VERSION 5.8 ;
BUSBITCHARS "[]" ;
DIVIDERCHAR "/" ;
UNITS
    DATABASE MICRONS 1000 ;
END UNITS

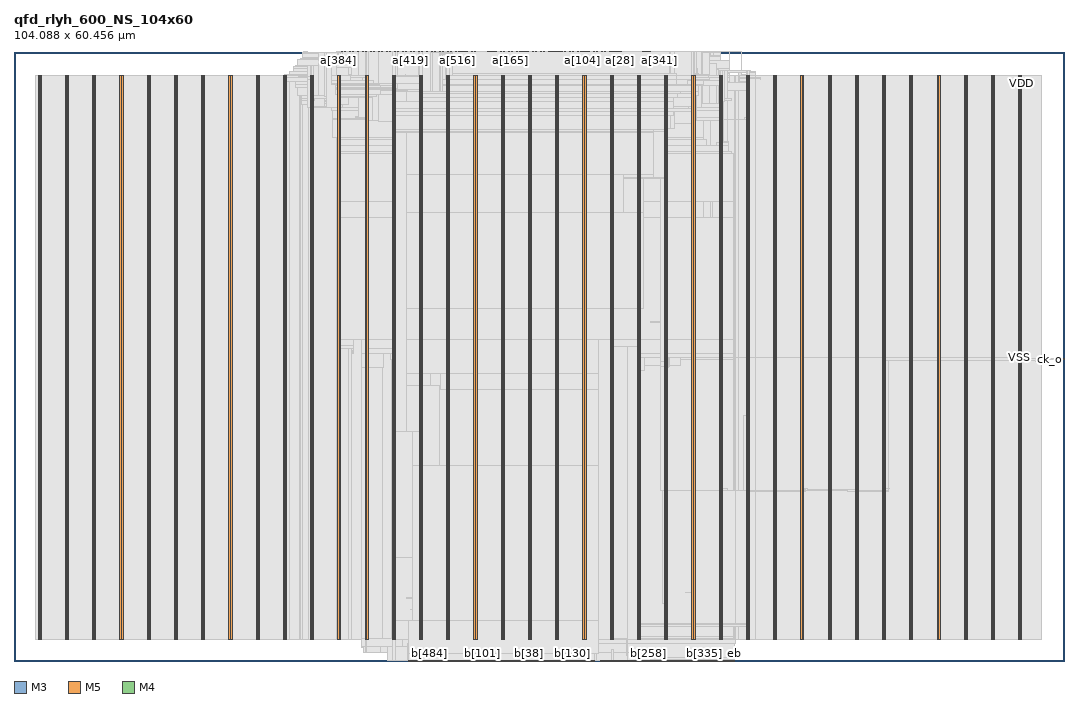
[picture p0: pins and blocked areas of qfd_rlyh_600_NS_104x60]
MACRO qfd_rlyh_600_NS_104x60
  FOREIGN qfd_rlyh_600_NS_104x60 0 0 ;
  CLASS BLOCK ;
  SIZE 104.088 BY 60.456 ;
  PIN a[0]
    DIRECTION INPUT ;
    USE SIGNAL ;
    PORT
      LAYER M3 ;
        RECT  58.068 60.419 58.086 60.456 ;
    END
  END a[0]
  PIN a[100]
    DIRECTION INPUT ;
    USE SIGNAL ;
    PORT
      LAYER M3 ;
        RECT  56.052 60.419 56.07 60.456 ;
    END
  END a[100]
  PIN a[101]
    DIRECTION INPUT ;
    USE SIGNAL ;
    PORT
      LAYER M3 ;
        RECT  56.124 60.419 56.142 60.456 ;
    END
  END a[101]
  PIN a[102]
    DIRECTION INPUT ;
    USE SIGNAL ;
    PORT
      LAYER M3 ;
        RECT  56.196 60.419 56.214 60.456 ;
    END
  END a[102]
  PIN a[103]
    DIRECTION INPUT ;
    USE SIGNAL ;
    PORT
      LAYER M3 ;
        RECT  56.268 60.419 56.286 60.456 ;
    END
  END a[103]
  PIN a[104]
    DIRECTION INPUT ;
    USE SIGNAL ;
    PORT
      LAYER M3 ;
        RECT  56.34 60.419 56.358 60.456 ;
    END
  END a[104]
  PIN a[105]
    DIRECTION INPUT ;
    USE SIGNAL ;
    PORT
      LAYER M3 ;
        RECT  56.412 60.419 56.43 60.456 ;
    END
  END a[105]
  PIN a[106]
    DIRECTION INPUT ;
    USE SIGNAL ;
    PORT
      LAYER M3 ;
        RECT  56.484 60.419 56.502 60.456 ;
    END
  END a[106]
  PIN a[107]
    DIRECTION INPUT ;
    USE SIGNAL ;
    PORT
      LAYER M3 ;
        RECT  56.556 60.419 56.574 60.456 ;
    END
  END a[107]
  PIN a[108]
    DIRECTION INPUT ;
    USE SIGNAL ;
    PORT
      LAYER M3 ;
        RECT  56.628 60.419 56.646 60.456 ;
    END
  END a[108]
  PIN a[109]
    DIRECTION INPUT ;
    USE SIGNAL ;
    PORT
      LAYER M3 ;
        RECT  56.7 60.419 56.718 60.456 ;
    END
  END a[109]
  PIN a[10]
    DIRECTION INPUT ;
    USE SIGNAL ;
    PORT
      LAYER M3 ;
        RECT  58.788 60.419 58.806 60.456 ;
    END
  END a[10]
  PIN a[110]
    DIRECTION INPUT ;
    USE SIGNAL ;
    PORT
      LAYER M3 ;
        RECT  56.772 60.419 56.79 60.456 ;
    END
  END a[110]
  PIN a[111]
    DIRECTION INPUT ;
    USE SIGNAL ;
    PORT
      LAYER M3 ;
        RECT  56.844 60.419 56.862 60.456 ;
    END
  END a[111]
  PIN a[112]
    DIRECTION INPUT ;
    USE SIGNAL ;
    PORT
      LAYER M3 ;
        RECT  56.916 60.419 56.934 60.456 ;
    END
  END a[112]
  PIN a[113]
    DIRECTION INPUT ;
    USE SIGNAL ;
    PORT
      LAYER M3 ;
        RECT  56.988 60.419 57.006 60.456 ;
    END
  END a[113]
  PIN a[114]
    DIRECTION INPUT ;
    USE SIGNAL ;
    PORT
      LAYER M3 ;
        RECT  57.06 60.419 57.078 60.456 ;
    END
  END a[114]
  PIN a[115]
    DIRECTION INPUT ;
    USE SIGNAL ;
    PORT
      LAYER M3 ;
        RECT  57.132 60.419 57.15 60.456 ;
    END
  END a[115]
  PIN a[116]
    DIRECTION INPUT ;
    USE SIGNAL ;
    PORT
      LAYER M3 ;
        RECT  57.204 60.419 57.222 60.456 ;
    END
  END a[116]
  PIN a[117]
    DIRECTION INPUT ;
    USE SIGNAL ;
    PORT
      LAYER M3 ;
        RECT  57.276 60.419 57.294 60.456 ;
    END
  END a[117]
  PIN a[118]
    DIRECTION INPUT ;
    USE SIGNAL ;
    PORT
      LAYER M3 ;
        RECT  57.348 60.419 57.366 60.456 ;
    END
  END a[118]
  PIN a[119]
    DIRECTION INPUT ;
    USE SIGNAL ;
    PORT
      LAYER M3 ;
        RECT  57.42 60.419 57.438 60.456 ;
    END
  END a[119]
  PIN a[11]
    DIRECTION INPUT ;
    USE SIGNAL ;
    PORT
      LAYER M3 ;
        RECT  58.86 60.419 58.878 60.456 ;
    END
  END a[11]
  PIN a[120]
    DIRECTION INPUT ;
    USE SIGNAL ;
    PORT
      LAYER M3 ;
        RECT  57.492 60.419 57.51 60.456 ;
    END
  END a[120]
  PIN a[121]
    DIRECTION INPUT ;
    USE SIGNAL ;
    PORT
      LAYER M3 ;
        RECT  57.564 60.419 57.582 60.456 ;
    END
  END a[121]
  PIN a[122]
    DIRECTION INPUT ;
    USE SIGNAL ;
    PORT
      LAYER M3 ;
        RECT  57.636 60.419 57.654 60.456 ;
    END
  END a[122]
  PIN a[123]
    DIRECTION INPUT ;
    USE SIGNAL ;
    PORT
      LAYER M3 ;
        RECT  57.708 60.419 57.726 60.456 ;
    END
  END a[123]
  PIN a[124]
    DIRECTION INPUT ;
    USE SIGNAL ;
    PORT
      LAYER M3 ;
        RECT  57.78 60.419 57.798 60.456 ;
    END
  END a[124]
  PIN a[125]
    DIRECTION INPUT ;
    USE SIGNAL ;
    PORT
      LAYER M3 ;
        RECT  57.852 60.419 57.87 60.456 ;
    END
  END a[125]
  PIN a[126]
    DIRECTION INPUT ;
    USE SIGNAL ;
    PORT
      LAYER M3 ;
        RECT  57.924 60.419 57.942 60.456 ;
    END
  END a[126]
  PIN a[127]
    DIRECTION INPUT ;
    USE SIGNAL ;
    PORT
      LAYER M3 ;
        RECT  57.996 60.419 58.014 60.456 ;
    END
  END a[127]
  PIN a[128]
    DIRECTION INPUT ;
    USE SIGNAL ;
    PORT
      LAYER M5 ;
        RECT  49.68 60.372 49.704 60.456 ;
    END
  END a[128]
  PIN a[129]
    DIRECTION INPUT ;
    USE SIGNAL ;
    PORT
      LAYER M5 ;
        RECT  49.776 60.372 49.8 60.456 ;
    END
  END a[129]
  PIN a[12]
    DIRECTION INPUT ;
    USE SIGNAL ;
    PORT
      LAYER M3 ;
        RECT  58.932 60.419 58.95 60.456 ;
    END
  END a[12]
  PIN a[130]
    DIRECTION INPUT ;
    USE SIGNAL ;
    PORT
      LAYER M5 ;
        RECT  49.872 60.372 49.896 60.456 ;
    END
  END a[130]
  PIN a[131]
    DIRECTION INPUT ;
    USE SIGNAL ;
    PORT
      LAYER M5 ;
        RECT  49.968 60.372 49.992 60.456 ;
    END
  END a[131]
  PIN a[132]
    DIRECTION INPUT ;
    USE SIGNAL ;
    PORT
      LAYER M5 ;
        RECT  50.064 60.372 50.088 60.456 ;
    END
  END a[132]
  PIN a[133]
    DIRECTION INPUT ;
    USE SIGNAL ;
    PORT
      LAYER M5 ;
        RECT  50.16 60.372 50.184 60.456 ;
    END
  END a[133]
  PIN a[134]
    DIRECTION INPUT ;
    USE SIGNAL ;
    PORT
      LAYER M5 ;
        RECT  50.256 60.372 50.28 60.456 ;
    END
  END a[134]
  PIN a[135]
    DIRECTION INPUT ;
    USE SIGNAL ;
    PORT
      LAYER M5 ;
        RECT  50.352 60.372 50.376 60.456 ;
    END
  END a[135]
  PIN a[136]
    DIRECTION INPUT ;
    USE SIGNAL ;
    PORT
      LAYER M5 ;
        RECT  50.448 60.372 50.472 60.456 ;
    END
  END a[136]
  PIN a[137]
    DIRECTION INPUT ;
    USE SIGNAL ;
    PORT
      LAYER M5 ;
        RECT  50.544 60.372 50.568 60.456 ;
    END
  END a[137]
  PIN a[138]
    DIRECTION INPUT ;
    USE SIGNAL ;
    PORT
      LAYER M5 ;
        RECT  50.64 60.372 50.664 60.456 ;
    END
  END a[138]
  PIN a[139]
    DIRECTION INPUT ;
    USE SIGNAL ;
    PORT
      LAYER M5 ;
        RECT  50.736 60.372 50.76 60.456 ;
    END
  END a[139]
  PIN a[13]
    DIRECTION INPUT ;
    USE SIGNAL ;
    PORT
      LAYER M3 ;
        RECT  59.004 60.419 59.022 60.456 ;
    END
  END a[13]
  PIN a[140]
    DIRECTION INPUT ;
    USE SIGNAL ;
    PORT
      LAYER M5 ;
        RECT  50.832 60.372 50.856 60.456 ;
    END
  END a[140]
  PIN a[141]
    DIRECTION INPUT ;
    USE SIGNAL ;
    PORT
      LAYER M5 ;
        RECT  50.928 60.372 50.952 60.456 ;
    END
  END a[141]
  PIN a[142]
    DIRECTION INPUT ;
    USE SIGNAL ;
    PORT
      LAYER M5 ;
        RECT  51.024 60.372 51.048 60.456 ;
    END
  END a[142]
  PIN a[143]
    DIRECTION INPUT ;
    USE SIGNAL ;
    PORT
      LAYER M5 ;
        RECT  51.12 60.372 51.144 60.456 ;
    END
  END a[143]
  PIN a[144]
    DIRECTION INPUT ;
    USE SIGNAL ;
    PORT
      LAYER M5 ;
        RECT  51.216 60.372 51.24 60.456 ;
    END
  END a[144]
  PIN a[145]
    DIRECTION INPUT ;
    USE SIGNAL ;
    PORT
      LAYER M5 ;
        RECT  51.312 60.372 51.336 60.456 ;
    END
  END a[145]
  PIN a[146]
    DIRECTION INPUT ;
    USE SIGNAL ;
    PORT
      LAYER M5 ;
        RECT  51.408 60.372 51.432 60.456 ;
    END
  END a[146]
  PIN a[147]
    DIRECTION INPUT ;
    USE SIGNAL ;
    PORT
      LAYER M5 ;
        RECT  51.504 60.372 51.528 60.456 ;
    END
  END a[147]
  PIN a[148]
    DIRECTION INPUT ;
    USE SIGNAL ;
    PORT
      LAYER M5 ;
        RECT  51.6 60.372 51.624 60.456 ;
    END
  END a[148]
  PIN a[149]
    DIRECTION INPUT ;
    USE SIGNAL ;
    PORT
      LAYER M5 ;
        RECT  51.696 60.372 51.72 60.456 ;
    END
  END a[149]
  PIN a[14]
    DIRECTION INPUT ;
    USE SIGNAL ;
    PORT
      LAYER M3 ;
        RECT  59.076 60.419 59.094 60.456 ;
    END
  END a[14]
  PIN a[150]
    DIRECTION INPUT ;
    USE SIGNAL ;
    PORT
      LAYER M5 ;
        RECT  51.792 60.372 51.816 60.456 ;
    END
  END a[150]
  PIN a[151]
    DIRECTION INPUT ;
    USE SIGNAL ;
    PORT
      LAYER M5 ;
        RECT  51.888 60.372 51.912 60.456 ;
    END
  END a[151]
  PIN a[152]
    DIRECTION INPUT ;
    USE SIGNAL ;
    PORT
      LAYER M5 ;
        RECT  51.984 60.372 52.008 60.456 ;
    END
  END a[152]
  PIN a[153]
    DIRECTION INPUT ;
    USE SIGNAL ;
    PORT
      LAYER M5 ;
        RECT  52.08 60.372 52.104 60.456 ;
    END
  END a[153]
  PIN a[154]
    DIRECTION INPUT ;
    USE SIGNAL ;
    PORT
      LAYER M5 ;
        RECT  52.176 60.372 52.2 60.456 ;
    END
  END a[154]
  PIN a[155]
    DIRECTION INPUT ;
    USE SIGNAL ;
    PORT
      LAYER M5 ;
        RECT  52.272 60.372 52.296 60.456 ;
    END
  END a[155]
  PIN a[156]
    DIRECTION INPUT ;
    USE SIGNAL ;
    PORT
      LAYER M5 ;
        RECT  52.368 60.372 52.392 60.456 ;
    END
  END a[156]
  PIN a[157]
    DIRECTION INPUT ;
    USE SIGNAL ;
    PORT
      LAYER M5 ;
        RECT  52.464 60.372 52.488 60.456 ;
    END
  END a[157]
  PIN a[158]
    DIRECTION INPUT ;
    USE SIGNAL ;
    PORT
      LAYER M5 ;
        RECT  52.56 60.372 52.584 60.456 ;
    END
  END a[158]
  PIN a[159]
    DIRECTION INPUT ;
    USE SIGNAL ;
    PORT
      LAYER M5 ;
        RECT  52.656 60.372 52.68 60.456 ;
    END
  END a[159]
  PIN a[15]
    DIRECTION INPUT ;
    USE SIGNAL ;
    PORT
      LAYER M3 ;
        RECT  59.148 60.419 59.166 60.456 ;
    END
  END a[15]
  PIN a[160]
    DIRECTION INPUT ;
    USE SIGNAL ;
    PORT
      LAYER M3 ;
        RECT  48.852 60.419 48.87 60.456 ;
    END
  END a[160]
  PIN a[161]
    DIRECTION INPUT ;
    USE SIGNAL ;
    PORT
      LAYER M3 ;
        RECT  48.924 60.419 48.942 60.456 ;
    END
  END a[161]
  PIN a[162]
    DIRECTION INPUT ;
    USE SIGNAL ;
    PORT
      LAYER M3 ;
        RECT  48.996 60.419 49.014 60.456 ;
    END
  END a[162]
  PIN a[163]
    DIRECTION INPUT ;
    USE SIGNAL ;
    PORT
      LAYER M3 ;
        RECT  49.068 60.419 49.086 60.456 ;
    END
  END a[163]
  PIN a[164]
    DIRECTION INPUT ;
    USE SIGNAL ;
    PORT
      LAYER M3 ;
        RECT  49.14 60.419 49.158 60.456 ;
    END
  END a[164]
  PIN a[165]
    DIRECTION INPUT ;
    USE SIGNAL ;
    PORT
      LAYER M3 ;
        RECT  49.212 60.419 49.23 60.456 ;
    END
  END a[165]
  PIN a[166]
    DIRECTION INPUT ;
    USE SIGNAL ;
    PORT
      LAYER M3 ;
        RECT  49.284 60.419 49.302 60.456 ;
    END
  END a[166]
  PIN a[167]
    DIRECTION INPUT ;
    USE SIGNAL ;
    PORT
      LAYER M3 ;
        RECT  49.356 60.419 49.374 60.456 ;
    END
  END a[167]
  PIN a[168]
    DIRECTION INPUT ;
    USE SIGNAL ;
    PORT
      LAYER M3 ;
        RECT  49.428 60.419 49.446 60.456 ;
    END
  END a[168]
  PIN a[169]
    DIRECTION INPUT ;
    USE SIGNAL ;
    PORT
      LAYER M3 ;
        RECT  49.5 60.419 49.518 60.456 ;
    END
  END a[169]
  PIN a[16]
    DIRECTION INPUT ;
    USE SIGNAL ;
    PORT
      LAYER M3 ;
        RECT  59.22 60.419 59.238 60.456 ;
    END
  END a[16]
  PIN a[170]
    DIRECTION INPUT ;
    USE SIGNAL ;
    PORT
      LAYER M3 ;
        RECT  49.572 60.419 49.59 60.456 ;
    END
  END a[170]
  PIN a[171]
    DIRECTION INPUT ;
    USE SIGNAL ;
    PORT
      LAYER M3 ;
        RECT  49.644 60.419 49.662 60.456 ;
    END
  END a[171]
  PIN a[172]
    DIRECTION INPUT ;
    USE SIGNAL ;
    PORT
      LAYER M3 ;
        RECT  49.716 60.419 49.734 60.456 ;
    END
  END a[172]
  PIN a[173]
    DIRECTION INPUT ;
    USE SIGNAL ;
    PORT
      LAYER M3 ;
        RECT  49.788 60.419 49.806 60.456 ;
    END
  END a[173]
  PIN a[174]
    DIRECTION INPUT ;
    USE SIGNAL ;
    PORT
      LAYER M3 ;
        RECT  49.86 60.419 49.878 60.456 ;
    END
  END a[174]
  PIN a[175]
    DIRECTION INPUT ;
    USE SIGNAL ;
    PORT
      LAYER M3 ;
        RECT  49.932 60.419 49.95 60.456 ;
    END
  END a[175]
  PIN a[176]
    DIRECTION INPUT ;
    USE SIGNAL ;
    PORT
      LAYER M3 ;
        RECT  50.004 60.419 50.022 60.456 ;
    END
  END a[176]
  PIN a[177]
    DIRECTION INPUT ;
    USE SIGNAL ;
    PORT
      LAYER M3 ;
        RECT  50.076 60.419 50.094 60.456 ;
    END
  END a[177]
  PIN a[178]
    DIRECTION INPUT ;
    USE SIGNAL ;
    PORT
      LAYER M3 ;
        RECT  50.148 60.419 50.166 60.456 ;
    END
  END a[178]
  PIN a[179]
    DIRECTION INPUT ;
    USE SIGNAL ;
    PORT
      LAYER M3 ;
        RECT  50.22 60.419 50.238 60.456 ;
    END
  END a[179]
  PIN a[17]
    DIRECTION INPUT ;
    USE SIGNAL ;
    PORT
      LAYER M3 ;
        RECT  59.292 60.419 59.31 60.456 ;
    END
  END a[17]
  PIN a[180]
    DIRECTION INPUT ;
    USE SIGNAL ;
    PORT
      LAYER M3 ;
        RECT  50.292 60.419 50.31 60.456 ;
    END
  END a[180]
  PIN a[181]
    DIRECTION INPUT ;
    USE SIGNAL ;
    PORT
      LAYER M3 ;
        RECT  50.364 60.419 50.382 60.456 ;
    END
  END a[181]
  PIN a[182]
    DIRECTION INPUT ;
    USE SIGNAL ;
    PORT
      LAYER M3 ;
        RECT  50.436 60.419 50.454 60.456 ;
    END
  END a[182]
  PIN a[183]
    DIRECTION INPUT ;
    USE SIGNAL ;
    PORT
      LAYER M3 ;
        RECT  50.508 60.419 50.526 60.456 ;
    END
  END a[183]
  PIN a[184]
    DIRECTION INPUT ;
    USE SIGNAL ;
    PORT
      LAYER M3 ;
        RECT  50.58 60.419 50.598 60.456 ;
    END
  END a[184]
  PIN a[185]
    DIRECTION INPUT ;
    USE SIGNAL ;
    PORT
      LAYER M3 ;
        RECT  50.652 60.419 50.67 60.456 ;
    END
  END a[185]
  PIN a[186]
    DIRECTION INPUT ;
    USE SIGNAL ;
    PORT
      LAYER M3 ;
        RECT  50.724 60.419 50.742 60.456 ;
    END
  END a[186]
  PIN a[187]
    DIRECTION INPUT ;
    USE SIGNAL ;
    PORT
      LAYER M3 ;
        RECT  50.796 60.419 50.814 60.456 ;
    END
  END a[187]
  PIN a[188]
    DIRECTION INPUT ;
    USE SIGNAL ;
    PORT
      LAYER M3 ;
        RECT  50.868 60.419 50.886 60.456 ;
    END
  END a[188]
  PIN a[189]
    DIRECTION INPUT ;
    USE SIGNAL ;
    PORT
      LAYER M3 ;
        RECT  50.94 60.419 50.958 60.456 ;
    END
  END a[189]
  PIN a[18]
    DIRECTION INPUT ;
    USE SIGNAL ;
    PORT
      LAYER M3 ;
        RECT  59.364 60.419 59.382 60.456 ;
    END
  END a[18]
  PIN a[190]
    DIRECTION INPUT ;
    USE SIGNAL ;
    PORT
      LAYER M3 ;
        RECT  51.012 60.419 51.03 60.456 ;
    END
  END a[190]
  PIN a[191]
    DIRECTION INPUT ;
    USE SIGNAL ;
    PORT
      LAYER M3 ;
        RECT  51.084 60.419 51.102 60.456 ;
    END
  END a[191]
  PIN a[192]
    DIRECTION INPUT ;
    USE SIGNAL ;
    PORT
      LAYER M3 ;
        RECT  53.46 60.419 53.478 60.456 ;
    END
  END a[192]
  PIN a[193]
    DIRECTION INPUT ;
    USE SIGNAL ;
    PORT
      LAYER M3 ;
        RECT  53.532 60.419 53.55 60.456 ;
    END
  END a[193]
  PIN a[194]
    DIRECTION INPUT ;
    USE SIGNAL ;
    PORT
      LAYER M3 ;
        RECT  53.604 60.419 53.622 60.456 ;
    END
  END a[194]
  PIN a[195]
    DIRECTION INPUT ;
    USE SIGNAL ;
    PORT
      LAYER M3 ;
        RECT  53.676 60.419 53.694 60.456 ;
    END
  END a[195]
  PIN a[196]
    DIRECTION INPUT ;
    USE SIGNAL ;
    PORT
      LAYER M3 ;
        RECT  53.748 60.419 53.766 60.456 ;
    END
  END a[196]
  PIN a[197]
    DIRECTION INPUT ;
    USE SIGNAL ;
    PORT
      LAYER M3 ;
        RECT  53.82 60.419 53.838 60.456 ;
    END
  END a[197]
  PIN a[198]
    DIRECTION INPUT ;
    USE SIGNAL ;
    PORT
      LAYER M3 ;
        RECT  53.892 60.419 53.91 60.456 ;
    END
  END a[198]
  PIN a[199]
    DIRECTION INPUT ;
    USE SIGNAL ;
    PORT
      LAYER M3 ;
        RECT  53.964 60.419 53.982 60.456 ;
    END
  END a[199]
  PIN a[19]
    DIRECTION INPUT ;
    USE SIGNAL ;
    PORT
      LAYER M3 ;
        RECT  59.436 60.419 59.454 60.456 ;
    END
  END a[19]
  PIN a[1]
    DIRECTION INPUT ;
    USE SIGNAL ;
    PORT
      LAYER M3 ;
        RECT  58.14 60.419 58.158 60.456 ;
    END
  END a[1]
  PIN a[200]
    DIRECTION INPUT ;
    USE SIGNAL ;
    PORT
      LAYER M3 ;
        RECT  54.036 60.419 54.054 60.456 ;
    END
  END a[200]
  PIN a[201]
    DIRECTION INPUT ;
    USE SIGNAL ;
    PORT
      LAYER M3 ;
        RECT  54.108 60.419 54.126 60.456 ;
    END
  END a[201]
  PIN a[202]
    DIRECTION INPUT ;
    USE SIGNAL ;
    PORT
      LAYER M3 ;
        RECT  54.18 60.419 54.198 60.456 ;
    END
  END a[202]
  PIN a[203]
    DIRECTION INPUT ;
    USE SIGNAL ;
    PORT
      LAYER M3 ;
        RECT  54.252 60.419 54.27 60.456 ;
    END
  END a[203]
  PIN a[204]
    DIRECTION INPUT ;
    USE SIGNAL ;
    PORT
      LAYER M3 ;
        RECT  54.324 60.419 54.342 60.456 ;
    END
  END a[204]
  PIN a[205]
    DIRECTION INPUT ;
    USE SIGNAL ;
    PORT
      LAYER M3 ;
        RECT  54.396 60.419 54.414 60.456 ;
    END
  END a[205]
  PIN a[206]
    DIRECTION INPUT ;
    USE SIGNAL ;
    PORT
      LAYER M3 ;
        RECT  54.468 60.419 54.486 60.456 ;
    END
  END a[206]
  PIN a[207]
    DIRECTION INPUT ;
    USE SIGNAL ;
    PORT
      LAYER M3 ;
        RECT  54.54 60.419 54.558 60.456 ;
    END
  END a[207]
  PIN a[208]
    DIRECTION INPUT ;
    USE SIGNAL ;
    PORT
      LAYER M3 ;
        RECT  54.612 60.419 54.63 60.456 ;
    END
  END a[208]
  PIN a[209]
    DIRECTION INPUT ;
    USE SIGNAL ;
    PORT
      LAYER M3 ;
        RECT  54.684 60.419 54.702 60.456 ;
    END
  END a[209]
  PIN a[20]
    DIRECTION INPUT ;
    USE SIGNAL ;
    PORT
      LAYER M3 ;
        RECT  59.508 60.419 59.526 60.456 ;
    END
  END a[20]
  PIN a[210]
    DIRECTION INPUT ;
    USE SIGNAL ;
    PORT
      LAYER M3 ;
        RECT  54.756 60.419 54.774 60.456 ;
    END
  END a[210]
  PIN a[211]
    DIRECTION INPUT ;
    USE SIGNAL ;
    PORT
      LAYER M3 ;
        RECT  54.828 60.419 54.846 60.456 ;
    END
  END a[211]
  PIN a[212]
    DIRECTION INPUT ;
    USE SIGNAL ;
    PORT
      LAYER M3 ;
        RECT  54.9 60.419 54.918 60.456 ;
    END
  END a[212]
  PIN a[213]
    DIRECTION INPUT ;
    USE SIGNAL ;
    PORT
      LAYER M3 ;
        RECT  54.972 60.419 54.99 60.456 ;
    END
  END a[213]
  PIN a[214]
    DIRECTION INPUT ;
    USE SIGNAL ;
    PORT
      LAYER M3 ;
        RECT  55.044 60.419 55.062 60.456 ;
    END
  END a[214]
  PIN a[215]
    DIRECTION INPUT ;
    USE SIGNAL ;
    PORT
      LAYER M3 ;
        RECT  55.116 60.419 55.134 60.456 ;
    END
  END a[215]
  PIN a[216]
    DIRECTION INPUT ;
    USE SIGNAL ;
    PORT
      LAYER M3 ;
        RECT  55.188 60.419 55.206 60.456 ;
    END
  END a[216]
  PIN a[217]
    DIRECTION INPUT ;
    USE SIGNAL ;
    PORT
      LAYER M3 ;
        RECT  55.26 60.419 55.278 60.456 ;
    END
  END a[217]
  PIN a[218]
    DIRECTION INPUT ;
    USE SIGNAL ;
    PORT
      LAYER M3 ;
        RECT  55.332 60.419 55.35 60.456 ;
    END
  END a[218]
  PIN a[219]
    DIRECTION INPUT ;
    USE SIGNAL ;
    PORT
      LAYER M3 ;
        RECT  55.404 60.419 55.422 60.456 ;
    END
  END a[219]
  PIN a[21]
    DIRECTION INPUT ;
    USE SIGNAL ;
    PORT
      LAYER M3 ;
        RECT  59.58 60.419 59.598 60.456 ;
    END
  END a[21]
  PIN a[220]
    DIRECTION INPUT ;
    USE SIGNAL ;
    PORT
      LAYER M3 ;
        RECT  55.476 60.419 55.494 60.456 ;
    END
  END a[220]
  PIN a[221]
    DIRECTION INPUT ;
    USE SIGNAL ;
    PORT
      LAYER M3 ;
        RECT  55.548 60.419 55.566 60.456 ;
    END
  END a[221]
  PIN a[222]
    DIRECTION INPUT ;
    USE SIGNAL ;
    PORT
      LAYER M3 ;
        RECT  55.62 60.419 55.638 60.456 ;
    END
  END a[222]
  PIN a[223]
    DIRECTION INPUT ;
    USE SIGNAL ;
    PORT
      LAYER M3 ;
        RECT  55.692 60.419 55.71 60.456 ;
    END
  END a[223]
  PIN a[224]
    DIRECTION INPUT ;
    USE SIGNAL ;
    PORT
      LAYER M3 ;
        RECT  51.156 60.419 51.174 60.456 ;
    END
  END a[224]
  PIN a[225]
    DIRECTION INPUT ;
    USE SIGNAL ;
    PORT
      LAYER M3 ;
        RECT  51.228 60.419 51.246 60.456 ;
    END
  END a[225]
  PIN a[226]
    DIRECTION INPUT ;
    USE SIGNAL ;
    PORT
      LAYER M3 ;
        RECT  51.3 60.419 51.318 60.456 ;
    END
  END a[226]
  PIN a[227]
    DIRECTION INPUT ;
    USE SIGNAL ;
    PORT
      LAYER M3 ;
        RECT  51.372 60.419 51.39 60.456 ;
    END
  END a[227]
  PIN a[228]
    DIRECTION INPUT ;
    USE SIGNAL ;
    PORT
      LAYER M3 ;
        RECT  51.444 60.419 51.462 60.456 ;
    END
  END a[228]
  PIN a[229]
    DIRECTION INPUT ;
    USE SIGNAL ;
    PORT
      LAYER M3 ;
        RECT  51.516 60.419 51.534 60.456 ;
    END
  END a[229]
  PIN a[22]
    DIRECTION INPUT ;
    USE SIGNAL ;
    PORT
      LAYER M3 ;
        RECT  59.652 60.419 59.67 60.456 ;
    END
  END a[22]
  PIN a[230]
    DIRECTION INPUT ;
    USE SIGNAL ;
    PORT
      LAYER M3 ;
        RECT  51.588 60.419 51.606 60.456 ;
    END
  END a[230]
  PIN a[231]
    DIRECTION INPUT ;
    USE SIGNAL ;
    PORT
      LAYER M3 ;
        RECT  51.66 60.419 51.678 60.456 ;
    END
  END a[231]
  PIN a[232]
    DIRECTION INPUT ;
    USE SIGNAL ;
    PORT
      LAYER M3 ;
        RECT  51.732 60.419 51.75 60.456 ;
    END
  END a[232]
  PIN a[233]
    DIRECTION INPUT ;
    USE SIGNAL ;
    PORT
      LAYER M3 ;
        RECT  51.804 60.419 51.822 60.456 ;
    END
  END a[233]
  PIN a[234]
    DIRECTION INPUT ;
    USE SIGNAL ;
    PORT
      LAYER M3 ;
        RECT  51.876 60.419 51.894 60.456 ;
    END
  END a[234]
  PIN a[235]
    DIRECTION INPUT ;
    USE SIGNAL ;
    PORT
      LAYER M3 ;
        RECT  51.948 60.419 51.966 60.456 ;
    END
  END a[235]
  PIN a[236]
    DIRECTION INPUT ;
    USE SIGNAL ;
    PORT
      LAYER M3 ;
        RECT  52.02 60.419 52.038 60.456 ;
    END
  END a[236]
  PIN a[237]
    DIRECTION INPUT ;
    USE SIGNAL ;
    PORT
      LAYER M3 ;
        RECT  52.092 60.419 52.11 60.456 ;
    END
  END a[237]
  PIN a[238]
    DIRECTION INPUT ;
    USE SIGNAL ;
    PORT
      LAYER M3 ;
        RECT  52.164 60.419 52.182 60.456 ;
    END
  END a[238]
  PIN a[239]
    DIRECTION INPUT ;
    USE SIGNAL ;
    PORT
      LAYER M3 ;
        RECT  52.236 60.419 52.254 60.456 ;
    END
  END a[239]
  PIN a[23]
    DIRECTION INPUT ;
    USE SIGNAL ;
    PORT
      LAYER M3 ;
        RECT  59.724 60.419 59.742 60.456 ;
    END
  END a[23]
  PIN a[240]
    DIRECTION INPUT ;
    USE SIGNAL ;
    PORT
      LAYER M3 ;
        RECT  52.308 60.419 52.326 60.456 ;
    END
  END a[240]
  PIN a[241]
    DIRECTION INPUT ;
    USE SIGNAL ;
    PORT
      LAYER M3 ;
        RECT  52.38 60.419 52.398 60.456 ;
    END
  END a[241]
  PIN a[242]
    DIRECTION INPUT ;
    USE SIGNAL ;
    PORT
      LAYER M3 ;
        RECT  52.452 60.419 52.47 60.456 ;
    END
  END a[242]
  PIN a[243]
    DIRECTION INPUT ;
    USE SIGNAL ;
    PORT
      LAYER M3 ;
        RECT  52.524 60.419 52.542 60.456 ;
    END
  END a[243]
  PIN a[244]
    DIRECTION INPUT ;
    USE SIGNAL ;
    PORT
      LAYER M3 ;
        RECT  52.596 60.419 52.614 60.456 ;
    END
  END a[244]
  PIN a[245]
    DIRECTION INPUT ;
    USE SIGNAL ;
    PORT
      LAYER M3 ;
        RECT  52.668 60.419 52.686 60.456 ;
    END
  END a[245]
  PIN a[246]
    DIRECTION INPUT ;
    USE SIGNAL ;
    PORT
      LAYER M3 ;
        RECT  52.74 60.419 52.758 60.456 ;
    END
  END a[246]
  PIN a[247]
    DIRECTION INPUT ;
    USE SIGNAL ;
    PORT
      LAYER M3 ;
        RECT  52.812 60.419 52.83 60.456 ;
    END
  END a[247]
  PIN a[248]
    DIRECTION INPUT ;
    USE SIGNAL ;
    PORT
      LAYER M3 ;
        RECT  52.884 60.419 52.902 60.456 ;
    END
  END a[248]
  PIN a[249]
    DIRECTION INPUT ;
    USE SIGNAL ;
    PORT
      LAYER M3 ;
        RECT  52.956 60.419 52.974 60.456 ;
    END
  END a[249]
  PIN a[24]
    DIRECTION INPUT ;
    USE SIGNAL ;
    PORT
      LAYER M3 ;
        RECT  59.796 60.419 59.814 60.456 ;
    END
  END a[24]
  PIN a[250]
    DIRECTION INPUT ;
    USE SIGNAL ;
    PORT
      LAYER M3 ;
        RECT  53.028 60.419 53.046 60.456 ;
    END
  END a[250]
  PIN a[251]
    DIRECTION INPUT ;
    USE SIGNAL ;
    PORT
      LAYER M3 ;
        RECT  53.1 60.419 53.118 60.456 ;
    END
  END a[251]
  PIN a[252]
    DIRECTION INPUT ;
    USE SIGNAL ;
    PORT
      LAYER M3 ;
        RECT  53.172 60.419 53.19 60.456 ;
    END
  END a[252]
  PIN a[253]
    DIRECTION INPUT ;
    USE SIGNAL ;
    PORT
      LAYER M3 ;
        RECT  53.244 60.419 53.262 60.456 ;
    END
  END a[253]
  PIN a[254]
    DIRECTION INPUT ;
    USE SIGNAL ;
    PORT
      LAYER M3 ;
        RECT  53.316 60.419 53.334 60.456 ;
    END
  END a[254]
  PIN a[255]
    DIRECTION INPUT ;
    USE SIGNAL ;
    PORT
      LAYER M3 ;
        RECT  53.388 60.419 53.406 60.456 ;
    END
  END a[255]
  PIN a[256]
    DIRECTION INPUT ;
    USE SIGNAL ;
    PORT
      LAYER M5 ;
        RECT  58.896 60.372 58.92 60.456 ;
    END
  END a[256]
  PIN a[257]
    DIRECTION INPUT ;
    USE SIGNAL ;
    PORT
      LAYER M5 ;
        RECT  58.992 60.372 59.016 60.456 ;
    END
  END a[257]
  PIN a[258]
    DIRECTION INPUT ;
    USE SIGNAL ;
    PORT
      LAYER M5 ;
        RECT  59.088 60.372 59.112 60.456 ;
    END
  END a[258]
  PIN a[259]
    DIRECTION INPUT ;
    USE SIGNAL ;
    PORT
      LAYER M5 ;
        RECT  59.184 60.372 59.208 60.456 ;
    END
  END a[259]
  PIN a[25]
    DIRECTION INPUT ;
    USE SIGNAL ;
    PORT
      LAYER M3 ;
        RECT  59.868 60.419 59.886 60.456 ;
    END
  END a[25]
  PIN a[260]
    DIRECTION INPUT ;
    USE SIGNAL ;
    PORT
      LAYER M5 ;
        RECT  59.28 60.372 59.304 60.456 ;
    END
  END a[260]
  PIN a[261]
    DIRECTION INPUT ;
    USE SIGNAL ;
    PORT
      LAYER M5 ;
        RECT  59.376 60.372 59.4 60.456 ;
    END
  END a[261]
  PIN a[262]
    DIRECTION INPUT ;
    USE SIGNAL ;
    PORT
      LAYER M5 ;
        RECT  59.472 60.372 59.496 60.456 ;
    END
  END a[262]
  PIN a[263]
    DIRECTION INPUT ;
    USE SIGNAL ;
    PORT
      LAYER M5 ;
        RECT  59.568 60.372 59.592 60.456 ;
    END
  END a[263]
  PIN a[264]
    DIRECTION INPUT ;
    USE SIGNAL ;
    PORT
      LAYER M5 ;
        RECT  59.664 60.372 59.688 60.456 ;
    END
  END a[264]
  PIN a[265]
    DIRECTION INPUT ;
    USE SIGNAL ;
    PORT
      LAYER M5 ;
        RECT  59.76 60.372 59.784 60.456 ;
    END
  END a[265]
  PIN a[266]
    DIRECTION INPUT ;
    USE SIGNAL ;
    PORT
      LAYER M5 ;
        RECT  59.856 60.372 59.88 60.456 ;
    END
  END a[266]
  PIN a[267]
    DIRECTION INPUT ;
    USE SIGNAL ;
    PORT
      LAYER M5 ;
        RECT  59.952 60.372 59.976 60.456 ;
    END
  END a[267]
  PIN a[268]
    DIRECTION INPUT ;
    USE SIGNAL ;
    PORT
      LAYER M5 ;
        RECT  60.048 60.372 60.072 60.456 ;
    END
  END a[268]
  PIN a[269]
    DIRECTION INPUT ;
    USE SIGNAL ;
    PORT
      LAYER M5 ;
        RECT  60.144 60.372 60.168 60.456 ;
    END
  END a[269]
  PIN a[26]
    DIRECTION INPUT ;
    USE SIGNAL ;
    PORT
      LAYER M3 ;
        RECT  59.94 60.419 59.958 60.456 ;
    END
  END a[26]
  PIN a[270]
    DIRECTION INPUT ;
    USE SIGNAL ;
    PORT
      LAYER M5 ;
        RECT  60.24 60.372 60.264 60.456 ;
    END
  END a[270]
  PIN a[271]
    DIRECTION INPUT ;
    USE SIGNAL ;
    PORT
      LAYER M5 ;
        RECT  60.336 60.372 60.36 60.456 ;
    END
  END a[271]
  PIN a[272]
    DIRECTION INPUT ;
    USE SIGNAL ;
    PORT
      LAYER M5 ;
        RECT  60.432 60.372 60.456 60.456 ;
    END
  END a[272]
  PIN a[273]
    DIRECTION INPUT ;
    USE SIGNAL ;
    PORT
      LAYER M5 ;
        RECT  60.528 60.372 60.552 60.456 ;
    END
  END a[273]
  PIN a[274]
    DIRECTION INPUT ;
    USE SIGNAL ;
    PORT
      LAYER M5 ;
        RECT  60.624 60.372 60.648 60.456 ;
    END
  END a[274]
  PIN a[275]
    DIRECTION INPUT ;
    USE SIGNAL ;
    PORT
      LAYER M5 ;
        RECT  60.72 60.372 60.744 60.456 ;
    END
  END a[275]
  PIN a[276]
    DIRECTION INPUT ;
    USE SIGNAL ;
    PORT
      LAYER M5 ;
        RECT  60.816 60.372 60.84 60.456 ;
    END
  END a[276]
  PIN a[277]
    DIRECTION INPUT ;
    USE SIGNAL ;
    PORT
      LAYER M5 ;
        RECT  60.912 60.372 60.936 60.456 ;
    END
  END a[277]
  PIN a[278]
    DIRECTION INPUT ;
    USE SIGNAL ;
    PORT
      LAYER M5 ;
        RECT  61.008 60.372 61.032 60.456 ;
    END
  END a[278]
  PIN a[279]
    DIRECTION INPUT ;
    USE SIGNAL ;
    PORT
      LAYER M5 ;
        RECT  61.104 60.372 61.128 60.456 ;
    END
  END a[279]
  PIN a[27]
    DIRECTION INPUT ;
    USE SIGNAL ;
    PORT
      LAYER M3 ;
        RECT  60.012 60.419 60.03 60.456 ;
    END
  END a[27]
  PIN a[280]
    DIRECTION INPUT ;
    USE SIGNAL ;
    PORT
      LAYER M5 ;
        RECT  61.2 60.372 61.224 60.456 ;
    END
  END a[280]
  PIN a[281]
    DIRECTION INPUT ;
    USE SIGNAL ;
    PORT
      LAYER M5 ;
        RECT  61.296 60.372 61.32 60.456 ;
    END
  END a[281]
  PIN a[282]
    DIRECTION INPUT ;
    USE SIGNAL ;
    PORT
      LAYER M5 ;
        RECT  61.392 60.372 61.416 60.456 ;
    END
  END a[282]
  PIN a[283]
    DIRECTION INPUT ;
    USE SIGNAL ;
    PORT
      LAYER M5 ;
        RECT  61.488 60.372 61.512 60.456 ;
    END
  END a[283]
  PIN a[284]
    DIRECTION INPUT ;
    USE SIGNAL ;
    PORT
      LAYER M5 ;
        RECT  61.584 60.372 61.608 60.456 ;
    END
  END a[284]
  PIN a[285]
    DIRECTION INPUT ;
    USE SIGNAL ;
    PORT
      LAYER M5 ;
        RECT  61.68 60.372 61.704 60.456 ;
    END
  END a[285]
  PIN a[286]
    DIRECTION INPUT ;
    USE SIGNAL ;
    PORT
      LAYER M5 ;
        RECT  61.776 60.372 61.8 60.456 ;
    END
  END a[286]
  PIN a[287]
    DIRECTION INPUT ;
    USE SIGNAL ;
    PORT
      LAYER M5 ;
        RECT  61.872 60.372 61.896 60.456 ;
    END
  END a[287]
  PIN a[288]
    DIRECTION INPUT ;
    USE SIGNAL ;
    PORT
      LAYER M5 ;
        RECT  55.824 60.372 55.848 60.456 ;
    END
  END a[288]
  PIN a[289]
    DIRECTION INPUT ;
    USE SIGNAL ;
    PORT
      LAYER M5 ;
        RECT  55.92 60.372 55.944 60.456 ;
    END
  END a[289]
  PIN a[28]
    DIRECTION INPUT ;
    USE SIGNAL ;
    PORT
      LAYER M3 ;
        RECT  60.084 60.419 60.102 60.456 ;
    END
  END a[28]
  PIN a[290]
    DIRECTION INPUT ;
    USE SIGNAL ;
    PORT
      LAYER M5 ;
        RECT  56.016 60.372 56.04 60.456 ;
    END
  END a[290]
  PIN a[291]
    DIRECTION INPUT ;
    USE SIGNAL ;
    PORT
      LAYER M5 ;
        RECT  56.112 60.372 56.136 60.456 ;
    END
  END a[291]
  PIN a[292]
    DIRECTION INPUT ;
    USE SIGNAL ;
    PORT
      LAYER M5 ;
        RECT  56.208 60.372 56.232 60.456 ;
    END
  END a[292]
  PIN a[293]
    DIRECTION INPUT ;
    USE SIGNAL ;
    PORT
      LAYER M5 ;
        RECT  56.304 60.372 56.328 60.456 ;
    END
  END a[293]
  PIN a[294]
    DIRECTION INPUT ;
    USE SIGNAL ;
    PORT
      LAYER M5 ;
        RECT  56.4 60.372 56.424 60.456 ;
    END
  END a[294]
  PIN a[295]
    DIRECTION INPUT ;
    USE SIGNAL ;
    PORT
      LAYER M5 ;
        RECT  56.496 60.372 56.52 60.456 ;
    END
  END a[295]
  PIN a[296]
    DIRECTION INPUT ;
    USE SIGNAL ;
    PORT
      LAYER M5 ;
        RECT  56.592 60.372 56.616 60.456 ;
    END
  END a[296]
  PIN a[297]
    DIRECTION INPUT ;
    USE SIGNAL ;
    PORT
      LAYER M5 ;
        RECT  56.688 60.372 56.712 60.456 ;
    END
  END a[297]
  PIN a[298]
    DIRECTION INPUT ;
    USE SIGNAL ;
    PORT
      LAYER M5 ;
        RECT  56.784 60.372 56.808 60.456 ;
    END
  END a[298]
  PIN a[299]
    DIRECTION INPUT ;
    USE SIGNAL ;
    PORT
      LAYER M5 ;
        RECT  56.88 60.372 56.904 60.456 ;
    END
  END a[299]
  PIN a[29]
    DIRECTION INPUT ;
    USE SIGNAL ;
    PORT
      LAYER M3 ;
        RECT  60.156 60.419 60.174 60.456 ;
    END
  END a[29]
  PIN a[2]
    DIRECTION INPUT ;
    USE SIGNAL ;
    PORT
      LAYER M3 ;
        RECT  58.212 60.419 58.23 60.456 ;
    END
  END a[2]
  PIN a[300]
    DIRECTION INPUT ;
    USE SIGNAL ;
    PORT
      LAYER M5 ;
        RECT  56.976 60.372 57 60.456 ;
    END
  END a[300]
  PIN a[301]
    DIRECTION INPUT ;
    USE SIGNAL ;
    PORT
      LAYER M5 ;
        RECT  57.072 60.372 57.096 60.456 ;
    END
  END a[301]
  PIN a[302]
    DIRECTION INPUT ;
    USE SIGNAL ;
    PORT
      LAYER M5 ;
        RECT  57.168 60.372 57.192 60.456 ;
    END
  END a[302]
  PIN a[303]
    DIRECTION INPUT ;
    USE SIGNAL ;
    PORT
      LAYER M5 ;
        RECT  57.264 60.372 57.288 60.456 ;
    END
  END a[303]
  PIN a[304]
    DIRECTION INPUT ;
    USE SIGNAL ;
    PORT
      LAYER M5 ;
        RECT  57.36 60.372 57.384 60.456 ;
    END
  END a[304]
  PIN a[305]
    DIRECTION INPUT ;
    USE SIGNAL ;
    PORT
      LAYER M5 ;
        RECT  57.456 60.372 57.48 60.456 ;
    END
  END a[305]
  PIN a[306]
    DIRECTION INPUT ;
    USE SIGNAL ;
    PORT
      LAYER M5 ;
        RECT  57.552 60.372 57.576 60.456 ;
    END
  END a[306]
  PIN a[307]
    DIRECTION INPUT ;
    USE SIGNAL ;
    PORT
      LAYER M5 ;
        RECT  57.648 60.372 57.672 60.456 ;
    END
  END a[307]
  PIN a[308]
    DIRECTION INPUT ;
    USE SIGNAL ;
    PORT
      LAYER M5 ;
        RECT  57.744 60.372 57.768 60.456 ;
    END
  END a[308]
  PIN a[309]
    DIRECTION INPUT ;
    USE SIGNAL ;
    PORT
      LAYER M5 ;
        RECT  57.84 60.372 57.864 60.456 ;
    END
  END a[309]
  PIN a[30]
    DIRECTION INPUT ;
    USE SIGNAL ;
    PORT
      LAYER M3 ;
        RECT  60.228 60.419 60.246 60.456 ;
    END
  END a[30]
  PIN a[310]
    DIRECTION INPUT ;
    USE SIGNAL ;
    PORT
      LAYER M5 ;
        RECT  57.936 60.372 57.96 60.456 ;
    END
  END a[310]
  PIN a[311]
    DIRECTION INPUT ;
    USE SIGNAL ;
    PORT
      LAYER M5 ;
        RECT  58.032 60.372 58.056 60.456 ;
    END
  END a[311]
  PIN a[312]
    DIRECTION INPUT ;
    USE SIGNAL ;
    PORT
      LAYER M5 ;
        RECT  58.128 60.372 58.152 60.456 ;
    END
  END a[312]
  PIN a[313]
    DIRECTION INPUT ;
    USE SIGNAL ;
    PORT
      LAYER M5 ;
        RECT  58.224 60.372 58.248 60.456 ;
    END
  END a[313]
  PIN a[314]
    DIRECTION INPUT ;
    USE SIGNAL ;
    PORT
      LAYER M5 ;
        RECT  58.32 60.372 58.344 60.456 ;
    END
  END a[314]
  PIN a[315]
    DIRECTION INPUT ;
    USE SIGNAL ;
    PORT
      LAYER M5 ;
        RECT  58.416 60.372 58.44 60.456 ;
    END
  END a[315]
  PIN a[316]
    DIRECTION INPUT ;
    USE SIGNAL ;
    PORT
      LAYER M5 ;
        RECT  58.512 60.372 58.536 60.456 ;
    END
  END a[316]
  PIN a[317]
    DIRECTION INPUT ;
    USE SIGNAL ;
    PORT
      LAYER M5 ;
        RECT  58.608 60.372 58.632 60.456 ;
    END
  END a[317]
  PIN a[318]
    DIRECTION INPUT ;
    USE SIGNAL ;
    PORT
      LAYER M5 ;
        RECT  58.704 60.372 58.728 60.456 ;
    END
  END a[318]
  PIN a[319]
    DIRECTION INPUT ;
    USE SIGNAL ;
    PORT
      LAYER M5 ;
        RECT  58.8 60.372 58.824 60.456 ;
    END
  END a[319]
  PIN a[31]
    DIRECTION INPUT ;
    USE SIGNAL ;
    PORT
      LAYER M3 ;
        RECT  60.3 60.419 60.318 60.456 ;
    END
  END a[31]
  PIN a[320]
    DIRECTION INPUT ;
    USE SIGNAL ;
    PORT
      LAYER M5 ;
        RECT  61.968 60.372 61.992 60.456 ;
    END
  END a[320]
  PIN a[321]
    DIRECTION INPUT ;
    USE SIGNAL ;
    PORT
      LAYER M5 ;
        RECT  62.064 60.372 62.088 60.456 ;
    END
  END a[321]
  PIN a[322]
    DIRECTION INPUT ;
    USE SIGNAL ;
    PORT
      LAYER M5 ;
        RECT  62.16 60.372 62.184 60.456 ;
    END
  END a[322]
  PIN a[323]
    DIRECTION INPUT ;
    USE SIGNAL ;
    PORT
      LAYER M5 ;
        RECT  62.256 60.372 62.28 60.456 ;
    END
  END a[323]
  PIN a[324]
    DIRECTION INPUT ;
    USE SIGNAL ;
    PORT
      LAYER M5 ;
        RECT  62.352 60.372 62.376 60.456 ;
    END
  END a[324]
  PIN a[325]
    DIRECTION INPUT ;
    USE SIGNAL ;
    PORT
      LAYER M5 ;
        RECT  62.448 60.372 62.472 60.456 ;
    END
  END a[325]
  PIN a[326]
    DIRECTION INPUT ;
    USE SIGNAL ;
    PORT
      LAYER M5 ;
        RECT  62.544 60.372 62.568 60.456 ;
    END
  END a[326]
  PIN a[327]
    DIRECTION INPUT ;
    USE SIGNAL ;
    PORT
      LAYER M5 ;
        RECT  62.64 60.372 62.664 60.456 ;
    END
  END a[327]
  PIN a[328]
    DIRECTION INPUT ;
    USE SIGNAL ;
    PORT
      LAYER M5 ;
        RECT  62.736 60.372 62.76 60.456 ;
    END
  END a[328]
  PIN a[329]
    DIRECTION INPUT ;
    USE SIGNAL ;
    PORT
      LAYER M5 ;
        RECT  62.832 60.372 62.856 60.456 ;
    END
  END a[329]
  PIN a[32]
    DIRECTION INPUT ;
    USE SIGNAL ;
    PORT
      LAYER M5 ;
        RECT  52.752 60.372 52.776 60.456 ;
    END
  END a[32]
  PIN a[330]
    DIRECTION INPUT ;
    USE SIGNAL ;
    PORT
      LAYER M5 ;
        RECT  62.928 60.372 62.952 60.456 ;
    END
  END a[330]
  PIN a[331]
    DIRECTION INPUT ;
    USE SIGNAL ;
    PORT
      LAYER M5 ;
        RECT  63.024 60.372 63.048 60.456 ;
    END
  END a[331]
  PIN a[332]
    DIRECTION INPUT ;
    USE SIGNAL ;
    PORT
      LAYER M5 ;
        RECT  63.12 60.372 63.144 60.456 ;
    END
  END a[332]
  PIN a[333]
    DIRECTION INPUT ;
    USE SIGNAL ;
    PORT
      LAYER M5 ;
        RECT  63.216 60.372 63.24 60.456 ;
    END
  END a[333]
  PIN a[334]
    DIRECTION INPUT ;
    USE SIGNAL ;
    PORT
      LAYER M5 ;
        RECT  63.312 60.372 63.336 60.456 ;
    END
  END a[334]
  PIN a[335]
    DIRECTION INPUT ;
    USE SIGNAL ;
    PORT
      LAYER M5 ;
        RECT  63.408 60.372 63.432 60.456 ;
    END
  END a[335]
  PIN a[336]
    DIRECTION INPUT ;
    USE SIGNAL ;
    PORT
      LAYER M5 ;
        RECT  63.504 60.372 63.528 60.456 ;
    END
  END a[336]
  PIN a[337]
    DIRECTION INPUT ;
    USE SIGNAL ;
    PORT
      LAYER M5 ;
        RECT  63.6 60.372 63.624 60.456 ;
    END
  END a[337]
  PIN a[338]
    DIRECTION INPUT ;
    USE SIGNAL ;
    PORT
      LAYER M5 ;
        RECT  63.696 60.372 63.72 60.456 ;
    END
  END a[338]
  PIN a[339]
    DIRECTION INPUT ;
    USE SIGNAL ;
    PORT
      LAYER M5 ;
        RECT  63.792 60.372 63.816 60.456 ;
    END
  END a[339]
  PIN a[33]
    DIRECTION INPUT ;
    USE SIGNAL ;
    PORT
      LAYER M5 ;
        RECT  52.848 60.372 52.872 60.456 ;
    END
  END a[33]
  PIN a[340]
    DIRECTION INPUT ;
    USE SIGNAL ;
    PORT
      LAYER M5 ;
        RECT  63.888 60.372 63.912 60.456 ;
    END
  END a[340]
  PIN a[341]
    DIRECTION INPUT ;
    USE SIGNAL ;
    PORT
      LAYER M5 ;
        RECT  63.984 60.372 64.008 60.456 ;
    END
  END a[341]
  PIN a[342]
    DIRECTION INPUT ;
    USE SIGNAL ;
    PORT
      LAYER M5 ;
        RECT  64.08 60.372 64.104 60.456 ;
    END
  END a[342]
  PIN a[343]
    DIRECTION INPUT ;
    USE SIGNAL ;
    PORT
      LAYER M5 ;
        RECT  64.176 60.372 64.2 60.456 ;
    END
  END a[343]
  PIN a[344]
    DIRECTION INPUT ;
    USE SIGNAL ;
    PORT
      LAYER M5 ;
        RECT  64.272 60.372 64.296 60.456 ;
    END
  END a[344]
  PIN a[345]
    DIRECTION INPUT ;
    USE SIGNAL ;
    PORT
      LAYER M5 ;
        RECT  64.368 60.372 64.392 60.456 ;
    END
  END a[345]
  PIN a[346]
    DIRECTION INPUT ;
    USE SIGNAL ;
    PORT
      LAYER M5 ;
        RECT  64.464 60.372 64.488 60.456 ;
    END
  END a[346]
  PIN a[347]
    DIRECTION INPUT ;
    USE SIGNAL ;
    PORT
      LAYER M5 ;
        RECT  64.56 60.372 64.584 60.456 ;
    END
  END a[347]
  PIN a[348]
    DIRECTION INPUT ;
    USE SIGNAL ;
    PORT
      LAYER M5 ;
        RECT  64.656 60.372 64.68 60.456 ;
    END
  END a[348]
  PIN a[349]
    DIRECTION INPUT ;
    USE SIGNAL ;
    PORT
      LAYER M5 ;
        RECT  64.752 60.372 64.776 60.456 ;
    END
  END a[349]
  PIN a[34]
    DIRECTION INPUT ;
    USE SIGNAL ;
    PORT
      LAYER M5 ;
        RECT  52.944 60.372 52.968 60.456 ;
    END
  END a[34]
  PIN a[350]
    DIRECTION INPUT ;
    USE SIGNAL ;
    PORT
      LAYER M5 ;
        RECT  64.848 60.372 64.872 60.456 ;
    END
  END a[350]
  PIN a[351]
    DIRECTION INPUT ;
    USE SIGNAL ;
    PORT
      LAYER M5 ;
        RECT  64.944 60.372 64.968 60.456 ;
    END
  END a[351]
  PIN a[352]
    DIRECTION INPUT ;
    USE SIGNAL ;
    PORT
      LAYER M5 ;
        RECT  46.608 60.372 46.632 60.456 ;
    END
  END a[352]
  PIN a[353]
    DIRECTION INPUT ;
    USE SIGNAL ;
    PORT
      LAYER M5 ;
        RECT  46.704 60.372 46.728 60.456 ;
    END
  END a[353]
  PIN a[354]
    DIRECTION INPUT ;
    USE SIGNAL ;
    PORT
      LAYER M5 ;
        RECT  46.8 60.372 46.824 60.456 ;
    END
  END a[354]
  PIN a[355]
    DIRECTION INPUT ;
    USE SIGNAL ;
    PORT
      LAYER M5 ;
        RECT  46.896 60.372 46.92 60.456 ;
    END
  END a[355]
  PIN a[356]
    DIRECTION INPUT ;
    USE SIGNAL ;
    PORT
      LAYER M5 ;
        RECT  46.992 60.372 47.016 60.456 ;
    END
  END a[356]
  PIN a[357]
    DIRECTION INPUT ;
    USE SIGNAL ;
    PORT
      LAYER M5 ;
        RECT  47.088 60.372 47.112 60.456 ;
    END
  END a[357]
  PIN a[358]
    DIRECTION INPUT ;
    USE SIGNAL ;
    PORT
      LAYER M5 ;
        RECT  47.184 60.372 47.208 60.456 ;
    END
  END a[358]
  PIN a[359]
    DIRECTION INPUT ;
    USE SIGNAL ;
    PORT
      LAYER M5 ;
        RECT  47.28 60.372 47.304 60.456 ;
    END
  END a[359]
  PIN a[35]
    DIRECTION INPUT ;
    USE SIGNAL ;
    PORT
      LAYER M5 ;
        RECT  53.04 60.372 53.064 60.456 ;
    END
  END a[35]
  PIN a[360]
    DIRECTION INPUT ;
    USE SIGNAL ;
    PORT
      LAYER M5 ;
        RECT  47.376 60.372 47.4 60.456 ;
    END
  END a[360]
  PIN a[361]
    DIRECTION INPUT ;
    USE SIGNAL ;
    PORT
      LAYER M5 ;
        RECT  47.472 60.372 47.496 60.456 ;
    END
  END a[361]
  PIN a[362]
    DIRECTION INPUT ;
    USE SIGNAL ;
    PORT
      LAYER M5 ;
        RECT  47.568 60.372 47.592 60.456 ;
    END
  END a[362]
  PIN a[363]
    DIRECTION INPUT ;
    USE SIGNAL ;
    PORT
      LAYER M5 ;
        RECT  47.664 60.372 47.688 60.456 ;
    END
  END a[363]
  PIN a[364]
    DIRECTION INPUT ;
    USE SIGNAL ;
    PORT
      LAYER M5 ;
        RECT  47.76 60.372 47.784 60.456 ;
    END
  END a[364]
  PIN a[365]
    DIRECTION INPUT ;
    USE SIGNAL ;
    PORT
      LAYER M5 ;
        RECT  47.856 60.372 47.88 60.456 ;
    END
  END a[365]
  PIN a[366]
    DIRECTION INPUT ;
    USE SIGNAL ;
    PORT
      LAYER M5 ;
        RECT  47.952 60.372 47.976 60.456 ;
    END
  END a[366]
  PIN a[367]
    DIRECTION INPUT ;
    USE SIGNAL ;
    PORT
      LAYER M5 ;
        RECT  48.048 60.372 48.072 60.456 ;
    END
  END a[367]
  PIN a[368]
    DIRECTION INPUT ;
    USE SIGNAL ;
    PORT
      LAYER M5 ;
        RECT  48.144 60.372 48.168 60.456 ;
    END
  END a[368]
  PIN a[369]
    DIRECTION INPUT ;
    USE SIGNAL ;
    PORT
      LAYER M5 ;
        RECT  48.24 60.372 48.264 60.456 ;
    END
  END a[369]
  PIN a[36]
    DIRECTION INPUT ;
    USE SIGNAL ;
    PORT
      LAYER M5 ;
        RECT  53.136 60.372 53.16 60.456 ;
    END
  END a[36]
  PIN a[370]
    DIRECTION INPUT ;
    USE SIGNAL ;
    PORT
      LAYER M5 ;
        RECT  48.336 60.372 48.36 60.456 ;
    END
  END a[370]
  PIN a[371]
    DIRECTION INPUT ;
    USE SIGNAL ;
    PORT
      LAYER M5 ;
        RECT  48.432 60.372 48.456 60.456 ;
    END
  END a[371]
  PIN a[372]
    DIRECTION INPUT ;
    USE SIGNAL ;
    PORT
      LAYER M5 ;
        RECT  48.528 60.372 48.552 60.456 ;
    END
  END a[372]
  PIN a[373]
    DIRECTION INPUT ;
    USE SIGNAL ;
    PORT
      LAYER M5 ;
        RECT  48.624 60.372 48.648 60.456 ;
    END
  END a[373]
  PIN a[374]
    DIRECTION INPUT ;
    USE SIGNAL ;
    PORT
      LAYER M5 ;
        RECT  48.72 60.372 48.744 60.456 ;
    END
  END a[374]
  PIN a[375]
    DIRECTION INPUT ;
    USE SIGNAL ;
    PORT
      LAYER M5 ;
        RECT  48.816 60.372 48.84 60.456 ;
    END
  END a[375]
  PIN a[376]
    DIRECTION INPUT ;
    USE SIGNAL ;
    PORT
      LAYER M5 ;
        RECT  48.912 60.372 48.936 60.456 ;
    END
  END a[376]
  PIN a[377]
    DIRECTION INPUT ;
    USE SIGNAL ;
    PORT
      LAYER M5 ;
        RECT  49.008 60.372 49.032 60.456 ;
    END
  END a[377]
  PIN a[378]
    DIRECTION INPUT ;
    USE SIGNAL ;
    PORT
      LAYER M5 ;
        RECT  49.104 60.372 49.128 60.456 ;
    END
  END a[378]
  PIN a[379]
    DIRECTION INPUT ;
    USE SIGNAL ;
    PORT
      LAYER M5 ;
        RECT  49.2 60.372 49.224 60.456 ;
    END
  END a[379]
  PIN a[37]
    DIRECTION INPUT ;
    USE SIGNAL ;
    PORT
      LAYER M5 ;
        RECT  53.232 60.372 53.256 60.456 ;
    END
  END a[37]
  PIN a[380]
    DIRECTION INPUT ;
    USE SIGNAL ;
    PORT
      LAYER M5 ;
        RECT  49.296 60.372 49.32 60.456 ;
    END
  END a[380]
  PIN a[381]
    DIRECTION INPUT ;
    USE SIGNAL ;
    PORT
      LAYER M5 ;
        RECT  49.392 60.372 49.416 60.456 ;
    END
  END a[381]
  PIN a[382]
    DIRECTION INPUT ;
    USE SIGNAL ;
    PORT
      LAYER M5 ;
        RECT  49.488 60.372 49.512 60.456 ;
    END
  END a[382]
  PIN a[383]
    DIRECTION INPUT ;
    USE SIGNAL ;
    PORT
      LAYER M5 ;
        RECT  49.584 60.372 49.608 60.456 ;
    END
  END a[383]
  PIN a[384]
    DIRECTION INPUT ;
    USE SIGNAL ;
    PORT
      LAYER M3 ;
        RECT  32.148 60.419 32.166 60.456 ;
    END
  END a[384]
  PIN a[385]
    DIRECTION INPUT ;
    USE SIGNAL ;
    PORT
      LAYER M3 ;
        RECT  32.22 60.419 32.238 60.456 ;
    END
  END a[385]
  PIN a[386]
    DIRECTION INPUT ;
    USE SIGNAL ;
    PORT
      LAYER M3 ;
        RECT  32.292 60.419 32.31 60.456 ;
    END
  END a[386]
  PIN a[387]
    DIRECTION INPUT ;
    USE SIGNAL ;
    PORT
      LAYER M3 ;
        RECT  32.364 60.419 32.382 60.456 ;
    END
  END a[387]
  PIN a[388]
    DIRECTION INPUT ;
    USE SIGNAL ;
    PORT
      LAYER M3 ;
        RECT  32.436 60.419 32.454 60.456 ;
    END
  END a[388]
  PIN a[389]
    DIRECTION INPUT ;
    USE SIGNAL ;
    PORT
      LAYER M3 ;
        RECT  32.508 60.419 32.526 60.456 ;
    END
  END a[389]
  PIN a[38]
    DIRECTION INPUT ;
    USE SIGNAL ;
    PORT
      LAYER M5 ;
        RECT  53.328 60.372 53.352 60.456 ;
    END
  END a[38]
  PIN a[390]
    DIRECTION INPUT ;
    USE SIGNAL ;
    PORT
      LAYER M3 ;
        RECT  32.58 60.419 32.598 60.456 ;
    END
  END a[390]
  PIN a[391]
    DIRECTION INPUT ;
    USE SIGNAL ;
    PORT
      LAYER M3 ;
        RECT  32.652 60.419 32.67 60.456 ;
    END
  END a[391]
  PIN a[392]
    DIRECTION INPUT ;
    USE SIGNAL ;
    PORT
      LAYER M3 ;
        RECT  32.724 60.419 32.742 60.456 ;
    END
  END a[392]
  PIN a[393]
    DIRECTION INPUT ;
    USE SIGNAL ;
    PORT
      LAYER M3 ;
        RECT  32.796 60.419 32.814 60.456 ;
    END
  END a[393]
  PIN a[394]
    DIRECTION INPUT ;
    USE SIGNAL ;
    PORT
      LAYER M3 ;
        RECT  32.868 60.419 32.886 60.456 ;
    END
  END a[394]
  PIN a[395]
    DIRECTION INPUT ;
    USE SIGNAL ;
    PORT
      LAYER M3 ;
        RECT  32.94 60.419 32.958 60.456 ;
    END
  END a[395]
  PIN a[396]
    DIRECTION INPUT ;
    USE SIGNAL ;
    PORT
      LAYER M3 ;
        RECT  33.012 60.419 33.03 60.456 ;
    END
  END a[396]
  PIN a[397]
    DIRECTION INPUT ;
    USE SIGNAL ;
    PORT
      LAYER M3 ;
        RECT  33.084 60.419 33.102 60.456 ;
    END
  END a[397]
  PIN a[398]
    DIRECTION INPUT ;
    USE SIGNAL ;
    PORT
      LAYER M3 ;
        RECT  33.156 60.419 33.174 60.456 ;
    END
  END a[398]
  PIN a[399]
    DIRECTION INPUT ;
    USE SIGNAL ;
    PORT
      LAYER M3 ;
        RECT  33.228 60.419 33.246 60.456 ;
    END
  END a[399]
  PIN a[39]
    DIRECTION INPUT ;
    USE SIGNAL ;
    PORT
      LAYER M5 ;
        RECT  53.424 60.372 53.448 60.456 ;
    END
  END a[39]
  PIN a[3]
    DIRECTION INPUT ;
    USE SIGNAL ;
    PORT
      LAYER M3 ;
        RECT  58.284 60.419 58.302 60.456 ;
    END
  END a[3]
  PIN a[400]
    DIRECTION INPUT ;
    USE SIGNAL ;
    PORT
      LAYER M3 ;
        RECT  33.3 60.419 33.318 60.456 ;
    END
  END a[400]
  PIN a[401]
    DIRECTION INPUT ;
    USE SIGNAL ;
    PORT
      LAYER M3 ;
        RECT  33.372 60.419 33.39 60.456 ;
    END
  END a[401]
  PIN a[402]
    DIRECTION INPUT ;
    USE SIGNAL ;
    PORT
      LAYER M3 ;
        RECT  33.444 60.419 33.462 60.456 ;
    END
  END a[402]
  PIN a[403]
    DIRECTION INPUT ;
    USE SIGNAL ;
    PORT
      LAYER M3 ;
        RECT  33.516 60.419 33.534 60.456 ;
    END
  END a[403]
  PIN a[404]
    DIRECTION INPUT ;
    USE SIGNAL ;
    PORT
      LAYER M3 ;
        RECT  33.588 60.419 33.606 60.456 ;
    END
  END a[404]
  PIN a[405]
    DIRECTION INPUT ;
    USE SIGNAL ;
    PORT
      LAYER M3 ;
        RECT  33.66 60.419 33.678 60.456 ;
    END
  END a[405]
  PIN a[406]
    DIRECTION INPUT ;
    USE SIGNAL ;
    PORT
      LAYER M3 ;
        RECT  33.732 60.419 33.75 60.456 ;
    END
  END a[406]
  PIN a[407]
    DIRECTION INPUT ;
    USE SIGNAL ;
    PORT
      LAYER M3 ;
        RECT  33.804 60.419 33.822 60.456 ;
    END
  END a[407]
  PIN a[408]
    DIRECTION INPUT ;
    USE SIGNAL ;
    PORT
      LAYER M3 ;
        RECT  33.876 60.419 33.894 60.456 ;
    END
  END a[408]
  PIN a[409]
    DIRECTION INPUT ;
    USE SIGNAL ;
    PORT
      LAYER M3 ;
        RECT  33.948 60.419 33.966 60.456 ;
    END
  END a[409]
  PIN a[40]
    DIRECTION INPUT ;
    USE SIGNAL ;
    PORT
      LAYER M5 ;
        RECT  53.52 60.372 53.544 60.456 ;
    END
  END a[40]
  PIN a[410]
    DIRECTION INPUT ;
    USE SIGNAL ;
    PORT
      LAYER M3 ;
        RECT  34.02 60.419 34.038 60.456 ;
    END
  END a[410]
  PIN a[411]
    DIRECTION INPUT ;
    USE SIGNAL ;
    PORT
      LAYER M3 ;
        RECT  34.092 60.419 34.11 60.456 ;
    END
  END a[411]
  PIN a[412]
    DIRECTION INPUT ;
    USE SIGNAL ;
    PORT
      LAYER M3 ;
        RECT  34.164 60.419 34.182 60.456 ;
    END
  END a[412]
  PIN a[413]
    DIRECTION INPUT ;
    USE SIGNAL ;
    PORT
      LAYER M3 ;
        RECT  34.236 60.419 34.254 60.456 ;
    END
  END a[413]
  PIN a[414]
    DIRECTION INPUT ;
    USE SIGNAL ;
    PORT
      LAYER M3 ;
        RECT  34.308 60.419 34.326 60.456 ;
    END
  END a[414]
  PIN a[415]
    DIRECTION INPUT ;
    USE SIGNAL ;
    PORT
      LAYER M3 ;
        RECT  34.38 60.419 34.398 60.456 ;
    END
  END a[415]
  PIN a[416]
    DIRECTION INPUT ;
    USE SIGNAL ;
    PORT
      LAYER M3 ;
        RECT  39.06 60.419 39.078 60.456 ;
    END
  END a[416]
  PIN a[417]
    DIRECTION INPUT ;
    USE SIGNAL ;
    PORT
      LAYER M3 ;
        RECT  39.132 60.419 39.15 60.456 ;
    END
  END a[417]
  PIN a[418]
    DIRECTION INPUT ;
    USE SIGNAL ;
    PORT
      LAYER M3 ;
        RECT  39.204 60.419 39.222 60.456 ;
    END
  END a[418]
  PIN a[419]
    DIRECTION INPUT ;
    USE SIGNAL ;
    PORT
      LAYER M3 ;
        RECT  39.276 60.419 39.294 60.456 ;
    END
  END a[419]
  PIN a[41]
    DIRECTION INPUT ;
    USE SIGNAL ;
    PORT
      LAYER M5 ;
        RECT  53.616 60.372 53.64 60.456 ;
    END
  END a[41]
  PIN a[420]
    DIRECTION INPUT ;
    USE SIGNAL ;
    PORT
      LAYER M3 ;
        RECT  39.348 60.419 39.366 60.456 ;
    END
  END a[420]
  PIN a[421]
    DIRECTION INPUT ;
    USE SIGNAL ;
    PORT
      LAYER M3 ;
        RECT  39.42 60.419 39.438 60.456 ;
    END
  END a[421]
  PIN a[422]
    DIRECTION INPUT ;
    USE SIGNAL ;
    PORT
      LAYER M3 ;
        RECT  39.492 60.419 39.51 60.456 ;
    END
  END a[422]
  PIN a[423]
    DIRECTION INPUT ;
    USE SIGNAL ;
    PORT
      LAYER M3 ;
        RECT  39.564 60.419 39.582 60.456 ;
    END
  END a[423]
  PIN a[424]
    DIRECTION INPUT ;
    USE SIGNAL ;
    PORT
      LAYER M3 ;
        RECT  39.636 60.419 39.654 60.456 ;
    END
  END a[424]
  PIN a[425]
    DIRECTION INPUT ;
    USE SIGNAL ;
    PORT
      LAYER M3 ;
        RECT  39.708 60.419 39.726 60.456 ;
    END
  END a[425]
  PIN a[426]
    DIRECTION INPUT ;
    USE SIGNAL ;
    PORT
      LAYER M3 ;
        RECT  39.78 60.419 39.798 60.456 ;
    END
  END a[426]
  PIN a[427]
    DIRECTION INPUT ;
    USE SIGNAL ;
    PORT
      LAYER M3 ;
        RECT  39.852 60.419 39.87 60.456 ;
    END
  END a[427]
  PIN a[428]
    DIRECTION INPUT ;
    USE SIGNAL ;
    PORT
      LAYER M3 ;
        RECT  39.924 60.419 39.942 60.456 ;
    END
  END a[428]
  PIN a[429]
    DIRECTION INPUT ;
    USE SIGNAL ;
    PORT
      LAYER M3 ;
        RECT  39.996 60.419 40.014 60.456 ;
    END
  END a[429]
  PIN a[42]
    DIRECTION INPUT ;
    USE SIGNAL ;
    PORT
      LAYER M5 ;
        RECT  53.712 60.372 53.736 60.456 ;
    END
  END a[42]
  PIN a[430]
    DIRECTION INPUT ;
    USE SIGNAL ;
    PORT
      LAYER M3 ;
        RECT  40.068 60.419 40.086 60.456 ;
    END
  END a[430]
  PIN a[431]
    DIRECTION INPUT ;
    USE SIGNAL ;
    PORT
      LAYER M3 ;
        RECT  40.14 60.419 40.158 60.456 ;
    END
  END a[431]
  PIN a[432]
    DIRECTION INPUT ;
    USE SIGNAL ;
    PORT
      LAYER M3 ;
        RECT  40.212 60.419 40.23 60.456 ;
    END
  END a[432]
  PIN a[433]
    DIRECTION INPUT ;
    USE SIGNAL ;
    PORT
      LAYER M3 ;
        RECT  40.284 60.419 40.302 60.456 ;
    END
  END a[433]
  PIN a[434]
    DIRECTION INPUT ;
    USE SIGNAL ;
    PORT
      LAYER M3 ;
        RECT  40.356 60.419 40.374 60.456 ;
    END
  END a[434]
  PIN a[435]
    DIRECTION INPUT ;
    USE SIGNAL ;
    PORT
      LAYER M3 ;
        RECT  40.428 60.419 40.446 60.456 ;
    END
  END a[435]
  PIN a[436]
    DIRECTION INPUT ;
    USE SIGNAL ;
    PORT
      LAYER M3 ;
        RECT  40.5 60.419 40.518 60.456 ;
    END
  END a[436]
  PIN a[437]
    DIRECTION INPUT ;
    USE SIGNAL ;
    PORT
      LAYER M3 ;
        RECT  40.572 60.419 40.59 60.456 ;
    END
  END a[437]
  PIN a[438]
    DIRECTION INPUT ;
    USE SIGNAL ;
    PORT
      LAYER M3 ;
        RECT  40.644 60.419 40.662 60.456 ;
    END
  END a[438]
  PIN a[439]
    DIRECTION INPUT ;
    USE SIGNAL ;
    PORT
      LAYER M3 ;
        RECT  40.716 60.419 40.734 60.456 ;
    END
  END a[439]
  PIN a[43]
    DIRECTION INPUT ;
    USE SIGNAL ;
    PORT
      LAYER M5 ;
        RECT  53.808 60.372 53.832 60.456 ;
    END
  END a[43]
  PIN a[440]
    DIRECTION INPUT ;
    USE SIGNAL ;
    PORT
      LAYER M3 ;
        RECT  40.788 60.419 40.806 60.456 ;
    END
  END a[440]
  PIN a[441]
    DIRECTION INPUT ;
    USE SIGNAL ;
    PORT
      LAYER M3 ;
        RECT  40.86 60.419 40.878 60.456 ;
    END
  END a[441]
  PIN a[442]
    DIRECTION INPUT ;
    USE SIGNAL ;
    PORT
      LAYER M3 ;
        RECT  40.932 60.419 40.95 60.456 ;
    END
  END a[442]
  PIN a[443]
    DIRECTION INPUT ;
    USE SIGNAL ;
    PORT
      LAYER M3 ;
        RECT  41.004 60.419 41.022 60.456 ;
    END
  END a[443]
  PIN a[444]
    DIRECTION INPUT ;
    USE SIGNAL ;
    PORT
      LAYER M3 ;
        RECT  41.076 60.419 41.094 60.456 ;
    END
  END a[444]
  PIN a[445]
    DIRECTION INPUT ;
    USE SIGNAL ;
    PORT
      LAYER M3 ;
        RECT  41.148 60.419 41.166 60.456 ;
    END
  END a[445]
  PIN a[446]
    DIRECTION INPUT ;
    USE SIGNAL ;
    PORT
      LAYER M3 ;
        RECT  41.22 60.419 41.238 60.456 ;
    END
  END a[446]
  PIN a[447]
    DIRECTION INPUT ;
    USE SIGNAL ;
    PORT
      LAYER M3 ;
        RECT  41.292 60.419 41.31 60.456 ;
    END
  END a[447]
  PIN a[448]
    DIRECTION INPUT ;
    USE SIGNAL ;
    PORT
      LAYER M3 ;
        RECT  41.364 60.419 41.382 60.456 ;
    END
  END a[448]
  PIN a[449]
    DIRECTION INPUT ;
    USE SIGNAL ;
    PORT
      LAYER M3 ;
        RECT  41.436 60.419 41.454 60.456 ;
    END
  END a[449]
  PIN a[44]
    DIRECTION INPUT ;
    USE SIGNAL ;
    PORT
      LAYER M5 ;
        RECT  53.904 60.372 53.928 60.456 ;
    END
  END a[44]
  PIN a[450]
    DIRECTION INPUT ;
    USE SIGNAL ;
    PORT
      LAYER M3 ;
        RECT  41.508 60.419 41.526 60.456 ;
    END
  END a[450]
  PIN a[451]
    DIRECTION INPUT ;
    USE SIGNAL ;
    PORT
      LAYER M3 ;
        RECT  41.58 60.419 41.598 60.456 ;
    END
  END a[451]
  PIN a[452]
    DIRECTION INPUT ;
    USE SIGNAL ;
    PORT
      LAYER M3 ;
        RECT  41.652 60.419 41.67 60.456 ;
    END
  END a[452]
  PIN a[453]
    DIRECTION INPUT ;
    USE SIGNAL ;
    PORT
      LAYER M3 ;
        RECT  41.724 60.419 41.742 60.456 ;
    END
  END a[453]
  PIN a[454]
    DIRECTION INPUT ;
    USE SIGNAL ;
    PORT
      LAYER M3 ;
        RECT  41.796 60.419 41.814 60.456 ;
    END
  END a[454]
  PIN a[455]
    DIRECTION INPUT ;
    USE SIGNAL ;
    PORT
      LAYER M3 ;
        RECT  41.868 60.419 41.886 60.456 ;
    END
  END a[455]
  PIN a[456]
    DIRECTION INPUT ;
    USE SIGNAL ;
    PORT
      LAYER M3 ;
        RECT  41.94 60.419 41.958 60.456 ;
    END
  END a[456]
  PIN a[457]
    DIRECTION INPUT ;
    USE SIGNAL ;
    PORT
      LAYER M3 ;
        RECT  42.012 60.419 42.03 60.456 ;
    END
  END a[457]
  PIN a[458]
    DIRECTION INPUT ;
    USE SIGNAL ;
    PORT
      LAYER M3 ;
        RECT  42.084 60.419 42.102 60.456 ;
    END
  END a[458]
  PIN a[459]
    DIRECTION INPUT ;
    USE SIGNAL ;
    PORT
      LAYER M3 ;
        RECT  42.156 60.419 42.174 60.456 ;
    END
  END a[459]
  PIN a[45]
    DIRECTION INPUT ;
    USE SIGNAL ;
    PORT
      LAYER M5 ;
        RECT  54 60.372 54.024 60.456 ;
    END
  END a[45]
  PIN a[460]
    DIRECTION INPUT ;
    USE SIGNAL ;
    PORT
      LAYER M3 ;
        RECT  42.228 60.419 42.246 60.456 ;
    END
  END a[460]
  PIN a[461]
    DIRECTION INPUT ;
    USE SIGNAL ;
    PORT
      LAYER M3 ;
        RECT  42.3 60.419 42.318 60.456 ;
    END
  END a[461]
  PIN a[462]
    DIRECTION INPUT ;
    USE SIGNAL ;
    PORT
      LAYER M3 ;
        RECT  42.372 60.419 42.39 60.456 ;
    END
  END a[462]
  PIN a[463]
    DIRECTION INPUT ;
    USE SIGNAL ;
    PORT
      LAYER M3 ;
        RECT  42.444 60.419 42.462 60.456 ;
    END
  END a[463]
  PIN a[464]
    DIRECTION INPUT ;
    USE SIGNAL ;
    PORT
      LAYER M3 ;
        RECT  42.516 60.419 42.534 60.456 ;
    END
  END a[464]
  PIN a[465]
    DIRECTION INPUT ;
    USE SIGNAL ;
    PORT
      LAYER M3 ;
        RECT  42.588 60.419 42.606 60.456 ;
    END
  END a[465]
  PIN a[466]
    DIRECTION INPUT ;
    USE SIGNAL ;
    PORT
      LAYER M3 ;
        RECT  42.66 60.419 42.678 60.456 ;
    END
  END a[466]
  PIN a[467]
    DIRECTION INPUT ;
    USE SIGNAL ;
    PORT
      LAYER M3 ;
        RECT  42.732 60.419 42.75 60.456 ;
    END
  END a[467]
  PIN a[468]
    DIRECTION INPUT ;
    USE SIGNAL ;
    PORT
      LAYER M3 ;
        RECT  42.804 60.419 42.822 60.456 ;
    END
  END a[468]
  PIN a[469]
    DIRECTION INPUT ;
    USE SIGNAL ;
    PORT
      LAYER M3 ;
        RECT  42.876 60.419 42.894 60.456 ;
    END
  END a[469]
  PIN a[46]
    DIRECTION INPUT ;
    USE SIGNAL ;
    PORT
      LAYER M5 ;
        RECT  54.096 60.372 54.12 60.456 ;
    END
  END a[46]
  PIN a[470]
    DIRECTION INPUT ;
    USE SIGNAL ;
    PORT
      LAYER M3 ;
        RECT  42.948 60.419 42.966 60.456 ;
    END
  END a[470]
  PIN a[471]
    DIRECTION INPUT ;
    USE SIGNAL ;
    PORT
      LAYER M3 ;
        RECT  43.02 60.419 43.038 60.456 ;
    END
  END a[471]
  PIN a[472]
    DIRECTION INPUT ;
    USE SIGNAL ;
    PORT
      LAYER M3 ;
        RECT  43.092 60.419 43.11 60.456 ;
    END
  END a[472]
  PIN a[473]
    DIRECTION INPUT ;
    USE SIGNAL ;
    PORT
      LAYER M3 ;
        RECT  43.164 60.419 43.182 60.456 ;
    END
  END a[473]
  PIN a[474]
    DIRECTION INPUT ;
    USE SIGNAL ;
    PORT
      LAYER M3 ;
        RECT  43.236 60.419 43.254 60.456 ;
    END
  END a[474]
  PIN a[475]
    DIRECTION INPUT ;
    USE SIGNAL ;
    PORT
      LAYER M3 ;
        RECT  43.308 60.419 43.326 60.456 ;
    END
  END a[475]
  PIN a[476]
    DIRECTION INPUT ;
    USE SIGNAL ;
    PORT
      LAYER M3 ;
        RECT  43.38 60.419 43.398 60.456 ;
    END
  END a[476]
  PIN a[477]
    DIRECTION INPUT ;
    USE SIGNAL ;
    PORT
      LAYER M3 ;
        RECT  43.452 60.419 43.47 60.456 ;
    END
  END a[477]
  PIN a[478]
    DIRECTION INPUT ;
    USE SIGNAL ;
    PORT
      LAYER M3 ;
        RECT  43.524 60.419 43.542 60.456 ;
    END
  END a[478]
  PIN a[479]
    DIRECTION INPUT ;
    USE SIGNAL ;
    PORT
      LAYER M3 ;
        RECT  43.596 60.419 43.614 60.456 ;
    END
  END a[479]
  PIN a[47]
    DIRECTION INPUT ;
    USE SIGNAL ;
    PORT
      LAYER M5 ;
        RECT  54.192 60.372 54.216 60.456 ;
    END
  END a[47]
  PIN a[480]
    DIRECTION INPUT ;
    USE SIGNAL ;
    PORT
      LAYER M3 ;
        RECT  34.452 60.419 34.47 60.456 ;
    END
  END a[480]
  PIN a[481]
    DIRECTION INPUT ;
    USE SIGNAL ;
    PORT
      LAYER M3 ;
        RECT  34.524 60.419 34.542 60.456 ;
    END
  END a[481]
  PIN a[482]
    DIRECTION INPUT ;
    USE SIGNAL ;
    PORT
      LAYER M3 ;
        RECT  34.596 60.419 34.614 60.456 ;
    END
  END a[482]
  PIN a[483]
    DIRECTION INPUT ;
    USE SIGNAL ;
    PORT
      LAYER M3 ;
        RECT  34.668 60.419 34.686 60.456 ;
    END
  END a[483]
  PIN a[484]
    DIRECTION INPUT ;
    USE SIGNAL ;
    PORT
      LAYER M3 ;
        RECT  34.74 60.419 34.758 60.456 ;
    END
  END a[484]
  PIN a[485]
    DIRECTION INPUT ;
    USE SIGNAL ;
    PORT
      LAYER M3 ;
        RECT  34.812 60.419 34.83 60.456 ;
    END
  END a[485]
  PIN a[486]
    DIRECTION INPUT ;
    USE SIGNAL ;
    PORT
      LAYER M3 ;
        RECT  34.884 60.419 34.902 60.456 ;
    END
  END a[486]
  PIN a[487]
    DIRECTION INPUT ;
    USE SIGNAL ;
    PORT
      LAYER M3 ;
        RECT  34.956 60.419 34.974 60.456 ;
    END
  END a[487]
  PIN a[488]
    DIRECTION INPUT ;
    USE SIGNAL ;
    PORT
      LAYER M3 ;
        RECT  35.028 60.419 35.046 60.456 ;
    END
  END a[488]
  PIN a[489]
    DIRECTION INPUT ;
    USE SIGNAL ;
    PORT
      LAYER M3 ;
        RECT  35.1 60.419 35.118 60.456 ;
    END
  END a[489]
  PIN a[48]
    DIRECTION INPUT ;
    USE SIGNAL ;
    PORT
      LAYER M5 ;
        RECT  54.288 60.372 54.312 60.456 ;
    END
  END a[48]
  PIN a[490]
    DIRECTION INPUT ;
    USE SIGNAL ;
    PORT
      LAYER M3 ;
        RECT  35.172 60.419 35.19 60.456 ;
    END
  END a[490]
  PIN a[491]
    DIRECTION INPUT ;
    USE SIGNAL ;
    PORT
      LAYER M3 ;
        RECT  35.244 60.419 35.262 60.456 ;
    END
  END a[491]
  PIN a[492]
    DIRECTION INPUT ;
    USE SIGNAL ;
    PORT
      LAYER M3 ;
        RECT  35.316 60.419 35.334 60.456 ;
    END
  END a[492]
  PIN a[493]
    DIRECTION INPUT ;
    USE SIGNAL ;
    PORT
      LAYER M3 ;
        RECT  35.388 60.419 35.406 60.456 ;
    END
  END a[493]
  PIN a[494]
    DIRECTION INPUT ;
    USE SIGNAL ;
    PORT
      LAYER M3 ;
        RECT  35.46 60.419 35.478 60.456 ;
    END
  END a[494]
  PIN a[495]
    DIRECTION INPUT ;
    USE SIGNAL ;
    PORT
      LAYER M3 ;
        RECT  35.532 60.419 35.55 60.456 ;
    END
  END a[495]
  PIN a[496]
    DIRECTION INPUT ;
    USE SIGNAL ;
    PORT
      LAYER M3 ;
        RECT  35.604 60.419 35.622 60.456 ;
    END
  END a[496]
  PIN a[497]
    DIRECTION INPUT ;
    USE SIGNAL ;
    PORT
      LAYER M3 ;
        RECT  35.676 60.419 35.694 60.456 ;
    END
  END a[497]
  PIN a[498]
    DIRECTION INPUT ;
    USE SIGNAL ;
    PORT
      LAYER M3 ;
        RECT  35.748 60.419 35.766 60.456 ;
    END
  END a[498]
  PIN a[499]
    DIRECTION INPUT ;
    USE SIGNAL ;
    PORT
      LAYER M3 ;
        RECT  35.82 60.419 35.838 60.456 ;
    END
  END a[499]
  PIN a[49]
    DIRECTION INPUT ;
    USE SIGNAL ;
    PORT
      LAYER M5 ;
        RECT  54.384 60.372 54.408 60.456 ;
    END
  END a[49]
  PIN a[4]
    DIRECTION INPUT ;
    USE SIGNAL ;
    PORT
      LAYER M3 ;
        RECT  58.356 60.419 58.374 60.456 ;
    END
  END a[4]
  PIN a[500]
    DIRECTION INPUT ;
    USE SIGNAL ;
    PORT
      LAYER M3 ;
        RECT  35.892 60.419 35.91 60.456 ;
    END
  END a[500]
  PIN a[501]
    DIRECTION INPUT ;
    USE SIGNAL ;
    PORT
      LAYER M3 ;
        RECT  35.964 60.419 35.982 60.456 ;
    END
  END a[501]
  PIN a[502]
    DIRECTION INPUT ;
    USE SIGNAL ;
    PORT
      LAYER M3 ;
        RECT  36.036 60.419 36.054 60.456 ;
    END
  END a[502]
  PIN a[503]
    DIRECTION INPUT ;
    USE SIGNAL ;
    PORT
      LAYER M3 ;
        RECT  36.108 60.419 36.126 60.456 ;
    END
  END a[503]
  PIN a[504]
    DIRECTION INPUT ;
    USE SIGNAL ;
    PORT
      LAYER M3 ;
        RECT  36.18 60.419 36.198 60.456 ;
    END
  END a[504]
  PIN a[505]
    DIRECTION INPUT ;
    USE SIGNAL ;
    PORT
      LAYER M3 ;
        RECT  36.252 60.419 36.27 60.456 ;
    END
  END a[505]
  PIN a[506]
    DIRECTION INPUT ;
    USE SIGNAL ;
    PORT
      LAYER M3 ;
        RECT  36.324 60.419 36.342 60.456 ;
    END
  END a[506]
  PIN a[507]
    DIRECTION INPUT ;
    USE SIGNAL ;
    PORT
      LAYER M3 ;
        RECT  36.396 60.419 36.414 60.456 ;
    END
  END a[507]
  PIN a[508]
    DIRECTION INPUT ;
    USE SIGNAL ;
    PORT
      LAYER M3 ;
        RECT  36.468 60.419 36.486 60.456 ;
    END
  END a[508]
  PIN a[509]
    DIRECTION INPUT ;
    USE SIGNAL ;
    PORT
      LAYER M3 ;
        RECT  36.54 60.419 36.558 60.456 ;
    END
  END a[509]
  PIN a[50]
    DIRECTION INPUT ;
    USE SIGNAL ;
    PORT
      LAYER M5 ;
        RECT  54.48 60.372 54.504 60.456 ;
    END
  END a[50]
  PIN a[510]
    DIRECTION INPUT ;
    USE SIGNAL ;
    PORT
      LAYER M3 ;
        RECT  36.612 60.419 36.63 60.456 ;
    END
  END a[510]
  PIN a[511]
    DIRECTION INPUT ;
    USE SIGNAL ;
    PORT
      LAYER M3 ;
        RECT  36.684 60.419 36.702 60.456 ;
    END
  END a[511]
  PIN a[512]
    DIRECTION INPUT ;
    USE SIGNAL ;
    PORT
      LAYER M3 ;
        RECT  43.668 60.419 43.686 60.456 ;
    END
  END a[512]
  PIN a[513]
    DIRECTION INPUT ;
    USE SIGNAL ;
    PORT
      LAYER M3 ;
        RECT  43.74 60.419 43.758 60.456 ;
    END
  END a[513]
  PIN a[514]
    DIRECTION INPUT ;
    USE SIGNAL ;
    PORT
      LAYER M3 ;
        RECT  43.812 60.419 43.83 60.456 ;
    END
  END a[514]
  PIN a[515]
    DIRECTION INPUT ;
    USE SIGNAL ;
    PORT
      LAYER M3 ;
        RECT  43.884 60.419 43.902 60.456 ;
    END
  END a[515]
  PIN a[516]
    DIRECTION INPUT ;
    USE SIGNAL ;
    PORT
      LAYER M3 ;
        RECT  43.956 60.419 43.974 60.456 ;
    END
  END a[516]
  PIN a[517]
    DIRECTION INPUT ;
    USE SIGNAL ;
    PORT
      LAYER M3 ;
        RECT  44.028 60.419 44.046 60.456 ;
    END
  END a[517]
  PIN a[518]
    DIRECTION INPUT ;
    USE SIGNAL ;
    PORT
      LAYER M3 ;
        RECT  44.1 60.419 44.118 60.456 ;
    END
  END a[518]
  PIN a[519]
    DIRECTION INPUT ;
    USE SIGNAL ;
    PORT
      LAYER M3 ;
        RECT  44.172 60.419 44.19 60.456 ;
    END
  END a[519]
  PIN a[51]
    DIRECTION INPUT ;
    USE SIGNAL ;
    PORT
      LAYER M5 ;
        RECT  54.576 60.372 54.6 60.456 ;
    END
  END a[51]
  PIN a[520]
    DIRECTION INPUT ;
    USE SIGNAL ;
    PORT
      LAYER M3 ;
        RECT  44.244 60.419 44.262 60.456 ;
    END
  END a[520]
  PIN a[521]
    DIRECTION INPUT ;
    USE SIGNAL ;
    PORT
      LAYER M3 ;
        RECT  44.316 60.419 44.334 60.456 ;
    END
  END a[521]
  PIN a[522]
    DIRECTION INPUT ;
    USE SIGNAL ;
    PORT
      LAYER M3 ;
        RECT  44.388 60.419 44.406 60.456 ;
    END
  END a[522]
  PIN a[523]
    DIRECTION INPUT ;
    USE SIGNAL ;
    PORT
      LAYER M3 ;
        RECT  44.46 60.419 44.478 60.456 ;
    END
  END a[523]
  PIN a[524]
    DIRECTION INPUT ;
    USE SIGNAL ;
    PORT
      LAYER M3 ;
        RECT  44.532 60.419 44.55 60.456 ;
    END
  END a[524]
  PIN a[525]
    DIRECTION INPUT ;
    USE SIGNAL ;
    PORT
      LAYER M3 ;
        RECT  44.604 60.419 44.622 60.456 ;
    END
  END a[525]
  PIN a[526]
    DIRECTION INPUT ;
    USE SIGNAL ;
    PORT
      LAYER M3 ;
        RECT  44.676 60.419 44.694 60.456 ;
    END
  END a[526]
  PIN a[527]
    DIRECTION INPUT ;
    USE SIGNAL ;
    PORT
      LAYER M3 ;
        RECT  44.748 60.419 44.766 60.456 ;
    END
  END a[527]
  PIN a[528]
    DIRECTION INPUT ;
    USE SIGNAL ;
    PORT
      LAYER M3 ;
        RECT  44.82 60.419 44.838 60.456 ;
    END
  END a[528]
  PIN a[529]
    DIRECTION INPUT ;
    USE SIGNAL ;
    PORT
      LAYER M3 ;
        RECT  44.892 60.419 44.91 60.456 ;
    END
  END a[529]
  PIN a[52]
    DIRECTION INPUT ;
    USE SIGNAL ;
    PORT
      LAYER M5 ;
        RECT  54.672 60.372 54.696 60.456 ;
    END
  END a[52]
  PIN a[530]
    DIRECTION INPUT ;
    USE SIGNAL ;
    PORT
      LAYER M3 ;
        RECT  44.964 60.419 44.982 60.456 ;
    END
  END a[530]
  PIN a[531]
    DIRECTION INPUT ;
    USE SIGNAL ;
    PORT
      LAYER M3 ;
        RECT  45.036 60.419 45.054 60.456 ;
    END
  END a[531]
  PIN a[532]
    DIRECTION INPUT ;
    USE SIGNAL ;
    PORT
      LAYER M3 ;
        RECT  45.108 60.419 45.126 60.456 ;
    END
  END a[532]
  PIN a[533]
    DIRECTION INPUT ;
    USE SIGNAL ;
    PORT
      LAYER M3 ;
        RECT  45.18 60.419 45.198 60.456 ;
    END
  END a[533]
  PIN a[534]
    DIRECTION INPUT ;
    USE SIGNAL ;
    PORT
      LAYER M3 ;
        RECT  45.252 60.419 45.27 60.456 ;
    END
  END a[534]
  PIN a[535]
    DIRECTION INPUT ;
    USE SIGNAL ;
    PORT
      LAYER M3 ;
        RECT  45.324 60.419 45.342 60.456 ;
    END
  END a[535]
  PIN a[536]
    DIRECTION INPUT ;
    USE SIGNAL ;
    PORT
      LAYER M3 ;
        RECT  45.396 60.419 45.414 60.456 ;
    END
  END a[536]
  PIN a[537]
    DIRECTION INPUT ;
    USE SIGNAL ;
    PORT
      LAYER M3 ;
        RECT  45.468 60.419 45.486 60.456 ;
    END
  END a[537]
  PIN a[538]
    DIRECTION INPUT ;
    USE SIGNAL ;
    PORT
      LAYER M3 ;
        RECT  45.54 60.419 45.558 60.456 ;
    END
  END a[538]
  PIN a[539]
    DIRECTION INPUT ;
    USE SIGNAL ;
    PORT
      LAYER M3 ;
        RECT  45.612 60.419 45.63 60.456 ;
    END
  END a[539]
  PIN a[53]
    DIRECTION INPUT ;
    USE SIGNAL ;
    PORT
      LAYER M5 ;
        RECT  54.768 60.372 54.792 60.456 ;
    END
  END a[53]
  PIN a[540]
    DIRECTION INPUT ;
    USE SIGNAL ;
    PORT
      LAYER M3 ;
        RECT  45.684 60.419 45.702 60.456 ;
    END
  END a[540]
  PIN a[541]
    DIRECTION INPUT ;
    USE SIGNAL ;
    PORT
      LAYER M3 ;
        RECT  45.756 60.419 45.774 60.456 ;
    END
  END a[541]
  PIN a[542]
    DIRECTION INPUT ;
    USE SIGNAL ;
    PORT
      LAYER M3 ;
        RECT  45.828 60.419 45.846 60.456 ;
    END
  END a[542]
  PIN a[543]
    DIRECTION INPUT ;
    USE SIGNAL ;
    PORT
      LAYER M3 ;
        RECT  45.9 60.419 45.918 60.456 ;
    END
  END a[543]
  PIN a[544]
    DIRECTION INPUT ;
    USE SIGNAL ;
    PORT
      LAYER M3 ;
        RECT  36.756 60.419 36.774 60.456 ;
    END
  END a[544]
  PIN a[545]
    DIRECTION INPUT ;
    USE SIGNAL ;
    PORT
      LAYER M3 ;
        RECT  36.828 60.419 36.846 60.456 ;
    END
  END a[545]
  PIN a[546]
    DIRECTION INPUT ;
    USE SIGNAL ;
    PORT
      LAYER M3 ;
        RECT  36.9 60.419 36.918 60.456 ;
    END
  END a[546]
  PIN a[547]
    DIRECTION INPUT ;
    USE SIGNAL ;
    PORT
      LAYER M3 ;
        RECT  36.972 60.419 36.99 60.456 ;
    END
  END a[547]
  PIN a[548]
    DIRECTION INPUT ;
    USE SIGNAL ;
    PORT
      LAYER M3 ;
        RECT  37.044 60.419 37.062 60.456 ;
    END
  END a[548]
  PIN a[549]
    DIRECTION INPUT ;
    USE SIGNAL ;
    PORT
      LAYER M3 ;
        RECT  37.116 60.419 37.134 60.456 ;
    END
  END a[549]
  PIN a[54]
    DIRECTION INPUT ;
    USE SIGNAL ;
    PORT
      LAYER M5 ;
        RECT  54.864 60.372 54.888 60.456 ;
    END
  END a[54]
  PIN a[550]
    DIRECTION INPUT ;
    USE SIGNAL ;
    PORT
      LAYER M3 ;
        RECT  37.188 60.419 37.206 60.456 ;
    END
  END a[550]
  PIN a[551]
    DIRECTION INPUT ;
    USE SIGNAL ;
    PORT
      LAYER M3 ;
        RECT  37.26 60.419 37.278 60.456 ;
    END
  END a[551]
  PIN a[552]
    DIRECTION INPUT ;
    USE SIGNAL ;
    PORT
      LAYER M3 ;
        RECT  37.332 60.419 37.35 60.456 ;
    END
  END a[552]
  PIN a[553]
    DIRECTION INPUT ;
    USE SIGNAL ;
    PORT
      LAYER M3 ;
        RECT  37.404 60.419 37.422 60.456 ;
    END
  END a[553]
  PIN a[554]
    DIRECTION INPUT ;
    USE SIGNAL ;
    PORT
      LAYER M3 ;
        RECT  37.476 60.419 37.494 60.456 ;
    END
  END a[554]
  PIN a[555]
    DIRECTION INPUT ;
    USE SIGNAL ;
    PORT
      LAYER M3 ;
        RECT  37.548 60.419 37.566 60.456 ;
    END
  END a[555]
  PIN a[556]
    DIRECTION INPUT ;
    USE SIGNAL ;
    PORT
      LAYER M3 ;
        RECT  37.62 60.419 37.638 60.456 ;
    END
  END a[556]
  PIN a[557]
    DIRECTION INPUT ;
    USE SIGNAL ;
    PORT
      LAYER M3 ;
        RECT  37.692 60.419 37.71 60.456 ;
    END
  END a[557]
  PIN a[558]
    DIRECTION INPUT ;
    USE SIGNAL ;
    PORT
      LAYER M3 ;
        RECT  37.764 60.419 37.782 60.456 ;
    END
  END a[558]
  PIN a[559]
    DIRECTION INPUT ;
    USE SIGNAL ;
    PORT
      LAYER M3 ;
        RECT  37.836 60.419 37.854 60.456 ;
    END
  END a[559]
  PIN a[55]
    DIRECTION INPUT ;
    USE SIGNAL ;
    PORT
      LAYER M5 ;
        RECT  54.96 60.372 54.984 60.456 ;
    END
  END a[55]
  PIN a[560]
    DIRECTION INPUT ;
    USE SIGNAL ;
    PORT
      LAYER M3 ;
        RECT  37.908 60.419 37.926 60.456 ;
    END
  END a[560]
  PIN a[561]
    DIRECTION INPUT ;
    USE SIGNAL ;
    PORT
      LAYER M3 ;
        RECT  37.98 60.419 37.998 60.456 ;
    END
  END a[561]
  PIN a[562]
    DIRECTION INPUT ;
    USE SIGNAL ;
    PORT
      LAYER M3 ;
        RECT  38.052 60.419 38.07 60.456 ;
    END
  END a[562]
  PIN a[563]
    DIRECTION INPUT ;
    USE SIGNAL ;
    PORT
      LAYER M3 ;
        RECT  38.124 60.419 38.142 60.456 ;
    END
  END a[563]
  PIN a[564]
    DIRECTION INPUT ;
    USE SIGNAL ;
    PORT
      LAYER M3 ;
        RECT  38.196 60.419 38.214 60.456 ;
    END
  END a[564]
  PIN a[565]
    DIRECTION INPUT ;
    USE SIGNAL ;
    PORT
      LAYER M3 ;
        RECT  38.268 60.419 38.286 60.456 ;
    END
  END a[565]
  PIN a[566]
    DIRECTION INPUT ;
    USE SIGNAL ;
    PORT
      LAYER M3 ;
        RECT  38.34 60.419 38.358 60.456 ;
    END
  END a[566]
  PIN a[567]
    DIRECTION INPUT ;
    USE SIGNAL ;
    PORT
      LAYER M3 ;
        RECT  38.412 60.419 38.43 60.456 ;
    END
  END a[567]
  PIN a[568]
    DIRECTION INPUT ;
    USE SIGNAL ;
    PORT
      LAYER M3 ;
        RECT  38.484 60.419 38.502 60.456 ;
    END
  END a[568]
  PIN a[569]
    DIRECTION INPUT ;
    USE SIGNAL ;
    PORT
      LAYER M3 ;
        RECT  38.556 60.419 38.574 60.456 ;
    END
  END a[569]
  PIN a[56]
    DIRECTION INPUT ;
    USE SIGNAL ;
    PORT
      LAYER M5 ;
        RECT  55.056 60.372 55.08 60.456 ;
    END
  END a[56]
  PIN a[570]
    DIRECTION INPUT ;
    USE SIGNAL ;
    PORT
      LAYER M3 ;
        RECT  38.628 60.419 38.646 60.456 ;
    END
  END a[570]
  PIN a[571]
    DIRECTION INPUT ;
    USE SIGNAL ;
    PORT
      LAYER M3 ;
        RECT  38.7 60.419 38.718 60.456 ;
    END
  END a[571]
  PIN a[572]
    DIRECTION INPUT ;
    USE SIGNAL ;
    PORT
      LAYER M3 ;
        RECT  38.772 60.419 38.79 60.456 ;
    END
  END a[572]
  PIN a[573]
    DIRECTION INPUT ;
    USE SIGNAL ;
    PORT
      LAYER M3 ;
        RECT  38.844 60.419 38.862 60.456 ;
    END
  END a[573]
  PIN a[574]
    DIRECTION INPUT ;
    USE SIGNAL ;
    PORT
      LAYER M3 ;
        RECT  38.916 60.419 38.934 60.456 ;
    END
  END a[574]
  PIN a[575]
    DIRECTION INPUT ;
    USE SIGNAL ;
    PORT
      LAYER M3 ;
        RECT  38.988 60.419 39.006 60.456 ;
    END
  END a[575]
  PIN a[576]
    DIRECTION INPUT ;
    USE SIGNAL ;
    PORT
      LAYER M5 ;
        RECT  43.44 60.372 43.464 60.456 ;
    END
  END a[576]
  PIN a[577]
    DIRECTION INPUT ;
    USE SIGNAL ;
    PORT
      LAYER M5 ;
        RECT  43.536 60.372 43.56 60.456 ;
    END
  END a[577]
  PIN a[578]
    DIRECTION INPUT ;
    USE SIGNAL ;
    PORT
      LAYER M5 ;
        RECT  43.632 60.372 43.656 60.456 ;
    END
  END a[578]
  PIN a[579]
    DIRECTION INPUT ;
    USE SIGNAL ;
    PORT
      LAYER M5 ;
        RECT  43.728 60.372 43.752 60.456 ;
    END
  END a[579]
  PIN a[57]
    DIRECTION INPUT ;
    USE SIGNAL ;
    PORT
      LAYER M5 ;
        RECT  55.152 60.372 55.176 60.456 ;
    END
  END a[57]
  PIN a[580]
    DIRECTION INPUT ;
    USE SIGNAL ;
    PORT
      LAYER M5 ;
        RECT  43.824 60.372 43.848 60.456 ;
    END
  END a[580]
  PIN a[581]
    DIRECTION INPUT ;
    USE SIGNAL ;
    PORT
      LAYER M5 ;
        RECT  43.92 60.372 43.944 60.456 ;
    END
  END a[581]
  PIN a[582]
    DIRECTION INPUT ;
    USE SIGNAL ;
    PORT
      LAYER M5 ;
        RECT  44.016 60.372 44.04 60.456 ;
    END
  END a[582]
  PIN a[583]
    DIRECTION INPUT ;
    USE SIGNAL ;
    PORT
      LAYER M5 ;
        RECT  44.112 60.372 44.136 60.456 ;
    END
  END a[583]
  PIN a[584]
    DIRECTION INPUT ;
    USE SIGNAL ;
    PORT
      LAYER M5 ;
        RECT  44.208 60.372 44.232 60.456 ;
    END
  END a[584]
  PIN a[585]
    DIRECTION INPUT ;
    USE SIGNAL ;
    PORT
      LAYER M5 ;
        RECT  44.304 60.372 44.328 60.456 ;
    END
  END a[585]
  PIN a[586]
    DIRECTION INPUT ;
    USE SIGNAL ;
    PORT
      LAYER M5 ;
        RECT  44.4 60.372 44.424 60.456 ;
    END
  END a[586]
  PIN a[587]
    DIRECTION INPUT ;
    USE SIGNAL ;
    PORT
      LAYER M5 ;
        RECT  44.496 60.372 44.52 60.456 ;
    END
  END a[587]
  PIN a[588]
    DIRECTION INPUT ;
    USE SIGNAL ;
    PORT
      LAYER M5 ;
        RECT  44.592 60.372 44.616 60.456 ;
    END
  END a[588]
  PIN a[589]
    DIRECTION INPUT ;
    USE SIGNAL ;
    PORT
      LAYER M5 ;
        RECT  44.688 60.372 44.712 60.456 ;
    END
  END a[589]
  PIN a[58]
    DIRECTION INPUT ;
    USE SIGNAL ;
    PORT
      LAYER M5 ;
        RECT  55.248 60.372 55.272 60.456 ;
    END
  END a[58]
  PIN a[590]
    DIRECTION INPUT ;
    USE SIGNAL ;
    PORT
      LAYER M5 ;
        RECT  44.784 60.372 44.808 60.456 ;
    END
  END a[590]
  PIN a[591]
    DIRECTION INPUT ;
    USE SIGNAL ;
    PORT
      LAYER M5 ;
        RECT  44.88 60.372 44.904 60.456 ;
    END
  END a[591]
  PIN a[592]
    DIRECTION INPUT ;
    USE SIGNAL ;
    PORT
      LAYER M5 ;
        RECT  44.976 60.372 45 60.456 ;
    END
  END a[592]
  PIN a[593]
    DIRECTION INPUT ;
    USE SIGNAL ;
    PORT
      LAYER M5 ;
        RECT  45.072 60.372 45.096 60.456 ;
    END
  END a[593]
  PIN a[594]
    DIRECTION INPUT ;
    USE SIGNAL ;
    PORT
      LAYER M5 ;
        RECT  45.168 60.372 45.192 60.456 ;
    END
  END a[594]
  PIN a[595]
    DIRECTION INPUT ;
    USE SIGNAL ;
    PORT
      LAYER M5 ;
        RECT  45.264 60.372 45.288 60.456 ;
    END
  END a[595]
  PIN a[596]
    DIRECTION INPUT ;
    USE SIGNAL ;
    PORT
      LAYER M5 ;
        RECT  45.36 60.372 45.384 60.456 ;
    END
  END a[596]
  PIN a[597]
    DIRECTION INPUT ;
    USE SIGNAL ;
    PORT
      LAYER M5 ;
        RECT  45.456 60.372 45.48 60.456 ;
    END
  END a[597]
  PIN a[598]
    DIRECTION INPUT ;
    USE SIGNAL ;
    PORT
      LAYER M5 ;
        RECT  45.552 60.372 45.576 60.456 ;
    END
  END a[598]
  PIN a[599]
    DIRECTION INPUT ;
    USE SIGNAL ;
    PORT
      LAYER M5 ;
        RECT  45.648 60.372 45.672 60.456 ;
    END
  END a[599]
  PIN a[59]
    DIRECTION INPUT ;
    USE SIGNAL ;
    PORT
      LAYER M5 ;
        RECT  55.344 60.372 55.368 60.456 ;
    END
  END a[59]
  PIN a[5]
    DIRECTION INPUT ;
    USE SIGNAL ;
    PORT
      LAYER M3 ;
        RECT  58.428 60.419 58.446 60.456 ;
    END
  END a[5]
  PIN a[60]
    DIRECTION INPUT ;
    USE SIGNAL ;
    PORT
      LAYER M5 ;
        RECT  55.44 60.372 55.464 60.456 ;
    END
  END a[60]
  PIN a[61]
    DIRECTION INPUT ;
    USE SIGNAL ;
    PORT
      LAYER M5 ;
        RECT  55.536 60.372 55.56 60.456 ;
    END
  END a[61]
  PIN a[62]
    DIRECTION INPUT ;
    USE SIGNAL ;
    PORT
      LAYER M5 ;
        RECT  55.632 60.372 55.656 60.456 ;
    END
  END a[62]
  PIN a[63]
    DIRECTION INPUT ;
    USE SIGNAL ;
    PORT
      LAYER M5 ;
        RECT  55.728 60.372 55.752 60.456 ;
    END
  END a[63]
  PIN a[64]
    DIRECTION INPUT ;
    USE SIGNAL ;
    PORT
      LAYER M3 ;
        RECT  46.548 60.419 46.566 60.456 ;
    END
  END a[64]
  PIN a[65]
    DIRECTION INPUT ;
    USE SIGNAL ;
    PORT
      LAYER M3 ;
        RECT  46.62 60.419 46.638 60.456 ;
    END
  END a[65]
  PIN a[66]
    DIRECTION INPUT ;
    USE SIGNAL ;
    PORT
      LAYER M3 ;
        RECT  46.692 60.419 46.71 60.456 ;
    END
  END a[66]
  PIN a[67]
    DIRECTION INPUT ;
    USE SIGNAL ;
    PORT
      LAYER M3 ;
        RECT  46.764 60.419 46.782 60.456 ;
    END
  END a[67]
  PIN a[68]
    DIRECTION INPUT ;
    USE SIGNAL ;
    PORT
      LAYER M3 ;
        RECT  46.836 60.419 46.854 60.456 ;
    END
  END a[68]
  PIN a[69]
    DIRECTION INPUT ;
    USE SIGNAL ;
    PORT
      LAYER M3 ;
        RECT  46.908 60.419 46.926 60.456 ;
    END
  END a[69]
  PIN a[6]
    DIRECTION INPUT ;
    USE SIGNAL ;
    PORT
      LAYER M3 ;
        RECT  58.5 60.419 58.518 60.456 ;
    END
  END a[6]
  PIN a[70]
    DIRECTION INPUT ;
    USE SIGNAL ;
    PORT
      LAYER M3 ;
        RECT  46.98 60.419 46.998 60.456 ;
    END
  END a[70]
  PIN a[71]
    DIRECTION INPUT ;
    USE SIGNAL ;
    PORT
      LAYER M3 ;
        RECT  47.052 60.419 47.07 60.456 ;
    END
  END a[71]
  PIN a[72]
    DIRECTION INPUT ;
    USE SIGNAL ;
    PORT
      LAYER M3 ;
        RECT  47.124 60.419 47.142 60.456 ;
    END
  END a[72]
  PIN a[73]
    DIRECTION INPUT ;
    USE SIGNAL ;
    PORT
      LAYER M3 ;
        RECT  47.196 60.419 47.214 60.456 ;
    END
  END a[73]
  PIN a[74]
    DIRECTION INPUT ;
    USE SIGNAL ;
    PORT
      LAYER M3 ;
        RECT  47.268 60.419 47.286 60.456 ;
    END
  END a[74]
  PIN a[75]
    DIRECTION INPUT ;
    USE SIGNAL ;
    PORT
      LAYER M3 ;
        RECT  47.34 60.419 47.358 60.456 ;
    END
  END a[75]
  PIN a[76]
    DIRECTION INPUT ;
    USE SIGNAL ;
    PORT
      LAYER M3 ;
        RECT  47.412 60.419 47.43 60.456 ;
    END
  END a[76]
  PIN a[77]
    DIRECTION INPUT ;
    USE SIGNAL ;
    PORT
      LAYER M3 ;
        RECT  47.484 60.419 47.502 60.456 ;
    END
  END a[77]
  PIN a[78]
    DIRECTION INPUT ;
    USE SIGNAL ;
    PORT
      LAYER M3 ;
        RECT  47.556 60.419 47.574 60.456 ;
    END
  END a[78]
  PIN a[79]
    DIRECTION INPUT ;
    USE SIGNAL ;
    PORT
      LAYER M3 ;
        RECT  47.628 60.419 47.646 60.456 ;
    END
  END a[79]
  PIN a[7]
    DIRECTION INPUT ;
    USE SIGNAL ;
    PORT
      LAYER M3 ;
        RECT  58.572 60.419 58.59 60.456 ;
    END
  END a[7]
  PIN a[80]
    DIRECTION INPUT ;
    USE SIGNAL ;
    PORT
      LAYER M3 ;
        RECT  47.7 60.419 47.718 60.456 ;
    END
  END a[80]
  PIN a[81]
    DIRECTION INPUT ;
    USE SIGNAL ;
    PORT
      LAYER M3 ;
        RECT  47.772 60.419 47.79 60.456 ;
    END
  END a[81]
  PIN a[82]
    DIRECTION INPUT ;
    USE SIGNAL ;
    PORT
      LAYER M3 ;
        RECT  47.844 60.419 47.862 60.456 ;
    END
  END a[82]
  PIN a[83]
    DIRECTION INPUT ;
    USE SIGNAL ;
    PORT
      LAYER M3 ;
        RECT  47.916 60.419 47.934 60.456 ;
    END
  END a[83]
  PIN a[84]
    DIRECTION INPUT ;
    USE SIGNAL ;
    PORT
      LAYER M3 ;
        RECT  47.988 60.419 48.006 60.456 ;
    END
  END a[84]
  PIN a[85]
    DIRECTION INPUT ;
    USE SIGNAL ;
    PORT
      LAYER M3 ;
        RECT  48.06 60.419 48.078 60.456 ;
    END
  END a[85]
  PIN a[86]
    DIRECTION INPUT ;
    USE SIGNAL ;
    PORT
      LAYER M3 ;
        RECT  48.132 60.419 48.15 60.456 ;
    END
  END a[86]
  PIN a[87]
    DIRECTION INPUT ;
    USE SIGNAL ;
    PORT
      LAYER M3 ;
        RECT  48.204 60.419 48.222 60.456 ;
    END
  END a[87]
  PIN a[88]
    DIRECTION INPUT ;
    USE SIGNAL ;
    PORT
      LAYER M3 ;
        RECT  48.276 60.419 48.294 60.456 ;
    END
  END a[88]
  PIN a[89]
    DIRECTION INPUT ;
    USE SIGNAL ;
    PORT
      LAYER M3 ;
        RECT  48.348 60.419 48.366 60.456 ;
    END
  END a[89]
  PIN a[8]
    DIRECTION INPUT ;
    USE SIGNAL ;
    PORT
      LAYER M3 ;
        RECT  58.644 60.419 58.662 60.456 ;
    END
  END a[8]
  PIN a[90]
    DIRECTION INPUT ;
    USE SIGNAL ;
    PORT
      LAYER M3 ;
        RECT  48.42 60.419 48.438 60.456 ;
    END
  END a[90]
  PIN a[91]
    DIRECTION INPUT ;
    USE SIGNAL ;
    PORT
      LAYER M3 ;
        RECT  48.492 60.419 48.51 60.456 ;
    END
  END a[91]
  PIN a[92]
    DIRECTION INPUT ;
    USE SIGNAL ;
    PORT
      LAYER M3 ;
        RECT  48.564 60.419 48.582 60.456 ;
    END
  END a[92]
  PIN a[93]
    DIRECTION INPUT ;
    USE SIGNAL ;
    PORT
      LAYER M3 ;
        RECT  48.636 60.419 48.654 60.456 ;
    END
  END a[93]
  PIN a[94]
    DIRECTION INPUT ;
    USE SIGNAL ;
    PORT
      LAYER M3 ;
        RECT  48.708 60.419 48.726 60.456 ;
    END
  END a[94]
  PIN a[95]
    DIRECTION INPUT ;
    USE SIGNAL ;
    PORT
      LAYER M3 ;
        RECT  48.78 60.419 48.798 60.456 ;
    END
  END a[95]
  PIN a[96]
    DIRECTION INPUT ;
    USE SIGNAL ;
    PORT
      LAYER M3 ;
        RECT  55.764 60.419 55.782 60.456 ;
    END
  END a[96]
  PIN a[97]
    DIRECTION INPUT ;
    USE SIGNAL ;
    PORT
      LAYER M3 ;
        RECT  55.836 60.419 55.854 60.456 ;
    END
  END a[97]
  PIN a[98]
    DIRECTION INPUT ;
    USE SIGNAL ;
    PORT
      LAYER M3 ;
        RECT  55.908 60.419 55.926 60.456 ;
    END
  END a[98]
  PIN a[99]
    DIRECTION INPUT ;
    USE SIGNAL ;
    PORT
      LAYER M3 ;
        RECT  55.98 60.419 55.998 60.456 ;
    END
  END a[99]
  PIN a[9]
    DIRECTION INPUT ;
    USE SIGNAL ;
    PORT
      LAYER M3 ;
        RECT  58.716 60.419 58.734 60.456 ;
    END
  END a[9]
  PIN b[0]
    DIRECTION OUTPUT ;
    USE SIGNAL ;
    PORT
      LAYER M3 ;
        RECT  43.74 0 43.758 0.037 ;
    END
  END b[0]
  PIN b[100]
    DIRECTION OUTPUT ;
    USE SIGNAL ;
    PORT
      LAYER M3 ;
        RECT  46.332 0 46.35 0.037 ;
    END
  END b[100]
  PIN b[101]
    DIRECTION OUTPUT ;
    USE SIGNAL ;
    PORT
      LAYER M3 ;
        RECT  46.404 0 46.422 0.037 ;
    END
  END b[101]
  PIN b[102]
    DIRECTION OUTPUT ;
    USE SIGNAL ;
    PORT
      LAYER M3 ;
        RECT  46.476 0 46.494 0.037 ;
    END
  END b[102]
  PIN b[103]
    DIRECTION OUTPUT ;
    USE SIGNAL ;
    PORT
      LAYER M3 ;
        RECT  46.548 0 46.566 0.037 ;
    END
  END b[103]
  PIN b[104]
    DIRECTION OUTPUT ;
    USE SIGNAL ;
    PORT
      LAYER M3 ;
        RECT  46.62 0 46.638 0.037 ;
    END
  END b[104]
  PIN b[105]
    DIRECTION OUTPUT ;
    USE SIGNAL ;
    PORT
      LAYER M3 ;
        RECT  46.692 0 46.71 0.037 ;
    END
  END b[105]
  PIN b[106]
    DIRECTION OUTPUT ;
    USE SIGNAL ;
    PORT
      LAYER M3 ;
        RECT  46.764 0 46.782 0.037 ;
    END
  END b[106]
  PIN b[107]
    DIRECTION OUTPUT ;
    USE SIGNAL ;
    PORT
      LAYER M3 ;
        RECT  46.836 0 46.854 0.037 ;
    END
  END b[107]
  PIN b[108]
    DIRECTION OUTPUT ;
    USE SIGNAL ;
    PORT
      LAYER M3 ;
        RECT  46.908 0 46.926 0.037 ;
    END
  END b[108]
  PIN b[109]
    DIRECTION OUTPUT ;
    USE SIGNAL ;
    PORT
      LAYER M3 ;
        RECT  46.98 0 46.998 0.037 ;
    END
  END b[109]
  PIN b[10]
    DIRECTION OUTPUT ;
    USE SIGNAL ;
    PORT
      LAYER M3 ;
        RECT  44.46 0 44.478 0.037 ;
    END
  END b[10]
  PIN b[110]
    DIRECTION OUTPUT ;
    USE SIGNAL ;
    PORT
      LAYER M3 ;
        RECT  47.052 0 47.07 0.037 ;
    END
  END b[110]
  PIN b[111]
    DIRECTION OUTPUT ;
    USE SIGNAL ;
    PORT
      LAYER M3 ;
        RECT  47.124 0 47.142 0.037 ;
    END
  END b[111]
  PIN b[112]
    DIRECTION OUTPUT ;
    USE SIGNAL ;
    PORT
      LAYER M3 ;
        RECT  47.196 0 47.214 0.037 ;
    END
  END b[112]
  PIN b[113]
    DIRECTION OUTPUT ;
    USE SIGNAL ;
    PORT
      LAYER M3 ;
        RECT  47.268 0 47.286 0.037 ;
    END
  END b[113]
  PIN b[114]
    DIRECTION OUTPUT ;
    USE SIGNAL ;
    PORT
      LAYER M3 ;
        RECT  47.34 0 47.358 0.037 ;
    END
  END b[114]
  PIN b[115]
    DIRECTION OUTPUT ;
    USE SIGNAL ;
    PORT
      LAYER M3 ;
        RECT  47.412 0 47.43 0.037 ;
    END
  END b[115]
  PIN b[116]
    DIRECTION OUTPUT ;
    USE SIGNAL ;
    PORT
      LAYER M3 ;
        RECT  47.484 0 47.502 0.037 ;
    END
  END b[116]
  PIN b[117]
    DIRECTION OUTPUT ;
    USE SIGNAL ;
    PORT
      LAYER M3 ;
        RECT  47.556 0 47.574 0.037 ;
    END
  END b[117]
  PIN b[118]
    DIRECTION OUTPUT ;
    USE SIGNAL ;
    PORT
      LAYER M3 ;
        RECT  47.628 0 47.646 0.037 ;
    END
  END b[118]
  PIN b[119]
    DIRECTION OUTPUT ;
    USE SIGNAL ;
    PORT
      LAYER M3 ;
        RECT  47.7 0 47.718 0.037 ;
    END
  END b[119]
  PIN b[11]
    DIRECTION OUTPUT ;
    USE SIGNAL ;
    PORT
      LAYER M3 ;
        RECT  44.532 0 44.55 0.037 ;
    END
  END b[11]
  PIN b[120]
    DIRECTION OUTPUT ;
    USE SIGNAL ;
    PORT
      LAYER M3 ;
        RECT  47.772 0 47.79 0.037 ;
    END
  END b[120]
  PIN b[121]
    DIRECTION OUTPUT ;
    USE SIGNAL ;
    PORT
      LAYER M3 ;
        RECT  47.844 0 47.862 0.037 ;
    END
  END b[121]
  PIN b[122]
    DIRECTION OUTPUT ;
    USE SIGNAL ;
    PORT
      LAYER M3 ;
        RECT  47.916 0 47.934 0.037 ;
    END
  END b[122]
  PIN b[123]
    DIRECTION OUTPUT ;
    USE SIGNAL ;
    PORT
      LAYER M3 ;
        RECT  47.988 0 48.006 0.037 ;
    END
  END b[123]
  PIN b[124]
    DIRECTION OUTPUT ;
    USE SIGNAL ;
    PORT
      LAYER M3 ;
        RECT  48.06 0 48.078 0.037 ;
    END
  END b[124]
  PIN b[125]
    DIRECTION OUTPUT ;
    USE SIGNAL ;
    PORT
      LAYER M3 ;
        RECT  48.132 0 48.15 0.037 ;
    END
  END b[125]
  PIN b[126]
    DIRECTION OUTPUT ;
    USE SIGNAL ;
    PORT
      LAYER M3 ;
        RECT  48.204 0 48.222 0.037 ;
    END
  END b[126]
  PIN b[127]
    DIRECTION OUTPUT ;
    USE SIGNAL ;
    PORT
      LAYER M3 ;
        RECT  48.276 0 48.294 0.037 ;
    END
  END b[127]
  PIN b[128]
    DIRECTION OUTPUT ;
    USE SIGNAL ;
    PORT
      LAYER M3 ;
        RECT  55.26 0 55.278 0.037 ;
    END
  END b[128]
  PIN b[129]
    DIRECTION OUTPUT ;
    USE SIGNAL ;
    PORT
      LAYER M3 ;
        RECT  55.332 0 55.35 0.037 ;
    END
  END b[129]
  PIN b[12]
    DIRECTION OUTPUT ;
    USE SIGNAL ;
    PORT
      LAYER M3 ;
        RECT  44.604 0 44.622 0.037 ;
    END
  END b[12]
  PIN b[130]
    DIRECTION OUTPUT ;
    USE SIGNAL ;
    PORT
      LAYER M3 ;
        RECT  55.404 0 55.422 0.037 ;
    END
  END b[130]
  PIN b[131]
    DIRECTION OUTPUT ;
    USE SIGNAL ;
    PORT
      LAYER M3 ;
        RECT  55.476 0 55.494 0.037 ;
    END
  END b[131]
  PIN b[132]
    DIRECTION OUTPUT ;
    USE SIGNAL ;
    PORT
      LAYER M3 ;
        RECT  55.548 0 55.566 0.037 ;
    END
  END b[132]
  PIN b[133]
    DIRECTION OUTPUT ;
    USE SIGNAL ;
    PORT
      LAYER M3 ;
        RECT  55.62 0 55.638 0.037 ;
    END
  END b[133]
  PIN b[134]
    DIRECTION OUTPUT ;
    USE SIGNAL ;
    PORT
      LAYER M3 ;
        RECT  55.692 0 55.71 0.037 ;
    END
  END b[134]
  PIN b[135]
    DIRECTION OUTPUT ;
    USE SIGNAL ;
    PORT
      LAYER M3 ;
        RECT  55.764 0 55.782 0.037 ;
    END
  END b[135]
  PIN b[136]
    DIRECTION OUTPUT ;
    USE SIGNAL ;
    PORT
      LAYER M3 ;
        RECT  55.836 0 55.854 0.037 ;
    END
  END b[136]
  PIN b[137]
    DIRECTION OUTPUT ;
    USE SIGNAL ;
    PORT
      LAYER M3 ;
        RECT  55.908 0 55.926 0.037 ;
    END
  END b[137]
  PIN b[138]
    DIRECTION OUTPUT ;
    USE SIGNAL ;
    PORT
      LAYER M3 ;
        RECT  55.98 0 55.998 0.037 ;
    END
  END b[138]
  PIN b[139]
    DIRECTION OUTPUT ;
    USE SIGNAL ;
    PORT
      LAYER M3 ;
        RECT  56.052 0 56.07 0.037 ;
    END
  END b[139]
  PIN b[13]
    DIRECTION OUTPUT ;
    USE SIGNAL ;
    PORT
      LAYER M3 ;
        RECT  44.676 0 44.694 0.037 ;
    END
  END b[13]
  PIN b[140]
    DIRECTION OUTPUT ;
    USE SIGNAL ;
    PORT
      LAYER M3 ;
        RECT  56.124 0 56.142 0.037 ;
    END
  END b[140]
  PIN b[141]
    DIRECTION OUTPUT ;
    USE SIGNAL ;
    PORT
      LAYER M3 ;
        RECT  56.196 0 56.214 0.037 ;
    END
  END b[141]
  PIN b[142]
    DIRECTION OUTPUT ;
    USE SIGNAL ;
    PORT
      LAYER M3 ;
        RECT  56.268 0 56.286 0.037 ;
    END
  END b[142]
  PIN b[143]
    DIRECTION OUTPUT ;
    USE SIGNAL ;
    PORT
      LAYER M3 ;
        RECT  56.34 0 56.358 0.037 ;
    END
  END b[143]
  PIN b[144]
    DIRECTION OUTPUT ;
    USE SIGNAL ;
    PORT
      LAYER M3 ;
        RECT  56.412 0 56.43 0.037 ;
    END
  END b[144]
  PIN b[145]
    DIRECTION OUTPUT ;
    USE SIGNAL ;
    PORT
      LAYER M3 ;
        RECT  56.484 0 56.502 0.037 ;
    END
  END b[145]
  PIN b[146]
    DIRECTION OUTPUT ;
    USE SIGNAL ;
    PORT
      LAYER M3 ;
        RECT  56.556 0 56.574 0.037 ;
    END
  END b[146]
  PIN b[147]
    DIRECTION OUTPUT ;
    USE SIGNAL ;
    PORT
      LAYER M3 ;
        RECT  56.628 0 56.646 0.037 ;
    END
  END b[147]
  PIN b[148]
    DIRECTION OUTPUT ;
    USE SIGNAL ;
    PORT
      LAYER M3 ;
        RECT  56.7 0 56.718 0.037 ;
    END
  END b[148]
  PIN b[149]
    DIRECTION OUTPUT ;
    USE SIGNAL ;
    PORT
      LAYER M3 ;
        RECT  56.772 0 56.79 0.037 ;
    END
  END b[149]
  PIN b[14]
    DIRECTION OUTPUT ;
    USE SIGNAL ;
    PORT
      LAYER M3 ;
        RECT  44.748 0 44.766 0.037 ;
    END
  END b[14]
  PIN b[150]
    DIRECTION OUTPUT ;
    USE SIGNAL ;
    PORT
      LAYER M3 ;
        RECT  56.844 0 56.862 0.037 ;
    END
  END b[150]
  PIN b[151]
    DIRECTION OUTPUT ;
    USE SIGNAL ;
    PORT
      LAYER M3 ;
        RECT  56.916 0 56.934 0.037 ;
    END
  END b[151]
  PIN b[152]
    DIRECTION OUTPUT ;
    USE SIGNAL ;
    PORT
      LAYER M3 ;
        RECT  56.988 0 57.006 0.037 ;
    END
  END b[152]
  PIN b[153]
    DIRECTION OUTPUT ;
    USE SIGNAL ;
    PORT
      LAYER M3 ;
        RECT  57.06 0 57.078 0.037 ;
    END
  END b[153]
  PIN b[154]
    DIRECTION OUTPUT ;
    USE SIGNAL ;
    PORT
      LAYER M3 ;
        RECT  57.132 0 57.15 0.037 ;
    END
  END b[154]
  PIN b[155]
    DIRECTION OUTPUT ;
    USE SIGNAL ;
    PORT
      LAYER M3 ;
        RECT  57.204 0 57.222 0.037 ;
    END
  END b[155]
  PIN b[156]
    DIRECTION OUTPUT ;
    USE SIGNAL ;
    PORT
      LAYER M3 ;
        RECT  57.276 0 57.294 0.037 ;
    END
  END b[156]
  PIN b[157]
    DIRECTION OUTPUT ;
    USE SIGNAL ;
    PORT
      LAYER M3 ;
        RECT  57.348 0 57.366 0.037 ;
    END
  END b[157]
  PIN b[158]
    DIRECTION OUTPUT ;
    USE SIGNAL ;
    PORT
      LAYER M3 ;
        RECT  57.42 0 57.438 0.037 ;
    END
  END b[158]
  PIN b[159]
    DIRECTION OUTPUT ;
    USE SIGNAL ;
    PORT
      LAYER M3 ;
        RECT  57.492 0 57.51 0.037 ;
    END
  END b[159]
  PIN b[15]
    DIRECTION OUTPUT ;
    USE SIGNAL ;
    PORT
      LAYER M3 ;
        RECT  44.82 0 44.838 0.037 ;
    END
  END b[15]
  PIN b[160]
    DIRECTION OUTPUT ;
    USE SIGNAL ;
    PORT
      LAYER M5 ;
        RECT  48.336 0 48.36 0.084 ;
    END
  END b[160]
  PIN b[161]
    DIRECTION OUTPUT ;
    USE SIGNAL ;
    PORT
      LAYER M5 ;
        RECT  48.432 0 48.456 0.084 ;
    END
  END b[161]
  PIN b[162]
    DIRECTION OUTPUT ;
    USE SIGNAL ;
    PORT
      LAYER M5 ;
        RECT  48.528 0 48.552 0.084 ;
    END
  END b[162]
  PIN b[163]
    DIRECTION OUTPUT ;
    USE SIGNAL ;
    PORT
      LAYER M5 ;
        RECT  48.624 0 48.648 0.084 ;
    END
  END b[163]
  PIN b[164]
    DIRECTION OUTPUT ;
    USE SIGNAL ;
    PORT
      LAYER M5 ;
        RECT  48.72 0 48.744 0.084 ;
    END
  END b[164]
  PIN b[165]
    DIRECTION OUTPUT ;
    USE SIGNAL ;
    PORT
      LAYER M5 ;
        RECT  48.816 0 48.84 0.084 ;
    END
  END b[165]
  PIN b[166]
    DIRECTION OUTPUT ;
    USE SIGNAL ;
    PORT
      LAYER M5 ;
        RECT  48.912 0 48.936 0.084 ;
    END
  END b[166]
  PIN b[167]
    DIRECTION OUTPUT ;
    USE SIGNAL ;
    PORT
      LAYER M5 ;
        RECT  49.008 0 49.032 0.084 ;
    END
  END b[167]
  PIN b[168]
    DIRECTION OUTPUT ;
    USE SIGNAL ;
    PORT
      LAYER M5 ;
        RECT  49.104 0 49.128 0.084 ;
    END
  END b[168]
  PIN b[169]
    DIRECTION OUTPUT ;
    USE SIGNAL ;
    PORT
      LAYER M5 ;
        RECT  49.2 0 49.224 0.084 ;
    END
  END b[169]
  PIN b[16]
    DIRECTION OUTPUT ;
    USE SIGNAL ;
    PORT
      LAYER M3 ;
        RECT  44.892 0 44.91 0.037 ;
    END
  END b[16]
  PIN b[170]
    DIRECTION OUTPUT ;
    USE SIGNAL ;
    PORT
      LAYER M5 ;
        RECT  49.296 0 49.32 0.084 ;
    END
  END b[170]
  PIN b[171]
    DIRECTION OUTPUT ;
    USE SIGNAL ;
    PORT
      LAYER M5 ;
        RECT  49.392 0 49.416 0.084 ;
    END
  END b[171]
  PIN b[172]
    DIRECTION OUTPUT ;
    USE SIGNAL ;
    PORT
      LAYER M5 ;
        RECT  49.488 0 49.512 0.084 ;
    END
  END b[172]
  PIN b[173]
    DIRECTION OUTPUT ;
    USE SIGNAL ;
    PORT
      LAYER M5 ;
        RECT  49.584 0 49.608 0.084 ;
    END
  END b[173]
  PIN b[174]
    DIRECTION OUTPUT ;
    USE SIGNAL ;
    PORT
      LAYER M5 ;
        RECT  49.68 0 49.704 0.084 ;
    END
  END b[174]
  PIN b[175]
    DIRECTION OUTPUT ;
    USE SIGNAL ;
    PORT
      LAYER M5 ;
        RECT  49.776 0 49.8 0.084 ;
    END
  END b[175]
  PIN b[176]
    DIRECTION OUTPUT ;
    USE SIGNAL ;
    PORT
      LAYER M5 ;
        RECT  49.872 0 49.896 0.084 ;
    END
  END b[176]
  PIN b[177]
    DIRECTION OUTPUT ;
    USE SIGNAL ;
    PORT
      LAYER M5 ;
        RECT  49.968 0 49.992 0.084 ;
    END
  END b[177]
  PIN b[178]
    DIRECTION OUTPUT ;
    USE SIGNAL ;
    PORT
      LAYER M5 ;
        RECT  50.064 0 50.088 0.084 ;
    END
  END b[178]
  PIN b[179]
    DIRECTION OUTPUT ;
    USE SIGNAL ;
    PORT
      LAYER M5 ;
        RECT  50.16 0 50.184 0.084 ;
    END
  END b[179]
  PIN b[17]
    DIRECTION OUTPUT ;
    USE SIGNAL ;
    PORT
      LAYER M3 ;
        RECT  44.964 0 44.982 0.037 ;
    END
  END b[17]
  PIN b[180]
    DIRECTION OUTPUT ;
    USE SIGNAL ;
    PORT
      LAYER M5 ;
        RECT  50.256 0 50.28 0.084 ;
    END
  END b[180]
  PIN b[181]
    DIRECTION OUTPUT ;
    USE SIGNAL ;
    PORT
      LAYER M5 ;
        RECT  50.352 0 50.376 0.084 ;
    END
  END b[181]
  PIN b[182]
    DIRECTION OUTPUT ;
    USE SIGNAL ;
    PORT
      LAYER M5 ;
        RECT  50.448 0 50.472 0.084 ;
    END
  END b[182]
  PIN b[183]
    DIRECTION OUTPUT ;
    USE SIGNAL ;
    PORT
      LAYER M5 ;
        RECT  50.544 0 50.568 0.084 ;
    END
  END b[183]
  PIN b[184]
    DIRECTION OUTPUT ;
    USE SIGNAL ;
    PORT
      LAYER M5 ;
        RECT  50.64 0 50.664 0.084 ;
    END
  END b[184]
  PIN b[185]
    DIRECTION OUTPUT ;
    USE SIGNAL ;
    PORT
      LAYER M5 ;
        RECT  50.736 0 50.76 0.084 ;
    END
  END b[185]
  PIN b[186]
    DIRECTION OUTPUT ;
    USE SIGNAL ;
    PORT
      LAYER M5 ;
        RECT  50.832 0 50.856 0.084 ;
    END
  END b[186]
  PIN b[187]
    DIRECTION OUTPUT ;
    USE SIGNAL ;
    PORT
      LAYER M5 ;
        RECT  50.928 0 50.952 0.084 ;
    END
  END b[187]
  PIN b[188]
    DIRECTION OUTPUT ;
    USE SIGNAL ;
    PORT
      LAYER M5 ;
        RECT  51.024 0 51.048 0.084 ;
    END
  END b[188]
  PIN b[189]
    DIRECTION OUTPUT ;
    USE SIGNAL ;
    PORT
      LAYER M5 ;
        RECT  51.12 0 51.144 0.084 ;
    END
  END b[189]
  PIN b[18]
    DIRECTION OUTPUT ;
    USE SIGNAL ;
    PORT
      LAYER M3 ;
        RECT  45.036 0 45.054 0.037 ;
    END
  END b[18]
  PIN b[190]
    DIRECTION OUTPUT ;
    USE SIGNAL ;
    PORT
      LAYER M5 ;
        RECT  51.216 0 51.24 0.084 ;
    END
  END b[190]
  PIN b[191]
    DIRECTION OUTPUT ;
    USE SIGNAL ;
    PORT
      LAYER M5 ;
        RECT  51.312 0 51.336 0.084 ;
    END
  END b[191]
  PIN b[192]
    DIRECTION OUTPUT ;
    USE SIGNAL ;
    PORT
      LAYER M3 ;
        RECT  52.956 0 52.974 0.037 ;
    END
  END b[192]
  PIN b[193]
    DIRECTION OUTPUT ;
    USE SIGNAL ;
    PORT
      LAYER M3 ;
        RECT  53.028 0 53.046 0.037 ;
    END
  END b[193]
  PIN b[194]
    DIRECTION OUTPUT ;
    USE SIGNAL ;
    PORT
      LAYER M3 ;
        RECT  53.1 0 53.118 0.037 ;
    END
  END b[194]
  PIN b[195]
    DIRECTION OUTPUT ;
    USE SIGNAL ;
    PORT
      LAYER M3 ;
        RECT  53.172 0 53.19 0.037 ;
    END
  END b[195]
  PIN b[196]
    DIRECTION OUTPUT ;
    USE SIGNAL ;
    PORT
      LAYER M3 ;
        RECT  53.244 0 53.262 0.037 ;
    END
  END b[196]
  PIN b[197]
    DIRECTION OUTPUT ;
    USE SIGNAL ;
    PORT
      LAYER M3 ;
        RECT  53.316 0 53.334 0.037 ;
    END
  END b[197]
  PIN b[198]
    DIRECTION OUTPUT ;
    USE SIGNAL ;
    PORT
      LAYER M3 ;
        RECT  53.388 0 53.406 0.037 ;
    END
  END b[198]
  PIN b[199]
    DIRECTION OUTPUT ;
    USE SIGNAL ;
    PORT
      LAYER M3 ;
        RECT  53.46 0 53.478 0.037 ;
    END
  END b[199]
  PIN b[19]
    DIRECTION OUTPUT ;
    USE SIGNAL ;
    PORT
      LAYER M3 ;
        RECT  45.108 0 45.126 0.037 ;
    END
  END b[19]
  PIN b[1]
    DIRECTION OUTPUT ;
    USE SIGNAL ;
    PORT
      LAYER M3 ;
        RECT  43.812 0 43.83 0.037 ;
    END
  END b[1]
  PIN b[200]
    DIRECTION OUTPUT ;
    USE SIGNAL ;
    PORT
      LAYER M3 ;
        RECT  53.532 0 53.55 0.037 ;
    END
  END b[200]
  PIN b[201]
    DIRECTION OUTPUT ;
    USE SIGNAL ;
    PORT
      LAYER M3 ;
        RECT  53.604 0 53.622 0.037 ;
    END
  END b[201]
  PIN b[202]
    DIRECTION OUTPUT ;
    USE SIGNAL ;
    PORT
      LAYER M3 ;
        RECT  53.676 0 53.694 0.037 ;
    END
  END b[202]
  PIN b[203]
    DIRECTION OUTPUT ;
    USE SIGNAL ;
    PORT
      LAYER M3 ;
        RECT  53.748 0 53.766 0.037 ;
    END
  END b[203]
  PIN b[204]
    DIRECTION OUTPUT ;
    USE SIGNAL ;
    PORT
      LAYER M3 ;
        RECT  53.82 0 53.838 0.037 ;
    END
  END b[204]
  PIN b[205]
    DIRECTION OUTPUT ;
    USE SIGNAL ;
    PORT
      LAYER M3 ;
        RECT  53.892 0 53.91 0.037 ;
    END
  END b[205]
  PIN b[206]
    DIRECTION OUTPUT ;
    USE SIGNAL ;
    PORT
      LAYER M3 ;
        RECT  53.964 0 53.982 0.037 ;
    END
  END b[206]
  PIN b[207]
    DIRECTION OUTPUT ;
    USE SIGNAL ;
    PORT
      LAYER M3 ;
        RECT  54.036 0 54.054 0.037 ;
    END
  END b[207]
  PIN b[208]
    DIRECTION OUTPUT ;
    USE SIGNAL ;
    PORT
      LAYER M3 ;
        RECT  54.108 0 54.126 0.037 ;
    END
  END b[208]
  PIN b[209]
    DIRECTION OUTPUT ;
    USE SIGNAL ;
    PORT
      LAYER M3 ;
        RECT  54.18 0 54.198 0.037 ;
    END
  END b[209]
  PIN b[20]
    DIRECTION OUTPUT ;
    USE SIGNAL ;
    PORT
      LAYER M3 ;
        RECT  45.18 0 45.198 0.037 ;
    END
  END b[20]
  PIN b[210]
    DIRECTION OUTPUT ;
    USE SIGNAL ;
    PORT
      LAYER M3 ;
        RECT  54.252 0 54.27 0.037 ;
    END
  END b[210]
  PIN b[211]
    DIRECTION OUTPUT ;
    USE SIGNAL ;
    PORT
      LAYER M3 ;
        RECT  54.324 0 54.342 0.037 ;
    END
  END b[211]
  PIN b[212]
    DIRECTION OUTPUT ;
    USE SIGNAL ;
    PORT
      LAYER M3 ;
        RECT  54.396 0 54.414 0.037 ;
    END
  END b[212]
  PIN b[213]
    DIRECTION OUTPUT ;
    USE SIGNAL ;
    PORT
      LAYER M3 ;
        RECT  54.468 0 54.486 0.037 ;
    END
  END b[213]
  PIN b[214]
    DIRECTION OUTPUT ;
    USE SIGNAL ;
    PORT
      LAYER M3 ;
        RECT  54.54 0 54.558 0.037 ;
    END
  END b[214]
  PIN b[215]
    DIRECTION OUTPUT ;
    USE SIGNAL ;
    PORT
      LAYER M3 ;
        RECT  54.612 0 54.63 0.037 ;
    END
  END b[215]
  PIN b[216]
    DIRECTION OUTPUT ;
    USE SIGNAL ;
    PORT
      LAYER M3 ;
        RECT  54.684 0 54.702 0.037 ;
    END
  END b[216]
  PIN b[217]
    DIRECTION OUTPUT ;
    USE SIGNAL ;
    PORT
      LAYER M3 ;
        RECT  54.756 0 54.774 0.037 ;
    END
  END b[217]
  PIN b[218]
    DIRECTION OUTPUT ;
    USE SIGNAL ;
    PORT
      LAYER M3 ;
        RECT  54.828 0 54.846 0.037 ;
    END
  END b[218]
  PIN b[219]
    DIRECTION OUTPUT ;
    USE SIGNAL ;
    PORT
      LAYER M3 ;
        RECT  54.9 0 54.918 0.037 ;
    END
  END b[219]
  PIN b[21]
    DIRECTION OUTPUT ;
    USE SIGNAL ;
    PORT
      LAYER M3 ;
        RECT  45.252 0 45.27 0.037 ;
    END
  END b[21]
  PIN b[220]
    DIRECTION OUTPUT ;
    USE SIGNAL ;
    PORT
      LAYER M3 ;
        RECT  54.972 0 54.99 0.037 ;
    END
  END b[220]
  PIN b[221]
    DIRECTION OUTPUT ;
    USE SIGNAL ;
    PORT
      LAYER M3 ;
        RECT  55.044 0 55.062 0.037 ;
    END
  END b[221]
  PIN b[222]
    DIRECTION OUTPUT ;
    USE SIGNAL ;
    PORT
      LAYER M3 ;
        RECT  55.116 0 55.134 0.037 ;
    END
  END b[222]
  PIN b[223]
    DIRECTION OUTPUT ;
    USE SIGNAL ;
    PORT
      LAYER M3 ;
        RECT  55.188 0 55.206 0.037 ;
    END
  END b[223]
  PIN b[224]
    DIRECTION OUTPUT ;
    USE SIGNAL ;
    PORT
      LAYER M3 ;
        RECT  48.348 0 48.366 0.037 ;
    END
  END b[224]
  PIN b[225]
    DIRECTION OUTPUT ;
    USE SIGNAL ;
    PORT
      LAYER M3 ;
        RECT  48.42 0 48.438 0.037 ;
    END
  END b[225]
  PIN b[226]
    DIRECTION OUTPUT ;
    USE SIGNAL ;
    PORT
      LAYER M3 ;
        RECT  48.492 0 48.51 0.037 ;
    END
  END b[226]
  PIN b[227]
    DIRECTION OUTPUT ;
    USE SIGNAL ;
    PORT
      LAYER M3 ;
        RECT  48.564 0 48.582 0.037 ;
    END
  END b[227]
  PIN b[228]
    DIRECTION OUTPUT ;
    USE SIGNAL ;
    PORT
      LAYER M3 ;
        RECT  48.636 0 48.654 0.037 ;
    END
  END b[228]
  PIN b[229]
    DIRECTION OUTPUT ;
    USE SIGNAL ;
    PORT
      LAYER M3 ;
        RECT  48.708 0 48.726 0.037 ;
    END
  END b[229]
  PIN b[22]
    DIRECTION OUTPUT ;
    USE SIGNAL ;
    PORT
      LAYER M3 ;
        RECT  45.324 0 45.342 0.037 ;
    END
  END b[22]
  PIN b[230]
    DIRECTION OUTPUT ;
    USE SIGNAL ;
    PORT
      LAYER M3 ;
        RECT  48.78 0 48.798 0.037 ;
    END
  END b[230]
  PIN b[231]
    DIRECTION OUTPUT ;
    USE SIGNAL ;
    PORT
      LAYER M3 ;
        RECT  48.852 0 48.87 0.037 ;
    END
  END b[231]
  PIN b[232]
    DIRECTION OUTPUT ;
    USE SIGNAL ;
    PORT
      LAYER M3 ;
        RECT  48.924 0 48.942 0.037 ;
    END
  END b[232]
  PIN b[233]
    DIRECTION OUTPUT ;
    USE SIGNAL ;
    PORT
      LAYER M3 ;
        RECT  48.996 0 49.014 0.037 ;
    END
  END b[233]
  PIN b[234]
    DIRECTION OUTPUT ;
    USE SIGNAL ;
    PORT
      LAYER M3 ;
        RECT  49.068 0 49.086 0.037 ;
    END
  END b[234]
  PIN b[235]
    DIRECTION OUTPUT ;
    USE SIGNAL ;
    PORT
      LAYER M3 ;
        RECT  49.14 0 49.158 0.037 ;
    END
  END b[235]
  PIN b[236]
    DIRECTION OUTPUT ;
    USE SIGNAL ;
    PORT
      LAYER M3 ;
        RECT  49.212 0 49.23 0.037 ;
    END
  END b[236]
  PIN b[237]
    DIRECTION OUTPUT ;
    USE SIGNAL ;
    PORT
      LAYER M3 ;
        RECT  49.284 0 49.302 0.037 ;
    END
  END b[237]
  PIN b[238]
    DIRECTION OUTPUT ;
    USE SIGNAL ;
    PORT
      LAYER M3 ;
        RECT  49.356 0 49.374 0.037 ;
    END
  END b[238]
  PIN b[239]
    DIRECTION OUTPUT ;
    USE SIGNAL ;
    PORT
      LAYER M3 ;
        RECT  49.428 0 49.446 0.037 ;
    END
  END b[239]
  PIN b[23]
    DIRECTION OUTPUT ;
    USE SIGNAL ;
    PORT
      LAYER M3 ;
        RECT  45.396 0 45.414 0.037 ;
    END
  END b[23]
  PIN b[240]
    DIRECTION OUTPUT ;
    USE SIGNAL ;
    PORT
      LAYER M3 ;
        RECT  49.5 0 49.518 0.037 ;
    END
  END b[240]
  PIN b[241]
    DIRECTION OUTPUT ;
    USE SIGNAL ;
    PORT
      LAYER M3 ;
        RECT  49.572 0 49.59 0.037 ;
    END
  END b[241]
  PIN b[242]
    DIRECTION OUTPUT ;
    USE SIGNAL ;
    PORT
      LAYER M3 ;
        RECT  49.644 0 49.662 0.037 ;
    END
  END b[242]
  PIN b[243]
    DIRECTION OUTPUT ;
    USE SIGNAL ;
    PORT
      LAYER M3 ;
        RECT  49.716 0 49.734 0.037 ;
    END
  END b[243]
  PIN b[244]
    DIRECTION OUTPUT ;
    USE SIGNAL ;
    PORT
      LAYER M3 ;
        RECT  49.788 0 49.806 0.037 ;
    END
  END b[244]
  PIN b[245]
    DIRECTION OUTPUT ;
    USE SIGNAL ;
    PORT
      LAYER M3 ;
        RECT  49.86 0 49.878 0.037 ;
    END
  END b[245]
  PIN b[246]
    DIRECTION OUTPUT ;
    USE SIGNAL ;
    PORT
      LAYER M3 ;
        RECT  49.932 0 49.95 0.037 ;
    END
  END b[246]
  PIN b[247]
    DIRECTION OUTPUT ;
    USE SIGNAL ;
    PORT
      LAYER M3 ;
        RECT  50.004 0 50.022 0.037 ;
    END
  END b[247]
  PIN b[248]
    DIRECTION OUTPUT ;
    USE SIGNAL ;
    PORT
      LAYER M3 ;
        RECT  50.076 0 50.094 0.037 ;
    END
  END b[248]
  PIN b[249]
    DIRECTION OUTPUT ;
    USE SIGNAL ;
    PORT
      LAYER M3 ;
        RECT  50.148 0 50.166 0.037 ;
    END
  END b[249]
  PIN b[24]
    DIRECTION OUTPUT ;
    USE SIGNAL ;
    PORT
      LAYER M3 ;
        RECT  45.468 0 45.486 0.037 ;
    END
  END b[24]
  PIN b[250]
    DIRECTION OUTPUT ;
    USE SIGNAL ;
    PORT
      LAYER M3 ;
        RECT  50.22 0 50.238 0.037 ;
    END
  END b[250]
  PIN b[251]
    DIRECTION OUTPUT ;
    USE SIGNAL ;
    PORT
      LAYER M3 ;
        RECT  50.292 0 50.31 0.037 ;
    END
  END b[251]
  PIN b[252]
    DIRECTION OUTPUT ;
    USE SIGNAL ;
    PORT
      LAYER M3 ;
        RECT  50.364 0 50.382 0.037 ;
    END
  END b[252]
  PIN b[253]
    DIRECTION OUTPUT ;
    USE SIGNAL ;
    PORT
      LAYER M3 ;
        RECT  50.436 0 50.454 0.037 ;
    END
  END b[253]
  PIN b[254]
    DIRECTION OUTPUT ;
    USE SIGNAL ;
    PORT
      LAYER M3 ;
        RECT  50.508 0 50.526 0.037 ;
    END
  END b[254]
  PIN b[255]
    DIRECTION OUTPUT ;
    USE SIGNAL ;
    PORT
      LAYER M3 ;
        RECT  50.58 0 50.598 0.037 ;
    END
  END b[255]
  PIN b[256]
    DIRECTION OUTPUT ;
    USE SIGNAL ;
    PORT
      LAYER M3 ;
        RECT  62.748 0 62.766 0.037 ;
    END
  END b[256]
  PIN b[257]
    DIRECTION OUTPUT ;
    USE SIGNAL ;
    PORT
      LAYER M3 ;
        RECT  62.82 0 62.838 0.037 ;
    END
  END b[257]
  PIN b[258]
    DIRECTION OUTPUT ;
    USE SIGNAL ;
    PORT
      LAYER M3 ;
        RECT  62.892 0 62.91 0.037 ;
    END
  END b[258]
  PIN b[259]
    DIRECTION OUTPUT ;
    USE SIGNAL ;
    PORT
      LAYER M3 ;
        RECT  62.964 0 62.982 0.037 ;
    END
  END b[259]
  PIN b[25]
    DIRECTION OUTPUT ;
    USE SIGNAL ;
    PORT
      LAYER M3 ;
        RECT  45.54 0 45.558 0.037 ;
    END
  END b[25]
  PIN b[260]
    DIRECTION OUTPUT ;
    USE SIGNAL ;
    PORT
      LAYER M3 ;
        RECT  63.036 0 63.054 0.037 ;
    END
  END b[260]
  PIN b[261]
    DIRECTION OUTPUT ;
    USE SIGNAL ;
    PORT
      LAYER M3 ;
        RECT  63.108 0 63.126 0.037 ;
    END
  END b[261]
  PIN b[262]
    DIRECTION OUTPUT ;
    USE SIGNAL ;
    PORT
      LAYER M3 ;
        RECT  63.18 0 63.198 0.037 ;
    END
  END b[262]
  PIN b[263]
    DIRECTION OUTPUT ;
    USE SIGNAL ;
    PORT
      LAYER M3 ;
        RECT  63.252 0 63.27 0.037 ;
    END
  END b[263]
  PIN b[264]
    DIRECTION OUTPUT ;
    USE SIGNAL ;
    PORT
      LAYER M3 ;
        RECT  63.324 0 63.342 0.037 ;
    END
  END b[264]
  PIN b[265]
    DIRECTION OUTPUT ;
    USE SIGNAL ;
    PORT
      LAYER M3 ;
        RECT  63.396 0 63.414 0.037 ;
    END
  END b[265]
  PIN b[266]
    DIRECTION OUTPUT ;
    USE SIGNAL ;
    PORT
      LAYER M3 ;
        RECT  63.468 0 63.486 0.037 ;
    END
  END b[266]
  PIN b[267]
    DIRECTION OUTPUT ;
    USE SIGNAL ;
    PORT
      LAYER M3 ;
        RECT  63.54 0 63.558 0.037 ;
    END
  END b[267]
  PIN b[268]
    DIRECTION OUTPUT ;
    USE SIGNAL ;
    PORT
      LAYER M3 ;
        RECT  63.612 0 63.63 0.037 ;
    END
  END b[268]
  PIN b[269]
    DIRECTION OUTPUT ;
    USE SIGNAL ;
    PORT
      LAYER M3 ;
        RECT  63.684 0 63.702 0.037 ;
    END
  END b[269]
  PIN b[26]
    DIRECTION OUTPUT ;
    USE SIGNAL ;
    PORT
      LAYER M3 ;
        RECT  45.612 0 45.63 0.037 ;
    END
  END b[26]
  PIN b[270]
    DIRECTION OUTPUT ;
    USE SIGNAL ;
    PORT
      LAYER M3 ;
        RECT  63.756 0 63.774 0.037 ;
    END
  END b[270]
  PIN b[271]
    DIRECTION OUTPUT ;
    USE SIGNAL ;
    PORT
      LAYER M3 ;
        RECT  63.828 0 63.846 0.037 ;
    END
  END b[271]
  PIN b[272]
    DIRECTION OUTPUT ;
    USE SIGNAL ;
    PORT
      LAYER M3 ;
        RECT  63.9 0 63.918 0.037 ;
    END
  END b[272]
  PIN b[273]
    DIRECTION OUTPUT ;
    USE SIGNAL ;
    PORT
      LAYER M3 ;
        RECT  63.972 0 63.99 0.037 ;
    END
  END b[273]
  PIN b[274]
    DIRECTION OUTPUT ;
    USE SIGNAL ;
    PORT
      LAYER M3 ;
        RECT  64.044 0 64.062 0.037 ;
    END
  END b[274]
  PIN b[275]
    DIRECTION OUTPUT ;
    USE SIGNAL ;
    PORT
      LAYER M3 ;
        RECT  64.116 0 64.134 0.037 ;
    END
  END b[275]
  PIN b[276]
    DIRECTION OUTPUT ;
    USE SIGNAL ;
    PORT
      LAYER M3 ;
        RECT  64.188 0 64.206 0.037 ;
    END
  END b[276]
  PIN b[277]
    DIRECTION OUTPUT ;
    USE SIGNAL ;
    PORT
      LAYER M3 ;
        RECT  64.26 0 64.278 0.037 ;
    END
  END b[277]
  PIN b[278]
    DIRECTION OUTPUT ;
    USE SIGNAL ;
    PORT
      LAYER M3 ;
        RECT  64.332 0 64.35 0.037 ;
    END
  END b[278]
  PIN b[279]
    DIRECTION OUTPUT ;
    USE SIGNAL ;
    PORT
      LAYER M3 ;
        RECT  64.404 0 64.422 0.037 ;
    END
  END b[279]
  PIN b[27]
    DIRECTION OUTPUT ;
    USE SIGNAL ;
    PORT
      LAYER M3 ;
        RECT  45.684 0 45.702 0.037 ;
    END
  END b[27]
  PIN b[280]
    DIRECTION OUTPUT ;
    USE SIGNAL ;
    PORT
      LAYER M3 ;
        RECT  64.476 0 64.494 0.037 ;
    END
  END b[280]
  PIN b[281]
    DIRECTION OUTPUT ;
    USE SIGNAL ;
    PORT
      LAYER M3 ;
        RECT  64.548 0 64.566 0.037 ;
    END
  END b[281]
  PIN b[282]
    DIRECTION OUTPUT ;
    USE SIGNAL ;
    PORT
      LAYER M3 ;
        RECT  64.62 0 64.638 0.037 ;
    END
  END b[282]
  PIN b[283]
    DIRECTION OUTPUT ;
    USE SIGNAL ;
    PORT
      LAYER M3 ;
        RECT  64.692 0 64.71 0.037 ;
    END
  END b[283]
  PIN b[284]
    DIRECTION OUTPUT ;
    USE SIGNAL ;
    PORT
      LAYER M3 ;
        RECT  64.764 0 64.782 0.037 ;
    END
  END b[284]
  PIN b[285]
    DIRECTION OUTPUT ;
    USE SIGNAL ;
    PORT
      LAYER M3 ;
        RECT  64.836 0 64.854 0.037 ;
    END
  END b[285]
  PIN b[286]
    DIRECTION OUTPUT ;
    USE SIGNAL ;
    PORT
      LAYER M3 ;
        RECT  64.908 0 64.926 0.037 ;
    END
  END b[286]
  PIN b[287]
    DIRECTION OUTPUT ;
    USE SIGNAL ;
    PORT
      LAYER M3 ;
        RECT  64.98 0 64.998 0.037 ;
    END
  END b[287]
  PIN b[288]
    DIRECTION OUTPUT ;
    USE SIGNAL ;
    PORT
      LAYER M5 ;
        RECT  54.48 0 54.504 0.084 ;
    END
  END b[288]
  PIN b[289]
    DIRECTION OUTPUT ;
    USE SIGNAL ;
    PORT
      LAYER M5 ;
        RECT  54.576 0 54.6 0.084 ;
    END
  END b[289]
  PIN b[28]
    DIRECTION OUTPUT ;
    USE SIGNAL ;
    PORT
      LAYER M3 ;
        RECT  45.756 0 45.774 0.037 ;
    END
  END b[28]
  PIN b[290]
    DIRECTION OUTPUT ;
    USE SIGNAL ;
    PORT
      LAYER M5 ;
        RECT  54.672 0 54.696 0.084 ;
    END
  END b[290]
  PIN b[291]
    DIRECTION OUTPUT ;
    USE SIGNAL ;
    PORT
      LAYER M5 ;
        RECT  54.768 0 54.792 0.084 ;
    END
  END b[291]
  PIN b[292]
    DIRECTION OUTPUT ;
    USE SIGNAL ;
    PORT
      LAYER M5 ;
        RECT  54.864 0 54.888 0.084 ;
    END
  END b[292]
  PIN b[293]
    DIRECTION OUTPUT ;
    USE SIGNAL ;
    PORT
      LAYER M5 ;
        RECT  54.96 0 54.984 0.084 ;
    END
  END b[293]
  PIN b[294]
    DIRECTION OUTPUT ;
    USE SIGNAL ;
    PORT
      LAYER M5 ;
        RECT  55.056 0 55.08 0.084 ;
    END
  END b[294]
  PIN b[295]
    DIRECTION OUTPUT ;
    USE SIGNAL ;
    PORT
      LAYER M5 ;
        RECT  55.152 0 55.176 0.084 ;
    END
  END b[295]
  PIN b[296]
    DIRECTION OUTPUT ;
    USE SIGNAL ;
    PORT
      LAYER M5 ;
        RECT  55.248 0 55.272 0.084 ;
    END
  END b[296]
  PIN b[297]
    DIRECTION OUTPUT ;
    USE SIGNAL ;
    PORT
      LAYER M5 ;
        RECT  55.344 0 55.368 0.084 ;
    END
  END b[297]
  PIN b[298]
    DIRECTION OUTPUT ;
    USE SIGNAL ;
    PORT
      LAYER M5 ;
        RECT  55.44 0 55.464 0.084 ;
    END
  END b[298]
  PIN b[299]
    DIRECTION OUTPUT ;
    USE SIGNAL ;
    PORT
      LAYER M5 ;
        RECT  55.536 0 55.56 0.084 ;
    END
  END b[299]
  PIN b[29]
    DIRECTION OUTPUT ;
    USE SIGNAL ;
    PORT
      LAYER M3 ;
        RECT  45.828 0 45.846 0.037 ;
    END
  END b[29]
  PIN b[2]
    DIRECTION OUTPUT ;
    USE SIGNAL ;
    PORT
      LAYER M3 ;
        RECT  43.884 0 43.902 0.037 ;
    END
  END b[2]
  PIN b[300]
    DIRECTION OUTPUT ;
    USE SIGNAL ;
    PORT
      LAYER M5 ;
        RECT  55.632 0 55.656 0.084 ;
    END
  END b[300]
  PIN b[301]
    DIRECTION OUTPUT ;
    USE SIGNAL ;
    PORT
      LAYER M5 ;
        RECT  55.728 0 55.752 0.084 ;
    END
  END b[301]
  PIN b[302]
    DIRECTION OUTPUT ;
    USE SIGNAL ;
    PORT
      LAYER M5 ;
        RECT  55.824 0 55.848 0.084 ;
    END
  END b[302]
  PIN b[303]
    DIRECTION OUTPUT ;
    USE SIGNAL ;
    PORT
      LAYER M5 ;
        RECT  55.92 0 55.944 0.084 ;
    END
  END b[303]
  PIN b[304]
    DIRECTION OUTPUT ;
    USE SIGNAL ;
    PORT
      LAYER M5 ;
        RECT  56.016 0 56.04 0.084 ;
    END
  END b[304]
  PIN b[305]
    DIRECTION OUTPUT ;
    USE SIGNAL ;
    PORT
      LAYER M5 ;
        RECT  56.112 0 56.136 0.084 ;
    END
  END b[305]
  PIN b[306]
    DIRECTION OUTPUT ;
    USE SIGNAL ;
    PORT
      LAYER M5 ;
        RECT  56.208 0 56.232 0.084 ;
    END
  END b[306]
  PIN b[307]
    DIRECTION OUTPUT ;
    USE SIGNAL ;
    PORT
      LAYER M5 ;
        RECT  56.304 0 56.328 0.084 ;
    END
  END b[307]
  PIN b[308]
    DIRECTION OUTPUT ;
    USE SIGNAL ;
    PORT
      LAYER M5 ;
        RECT  56.4 0 56.424 0.084 ;
    END
  END b[308]
  PIN b[309]
    DIRECTION OUTPUT ;
    USE SIGNAL ;
    PORT
      LAYER M5 ;
        RECT  56.496 0 56.52 0.084 ;
    END
  END b[309]
  PIN b[30]
    DIRECTION OUTPUT ;
    USE SIGNAL ;
    PORT
      LAYER M3 ;
        RECT  45.9 0 45.918 0.037 ;
    END
  END b[30]
  PIN b[310]
    DIRECTION OUTPUT ;
    USE SIGNAL ;
    PORT
      LAYER M5 ;
        RECT  56.592 0 56.616 0.084 ;
    END
  END b[310]
  PIN b[311]
    DIRECTION OUTPUT ;
    USE SIGNAL ;
    PORT
      LAYER M5 ;
        RECT  56.688 0 56.712 0.084 ;
    END
  END b[311]
  PIN b[312]
    DIRECTION OUTPUT ;
    USE SIGNAL ;
    PORT
      LAYER M5 ;
        RECT  56.784 0 56.808 0.084 ;
    END
  END b[312]
  PIN b[313]
    DIRECTION OUTPUT ;
    USE SIGNAL ;
    PORT
      LAYER M5 ;
        RECT  56.88 0 56.904 0.084 ;
    END
  END b[313]
  PIN b[314]
    DIRECTION OUTPUT ;
    USE SIGNAL ;
    PORT
      LAYER M5 ;
        RECT  56.976 0 57 0.084 ;
    END
  END b[314]
  PIN b[315]
    DIRECTION OUTPUT ;
    USE SIGNAL ;
    PORT
      LAYER M5 ;
        RECT  57.072 0 57.096 0.084 ;
    END
  END b[315]
  PIN b[316]
    DIRECTION OUTPUT ;
    USE SIGNAL ;
    PORT
      LAYER M5 ;
        RECT  57.168 0 57.192 0.084 ;
    END
  END b[316]
  PIN b[317]
    DIRECTION OUTPUT ;
    USE SIGNAL ;
    PORT
      LAYER M5 ;
        RECT  57.264 0 57.288 0.084 ;
    END
  END b[317]
  PIN b[318]
    DIRECTION OUTPUT ;
    USE SIGNAL ;
    PORT
      LAYER M5 ;
        RECT  57.36 0 57.384 0.084 ;
    END
  END b[318]
  PIN b[319]
    DIRECTION OUTPUT ;
    USE SIGNAL ;
    PORT
      LAYER M5 ;
        RECT  57.456 0 57.48 0.084 ;
    END
  END b[319]
  PIN b[31]
    DIRECTION OUTPUT ;
    USE SIGNAL ;
    PORT
      LAYER M3 ;
        RECT  45.972 0 45.99 0.037 ;
    END
  END b[31]
  PIN b[320]
    DIRECTION OUTPUT ;
    USE SIGNAL ;
    PORT
      LAYER M3 ;
        RECT  67.356 0 67.374 0.037 ;
    END
  END b[320]
  PIN b[321]
    DIRECTION OUTPUT ;
    USE SIGNAL ;
    PORT
      LAYER M3 ;
        RECT  67.428 0 67.446 0.037 ;
    END
  END b[321]
  PIN b[322]
    DIRECTION OUTPUT ;
    USE SIGNAL ;
    PORT
      LAYER M3 ;
        RECT  67.5 0 67.518 0.037 ;
    END
  END b[322]
  PIN b[323]
    DIRECTION OUTPUT ;
    USE SIGNAL ;
    PORT
      LAYER M3 ;
        RECT  67.572 0 67.59 0.037 ;
    END
  END b[323]
  PIN b[324]
    DIRECTION OUTPUT ;
    USE SIGNAL ;
    PORT
      LAYER M3 ;
        RECT  67.644 0 67.662 0.037 ;
    END
  END b[324]
  PIN b[325]
    DIRECTION OUTPUT ;
    USE SIGNAL ;
    PORT
      LAYER M3 ;
        RECT  67.716 0 67.734 0.037 ;
    END
  END b[325]
  PIN b[326]
    DIRECTION OUTPUT ;
    USE SIGNAL ;
    PORT
      LAYER M3 ;
        RECT  67.788 0 67.806 0.037 ;
    END
  END b[326]
  PIN b[327]
    DIRECTION OUTPUT ;
    USE SIGNAL ;
    PORT
      LAYER M3 ;
        RECT  67.86 0 67.878 0.037 ;
    END
  END b[327]
  PIN b[328]
    DIRECTION OUTPUT ;
    USE SIGNAL ;
    PORT
      LAYER M3 ;
        RECT  67.932 0 67.95 0.037 ;
    END
  END b[328]
  PIN b[329]
    DIRECTION OUTPUT ;
    USE SIGNAL ;
    PORT
      LAYER M3 ;
        RECT  68.004 0 68.022 0.037 ;
    END
  END b[329]
  PIN b[32]
    DIRECTION OUTPUT ;
    USE SIGNAL ;
    PORT
      LAYER M3 ;
        RECT  50.652 0 50.67 0.037 ;
    END
  END b[32]
  PIN b[330]
    DIRECTION OUTPUT ;
    USE SIGNAL ;
    PORT
      LAYER M3 ;
        RECT  68.076 0 68.094 0.037 ;
    END
  END b[330]
  PIN b[331]
    DIRECTION OUTPUT ;
    USE SIGNAL ;
    PORT
      LAYER M3 ;
        RECT  68.148 0 68.166 0.037 ;
    END
  END b[331]
  PIN b[332]
    DIRECTION OUTPUT ;
    USE SIGNAL ;
    PORT
      LAYER M3 ;
        RECT  68.22 0 68.238 0.037 ;
    END
  END b[332]
  PIN b[333]
    DIRECTION OUTPUT ;
    USE SIGNAL ;
    PORT
      LAYER M3 ;
        RECT  68.292 0 68.31 0.037 ;
    END
  END b[333]
  PIN b[334]
    DIRECTION OUTPUT ;
    USE SIGNAL ;
    PORT
      LAYER M3 ;
        RECT  68.364 0 68.382 0.037 ;
    END
  END b[334]
  PIN b[335]
    DIRECTION OUTPUT ;
    USE SIGNAL ;
    PORT
      LAYER M3 ;
        RECT  68.436 0 68.454 0.037 ;
    END
  END b[335]
  PIN b[336]
    DIRECTION OUTPUT ;
    USE SIGNAL ;
    PORT
      LAYER M3 ;
        RECT  68.508 0 68.526 0.037 ;
    END
  END b[336]
  PIN b[337]
    DIRECTION OUTPUT ;
    USE SIGNAL ;
    PORT
      LAYER M3 ;
        RECT  68.58 0 68.598 0.037 ;
    END
  END b[337]
  PIN b[338]
    DIRECTION OUTPUT ;
    USE SIGNAL ;
    PORT
      LAYER M3 ;
        RECT  68.652 0 68.67 0.037 ;
    END
  END b[338]
  PIN b[339]
    DIRECTION OUTPUT ;
    USE SIGNAL ;
    PORT
      LAYER M3 ;
        RECT  68.724 0 68.742 0.037 ;
    END
  END b[339]
  PIN b[33]
    DIRECTION OUTPUT ;
    USE SIGNAL ;
    PORT
      LAYER M3 ;
        RECT  50.724 0 50.742 0.037 ;
    END
  END b[33]
  PIN b[340]
    DIRECTION OUTPUT ;
    USE SIGNAL ;
    PORT
      LAYER M3 ;
        RECT  68.796 0 68.814 0.037 ;
    END
  END b[340]
  PIN b[341]
    DIRECTION OUTPUT ;
    USE SIGNAL ;
    PORT
      LAYER M3 ;
        RECT  68.868 0 68.886 0.037 ;
    END
  END b[341]
  PIN b[342]
    DIRECTION OUTPUT ;
    USE SIGNAL ;
    PORT
      LAYER M3 ;
        RECT  68.94 0 68.958 0.037 ;
    END
  END b[342]
  PIN b[343]
    DIRECTION OUTPUT ;
    USE SIGNAL ;
    PORT
      LAYER M3 ;
        RECT  69.012 0 69.03 0.037 ;
    END
  END b[343]
  PIN b[344]
    DIRECTION OUTPUT ;
    USE SIGNAL ;
    PORT
      LAYER M3 ;
        RECT  69.084 0 69.102 0.037 ;
    END
  END b[344]
  PIN b[345]
    DIRECTION OUTPUT ;
    USE SIGNAL ;
    PORT
      LAYER M3 ;
        RECT  69.156 0 69.174 0.037 ;
    END
  END b[345]
  PIN b[346]
    DIRECTION OUTPUT ;
    USE SIGNAL ;
    PORT
      LAYER M3 ;
        RECT  69.228 0 69.246 0.037 ;
    END
  END b[346]
  PIN b[347]
    DIRECTION OUTPUT ;
    USE SIGNAL ;
    PORT
      LAYER M3 ;
        RECT  69.3 0 69.318 0.037 ;
    END
  END b[347]
  PIN b[348]
    DIRECTION OUTPUT ;
    USE SIGNAL ;
    PORT
      LAYER M3 ;
        RECT  69.372 0 69.39 0.037 ;
    END
  END b[348]
  PIN b[349]
    DIRECTION OUTPUT ;
    USE SIGNAL ;
    PORT
      LAYER M3 ;
        RECT  69.444 0 69.462 0.037 ;
    END
  END b[349]
  PIN b[34]
    DIRECTION OUTPUT ;
    USE SIGNAL ;
    PORT
      LAYER M3 ;
        RECT  50.796 0 50.814 0.037 ;
    END
  END b[34]
  PIN b[350]
    DIRECTION OUTPUT ;
    USE SIGNAL ;
    PORT
      LAYER M3 ;
        RECT  69.516 0 69.534 0.037 ;
    END
  END b[350]
  PIN b[351]
    DIRECTION OUTPUT ;
    USE SIGNAL ;
    PORT
      LAYER M3 ;
        RECT  69.588 0 69.606 0.037 ;
    END
  END b[351]
  PIN b[352]
    DIRECTION OUTPUT ;
    USE SIGNAL ;
    PORT
      LAYER M5 ;
        RECT  51.408 0 51.432 0.084 ;
    END
  END b[352]
  PIN b[353]
    DIRECTION OUTPUT ;
    USE SIGNAL ;
    PORT
      LAYER M5 ;
        RECT  51.504 0 51.528 0.084 ;
    END
  END b[353]
  PIN b[354]
    DIRECTION OUTPUT ;
    USE SIGNAL ;
    PORT
      LAYER M5 ;
        RECT  51.6 0 51.624 0.084 ;
    END
  END b[354]
  PIN b[355]
    DIRECTION OUTPUT ;
    USE SIGNAL ;
    PORT
      LAYER M5 ;
        RECT  51.696 0 51.72 0.084 ;
    END
  END b[355]
  PIN b[356]
    DIRECTION OUTPUT ;
    USE SIGNAL ;
    PORT
      LAYER M5 ;
        RECT  51.792 0 51.816 0.084 ;
    END
  END b[356]
  PIN b[357]
    DIRECTION OUTPUT ;
    USE SIGNAL ;
    PORT
      LAYER M5 ;
        RECT  51.888 0 51.912 0.084 ;
    END
  END b[357]
  PIN b[358]
    DIRECTION OUTPUT ;
    USE SIGNAL ;
    PORT
      LAYER M5 ;
        RECT  51.984 0 52.008 0.084 ;
    END
  END b[358]
  PIN b[359]
    DIRECTION OUTPUT ;
    USE SIGNAL ;
    PORT
      LAYER M5 ;
        RECT  52.08 0 52.104 0.084 ;
    END
  END b[359]
  PIN b[35]
    DIRECTION OUTPUT ;
    USE SIGNAL ;
    PORT
      LAYER M3 ;
        RECT  50.868 0 50.886 0.037 ;
    END
  END b[35]
  PIN b[360]
    DIRECTION OUTPUT ;
    USE SIGNAL ;
    PORT
      LAYER M5 ;
        RECT  52.176 0 52.2 0.084 ;
    END
  END b[360]
  PIN b[361]
    DIRECTION OUTPUT ;
    USE SIGNAL ;
    PORT
      LAYER M5 ;
        RECT  52.272 0 52.296 0.084 ;
    END
  END b[361]
  PIN b[362]
    DIRECTION OUTPUT ;
    USE SIGNAL ;
    PORT
      LAYER M5 ;
        RECT  52.368 0 52.392 0.084 ;
    END
  END b[362]
  PIN b[363]
    DIRECTION OUTPUT ;
    USE SIGNAL ;
    PORT
      LAYER M5 ;
        RECT  52.464 0 52.488 0.084 ;
    END
  END b[363]
  PIN b[364]
    DIRECTION OUTPUT ;
    USE SIGNAL ;
    PORT
      LAYER M5 ;
        RECT  52.56 0 52.584 0.084 ;
    END
  END b[364]
  PIN b[365]
    DIRECTION OUTPUT ;
    USE SIGNAL ;
    PORT
      LAYER M5 ;
        RECT  52.656 0 52.68 0.084 ;
    END
  END b[365]
  PIN b[366]
    DIRECTION OUTPUT ;
    USE SIGNAL ;
    PORT
      LAYER M5 ;
        RECT  52.752 0 52.776 0.084 ;
    END
  END b[366]
  PIN b[367]
    DIRECTION OUTPUT ;
    USE SIGNAL ;
    PORT
      LAYER M5 ;
        RECT  52.848 0 52.872 0.084 ;
    END
  END b[367]
  PIN b[368]
    DIRECTION OUTPUT ;
    USE SIGNAL ;
    PORT
      LAYER M5 ;
        RECT  52.944 0 52.968 0.084 ;
    END
  END b[368]
  PIN b[369]
    DIRECTION OUTPUT ;
    USE SIGNAL ;
    PORT
      LAYER M5 ;
        RECT  53.04 0 53.064 0.084 ;
    END
  END b[369]
  PIN b[36]
    DIRECTION OUTPUT ;
    USE SIGNAL ;
    PORT
      LAYER M3 ;
        RECT  50.94 0 50.958 0.037 ;
    END
  END b[36]
  PIN b[370]
    DIRECTION OUTPUT ;
    USE SIGNAL ;
    PORT
      LAYER M5 ;
        RECT  53.136 0 53.16 0.084 ;
    END
  END b[370]
  PIN b[371]
    DIRECTION OUTPUT ;
    USE SIGNAL ;
    PORT
      LAYER M5 ;
        RECT  53.232 0 53.256 0.084 ;
    END
  END b[371]
  PIN b[372]
    DIRECTION OUTPUT ;
    USE SIGNAL ;
    PORT
      LAYER M5 ;
        RECT  53.328 0 53.352 0.084 ;
    END
  END b[372]
  PIN b[373]
    DIRECTION OUTPUT ;
    USE SIGNAL ;
    PORT
      LAYER M5 ;
        RECT  53.424 0 53.448 0.084 ;
    END
  END b[373]
  PIN b[374]
    DIRECTION OUTPUT ;
    USE SIGNAL ;
    PORT
      LAYER M5 ;
        RECT  53.52 0 53.544 0.084 ;
    END
  END b[374]
  PIN b[375]
    DIRECTION OUTPUT ;
    USE SIGNAL ;
    PORT
      LAYER M5 ;
        RECT  53.616 0 53.64 0.084 ;
    END
  END b[375]
  PIN b[376]
    DIRECTION OUTPUT ;
    USE SIGNAL ;
    PORT
      LAYER M5 ;
        RECT  53.712 0 53.736 0.084 ;
    END
  END b[376]
  PIN b[377]
    DIRECTION OUTPUT ;
    USE SIGNAL ;
    PORT
      LAYER M5 ;
        RECT  53.808 0 53.832 0.084 ;
    END
  END b[377]
  PIN b[378]
    DIRECTION OUTPUT ;
    USE SIGNAL ;
    PORT
      LAYER M5 ;
        RECT  53.904 0 53.928 0.084 ;
    END
  END b[378]
  PIN b[379]
    DIRECTION OUTPUT ;
    USE SIGNAL ;
    PORT
      LAYER M5 ;
        RECT  54 0 54.024 0.084 ;
    END
  END b[379]
  PIN b[37]
    DIRECTION OUTPUT ;
    USE SIGNAL ;
    PORT
      LAYER M3 ;
        RECT  51.012 0 51.03 0.037 ;
    END
  END b[37]
  PIN b[380]
    DIRECTION OUTPUT ;
    USE SIGNAL ;
    PORT
      LAYER M5 ;
        RECT  54.096 0 54.12 0.084 ;
    END
  END b[380]
  PIN b[381]
    DIRECTION OUTPUT ;
    USE SIGNAL ;
    PORT
      LAYER M5 ;
        RECT  54.192 0 54.216 0.084 ;
    END
  END b[381]
  PIN b[382]
    DIRECTION OUTPUT ;
    USE SIGNAL ;
    PORT
      LAYER M5 ;
        RECT  54.288 0 54.312 0.084 ;
    END
  END b[382]
  PIN b[383]
    DIRECTION OUTPUT ;
    USE SIGNAL ;
    PORT
      LAYER M5 ;
        RECT  54.384 0 54.408 0.084 ;
    END
  END b[383]
  PIN b[384]
    DIRECTION OUTPUT ;
    USE SIGNAL ;
    PORT
      LAYER M5 ;
        RECT  39.12 0 39.144 0.084 ;
    END
  END b[384]
  PIN b[385]
    DIRECTION OUTPUT ;
    USE SIGNAL ;
    PORT
      LAYER M5 ;
        RECT  39.216 0 39.24 0.084 ;
    END
  END b[385]
  PIN b[386]
    DIRECTION OUTPUT ;
    USE SIGNAL ;
    PORT
      LAYER M5 ;
        RECT  39.312 0 39.336 0.084 ;
    END
  END b[386]
  PIN b[387]
    DIRECTION OUTPUT ;
    USE SIGNAL ;
    PORT
      LAYER M5 ;
        RECT  39.408 0 39.432 0.084 ;
    END
  END b[387]
  PIN b[388]
    DIRECTION OUTPUT ;
    USE SIGNAL ;
    PORT
      LAYER M5 ;
        RECT  39.504 0 39.528 0.084 ;
    END
  END b[388]
  PIN b[389]
    DIRECTION OUTPUT ;
    USE SIGNAL ;
    PORT
      LAYER M5 ;
        RECT  39.6 0 39.624 0.084 ;
    END
  END b[389]
  PIN b[38]
    DIRECTION OUTPUT ;
    USE SIGNAL ;
    PORT
      LAYER M3 ;
        RECT  51.084 0 51.102 0.037 ;
    END
  END b[38]
  PIN b[390]
    DIRECTION OUTPUT ;
    USE SIGNAL ;
    PORT
      LAYER M5 ;
        RECT  39.696 0 39.72 0.084 ;
    END
  END b[390]
  PIN b[391]
    DIRECTION OUTPUT ;
    USE SIGNAL ;
    PORT
      LAYER M5 ;
        RECT  39.792 0 39.816 0.084 ;
    END
  END b[391]
  PIN b[392]
    DIRECTION OUTPUT ;
    USE SIGNAL ;
    PORT
      LAYER M5 ;
        RECT  39.888 0 39.912 0.084 ;
    END
  END b[392]
  PIN b[393]
    DIRECTION OUTPUT ;
    USE SIGNAL ;
    PORT
      LAYER M5 ;
        RECT  39.984 0 40.008 0.084 ;
    END
  END b[393]
  PIN b[394]
    DIRECTION OUTPUT ;
    USE SIGNAL ;
    PORT
      LAYER M5 ;
        RECT  40.08 0 40.104 0.084 ;
    END
  END b[394]
  PIN b[395]
    DIRECTION OUTPUT ;
    USE SIGNAL ;
    PORT
      LAYER M5 ;
        RECT  40.176 0 40.2 0.084 ;
    END
  END b[395]
  PIN b[396]
    DIRECTION OUTPUT ;
    USE SIGNAL ;
    PORT
      LAYER M5 ;
        RECT  40.272 0 40.296 0.084 ;
    END
  END b[396]
  PIN b[397]
    DIRECTION OUTPUT ;
    USE SIGNAL ;
    PORT
      LAYER M5 ;
        RECT  40.368 0 40.392 0.084 ;
    END
  END b[397]
  PIN b[398]
    DIRECTION OUTPUT ;
    USE SIGNAL ;
    PORT
      LAYER M5 ;
        RECT  40.464 0 40.488 0.084 ;
    END
  END b[398]
  PIN b[399]
    DIRECTION OUTPUT ;
    USE SIGNAL ;
    PORT
      LAYER M5 ;
        RECT  40.56 0 40.584 0.084 ;
    END
  END b[399]
  PIN b[39]
    DIRECTION OUTPUT ;
    USE SIGNAL ;
    PORT
      LAYER M3 ;
        RECT  51.156 0 51.174 0.037 ;
    END
  END b[39]
  PIN b[3]
    DIRECTION OUTPUT ;
    USE SIGNAL ;
    PORT
      LAYER M3 ;
        RECT  43.956 0 43.974 0.037 ;
    END
  END b[3]
  PIN b[400]
    DIRECTION OUTPUT ;
    USE SIGNAL ;
    PORT
      LAYER M5 ;
        RECT  40.656 0 40.68 0.084 ;
    END
  END b[400]
  PIN b[401]
    DIRECTION OUTPUT ;
    USE SIGNAL ;
    PORT
      LAYER M5 ;
        RECT  40.752 0 40.776 0.084 ;
    END
  END b[401]
  PIN b[402]
    DIRECTION OUTPUT ;
    USE SIGNAL ;
    PORT
      LAYER M5 ;
        RECT  40.848 0 40.872 0.084 ;
    END
  END b[402]
  PIN b[403]
    DIRECTION OUTPUT ;
    USE SIGNAL ;
    PORT
      LAYER M5 ;
        RECT  40.944 0 40.968 0.084 ;
    END
  END b[403]
  PIN b[404]
    DIRECTION OUTPUT ;
    USE SIGNAL ;
    PORT
      LAYER M5 ;
        RECT  41.04 0 41.064 0.084 ;
    END
  END b[404]
  PIN b[405]
    DIRECTION OUTPUT ;
    USE SIGNAL ;
    PORT
      LAYER M5 ;
        RECT  41.136 0 41.16 0.084 ;
    END
  END b[405]
  PIN b[406]
    DIRECTION OUTPUT ;
    USE SIGNAL ;
    PORT
      LAYER M5 ;
        RECT  41.232 0 41.256 0.084 ;
    END
  END b[406]
  PIN b[407]
    DIRECTION OUTPUT ;
    USE SIGNAL ;
    PORT
      LAYER M5 ;
        RECT  41.328 0 41.352 0.084 ;
    END
  END b[407]
  PIN b[408]
    DIRECTION OUTPUT ;
    USE SIGNAL ;
    PORT
      LAYER M5 ;
        RECT  41.424 0 41.448 0.084 ;
    END
  END b[408]
  PIN b[409]
    DIRECTION OUTPUT ;
    USE SIGNAL ;
    PORT
      LAYER M5 ;
        RECT  41.52 0 41.544 0.084 ;
    END
  END b[409]
  PIN b[40]
    DIRECTION OUTPUT ;
    USE SIGNAL ;
    PORT
      LAYER M3 ;
        RECT  51.228 0 51.246 0.037 ;
    END
  END b[40]
  PIN b[410]
    DIRECTION OUTPUT ;
    USE SIGNAL ;
    PORT
      LAYER M5 ;
        RECT  41.616 0 41.64 0.084 ;
    END
  END b[410]
  PIN b[411]
    DIRECTION OUTPUT ;
    USE SIGNAL ;
    PORT
      LAYER M5 ;
        RECT  41.712 0 41.736 0.084 ;
    END
  END b[411]
  PIN b[412]
    DIRECTION OUTPUT ;
    USE SIGNAL ;
    PORT
      LAYER M5 ;
        RECT  41.808 0 41.832 0.084 ;
    END
  END b[412]
  PIN b[413]
    DIRECTION OUTPUT ;
    USE SIGNAL ;
    PORT
      LAYER M5 ;
        RECT  41.904 0 41.928 0.084 ;
    END
  END b[413]
  PIN b[414]
    DIRECTION OUTPUT ;
    USE SIGNAL ;
    PORT
      LAYER M5 ;
        RECT  42 0 42.024 0.084 ;
    END
  END b[414]
  PIN b[415]
    DIRECTION OUTPUT ;
    USE SIGNAL ;
    PORT
      LAYER M5 ;
        RECT  42.096 0 42.12 0.084 ;
    END
  END b[415]
  PIN b[416]
    DIRECTION OUTPUT ;
    USE SIGNAL ;
    PORT
      LAYER M5 ;
        RECT  45.264 0 45.288 0.084 ;
    END
  END b[416]
  PIN b[417]
    DIRECTION OUTPUT ;
    USE SIGNAL ;
    PORT
      LAYER M5 ;
        RECT  45.36 0 45.384 0.084 ;
    END
  END b[417]
  PIN b[418]
    DIRECTION OUTPUT ;
    USE SIGNAL ;
    PORT
      LAYER M5 ;
        RECT  45.456 0 45.48 0.084 ;
    END
  END b[418]
  PIN b[419]
    DIRECTION OUTPUT ;
    USE SIGNAL ;
    PORT
      LAYER M5 ;
        RECT  45.552 0 45.576 0.084 ;
    END
  END b[419]
  PIN b[41]
    DIRECTION OUTPUT ;
    USE SIGNAL ;
    PORT
      LAYER M3 ;
        RECT  51.3 0 51.318 0.037 ;
    END
  END b[41]
  PIN b[420]
    DIRECTION OUTPUT ;
    USE SIGNAL ;
    PORT
      LAYER M5 ;
        RECT  45.648 0 45.672 0.084 ;
    END
  END b[420]
  PIN b[421]
    DIRECTION OUTPUT ;
    USE SIGNAL ;
    PORT
      LAYER M5 ;
        RECT  45.744 0 45.768 0.084 ;
    END
  END b[421]
  PIN b[422]
    DIRECTION OUTPUT ;
    USE SIGNAL ;
    PORT
      LAYER M5 ;
        RECT  45.84 0 45.864 0.084 ;
    END
  END b[422]
  PIN b[423]
    DIRECTION OUTPUT ;
    USE SIGNAL ;
    PORT
      LAYER M5 ;
        RECT  45.936 0 45.96 0.084 ;
    END
  END b[423]
  PIN b[424]
    DIRECTION OUTPUT ;
    USE SIGNAL ;
    PORT
      LAYER M5 ;
        RECT  46.032 0 46.056 0.084 ;
    END
  END b[424]
  PIN b[425]
    DIRECTION OUTPUT ;
    USE SIGNAL ;
    PORT
      LAYER M5 ;
        RECT  46.128 0 46.152 0.084 ;
    END
  END b[425]
  PIN b[426]
    DIRECTION OUTPUT ;
    USE SIGNAL ;
    PORT
      LAYER M5 ;
        RECT  46.224 0 46.248 0.084 ;
    END
  END b[426]
  PIN b[427]
    DIRECTION OUTPUT ;
    USE SIGNAL ;
    PORT
      LAYER M5 ;
        RECT  46.32 0 46.344 0.084 ;
    END
  END b[427]
  PIN b[428]
    DIRECTION OUTPUT ;
    USE SIGNAL ;
    PORT
      LAYER M5 ;
        RECT  46.416 0 46.44 0.084 ;
    END
  END b[428]
  PIN b[429]
    DIRECTION OUTPUT ;
    USE SIGNAL ;
    PORT
      LAYER M5 ;
        RECT  46.512 0 46.536 0.084 ;
    END
  END b[429]
  PIN b[42]
    DIRECTION OUTPUT ;
    USE SIGNAL ;
    PORT
      LAYER M3 ;
        RECT  51.372 0 51.39 0.037 ;
    END
  END b[42]
  PIN b[430]
    DIRECTION OUTPUT ;
    USE SIGNAL ;
    PORT
      LAYER M5 ;
        RECT  46.608 0 46.632 0.084 ;
    END
  END b[430]
  PIN b[431]
    DIRECTION OUTPUT ;
    USE SIGNAL ;
    PORT
      LAYER M5 ;
        RECT  46.704 0 46.728 0.084 ;
    END
  END b[431]
  PIN b[432]
    DIRECTION OUTPUT ;
    USE SIGNAL ;
    PORT
      LAYER M5 ;
        RECT  46.8 0 46.824 0.084 ;
    END
  END b[432]
  PIN b[433]
    DIRECTION OUTPUT ;
    USE SIGNAL ;
    PORT
      LAYER M5 ;
        RECT  46.896 0 46.92 0.084 ;
    END
  END b[433]
  PIN b[434]
    DIRECTION OUTPUT ;
    USE SIGNAL ;
    PORT
      LAYER M5 ;
        RECT  46.992 0 47.016 0.084 ;
    END
  END b[434]
  PIN b[435]
    DIRECTION OUTPUT ;
    USE SIGNAL ;
    PORT
      LAYER M5 ;
        RECT  47.088 0 47.112 0.084 ;
    END
  END b[435]
  PIN b[436]
    DIRECTION OUTPUT ;
    USE SIGNAL ;
    PORT
      LAYER M5 ;
        RECT  47.184 0 47.208 0.084 ;
    END
  END b[436]
  PIN b[437]
    DIRECTION OUTPUT ;
    USE SIGNAL ;
    PORT
      LAYER M5 ;
        RECT  47.28 0 47.304 0.084 ;
    END
  END b[437]
  PIN b[438]
    DIRECTION OUTPUT ;
    USE SIGNAL ;
    PORT
      LAYER M5 ;
        RECT  47.376 0 47.4 0.084 ;
    END
  END b[438]
  PIN b[439]
    DIRECTION OUTPUT ;
    USE SIGNAL ;
    PORT
      LAYER M5 ;
        RECT  47.472 0 47.496 0.084 ;
    END
  END b[439]
  PIN b[43]
    DIRECTION OUTPUT ;
    USE SIGNAL ;
    PORT
      LAYER M3 ;
        RECT  51.444 0 51.462 0.037 ;
    END
  END b[43]
  PIN b[440]
    DIRECTION OUTPUT ;
    USE SIGNAL ;
    PORT
      LAYER M5 ;
        RECT  47.568 0 47.592 0.084 ;
    END
  END b[440]
  PIN b[441]
    DIRECTION OUTPUT ;
    USE SIGNAL ;
    PORT
      LAYER M5 ;
        RECT  47.664 0 47.688 0.084 ;
    END
  END b[441]
  PIN b[442]
    DIRECTION OUTPUT ;
    USE SIGNAL ;
    PORT
      LAYER M5 ;
        RECT  47.76 0 47.784 0.084 ;
    END
  END b[442]
  PIN b[443]
    DIRECTION OUTPUT ;
    USE SIGNAL ;
    PORT
      LAYER M5 ;
        RECT  47.856 0 47.88 0.084 ;
    END
  END b[443]
  PIN b[444]
    DIRECTION OUTPUT ;
    USE SIGNAL ;
    PORT
      LAYER M5 ;
        RECT  47.952 0 47.976 0.084 ;
    END
  END b[444]
  PIN b[445]
    DIRECTION OUTPUT ;
    USE SIGNAL ;
    PORT
      LAYER M5 ;
        RECT  48.048 0 48.072 0.084 ;
    END
  END b[445]
  PIN b[446]
    DIRECTION OUTPUT ;
    USE SIGNAL ;
    PORT
      LAYER M5 ;
        RECT  48.144 0 48.168 0.084 ;
    END
  END b[446]
  PIN b[447]
    DIRECTION OUTPUT ;
    USE SIGNAL ;
    PORT
      LAYER M5 ;
        RECT  48.24 0 48.264 0.084 ;
    END
  END b[447]
  PIN b[448]
    DIRECTION OUTPUT ;
    USE SIGNAL ;
    PORT
      LAYER M3 ;
        RECT  58.14 0 58.158 0.037 ;
    END
  END b[448]
  PIN b[449]
    DIRECTION OUTPUT ;
    USE SIGNAL ;
    PORT
      LAYER M3 ;
        RECT  58.212 0 58.23 0.037 ;
    END
  END b[449]
  PIN b[44]
    DIRECTION OUTPUT ;
    USE SIGNAL ;
    PORT
      LAYER M3 ;
        RECT  51.516 0 51.534 0.037 ;
    END
  END b[44]
  PIN b[450]
    DIRECTION OUTPUT ;
    USE SIGNAL ;
    PORT
      LAYER M3 ;
        RECT  58.284 0 58.302 0.037 ;
    END
  END b[450]
  PIN b[451]
    DIRECTION OUTPUT ;
    USE SIGNAL ;
    PORT
      LAYER M3 ;
        RECT  58.356 0 58.374 0.037 ;
    END
  END b[451]
  PIN b[452]
    DIRECTION OUTPUT ;
    USE SIGNAL ;
    PORT
      LAYER M3 ;
        RECT  58.428 0 58.446 0.037 ;
    END
  END b[452]
  PIN b[453]
    DIRECTION OUTPUT ;
    USE SIGNAL ;
    PORT
      LAYER M3 ;
        RECT  58.5 0 58.518 0.037 ;
    END
  END b[453]
  PIN b[454]
    DIRECTION OUTPUT ;
    USE SIGNAL ;
    PORT
      LAYER M3 ;
        RECT  58.572 0 58.59 0.037 ;
    END
  END b[454]
  PIN b[455]
    DIRECTION OUTPUT ;
    USE SIGNAL ;
    PORT
      LAYER M3 ;
        RECT  58.644 0 58.662 0.037 ;
    END
  END b[455]
  PIN b[456]
    DIRECTION OUTPUT ;
    USE SIGNAL ;
    PORT
      LAYER M3 ;
        RECT  58.716 0 58.734 0.037 ;
    END
  END b[456]
  PIN b[457]
    DIRECTION OUTPUT ;
    USE SIGNAL ;
    PORT
      LAYER M3 ;
        RECT  58.788 0 58.806 0.037 ;
    END
  END b[457]
  PIN b[458]
    DIRECTION OUTPUT ;
    USE SIGNAL ;
    PORT
      LAYER M3 ;
        RECT  58.86 0 58.878 0.037 ;
    END
  END b[458]
  PIN b[459]
    DIRECTION OUTPUT ;
    USE SIGNAL ;
    PORT
      LAYER M3 ;
        RECT  58.932 0 58.95 0.037 ;
    END
  END b[459]
  PIN b[45]
    DIRECTION OUTPUT ;
    USE SIGNAL ;
    PORT
      LAYER M3 ;
        RECT  51.588 0 51.606 0.037 ;
    END
  END b[45]
  PIN b[460]
    DIRECTION OUTPUT ;
    USE SIGNAL ;
    PORT
      LAYER M3 ;
        RECT  59.004 0 59.022 0.037 ;
    END
  END b[460]
  PIN b[461]
    DIRECTION OUTPUT ;
    USE SIGNAL ;
    PORT
      LAYER M3 ;
        RECT  59.076 0 59.094 0.037 ;
    END
  END b[461]
  PIN b[462]
    DIRECTION OUTPUT ;
    USE SIGNAL ;
    PORT
      LAYER M3 ;
        RECT  59.148 0 59.166 0.037 ;
    END
  END b[462]
  PIN b[463]
    DIRECTION OUTPUT ;
    USE SIGNAL ;
    PORT
      LAYER M3 ;
        RECT  59.22 0 59.238 0.037 ;
    END
  END b[463]
  PIN b[464]
    DIRECTION OUTPUT ;
    USE SIGNAL ;
    PORT
      LAYER M3 ;
        RECT  59.292 0 59.31 0.037 ;
    END
  END b[464]
  PIN b[465]
    DIRECTION OUTPUT ;
    USE SIGNAL ;
    PORT
      LAYER M3 ;
        RECT  59.364 0 59.382 0.037 ;
    END
  END b[465]
  PIN b[466]
    DIRECTION OUTPUT ;
    USE SIGNAL ;
    PORT
      LAYER M3 ;
        RECT  59.436 0 59.454 0.037 ;
    END
  END b[466]
  PIN b[467]
    DIRECTION OUTPUT ;
    USE SIGNAL ;
    PORT
      LAYER M3 ;
        RECT  59.508 0 59.526 0.037 ;
    END
  END b[467]
  PIN b[468]
    DIRECTION OUTPUT ;
    USE SIGNAL ;
    PORT
      LAYER M3 ;
        RECT  59.58 0 59.598 0.037 ;
    END
  END b[468]
  PIN b[469]
    DIRECTION OUTPUT ;
    USE SIGNAL ;
    PORT
      LAYER M3 ;
        RECT  59.652 0 59.67 0.037 ;
    END
  END b[469]
  PIN b[46]
    DIRECTION OUTPUT ;
    USE SIGNAL ;
    PORT
      LAYER M3 ;
        RECT  51.66 0 51.678 0.037 ;
    END
  END b[46]
  PIN b[470]
    DIRECTION OUTPUT ;
    USE SIGNAL ;
    PORT
      LAYER M3 ;
        RECT  59.724 0 59.742 0.037 ;
    END
  END b[470]
  PIN b[471]
    DIRECTION OUTPUT ;
    USE SIGNAL ;
    PORT
      LAYER M3 ;
        RECT  59.796 0 59.814 0.037 ;
    END
  END b[471]
  PIN b[472]
    DIRECTION OUTPUT ;
    USE SIGNAL ;
    PORT
      LAYER M3 ;
        RECT  59.868 0 59.886 0.037 ;
    END
  END b[472]
  PIN b[473]
    DIRECTION OUTPUT ;
    USE SIGNAL ;
    PORT
      LAYER M3 ;
        RECT  59.94 0 59.958 0.037 ;
    END
  END b[473]
  PIN b[474]
    DIRECTION OUTPUT ;
    USE SIGNAL ;
    PORT
      LAYER M3 ;
        RECT  60.012 0 60.03 0.037 ;
    END
  END b[474]
  PIN b[475]
    DIRECTION OUTPUT ;
    USE SIGNAL ;
    PORT
      LAYER M3 ;
        RECT  60.084 0 60.102 0.037 ;
    END
  END b[475]
  PIN b[476]
    DIRECTION OUTPUT ;
    USE SIGNAL ;
    PORT
      LAYER M3 ;
        RECT  60.156 0 60.174 0.037 ;
    END
  END b[476]
  PIN b[477]
    DIRECTION OUTPUT ;
    USE SIGNAL ;
    PORT
      LAYER M3 ;
        RECT  60.228 0 60.246 0.037 ;
    END
  END b[477]
  PIN b[478]
    DIRECTION OUTPUT ;
    USE SIGNAL ;
    PORT
      LAYER M3 ;
        RECT  60.3 0 60.318 0.037 ;
    END
  END b[478]
  PIN b[479]
    DIRECTION OUTPUT ;
    USE SIGNAL ;
    PORT
      LAYER M3 ;
        RECT  60.372 0 60.39 0.037 ;
    END
  END b[479]
  PIN b[47]
    DIRECTION OUTPUT ;
    USE SIGNAL ;
    PORT
      LAYER M3 ;
        RECT  51.732 0 51.75 0.037 ;
    END
  END b[47]
  PIN b[480]
    DIRECTION OUTPUT ;
    USE SIGNAL ;
    PORT
      LAYER M3 ;
        RECT  40.86 0 40.878 0.037 ;
    END
  END b[480]
  PIN b[481]
    DIRECTION OUTPUT ;
    USE SIGNAL ;
    PORT
      LAYER M3 ;
        RECT  40.932 0 40.95 0.037 ;
    END
  END b[481]
  PIN b[482]
    DIRECTION OUTPUT ;
    USE SIGNAL ;
    PORT
      LAYER M3 ;
        RECT  41.004 0 41.022 0.037 ;
    END
  END b[482]
  PIN b[483]
    DIRECTION OUTPUT ;
    USE SIGNAL ;
    PORT
      LAYER M3 ;
        RECT  41.076 0 41.094 0.037 ;
    END
  END b[483]
  PIN b[484]
    DIRECTION OUTPUT ;
    USE SIGNAL ;
    PORT
      LAYER M3 ;
        RECT  41.148 0 41.166 0.037 ;
    END
  END b[484]
  PIN b[485]
    DIRECTION OUTPUT ;
    USE SIGNAL ;
    PORT
      LAYER M3 ;
        RECT  41.22 0 41.238 0.037 ;
    END
  END b[485]
  PIN b[486]
    DIRECTION OUTPUT ;
    USE SIGNAL ;
    PORT
      LAYER M3 ;
        RECT  41.292 0 41.31 0.037 ;
    END
  END b[486]
  PIN b[487]
    DIRECTION OUTPUT ;
    USE SIGNAL ;
    PORT
      LAYER M3 ;
        RECT  41.364 0 41.382 0.037 ;
    END
  END b[487]
  PIN b[488]
    DIRECTION OUTPUT ;
    USE SIGNAL ;
    PORT
      LAYER M3 ;
        RECT  41.436 0 41.454 0.037 ;
    END
  END b[488]
  PIN b[489]
    DIRECTION OUTPUT ;
    USE SIGNAL ;
    PORT
      LAYER M3 ;
        RECT  41.508 0 41.526 0.037 ;
    END
  END b[489]
  PIN b[48]
    DIRECTION OUTPUT ;
    USE SIGNAL ;
    PORT
      LAYER M3 ;
        RECT  51.804 0 51.822 0.037 ;
    END
  END b[48]
  PIN b[490]
    DIRECTION OUTPUT ;
    USE SIGNAL ;
    PORT
      LAYER M3 ;
        RECT  41.58 0 41.598 0.037 ;
    END
  END b[490]
  PIN b[491]
    DIRECTION OUTPUT ;
    USE SIGNAL ;
    PORT
      LAYER M3 ;
        RECT  41.652 0 41.67 0.037 ;
    END
  END b[491]
  PIN b[492]
    DIRECTION OUTPUT ;
    USE SIGNAL ;
    PORT
      LAYER M3 ;
        RECT  41.724 0 41.742 0.037 ;
    END
  END b[492]
  PIN b[493]
    DIRECTION OUTPUT ;
    USE SIGNAL ;
    PORT
      LAYER M3 ;
        RECT  41.796 0 41.814 0.037 ;
    END
  END b[493]
  PIN b[494]
    DIRECTION OUTPUT ;
    USE SIGNAL ;
    PORT
      LAYER M3 ;
        RECT  41.868 0 41.886 0.037 ;
    END
  END b[494]
  PIN b[495]
    DIRECTION OUTPUT ;
    USE SIGNAL ;
    PORT
      LAYER M3 ;
        RECT  41.94 0 41.958 0.037 ;
    END
  END b[495]
  PIN b[496]
    DIRECTION OUTPUT ;
    USE SIGNAL ;
    PORT
      LAYER M3 ;
        RECT  42.012 0 42.03 0.037 ;
    END
  END b[496]
  PIN b[497]
    DIRECTION OUTPUT ;
    USE SIGNAL ;
    PORT
      LAYER M3 ;
        RECT  42.084 0 42.102 0.037 ;
    END
  END b[497]
  PIN b[498]
    DIRECTION OUTPUT ;
    USE SIGNAL ;
    PORT
      LAYER M3 ;
        RECT  42.156 0 42.174 0.037 ;
    END
  END b[498]
  PIN b[499]
    DIRECTION OUTPUT ;
    USE SIGNAL ;
    PORT
      LAYER M3 ;
        RECT  42.228 0 42.246 0.037 ;
    END
  END b[499]
  PIN b[49]
    DIRECTION OUTPUT ;
    USE SIGNAL ;
    PORT
      LAYER M3 ;
        RECT  51.876 0 51.894 0.037 ;
    END
  END b[49]
  PIN b[4]
    DIRECTION OUTPUT ;
    USE SIGNAL ;
    PORT
      LAYER M3 ;
        RECT  44.028 0 44.046 0.037 ;
    END
  END b[4]
  PIN b[500]
    DIRECTION OUTPUT ;
    USE SIGNAL ;
    PORT
      LAYER M3 ;
        RECT  42.3 0 42.318 0.037 ;
    END
  END b[500]
  PIN b[501]
    DIRECTION OUTPUT ;
    USE SIGNAL ;
    PORT
      LAYER M3 ;
        RECT  42.372 0 42.39 0.037 ;
    END
  END b[501]
  PIN b[502]
    DIRECTION OUTPUT ;
    USE SIGNAL ;
    PORT
      LAYER M3 ;
        RECT  42.444 0 42.462 0.037 ;
    END
  END b[502]
  PIN b[503]
    DIRECTION OUTPUT ;
    USE SIGNAL ;
    PORT
      LAYER M3 ;
        RECT  42.516 0 42.534 0.037 ;
    END
  END b[503]
  PIN b[504]
    DIRECTION OUTPUT ;
    USE SIGNAL ;
    PORT
      LAYER M3 ;
        RECT  42.588 0 42.606 0.037 ;
    END
  END b[504]
  PIN b[505]
    DIRECTION OUTPUT ;
    USE SIGNAL ;
    PORT
      LAYER M3 ;
        RECT  42.66 0 42.678 0.037 ;
    END
  END b[505]
  PIN b[506]
    DIRECTION OUTPUT ;
    USE SIGNAL ;
    PORT
      LAYER M3 ;
        RECT  42.732 0 42.75 0.037 ;
    END
  END b[506]
  PIN b[507]
    DIRECTION OUTPUT ;
    USE SIGNAL ;
    PORT
      LAYER M3 ;
        RECT  42.804 0 42.822 0.037 ;
    END
  END b[507]
  PIN b[508]
    DIRECTION OUTPUT ;
    USE SIGNAL ;
    PORT
      LAYER M3 ;
        RECT  42.876 0 42.894 0.037 ;
    END
  END b[508]
  PIN b[509]
    DIRECTION OUTPUT ;
    USE SIGNAL ;
    PORT
      LAYER M3 ;
        RECT  42.948 0 42.966 0.037 ;
    END
  END b[509]
  PIN b[50]
    DIRECTION OUTPUT ;
    USE SIGNAL ;
    PORT
      LAYER M3 ;
        RECT  51.948 0 51.966 0.037 ;
    END
  END b[50]
  PIN b[510]
    DIRECTION OUTPUT ;
    USE SIGNAL ;
    PORT
      LAYER M3 ;
        RECT  43.02 0 43.038 0.037 ;
    END
  END b[510]
  PIN b[511]
    DIRECTION OUTPUT ;
    USE SIGNAL ;
    PORT
      LAYER M3 ;
        RECT  43.092 0 43.11 0.037 ;
    END
  END b[511]
  PIN b[512]
    DIRECTION OUTPUT ;
    USE SIGNAL ;
    PORT
      LAYER M3 ;
        RECT  60.444 0 60.462 0.037 ;
    END
  END b[512]
  PIN b[513]
    DIRECTION OUTPUT ;
    USE SIGNAL ;
    PORT
      LAYER M3 ;
        RECT  60.516 0 60.534 0.037 ;
    END
  END b[513]
  PIN b[514]
    DIRECTION OUTPUT ;
    USE SIGNAL ;
    PORT
      LAYER M3 ;
        RECT  60.588 0 60.606 0.037 ;
    END
  END b[514]
  PIN b[515]
    DIRECTION OUTPUT ;
    USE SIGNAL ;
    PORT
      LAYER M3 ;
        RECT  60.66 0 60.678 0.037 ;
    END
  END b[515]
  PIN b[516]
    DIRECTION OUTPUT ;
    USE SIGNAL ;
    PORT
      LAYER M3 ;
        RECT  60.732 0 60.75 0.037 ;
    END
  END b[516]
  PIN b[517]
    DIRECTION OUTPUT ;
    USE SIGNAL ;
    PORT
      LAYER M3 ;
        RECT  60.804 0 60.822 0.037 ;
    END
  END b[517]
  PIN b[518]
    DIRECTION OUTPUT ;
    USE SIGNAL ;
    PORT
      LAYER M3 ;
        RECT  60.876 0 60.894 0.037 ;
    END
  END b[518]
  PIN b[519]
    DIRECTION OUTPUT ;
    USE SIGNAL ;
    PORT
      LAYER M3 ;
        RECT  60.948 0 60.966 0.037 ;
    END
  END b[519]
  PIN b[51]
    DIRECTION OUTPUT ;
    USE SIGNAL ;
    PORT
      LAYER M3 ;
        RECT  52.02 0 52.038 0.037 ;
    END
  END b[51]
  PIN b[520]
    DIRECTION OUTPUT ;
    USE SIGNAL ;
    PORT
      LAYER M3 ;
        RECT  61.02 0 61.038 0.037 ;
    END
  END b[520]
  PIN b[521]
    DIRECTION OUTPUT ;
    USE SIGNAL ;
    PORT
      LAYER M3 ;
        RECT  61.092 0 61.11 0.037 ;
    END
  END b[521]
  PIN b[522]
    DIRECTION OUTPUT ;
    USE SIGNAL ;
    PORT
      LAYER M3 ;
        RECT  61.164 0 61.182 0.037 ;
    END
  END b[522]
  PIN b[523]
    DIRECTION OUTPUT ;
    USE SIGNAL ;
    PORT
      LAYER M3 ;
        RECT  61.236 0 61.254 0.037 ;
    END
  END b[523]
  PIN b[524]
    DIRECTION OUTPUT ;
    USE SIGNAL ;
    PORT
      LAYER M3 ;
        RECT  61.308 0 61.326 0.037 ;
    END
  END b[524]
  PIN b[525]
    DIRECTION OUTPUT ;
    USE SIGNAL ;
    PORT
      LAYER M3 ;
        RECT  61.38 0 61.398 0.037 ;
    END
  END b[525]
  PIN b[526]
    DIRECTION OUTPUT ;
    USE SIGNAL ;
    PORT
      LAYER M3 ;
        RECT  61.452 0 61.47 0.037 ;
    END
  END b[526]
  PIN b[527]
    DIRECTION OUTPUT ;
    USE SIGNAL ;
    PORT
      LAYER M3 ;
        RECT  61.524 0 61.542 0.037 ;
    END
  END b[527]
  PIN b[528]
    DIRECTION OUTPUT ;
    USE SIGNAL ;
    PORT
      LAYER M3 ;
        RECT  61.596 0 61.614 0.037 ;
    END
  END b[528]
  PIN b[529]
    DIRECTION OUTPUT ;
    USE SIGNAL ;
    PORT
      LAYER M3 ;
        RECT  61.668 0 61.686 0.037 ;
    END
  END b[529]
  PIN b[52]
    DIRECTION OUTPUT ;
    USE SIGNAL ;
    PORT
      LAYER M3 ;
        RECT  52.092 0 52.11 0.037 ;
    END
  END b[52]
  PIN b[530]
    DIRECTION OUTPUT ;
    USE SIGNAL ;
    PORT
      LAYER M3 ;
        RECT  61.74 0 61.758 0.037 ;
    END
  END b[530]
  PIN b[531]
    DIRECTION OUTPUT ;
    USE SIGNAL ;
    PORT
      LAYER M3 ;
        RECT  61.812 0 61.83 0.037 ;
    END
  END b[531]
  PIN b[532]
    DIRECTION OUTPUT ;
    USE SIGNAL ;
    PORT
      LAYER M3 ;
        RECT  61.884 0 61.902 0.037 ;
    END
  END b[532]
  PIN b[533]
    DIRECTION OUTPUT ;
    USE SIGNAL ;
    PORT
      LAYER M3 ;
        RECT  61.956 0 61.974 0.037 ;
    END
  END b[533]
  PIN b[534]
    DIRECTION OUTPUT ;
    USE SIGNAL ;
    PORT
      LAYER M3 ;
        RECT  62.028 0 62.046 0.037 ;
    END
  END b[534]
  PIN b[535]
    DIRECTION OUTPUT ;
    USE SIGNAL ;
    PORT
      LAYER M3 ;
        RECT  62.1 0 62.118 0.037 ;
    END
  END b[535]
  PIN b[536]
    DIRECTION OUTPUT ;
    USE SIGNAL ;
    PORT
      LAYER M3 ;
        RECT  62.172 0 62.19 0.037 ;
    END
  END b[536]
  PIN b[537]
    DIRECTION OUTPUT ;
    USE SIGNAL ;
    PORT
      LAYER M3 ;
        RECT  62.244 0 62.262 0.037 ;
    END
  END b[537]
  PIN b[538]
    DIRECTION OUTPUT ;
    USE SIGNAL ;
    PORT
      LAYER M3 ;
        RECT  62.316 0 62.334 0.037 ;
    END
  END b[538]
  PIN b[539]
    DIRECTION OUTPUT ;
    USE SIGNAL ;
    PORT
      LAYER M3 ;
        RECT  62.388 0 62.406 0.037 ;
    END
  END b[539]
  PIN b[53]
    DIRECTION OUTPUT ;
    USE SIGNAL ;
    PORT
      LAYER M3 ;
        RECT  52.164 0 52.182 0.037 ;
    END
  END b[53]
  PIN b[540]
    DIRECTION OUTPUT ;
    USE SIGNAL ;
    PORT
      LAYER M3 ;
        RECT  62.46 0 62.478 0.037 ;
    END
  END b[540]
  PIN b[541]
    DIRECTION OUTPUT ;
    USE SIGNAL ;
    PORT
      LAYER M3 ;
        RECT  62.532 0 62.55 0.037 ;
    END
  END b[541]
  PIN b[542]
    DIRECTION OUTPUT ;
    USE SIGNAL ;
    PORT
      LAYER M3 ;
        RECT  62.604 0 62.622 0.037 ;
    END
  END b[542]
  PIN b[543]
    DIRECTION OUTPUT ;
    USE SIGNAL ;
    PORT
      LAYER M3 ;
        RECT  62.676 0 62.694 0.037 ;
    END
  END b[543]
  PIN b[544]
    DIRECTION OUTPUT ;
    USE SIGNAL ;
    PORT
      LAYER M3 ;
        RECT  65.052 0 65.07 0.037 ;
    END
  END b[544]
  PIN b[545]
    DIRECTION OUTPUT ;
    USE SIGNAL ;
    PORT
      LAYER M3 ;
        RECT  65.124 0 65.142 0.037 ;
    END
  END b[545]
  PIN b[546]
    DIRECTION OUTPUT ;
    USE SIGNAL ;
    PORT
      LAYER M3 ;
        RECT  65.196 0 65.214 0.037 ;
    END
  END b[546]
  PIN b[547]
    DIRECTION OUTPUT ;
    USE SIGNAL ;
    PORT
      LAYER M3 ;
        RECT  65.268 0 65.286 0.037 ;
    END
  END b[547]
  PIN b[548]
    DIRECTION OUTPUT ;
    USE SIGNAL ;
    PORT
      LAYER M3 ;
        RECT  65.34 0 65.358 0.037 ;
    END
  END b[548]
  PIN b[549]
    DIRECTION OUTPUT ;
    USE SIGNAL ;
    PORT
      LAYER M3 ;
        RECT  65.412 0 65.43 0.037 ;
    END
  END b[549]
  PIN b[54]
    DIRECTION OUTPUT ;
    USE SIGNAL ;
    PORT
      LAYER M3 ;
        RECT  52.236 0 52.254 0.037 ;
    END
  END b[54]
  PIN b[550]
    DIRECTION OUTPUT ;
    USE SIGNAL ;
    PORT
      LAYER M3 ;
        RECT  65.484 0 65.502 0.037 ;
    END
  END b[550]
  PIN b[551]
    DIRECTION OUTPUT ;
    USE SIGNAL ;
    PORT
      LAYER M3 ;
        RECT  65.556 0 65.574 0.037 ;
    END
  END b[551]
  PIN b[552]
    DIRECTION OUTPUT ;
    USE SIGNAL ;
    PORT
      LAYER M3 ;
        RECT  65.628 0 65.646 0.037 ;
    END
  END b[552]
  PIN b[553]
    DIRECTION OUTPUT ;
    USE SIGNAL ;
    PORT
      LAYER M3 ;
        RECT  65.7 0 65.718 0.037 ;
    END
  END b[553]
  PIN b[554]
    DIRECTION OUTPUT ;
    USE SIGNAL ;
    PORT
      LAYER M3 ;
        RECT  65.772 0 65.79 0.037 ;
    END
  END b[554]
  PIN b[555]
    DIRECTION OUTPUT ;
    USE SIGNAL ;
    PORT
      LAYER M3 ;
        RECT  65.844 0 65.862 0.037 ;
    END
  END b[555]
  PIN b[556]
    DIRECTION OUTPUT ;
    USE SIGNAL ;
    PORT
      LAYER M3 ;
        RECT  65.916 0 65.934 0.037 ;
    END
  END b[556]
  PIN b[557]
    DIRECTION OUTPUT ;
    USE SIGNAL ;
    PORT
      LAYER M3 ;
        RECT  65.988 0 66.006 0.037 ;
    END
  END b[557]
  PIN b[558]
    DIRECTION OUTPUT ;
    USE SIGNAL ;
    PORT
      LAYER M3 ;
        RECT  66.06 0 66.078 0.037 ;
    END
  END b[558]
  PIN b[559]
    DIRECTION OUTPUT ;
    USE SIGNAL ;
    PORT
      LAYER M3 ;
        RECT  66.132 0 66.15 0.037 ;
    END
  END b[559]
  PIN b[55]
    DIRECTION OUTPUT ;
    USE SIGNAL ;
    PORT
      LAYER M3 ;
        RECT  52.308 0 52.326 0.037 ;
    END
  END b[55]
  PIN b[560]
    DIRECTION OUTPUT ;
    USE SIGNAL ;
    PORT
      LAYER M3 ;
        RECT  66.204 0 66.222 0.037 ;
    END
  END b[560]
  PIN b[561]
    DIRECTION OUTPUT ;
    USE SIGNAL ;
    PORT
      LAYER M3 ;
        RECT  66.276 0 66.294 0.037 ;
    END
  END b[561]
  PIN b[562]
    DIRECTION OUTPUT ;
    USE SIGNAL ;
    PORT
      LAYER M3 ;
        RECT  66.348 0 66.366 0.037 ;
    END
  END b[562]
  PIN b[563]
    DIRECTION OUTPUT ;
    USE SIGNAL ;
    PORT
      LAYER M3 ;
        RECT  66.42 0 66.438 0.037 ;
    END
  END b[563]
  PIN b[564]
    DIRECTION OUTPUT ;
    USE SIGNAL ;
    PORT
      LAYER M3 ;
        RECT  66.492 0 66.51 0.037 ;
    END
  END b[564]
  PIN b[565]
    DIRECTION OUTPUT ;
    USE SIGNAL ;
    PORT
      LAYER M3 ;
        RECT  66.564 0 66.582 0.037 ;
    END
  END b[565]
  PIN b[566]
    DIRECTION OUTPUT ;
    USE SIGNAL ;
    PORT
      LAYER M3 ;
        RECT  66.636 0 66.654 0.037 ;
    END
  END b[566]
  PIN b[567]
    DIRECTION OUTPUT ;
    USE SIGNAL ;
    PORT
      LAYER M3 ;
        RECT  66.708 0 66.726 0.037 ;
    END
  END b[567]
  PIN b[568]
    DIRECTION OUTPUT ;
    USE SIGNAL ;
    PORT
      LAYER M3 ;
        RECT  66.78 0 66.798 0.037 ;
    END
  END b[568]
  PIN b[569]
    DIRECTION OUTPUT ;
    USE SIGNAL ;
    PORT
      LAYER M3 ;
        RECT  66.852 0 66.87 0.037 ;
    END
  END b[569]
  PIN b[56]
    DIRECTION OUTPUT ;
    USE SIGNAL ;
    PORT
      LAYER M3 ;
        RECT  52.38 0 52.398 0.037 ;
    END
  END b[56]
  PIN b[570]
    DIRECTION OUTPUT ;
    USE SIGNAL ;
    PORT
      LAYER M3 ;
        RECT  66.924 0 66.942 0.037 ;
    END
  END b[570]
  PIN b[571]
    DIRECTION OUTPUT ;
    USE SIGNAL ;
    PORT
      LAYER M3 ;
        RECT  66.996 0 67.014 0.037 ;
    END
  END b[571]
  PIN b[572]
    DIRECTION OUTPUT ;
    USE SIGNAL ;
    PORT
      LAYER M3 ;
        RECT  67.068 0 67.086 0.037 ;
    END
  END b[572]
  PIN b[573]
    DIRECTION OUTPUT ;
    USE SIGNAL ;
    PORT
      LAYER M3 ;
        RECT  67.14 0 67.158 0.037 ;
    END
  END b[573]
  PIN b[574]
    DIRECTION OUTPUT ;
    USE SIGNAL ;
    PORT
      LAYER M3 ;
        RECT  67.212 0 67.23 0.037 ;
    END
  END b[574]
  PIN b[575]
    DIRECTION OUTPUT ;
    USE SIGNAL ;
    PORT
      LAYER M3 ;
        RECT  67.284 0 67.302 0.037 ;
    END
  END b[575]
  PIN b[576]
    DIRECTION OUTPUT ;
    USE SIGNAL ;
    PORT
      LAYER M3 ;
        RECT  69.66 0 69.678 0.037 ;
    END
  END b[576]
  PIN b[577]
    DIRECTION OUTPUT ;
    USE SIGNAL ;
    PORT
      LAYER M3 ;
        RECT  69.732 0 69.75 0.037 ;
    END
  END b[577]
  PIN b[578]
    DIRECTION OUTPUT ;
    USE SIGNAL ;
    PORT
      LAYER M3 ;
        RECT  69.804 0 69.822 0.037 ;
    END
  END b[578]
  PIN b[579]
    DIRECTION OUTPUT ;
    USE SIGNAL ;
    PORT
      LAYER M3 ;
        RECT  69.876 0 69.894 0.037 ;
    END
  END b[579]
  PIN b[57]
    DIRECTION OUTPUT ;
    USE SIGNAL ;
    PORT
      LAYER M3 ;
        RECT  52.452 0 52.47 0.037 ;
    END
  END b[57]
  PIN b[580]
    DIRECTION OUTPUT ;
    USE SIGNAL ;
    PORT
      LAYER M3 ;
        RECT  69.948 0 69.966 0.037 ;
    END
  END b[580]
  PIN b[581]
    DIRECTION OUTPUT ;
    USE SIGNAL ;
    PORT
      LAYER M3 ;
        RECT  70.02 0 70.038 0.037 ;
    END
  END b[581]
  PIN b[582]
    DIRECTION OUTPUT ;
    USE SIGNAL ;
    PORT
      LAYER M3 ;
        RECT  70.092 0 70.11 0.037 ;
    END
  END b[582]
  PIN b[583]
    DIRECTION OUTPUT ;
    USE SIGNAL ;
    PORT
      LAYER M3 ;
        RECT  70.164 0 70.182 0.037 ;
    END
  END b[583]
  PIN b[584]
    DIRECTION OUTPUT ;
    USE SIGNAL ;
    PORT
      LAYER M3 ;
        RECT  70.236 0 70.254 0.037 ;
    END
  END b[584]
  PIN b[585]
    DIRECTION OUTPUT ;
    USE SIGNAL ;
    PORT
      LAYER M3 ;
        RECT  70.308 0 70.326 0.037 ;
    END
  END b[585]
  PIN b[586]
    DIRECTION OUTPUT ;
    USE SIGNAL ;
    PORT
      LAYER M3 ;
        RECT  70.38 0 70.398 0.037 ;
    END
  END b[586]
  PIN b[587]
    DIRECTION OUTPUT ;
    USE SIGNAL ;
    PORT
      LAYER M3 ;
        RECT  70.452 0 70.47 0.037 ;
    END
  END b[587]
  PIN b[588]
    DIRECTION OUTPUT ;
    USE SIGNAL ;
    PORT
      LAYER M3 ;
        RECT  70.524 0 70.542 0.037 ;
    END
  END b[588]
  PIN b[589]
    DIRECTION OUTPUT ;
    USE SIGNAL ;
    PORT
      LAYER M3 ;
        RECT  70.596 0 70.614 0.037 ;
    END
  END b[589]
  PIN b[58]
    DIRECTION OUTPUT ;
    USE SIGNAL ;
    PORT
      LAYER M3 ;
        RECT  52.524 0 52.542 0.037 ;
    END
  END b[58]
  PIN b[590]
    DIRECTION OUTPUT ;
    USE SIGNAL ;
    PORT
      LAYER M3 ;
        RECT  70.668 0 70.686 0.037 ;
    END
  END b[590]
  PIN b[591]
    DIRECTION OUTPUT ;
    USE SIGNAL ;
    PORT
      LAYER M3 ;
        RECT  70.74 0 70.758 0.037 ;
    END
  END b[591]
  PIN b[592]
    DIRECTION OUTPUT ;
    USE SIGNAL ;
    PORT
      LAYER M3 ;
        RECT  70.812 0 70.83 0.037 ;
    END
  END b[592]
  PIN b[593]
    DIRECTION OUTPUT ;
    USE SIGNAL ;
    PORT
      LAYER M3 ;
        RECT  70.884 0 70.902 0.037 ;
    END
  END b[593]
  PIN b[594]
    DIRECTION OUTPUT ;
    USE SIGNAL ;
    PORT
      LAYER M3 ;
        RECT  70.956 0 70.974 0.037 ;
    END
  END b[594]
  PIN b[595]
    DIRECTION OUTPUT ;
    USE SIGNAL ;
    PORT
      LAYER M3 ;
        RECT  71.028 0 71.046 0.037 ;
    END
  END b[595]
  PIN b[596]
    DIRECTION OUTPUT ;
    USE SIGNAL ;
    PORT
      LAYER M3 ;
        RECT  71.1 0 71.118 0.037 ;
    END
  END b[596]
  PIN b[597]
    DIRECTION OUTPUT ;
    USE SIGNAL ;
    PORT
      LAYER M3 ;
        RECT  71.172 0 71.19 0.037 ;
    END
  END b[597]
  PIN b[598]
    DIRECTION OUTPUT ;
    USE SIGNAL ;
    PORT
      LAYER M3 ;
        RECT  71.244 0 71.262 0.037 ;
    END
  END b[598]
  PIN b[599]
    DIRECTION OUTPUT ;
    USE SIGNAL ;
    PORT
      LAYER M3 ;
        RECT  71.316 0 71.334 0.037 ;
    END
  END b[599]
  PIN b[59]
    DIRECTION OUTPUT ;
    USE SIGNAL ;
    PORT
      LAYER M3 ;
        RECT  52.596 0 52.614 0.037 ;
    END
  END b[59]
  PIN b[5]
    DIRECTION OUTPUT ;
    USE SIGNAL ;
    PORT
      LAYER M3 ;
        RECT  44.1 0 44.118 0.037 ;
    END
  END b[5]
  PIN b[60]
    DIRECTION OUTPUT ;
    USE SIGNAL ;
    PORT
      LAYER M3 ;
        RECT  52.668 0 52.686 0.037 ;
    END
  END b[60]
  PIN b[61]
    DIRECTION OUTPUT ;
    USE SIGNAL ;
    PORT
      LAYER M3 ;
        RECT  52.74 0 52.758 0.037 ;
    END
  END b[61]
  PIN b[62]
    DIRECTION OUTPUT ;
    USE SIGNAL ;
    PORT
      LAYER M3 ;
        RECT  52.812 0 52.83 0.037 ;
    END
  END b[62]
  PIN b[63]
    DIRECTION OUTPUT ;
    USE SIGNAL ;
    PORT
      LAYER M3 ;
        RECT  52.884 0 52.902 0.037 ;
    END
  END b[63]
  PIN b[64]
    DIRECTION OUTPUT ;
    USE SIGNAL ;
    PORT
      LAYER M5 ;
        RECT  42.192 0 42.216 0.084 ;
    END
  END b[64]
  PIN b[65]
    DIRECTION OUTPUT ;
    USE SIGNAL ;
    PORT
      LAYER M5 ;
        RECT  42.288 0 42.312 0.084 ;
    END
  END b[65]
  PIN b[66]
    DIRECTION OUTPUT ;
    USE SIGNAL ;
    PORT
      LAYER M5 ;
        RECT  42.384 0 42.408 0.084 ;
    END
  END b[66]
  PIN b[67]
    DIRECTION OUTPUT ;
    USE SIGNAL ;
    PORT
      LAYER M5 ;
        RECT  42.48 0 42.504 0.084 ;
    END
  END b[67]
  PIN b[68]
    DIRECTION OUTPUT ;
    USE SIGNAL ;
    PORT
      LAYER M5 ;
        RECT  42.576 0 42.6 0.084 ;
    END
  END b[68]
  PIN b[69]
    DIRECTION OUTPUT ;
    USE SIGNAL ;
    PORT
      LAYER M5 ;
        RECT  42.672 0 42.696 0.084 ;
    END
  END b[69]
  PIN b[6]
    DIRECTION OUTPUT ;
    USE SIGNAL ;
    PORT
      LAYER M3 ;
        RECT  44.172 0 44.19 0.037 ;
    END
  END b[6]
  PIN b[70]
    DIRECTION OUTPUT ;
    USE SIGNAL ;
    PORT
      LAYER M5 ;
        RECT  42.768 0 42.792 0.084 ;
    END
  END b[70]
  PIN b[71]
    DIRECTION OUTPUT ;
    USE SIGNAL ;
    PORT
      LAYER M5 ;
        RECT  42.864 0 42.888 0.084 ;
    END
  END b[71]
  PIN b[72]
    DIRECTION OUTPUT ;
    USE SIGNAL ;
    PORT
      LAYER M5 ;
        RECT  42.96 0 42.984 0.084 ;
    END
  END b[72]
  PIN b[73]
    DIRECTION OUTPUT ;
    USE SIGNAL ;
    PORT
      LAYER M5 ;
        RECT  43.056 0 43.08 0.084 ;
    END
  END b[73]
  PIN b[74]
    DIRECTION OUTPUT ;
    USE SIGNAL ;
    PORT
      LAYER M5 ;
        RECT  43.152 0 43.176 0.084 ;
    END
  END b[74]
  PIN b[75]
    DIRECTION OUTPUT ;
    USE SIGNAL ;
    PORT
      LAYER M5 ;
        RECT  43.248 0 43.272 0.084 ;
    END
  END b[75]
  PIN b[76]
    DIRECTION OUTPUT ;
    USE SIGNAL ;
    PORT
      LAYER M5 ;
        RECT  43.344 0 43.368 0.084 ;
    END
  END b[76]
  PIN b[77]
    DIRECTION OUTPUT ;
    USE SIGNAL ;
    PORT
      LAYER M5 ;
        RECT  43.44 0 43.464 0.084 ;
    END
  END b[77]
  PIN b[78]
    DIRECTION OUTPUT ;
    USE SIGNAL ;
    PORT
      LAYER M5 ;
        RECT  43.536 0 43.56 0.084 ;
    END
  END b[78]
  PIN b[79]
    DIRECTION OUTPUT ;
    USE SIGNAL ;
    PORT
      LAYER M5 ;
        RECT  43.632 0 43.656 0.084 ;
    END
  END b[79]
  PIN b[7]
    DIRECTION OUTPUT ;
    USE SIGNAL ;
    PORT
      LAYER M3 ;
        RECT  44.244 0 44.262 0.037 ;
    END
  END b[7]
  PIN b[80]
    DIRECTION OUTPUT ;
    USE SIGNAL ;
    PORT
      LAYER M5 ;
        RECT  43.728 0 43.752 0.084 ;
    END
  END b[80]
  PIN b[81]
    DIRECTION OUTPUT ;
    USE SIGNAL ;
    PORT
      LAYER M5 ;
        RECT  43.824 0 43.848 0.084 ;
    END
  END b[81]
  PIN b[82]
    DIRECTION OUTPUT ;
    USE SIGNAL ;
    PORT
      LAYER M5 ;
        RECT  43.92 0 43.944 0.084 ;
    END
  END b[82]
  PIN b[83]
    DIRECTION OUTPUT ;
    USE SIGNAL ;
    PORT
      LAYER M5 ;
        RECT  44.016 0 44.04 0.084 ;
    END
  END b[83]
  PIN b[84]
    DIRECTION OUTPUT ;
    USE SIGNAL ;
    PORT
      LAYER M5 ;
        RECT  44.112 0 44.136 0.084 ;
    END
  END b[84]
  PIN b[85]
    DIRECTION OUTPUT ;
    USE SIGNAL ;
    PORT
      LAYER M5 ;
        RECT  44.208 0 44.232 0.084 ;
    END
  END b[85]
  PIN b[86]
    DIRECTION OUTPUT ;
    USE SIGNAL ;
    PORT
      LAYER M5 ;
        RECT  44.304 0 44.328 0.084 ;
    END
  END b[86]
  PIN b[87]
    DIRECTION OUTPUT ;
    USE SIGNAL ;
    PORT
      LAYER M5 ;
        RECT  44.4 0 44.424 0.084 ;
    END
  END b[87]
  PIN b[88]
    DIRECTION OUTPUT ;
    USE SIGNAL ;
    PORT
      LAYER M5 ;
        RECT  44.496 0 44.52 0.084 ;
    END
  END b[88]
  PIN b[89]
    DIRECTION OUTPUT ;
    USE SIGNAL ;
    PORT
      LAYER M5 ;
        RECT  44.592 0 44.616 0.084 ;
    END
  END b[89]
  PIN b[8]
    DIRECTION OUTPUT ;
    USE SIGNAL ;
    PORT
      LAYER M3 ;
        RECT  44.316 0 44.334 0.037 ;
    END
  END b[8]
  PIN b[90]
    DIRECTION OUTPUT ;
    USE SIGNAL ;
    PORT
      LAYER M5 ;
        RECT  44.688 0 44.712 0.084 ;
    END
  END b[90]
  PIN b[91]
    DIRECTION OUTPUT ;
    USE SIGNAL ;
    PORT
      LAYER M5 ;
        RECT  44.784 0 44.808 0.084 ;
    END
  END b[91]
  PIN b[92]
    DIRECTION OUTPUT ;
    USE SIGNAL ;
    PORT
      LAYER M5 ;
        RECT  44.88 0 44.904 0.084 ;
    END
  END b[92]
  PIN b[93]
    DIRECTION OUTPUT ;
    USE SIGNAL ;
    PORT
      LAYER M5 ;
        RECT  44.976 0 45 0.084 ;
    END
  END b[93]
  PIN b[94]
    DIRECTION OUTPUT ;
    USE SIGNAL ;
    PORT
      LAYER M5 ;
        RECT  45.072 0 45.096 0.084 ;
    END
  END b[94]
  PIN b[95]
    DIRECTION OUTPUT ;
    USE SIGNAL ;
    PORT
      LAYER M5 ;
        RECT  45.168 0 45.192 0.084 ;
    END
  END b[95]
  PIN b[96]
    DIRECTION OUTPUT ;
    USE SIGNAL ;
    PORT
      LAYER M3 ;
        RECT  46.044 0 46.062 0.037 ;
    END
  END b[96]
  PIN b[97]
    DIRECTION OUTPUT ;
    USE SIGNAL ;
    PORT
      LAYER M3 ;
        RECT  46.116 0 46.134 0.037 ;
    END
  END b[97]
  PIN b[98]
    DIRECTION OUTPUT ;
    USE SIGNAL ;
    PORT
      LAYER M3 ;
        RECT  46.188 0 46.206 0.037 ;
    END
  END b[98]
  PIN b[99]
    DIRECTION OUTPUT ;
    USE SIGNAL ;
    PORT
      LAYER M3 ;
        RECT  46.26 0 46.278 0.037 ;
    END
  END b[99]
  PIN b[9]
    DIRECTION OUTPUT ;
    USE SIGNAL ;
    PORT
      LAYER M3 ;
        RECT  44.388 0 44.406 0.037 ;
    END
  END b[9]
  PIN ck_o
    DIRECTION OUTPUT ;
    USE SIGNAL ;
    PORT
      LAYER M4 ;
        RECT  104.004 29.904 104.088 29.928 ;
    END
  END ck_o
  PIN ckf
    DIRECTION INPUT ;
    USE SIGNAL ;
    PORT
      LAYER M4 ;
        RECT  104.004 30 104.088 30.024 ;
    END
  END ckf
  PIN ea
    DIRECTION INPUT ;
    USE SIGNAL ;
    PORT
      LAYER M5 ;
        RECT  45.744 60.372 45.768 60.456 ;
    END
  END ea
  PIN eb
    DIRECTION OUTPUT ;
    USE SIGNAL ;
    PORT
      LAYER M3 ;
        RECT  71.388 0 71.406 0.037 ;
    END
  END eb
  PIN VDD
    DIRECTION INOUT ;
    USE POWER ;
    PORT
      LAYER M5 ;
        RECT  99.792 2.151 99.912 58.073 ;
        RECT  97.092 2.151 97.212 58.073 ;
        RECT  94.392 2.151 94.512 58.073 ;
        RECT  91.692 2.151 91.812 58.073 ;
        RECT  88.992 2.151 89.112 58.073 ;
        RECT  86.292 2.151 86.412 58.073 ;
        RECT  83.592 2.151 83.712 58.073 ;
        RECT  80.892 2.151 81.012 58.073 ;
        RECT  78.192 2.151 78.312 58.073 ;
        RECT  75.492 2.151 75.612 58.073 ;
        RECT  72.792 2.151 72.912 58.073 ;
        RECT  70.092 2.151 70.212 58.073 ;
        RECT  67.392 2.151 67.512 58.073 ;
        RECT  64.692 2.151 64.812 58.073 ;
        RECT  61.992 2.151 62.112 58.073 ;
        RECT  59.292 2.151 59.412 58.073 ;
        RECT  56.592 2.151 56.712 58.073 ;
        RECT  53.892 2.151 54.012 58.073 ;
        RECT  51.192 2.151 51.312 58.073 ;
        RECT  48.492 2.151 48.612 58.073 ;
        RECT  45.792 2.151 45.912 58.073 ;
        RECT  43.092 2.151 43.212 58.073 ;
        RECT  40.392 2.151 40.512 58.073 ;
        RECT  37.692 2.151 37.812 58.073 ;
        RECT  34.992 2.151 35.112 58.073 ;
        RECT  32.292 2.151 32.412 58.073 ;
        RECT  29.592 2.151 29.712 58.073 ;
        RECT  26.892 2.151 27.012 58.073 ;
        RECT  24.192 2.151 24.312 58.073 ;
        RECT  21.492 2.151 21.612 58.073 ;
        RECT  18.792 2.151 18.912 58.073 ;
        RECT  16.092 2.151 16.212 58.073 ;
        RECT  13.392 2.151 13.512 58.073 ;
        RECT  10.692 2.151 10.812 58.073 ;
        RECT  7.992 2.151 8.112 58.073 ;
        RECT  5.292 2.151 5.412 58.073 ;
        RECT  2.592 2.151 2.712 58.073 ;
    END
  END VDD
  PIN VSS
    DIRECTION INOUT ;
    USE GROUND ;
    PORT
      LAYER M5 ;
        RECT  99.6 2.137 99.72 58.059 ;
        RECT  96.9 2.137 97.02 58.059 ;
        RECT  94.2 2.137 94.32 58.059 ;
        RECT  91.5 2.137 91.62 58.059 ;
        RECT  88.8 2.137 88.92 58.059 ;
        RECT  86.1 2.137 86.22 58.059 ;
        RECT  83.4 2.137 83.52 58.059 ;
        RECT  80.7 2.137 80.82 58.059 ;
        RECT  78 2.137 78.12 58.059 ;
        RECT  75.3 2.137 75.42 58.059 ;
        RECT  72.6 2.137 72.72 58.059 ;
        RECT  69.9 2.137 70.02 58.059 ;
        RECT  67.2 2.137 67.32 58.059 ;
        RECT  64.5 2.137 64.62 58.059 ;
        RECT  61.8 2.137 61.92 58.059 ;
        RECT  59.1 2.137 59.22 58.059 ;
        RECT  56.4 2.137 56.52 58.059 ;
        RECT  53.7 2.137 53.82 58.059 ;
        RECT  51 2.137 51.12 58.059 ;
        RECT  48.3 2.137 48.42 58.059 ;
        RECT  45.6 2.137 45.72 58.059 ;
        RECT  42.9 2.137 43.02 58.059 ;
        RECT  40.2 2.137 40.32 58.059 ;
        RECT  37.5 2.137 37.62 58.059 ;
        RECT  34.8 2.137 34.92 58.059 ;
        RECT  32.1 2.137 32.22 58.059 ;
        RECT  29.4 2.137 29.52 58.059 ;
        RECT  26.7 2.137 26.82 58.059 ;
        RECT  24 2.137 24.12 58.059 ;
        RECT  21.3 2.137 21.42 58.059 ;
        RECT  18.6 2.137 18.72 58.059 ;
        RECT  15.9 2.137 16.02 58.059 ;
        RECT  13.2 2.137 13.32 58.059 ;
        RECT  10.5 2.137 10.62 58.059 ;
        RECT  7.8 2.137 7.92 58.059 ;
        RECT  5.1 2.137 5.22 58.059 ;
        RECT  2.4 2.137 2.52 58.059 ;
    END
  END VSS
  # OT_OBS_CLOSED layer=M5 d_um=1.536 added=44
  OBS
    LAYER RVTN ;
     RECT  2.16 2.16 101.898 2.295 ;
     RECT  2.16 2.565 101.898 2.835 ;
     RECT  2.16 3.105 101.898 3.375 ;
     RECT  2.16 3.645 101.898 3.915 ;
     RECT  2.16 4.185 101.898 4.455 ;
     RECT  2.16 4.725 101.898 4.995 ;
     RECT  2.16 5.265 101.898 5.535 ;
     RECT  2.16 5.805 101.898 6.075 ;
     RECT  2.16 6.345 101.898 6.615 ;
     RECT  2.16 6.885 101.898 7.155 ;
     RECT  2.16 7.425 101.898 7.695 ;
     RECT  2.16 7.965 101.898 8.235 ;
     RECT  2.16 8.505 101.898 8.775 ;
     RECT  2.16 9.045 101.898 9.315 ;
     RECT  2.16 9.585 101.898 9.855 ;
     RECT  2.16 10.125 101.898 10.395 ;
     RECT  2.16 10.665 101.898 10.935 ;
     RECT  2.16 11.205 101.898 11.475 ;
     RECT  2.16 11.745 101.898 12.015 ;
     RECT  2.16 12.285 101.898 12.555 ;
     RECT  2.16 12.825 101.898 13.095 ;
     RECT  2.16 13.365 101.898 13.635 ;
     RECT  2.16 13.905 101.898 14.175 ;
     RECT  2.16 14.445 101.898 14.715 ;
     RECT  2.16 14.985 101.898 15.255 ;
     RECT  2.16 15.525 101.898 15.795 ;
     RECT  2.16 16.065 101.898 16.335 ;
     RECT  2.16 16.605 101.898 16.875 ;
     RECT  2.16 17.145 101.898 17.415 ;
     RECT  2.16 17.685 101.898 17.955 ;
     RECT  2.16 18.225 101.898 18.495 ;
     RECT  2.16 18.765 101.898 19.035 ;
     RECT  2.16 19.305 101.898 19.575 ;
     RECT  2.16 19.845 101.898 20.115 ;
     RECT  2.16 20.385 101.898 20.655 ;
     RECT  2.16 20.925 101.898 21.195 ;
     RECT  2.16 21.465 101.898 21.735 ;
     RECT  2.16 22.005 101.898 22.275 ;
     RECT  2.16 22.545 101.898 22.815 ;
     RECT  2.16 23.085 101.898 23.355 ;
     RECT  2.16 23.625 101.898 23.895 ;
     RECT  2.16 24.165 101.898 24.435 ;
     RECT  2.16 24.705 101.898 24.975 ;
     RECT  2.16 25.245 101.898 25.515 ;
     RECT  2.16 25.785 101.898 26.055 ;
     RECT  2.16 26.325 101.898 26.595 ;
     RECT  2.16 26.865 101.898 27.135 ;
     RECT  2.16 27.405 101.898 27.675 ;
     RECT  2.16 27.945 101.898 28.215 ;
     RECT  2.16 28.485 101.898 28.755 ;
     RECT  2.16 29.025 101.898 29.295 ;
     RECT  2.16 29.565 101.898 29.835 ;
     RECT  2.16 30.105 101.898 30.375 ;
     RECT  2.16 30.645 101.898 30.915 ;
     RECT  2.16 31.185 101.898 31.455 ;
     RECT  2.16 31.725 101.898 31.995 ;
     RECT  2.16 32.265 101.898 32.535 ;
     RECT  2.16 32.805 101.898 33.075 ;
     RECT  2.16 33.345 101.898 33.615 ;
     RECT  2.16 33.885 101.898 34.155 ;
     RECT  2.16 34.425 101.898 34.695 ;
     RECT  2.16 34.965 101.898 35.235 ;
     RECT  2.16 35.505 101.898 35.775 ;
     RECT  2.16 36.045 101.898 36.315 ;
     RECT  2.16 36.585 101.898 36.855 ;
     RECT  2.16 37.125 101.898 37.395 ;
     RECT  2.16 37.665 101.898 37.935 ;
     RECT  2.16 38.205 101.898 38.475 ;
     RECT  2.16 38.745 101.898 39.015 ;
     RECT  2.16 39.285 101.898 39.555 ;
     RECT  2.16 39.825 101.898 40.095 ;
     RECT  2.16 40.365 101.898 40.635 ;
     RECT  2.16 40.905 101.898 41.175 ;
     RECT  2.16 41.445 101.898 41.715 ;
     RECT  2.16 41.985 101.898 42.255 ;
     RECT  2.16 42.525 101.898 42.795 ;
     RECT  2.16 43.065 101.898 43.335 ;
     RECT  2.16 43.605 101.898 43.875 ;
     RECT  2.16 44.145 101.898 44.415 ;
     RECT  2.16 44.685 101.898 44.955 ;
     RECT  2.16 45.225 101.898 45.495 ;
     RECT  2.16 45.765 101.898 46.035 ;
     RECT  2.16 46.305 101.898 46.575 ;
     RECT  2.16 46.845 101.898 47.115 ;
     RECT  2.16 47.385 101.898 47.655 ;
     RECT  2.16 47.925 101.898 48.195 ;
     RECT  2.16 48.465 101.898 48.735 ;
     RECT  2.16 49.005 101.898 49.275 ;
     RECT  2.16 49.545 101.898 49.815 ;
     RECT  2.16 50.085 101.898 50.355 ;
     RECT  2.16 50.625 101.898 50.895 ;
     RECT  2.16 51.165 101.898 51.435 ;
     RECT  2.16 51.705 101.898 51.975 ;
     RECT  2.16 52.245 101.898 52.515 ;
     RECT  2.16 52.785 101.898 53.055 ;
     RECT  2.16 53.325 101.898 53.595 ;
     RECT  2.16 53.865 101.898 54.135 ;
     RECT  2.16 54.405 101.898 54.675 ;
     RECT  2.16 54.945 101.898 55.215 ;
     RECT  2.16 55.485 101.898 55.755 ;
     RECT  2.16 56.025 101.898 56.295 ;
     RECT  2.16 56.565 101.898 56.835 ;
     RECT  2.16 57.105 101.898 57.375 ;
     RECT  2.16 57.645 101.898 57.915 ;
    LAYER RVTP ;
     RECT  2.16 2.295 101.898 2.565 ;
     RECT  2.16 2.835 101.898 3.105 ;
     RECT  2.16 3.375 101.898 3.645 ;
     RECT  2.16 3.915 101.898 4.185 ;
     RECT  2.16 4.455 101.898 4.725 ;
     RECT  2.16 4.995 101.898 5.265 ;
     RECT  2.16 5.535 101.898 5.805 ;
     RECT  2.16 6.075 101.898 6.345 ;
     RECT  2.16 6.615 101.898 6.885 ;
     RECT  2.16 7.155 101.898 7.425 ;
     RECT  2.16 7.695 101.898 7.965 ;
     RECT  2.16 8.235 101.898 8.505 ;
     RECT  2.16 8.775 101.898 9.045 ;
     RECT  2.16 9.315 101.898 9.585 ;
     RECT  2.16 9.855 101.898 10.125 ;
     RECT  2.16 10.395 101.898 10.665 ;
     RECT  2.16 10.935 101.898 11.205 ;
     RECT  2.16 11.475 101.898 11.745 ;
     RECT  2.16 12.015 101.898 12.285 ;
     RECT  2.16 12.555 101.898 12.825 ;
     RECT  2.16 13.095 101.898 13.365 ;
     RECT  2.16 13.635 101.898 13.905 ;
     RECT  2.16 14.175 101.898 14.445 ;
     RECT  2.16 14.715 101.898 14.985 ;
     RECT  2.16 15.255 101.898 15.525 ;
     RECT  2.16 15.795 101.898 16.065 ;
     RECT  2.16 16.335 101.898 16.605 ;
     RECT  2.16 16.875 101.898 17.145 ;
     RECT  2.16 17.415 101.898 17.685 ;
     RECT  2.16 17.955 101.898 18.225 ;
     RECT  2.16 18.495 101.898 18.765 ;
     RECT  2.16 19.035 101.898 19.305 ;
     RECT  2.16 19.575 101.898 19.845 ;
     RECT  2.16 20.115 101.898 20.385 ;
     RECT  2.16 20.655 101.898 20.925 ;
     RECT  2.16 21.195 101.898 21.465 ;
     RECT  2.16 21.735 101.898 22.005 ;
     RECT  2.16 22.275 101.898 22.545 ;
     RECT  2.16 22.815 101.898 23.085 ;
     RECT  2.16 23.355 101.898 23.625 ;
     RECT  2.16 23.895 101.898 24.165 ;
     RECT  2.16 24.435 101.898 24.705 ;
     RECT  2.16 24.975 101.898 25.245 ;
     RECT  2.16 25.515 101.898 25.785 ;
     RECT  2.16 26.055 101.898 26.325 ;
     RECT  2.16 26.595 101.898 26.865 ;
     RECT  2.16 27.135 101.898 27.405 ;
     RECT  2.16 27.675 101.898 27.945 ;
     RECT  2.16 28.215 101.898 28.485 ;
     RECT  2.16 28.755 101.898 29.025 ;
     RECT  2.16 29.295 101.898 29.565 ;
     RECT  2.16 29.835 101.898 30.105 ;
     RECT  2.16 30.375 101.898 30.645 ;
     RECT  2.16 30.915 101.898 31.185 ;
     RECT  2.16 31.455 101.898 31.725 ;
     RECT  2.16 31.995 101.898 32.265 ;
     RECT  2.16 32.535 101.898 32.805 ;
     RECT  2.16 33.075 101.898 33.345 ;
     RECT  2.16 33.615 101.898 33.885 ;
     RECT  2.16 34.155 101.898 34.425 ;
     RECT  2.16 34.695 101.898 34.965 ;
     RECT  2.16 35.235 101.898 35.505 ;
     RECT  2.16 35.775 101.898 36.045 ;
     RECT  2.16 36.315 101.898 36.585 ;
     RECT  2.16 36.855 101.898 37.125 ;
     RECT  2.16 37.395 101.898 37.665 ;
     RECT  2.16 37.935 101.898 38.205 ;
     RECT  2.16 38.475 101.898 38.745 ;
     RECT  2.16 39.015 101.898 39.285 ;
     RECT  2.16 39.555 101.898 39.825 ;
     RECT  2.16 40.095 101.898 40.365 ;
     RECT  2.16 40.635 101.898 40.905 ;
     RECT  2.16 41.175 101.898 41.445 ;
     RECT  2.16 41.715 101.898 41.985 ;
     RECT  2.16 42.255 101.898 42.525 ;
     RECT  2.16 42.795 101.898 43.065 ;
     RECT  2.16 43.335 101.898 43.605 ;
     RECT  2.16 43.875 101.898 44.145 ;
     RECT  2.16 44.415 101.898 44.685 ;
     RECT  2.16 44.955 101.898 45.225 ;
     RECT  2.16 45.495 101.898 45.765 ;
     RECT  2.16 46.035 101.898 46.305 ;
     RECT  2.16 46.575 101.898 46.845 ;
     RECT  2.16 47.115 101.898 47.385 ;
     RECT  2.16 47.655 101.898 47.925 ;
     RECT  2.16 48.195 101.898 48.465 ;
     RECT  2.16 48.735 101.898 49.005 ;
     RECT  2.16 49.275 101.898 49.545 ;
     RECT  2.16 49.815 101.898 50.085 ;
     RECT  2.16 50.355 101.898 50.625 ;
     RECT  2.16 50.895 101.898 51.165 ;
     RECT  2.16 51.435 101.898 51.705 ;
     RECT  2.16 51.975 101.898 52.245 ;
     RECT  2.16 52.515 101.898 52.785 ;
     RECT  2.16 53.055 101.898 53.325 ;
     RECT  2.16 53.595 101.898 53.865 ;
     RECT  2.16 54.135 101.898 54.405 ;
     RECT  2.16 54.675 101.898 54.945 ;
     RECT  2.16 55.215 101.898 55.485 ;
     RECT  2.16 55.755 101.898 56.025 ;
     RECT  2.16 56.295 101.898 56.565 ;
     RECT  2.16 56.835 101.898 57.105 ;
     RECT  2.16 57.375 101.898 57.645 ;
     RECT  2.16 57.915 101.898 58.05 ;
    LAYER M1 ;
     RECT  2.16 2.151 101.898 58.059 ;
    LAYER M2 ;
     RECT  2.16 2.151 26.779 58.059 ;
     RECT  26.779 2.151 26.851 58.14 ;
     RECT  26.851 2.151 27.355 58.176 ;
     RECT  27.355 2.151 28.327 58.446 ;
     RECT  28.147 59.58 28.327 59.598 ;
     RECT  28.327 2.151 28.435 59.598 ;
     RECT  28.435 2.151 28.579 59.679 ;
     RECT  28.579 2.151 29.147 60.3 ;
     RECT  29.147 2.151 31.999 60.264 ;
     RECT  31.999 2.151 32.315 60.408 ;
     RECT  32.315 2.151 32.387 60.336 ;
     RECT  32.387 2.151 33.115 60.3 ;
     RECT  33.115 2.151 33.475 60.408 ;
     RECT  33.475 2.151 37.435 60.444 ;
     RECT  37.435 1.422 39.199 60.444 ;
     RECT  39.199 1.116 39.983 60.444 ;
     RECT  39.983 1.116 40.163 60.408 ;
     RECT  38.515 0.036 40.351 0.054 ;
     RECT  40.163 1.116 40.451 60.336 ;
     RECT  40.351 0.036 40.891 0.126 ;
     RECT  40.891 0.036 41.323 0.324 ;
     RECT  40.451 1.116 41.323 1.134 ;
     RECT  41.323 0.036 41.639 1.134 ;
     RECT  40.451 2.106 41.899 60.336 ;
     RECT  41.639 0.036 42.179 0.396 ;
     RECT  41.899 2.106 43.439 60.408 ;
     RECT  43.439 58.968 43.547 60.408 ;
     RECT  43.439 2.106 43.835 58.176 ;
     RECT  43.547 58.968 44.527 60.336 ;
     RECT  44.527 58.968 44.915 60.408 ;
     RECT  44.915 59.544 44.987 60.408 ;
     RECT  44.987 59.544 45.059 59.562 ;
     RECT  43.835 2.106 45.067 58.14 ;
     RECT  42.179 0.036 45.607 0.279 ;
     RECT  45.607 0.036 45.643 0.864 ;
     RECT  45.067 2.034 45.643 58.14 ;
     RECT  44.987 60.318 45.895 60.408 ;
     RECT  45.895 60.282 46.759 60.408 ;
     RECT  46.759 60.246 47.011 60.408 ;
     RECT  47.011 60.156 47.083 60.408 ;
     RECT  47.083 60.084 47.479 60.408 ;
     RECT  47.407 58.896 47.507 58.914 ;
     RECT  47.479 59.886 47.651 60.408 ;
     RECT  47.651 59.931 47.687 60.408 ;
     RECT  45.643 0.036 48.191 58.14 ;
     RECT  47.687 60.282 48.487 60.408 ;
     RECT  48.487 60.201 48.523 60.408 ;
     RECT  48.523 60.048 48.803 60.408 ;
     RECT  48.803 60.246 49.783 60.408 ;
     RECT  49.783 60.201 49.891 60.408 ;
     RECT  49.891 60.156 50.171 60.408 ;
     RECT  50.171 60.201 51.071 60.408 ;
     RECT  48.191 0.036 51.827 58.104 ;
     RECT  51.071 60.246 52.411 60.408 ;
     RECT  51.827 0.036 52.663 58.059 ;
     RECT  52.411 60.201 52.763 60.408 ;
     RECT  52.763 60.246 53.599 60.408 ;
     RECT  53.599 59.742 53.843 60.408 ;
     RECT  53.843 60.156 54.527 60.408 ;
     RECT  54.527 60.201 55.543 60.408 ;
     RECT  55.543 60.156 55.723 60.408 ;
     RECT  52.663 0.036 56.083 58.716 ;
     RECT  55.723 60.012 57.911 60.408 ;
     RECT  56.083 0.036 58.207 58.986 ;
     RECT  57.911 60.012 58.207 60.336 ;
     RECT  58.207 0.036 59.035 60.336 ;
     RECT  59.035 0.036 59.395 60.408 ;
     RECT  59.395 0.036 59.531 60.444 ;
     RECT  59.531 0.036 59.567 0.054 ;
     RECT  59.531 0.846 60.143 60.444 ;
     RECT  60.143 0.918 60.215 60.444 ;
     RECT  60.439 0.036 60.475 0.054 ;
     RECT  60.215 1.8 60.791 60.444 ;
     RECT  60.215 0.918 61.051 1.044 ;
     RECT  60.475 0.036 61.159 0.126 ;
     RECT  61.051 0.918 61.159 1.17 ;
     RECT  61.159 0.036 61.331 1.17 ;
     RECT  61.331 0.036 61.835 0.279 ;
     RECT  61.331 1.152 62.051 1.17 ;
     RECT  60.791 2.106 62.779 60.444 ;
     RECT  61.835 0.036 64.435 0.054 ;
     RECT  64.435 0.036 64.471 0.126 ;
     RECT  64.471 0.036 64.651 0.234 ;
     RECT  64.651 0.036 64.787 0.279 ;
     RECT  64.787 0.036 64.967 0.126 ;
     RECT  62.779 1.998 65.011 60.444 ;
     RECT  65.011 1.728 65.219 60.444 ;
     RECT  64.967 0.108 65.327 0.126 ;
     RECT  65.219 1.998 65.399 60.444 ;
     RECT  65.399 2.151 66.523 60.444 ;
     RECT  66.523 1.728 67.235 60.444 ;
     RECT  66.307 0.306 67.279 0.324 ;
     RECT  67.279 0.306 67.351 0.36 ;
     RECT  67.351 0.144 67.423 0.36 ;
     RECT  67.423 0.036 67.703 0.36 ;
     RECT  67.703 0.036 68.747 0.324 ;
     RECT  67.235 2.151 69.035 60.444 ;
     RECT  68.747 0.306 69.251 0.324 ;
     RECT  69.035 59.544 69.359 60.444 ;
     RECT  69.763 0.108 69.835 0.126 ;
     RECT  69.359 60.354 70.007 60.444 ;
     RECT  69.835 0.036 70.043 0.126 ;
     RECT  69.035 2.151 70.087 58.446 ;
     RECT  70.087 1.494 70.259 58.446 ;
     RECT  70.259 1.494 70.367 58.104 ;
     RECT  70.043 0.036 70.619 0.054 ;
     RECT  69.359 59.544 70.727 59.562 ;
     RECT  70.367 2.151 70.763 58.104 ;
     RECT  70.007 60.39 70.979 60.444 ;
     RECT  70.763 2.151 71.383 58.059 ;
     RECT  71.383 1.728 71.519 58.059 ;
     RECT  71.519 2.151 71.779 58.059 ;
     RECT  70.979 60.39 72.095 60.408 ;
     RECT  71.779 2.151 73.499 58.104 ;
     RECT  73.499 2.151 101.898 58.059 ;
    LAYER M3 ;
     RECT  40.878 0.012 40.932 0.031 ;
     RECT  40.95 0.012 41.004 0.031 ;
     RECT  41.022 0.012 41.076 0.031 ;
     RECT  41.094 0.012 41.148 0.031 ;
     RECT  41.166 0.012 41.22 0.031 ;
     RECT  41.238 0.012 41.292 0.031 ;
     RECT  41.31 0.012 41.364 0.031 ;
     RECT  41.382 0.012 41.436 0.031 ;
     RECT  41.454 0.012 41.508 0.031 ;
     RECT  41.526 0.012 41.58 0.031 ;
     RECT  41.598 0.012 41.652 0.031 ;
     RECT  41.67 0.012 41.724 0.031 ;
     RECT  41.742 0.012 41.796 0.031 ;
     RECT  41.814 0.012 41.868 0.031 ;
     RECT  41.886 0.012 41.94 0.031 ;
     RECT  41.958 0.012 42.012 0.031 ;
     RECT  42.03 0.012 42.084 0.031 ;
     RECT  42.102 0.012 42.156 0.031 ;
     RECT  42.174 0.012 42.228 0.031 ;
     RECT  42.246 0.012 42.3 0.031 ;
     RECT  42.318 0.012 42.372 0.031 ;
     RECT  42.39 0.012 42.444 0.031 ;
     RECT  42.462 0.012 42.516 0.031 ;
     RECT  42.534 0.012 42.588 0.031 ;
     RECT  42.606 0.012 42.66 0.031 ;
     RECT  42.678 0.012 42.732 0.031 ;
     RECT  42.75 0.012 42.804 0.031 ;
     RECT  42.822 0.012 42.876 0.031 ;
     RECT  42.894 0.012 42.948 0.031 ;
     RECT  42.966 0.012 43.02 0.031 ;
     RECT  43.038 0.012 43.092 0.031 ;
     RECT  43.11 0.012 43.74 0.031 ;
     RECT  43.758 0.012 43.812 0.031 ;
     RECT  43.83 0.012 43.884 0.031 ;
     RECT  43.902 0.012 43.956 0.031 ;
     RECT  43.974 0.012 44.028 0.031 ;
     RECT  44.046 0.012 44.1 0.031 ;
     RECT  44.118 0.012 44.172 0.031 ;
     RECT  44.19 0.012 44.244 0.031 ;
     RECT  44.262 0.012 44.316 0.031 ;
     RECT  44.334 0.012 44.388 0.031 ;
     RECT  44.406 0.012 44.46 0.031 ;
     RECT  44.478 0.012 44.532 0.031 ;
     RECT  44.55 0.012 44.604 0.031 ;
     RECT  44.622 0.012 44.676 0.031 ;
     RECT  44.694 0.012 44.748 0.031 ;
     RECT  44.766 0.012 44.82 0.031 ;
     RECT  44.838 0.012 44.892 0.031 ;
     RECT  44.91 0.012 44.964 0.031 ;
     RECT  44.982 0.012 45.036 0.031 ;
     RECT  45.054 0.012 45.108 0.031 ;
     RECT  45.126 0.012 45.18 0.031 ;
     RECT  45.198 0.012 45.252 0.031 ;
     RECT  45.27 0.012 45.324 0.031 ;
     RECT  45.342 0.012 45.396 0.031 ;
     RECT  45.414 0.012 45.468 0.031 ;
     RECT  45.486 0.012 45.54 0.031 ;
     RECT  45.558 0.012 45.612 0.031 ;
     RECT  45.63 0.012 45.684 0.031 ;
     RECT  45.702 0.012 45.756 0.031 ;
     RECT  45.774 0.012 45.828 0.031 ;
     RECT  45.846 0.012 45.9 0.031 ;
     RECT  45.918 0.012 45.972 0.031 ;
     RECT  45.99 0.012 46.044 0.031 ;
     RECT  46.062 0.012 46.116 0.031 ;
     RECT  46.134 0.012 46.188 0.031 ;
     RECT  46.206 0.012 46.26 0.031 ;
     RECT  46.278 0.012 46.332 0.031 ;
     RECT  46.35 0.012 46.404 0.031 ;
     RECT  46.422 0.012 46.476 0.031 ;
     RECT  46.494 0.012 46.548 0.031 ;
     RECT  46.566 0.012 46.62 0.031 ;
     RECT  46.638 0.012 46.692 0.031 ;
     RECT  46.71 0.012 46.764 0.031 ;
     RECT  46.782 0.012 46.836 0.031 ;
     RECT  46.854 0.012 46.908 0.031 ;
     RECT  46.926 0.012 46.98 0.031 ;
     RECT  46.998 0.012 47.052 0.031 ;
     RECT  47.07 0.012 47.124 0.031 ;
     RECT  47.142 0.012 47.196 0.031 ;
     RECT  47.214 0.012 47.268 0.031 ;
     RECT  47.286 0.012 47.34 0.031 ;
     RECT  47.358 0.012 47.412 0.031 ;
     RECT  47.43 0.012 47.484 0.031 ;
     RECT  47.502 0.012 47.556 0.031 ;
     RECT  47.574 0.012 47.628 0.031 ;
     RECT  47.646 0.012 47.7 0.031 ;
     RECT  47.718 0.012 47.772 0.031 ;
     RECT  47.79 0.012 47.844 0.031 ;
     RECT  47.862 0.012 47.916 0.031 ;
     RECT  47.934 0.012 47.988 0.031 ;
     RECT  48.006 0.012 48.06 0.031 ;
     RECT  48.078 0.012 48.132 0.031 ;
     RECT  48.15 0.012 48.204 0.031 ;
     RECT  48.222 0.012 48.276 0.031 ;
     RECT  48.294 0.012 48.348 0.031 ;
     RECT  48.366 0.012 48.42 0.031 ;
     RECT  48.438 0.012 48.492 0.031 ;
     RECT  48.51 0.012 48.564 0.031 ;
     RECT  48.582 0.012 48.636 0.031 ;
     RECT  48.654 0.012 48.708 0.031 ;
     RECT  48.726 0.012 48.78 0.031 ;
     RECT  48.798 0.012 48.852 0.031 ;
     RECT  48.87 0.012 48.924 0.031 ;
     RECT  48.942 0.012 48.996 0.031 ;
     RECT  49.014 0.012 49.068 0.031 ;
     RECT  49.086 0.012 49.14 0.031 ;
     RECT  49.158 0.012 49.212 0.031 ;
     RECT  49.23 0.012 49.284 0.031 ;
     RECT  49.302 0.012 49.356 0.031 ;
     RECT  49.374 0.012 49.428 0.031 ;
     RECT  49.446 0.012 49.5 0.031 ;
     RECT  49.518 0.012 49.572 0.031 ;
     RECT  49.59 0.012 49.644 0.031 ;
     RECT  49.662 0.012 49.716 0.031 ;
     RECT  49.734 0.012 49.788 0.031 ;
     RECT  49.806 0.012 49.86 0.031 ;
     RECT  49.878 0.012 49.932 0.031 ;
     RECT  49.95 0.012 50.004 0.031 ;
     RECT  50.022 0.012 50.076 0.031 ;
     RECT  50.094 0.012 50.148 0.031 ;
     RECT  50.166 0.012 50.22 0.031 ;
     RECT  50.238 0.012 50.292 0.031 ;
     RECT  50.31 0.012 50.364 0.031 ;
     RECT  50.382 0.012 50.436 0.031 ;
     RECT  50.454 0.012 50.508 0.031 ;
     RECT  50.526 0.012 50.58 0.031 ;
     RECT  50.598 0.012 50.652 0.031 ;
     RECT  50.67 0.012 50.724 0.031 ;
     RECT  50.742 0.012 50.796 0.031 ;
     RECT  50.814 0.012 50.868 0.031 ;
     RECT  50.886 0.012 50.94 0.031 ;
     RECT  50.958 0.012 51.012 0.031 ;
     RECT  51.03 0.012 51.084 0.031 ;
     RECT  51.102 0.012 51.156 0.031 ;
     RECT  51.174 0.012 51.228 0.031 ;
     RECT  51.246 0.012 51.3 0.031 ;
     RECT  51.318 0.012 51.372 0.031 ;
     RECT  51.39 0.012 51.444 0.031 ;
     RECT  51.462 0.012 51.516 0.031 ;
     RECT  51.534 0.012 51.588 0.031 ;
     RECT  51.606 0.012 51.66 0.031 ;
     RECT  51.678 0.012 51.732 0.031 ;
     RECT  51.75 0.012 51.804 0.031 ;
     RECT  51.822 0.012 51.876 0.031 ;
     RECT  51.894 0.012 51.948 0.031 ;
     RECT  51.966 0.012 52.02 0.031 ;
     RECT  52.038 0.012 52.092 0.031 ;
     RECT  52.11 0.012 52.164 0.031 ;
     RECT  52.182 0.012 52.236 0.031 ;
     RECT  52.254 0.012 52.308 0.031 ;
     RECT  52.326 0.012 52.38 0.031 ;
     RECT  52.398 0.012 52.452 0.031 ;
     RECT  52.47 0.012 52.524 0.031 ;
     RECT  52.542 0.012 52.596 0.031 ;
     RECT  52.614 0.012 52.668 0.031 ;
     RECT  52.686 0.012 52.74 0.031 ;
     RECT  52.758 0.012 52.812 0.031 ;
     RECT  52.83 0.012 52.884 0.031 ;
     RECT  52.902 0.012 52.956 0.031 ;
     RECT  52.974 0.012 53.028 0.031 ;
     RECT  53.046 0.012 53.1 0.031 ;
     RECT  53.118 0.012 53.172 0.031 ;
     RECT  53.19 0.012 53.244 0.031 ;
     RECT  53.262 0.012 53.316 0.031 ;
     RECT  53.334 0.012 53.388 0.031 ;
     RECT  53.406 0.012 53.46 0.031 ;
     RECT  53.478 0.012 53.532 0.031 ;
     RECT  53.55 0.012 53.604 0.031 ;
     RECT  53.622 0.012 53.676 0.031 ;
     RECT  53.694 0.012 53.748 0.031 ;
     RECT  53.766 0.012 53.82 0.031 ;
     RECT  53.838 0.012 53.892 0.031 ;
     RECT  53.91 0.012 53.964 0.031 ;
     RECT  53.982 0.012 54.036 0.031 ;
     RECT  54.054 0.012 54.108 0.031 ;
     RECT  54.126 0.012 54.18 0.031 ;
     RECT  54.198 0.012 54.252 0.031 ;
     RECT  54.27 0.012 54.324 0.031 ;
     RECT  54.342 0.012 54.396 0.031 ;
     RECT  54.414 0.012 54.468 0.031 ;
     RECT  54.486 0.012 54.54 0.031 ;
     RECT  54.558 0.012 54.612 0.031 ;
     RECT  54.63 0.012 54.684 0.031 ;
     RECT  54.702 0.012 54.756 0.031 ;
     RECT  54.774 0.012 54.828 0.031 ;
     RECT  54.846 0.012 54.9 0.031 ;
     RECT  54.918 0.012 54.972 0.031 ;
     RECT  54.99 0.012 55.044 0.031 ;
     RECT  55.062 0.012 55.116 0.031 ;
     RECT  55.134 0.012 55.188 0.031 ;
     RECT  55.206 0.012 55.26 0.031 ;
     RECT  55.278 0.012 55.332 0.031 ;
     RECT  55.35 0.012 55.404 0.031 ;
     RECT  55.422 0.012 55.476 0.031 ;
     RECT  55.494 0.012 55.548 0.031 ;
     RECT  55.566 0.012 55.62 0.031 ;
     RECT  55.638 0.012 55.692 0.031 ;
     RECT  55.71 0.012 55.764 0.031 ;
     RECT  55.782 0.012 55.836 0.031 ;
     RECT  55.854 0.012 55.908 0.031 ;
     RECT  55.926 0.012 55.98 0.031 ;
     RECT  55.998 0.012 56.052 0.031 ;
     RECT  56.07 0.012 56.124 0.031 ;
     RECT  56.142 0.012 56.196 0.031 ;
     RECT  56.214 0.012 56.268 0.031 ;
     RECT  56.286 0.012 56.34 0.031 ;
     RECT  56.358 0.012 56.412 0.031 ;
     RECT  56.43 0.012 56.484 0.031 ;
     RECT  56.502 0.012 56.556 0.031 ;
     RECT  56.574 0.012 56.628 0.031 ;
     RECT  56.646 0.012 56.7 0.031 ;
     RECT  56.718 0.012 56.772 0.031 ;
     RECT  56.79 0.012 56.844 0.031 ;
     RECT  56.862 0.012 56.916 0.031 ;
     RECT  56.934 0.012 56.988 0.031 ;
     RECT  57.006 0.012 57.06 0.031 ;
     RECT  57.078 0.012 57.132 0.031 ;
     RECT  57.15 0.012 57.204 0.031 ;
     RECT  57.222 0.012 57.276 0.031 ;
     RECT  57.294 0.012 57.348 0.031 ;
     RECT  57.366 0.012 57.42 0.031 ;
     RECT  57.438 0.012 57.492 0.031 ;
     RECT  57.51 0.012 58.14 0.031 ;
     RECT  58.158 0.012 58.212 0.031 ;
     RECT  58.23 0.012 58.284 0.031 ;
     RECT  58.302 0.012 58.356 0.031 ;
     RECT  58.374 0.012 58.428 0.031 ;
     RECT  58.446 0.012 58.5 0.031 ;
     RECT  58.518 0.012 58.572 0.031 ;
     RECT  58.59 0.012 58.644 0.031 ;
     RECT  58.662 0.012 58.716 0.031 ;
     RECT  58.734 0.012 58.788 0.031 ;
     RECT  58.806 0.012 58.86 0.031 ;
     RECT  58.878 0.012 58.932 0.031 ;
     RECT  58.95 0.012 59.004 0.031 ;
     RECT  59.022 0.012 59.076 0.031 ;
     RECT  59.094 0.012 59.148 0.031 ;
     RECT  59.166 0.012 59.22 0.031 ;
     RECT  59.238 0.012 59.292 0.031 ;
     RECT  59.31 0.012 59.364 0.031 ;
     RECT  59.382 0.012 59.436 0.031 ;
     RECT  59.454 0.012 59.508 0.031 ;
     RECT  59.526 0.012 59.58 0.031 ;
     RECT  59.598 0.012 59.652 0.031 ;
     RECT  59.67 0.012 59.724 0.031 ;
     RECT  59.742 0.012 59.796 0.031 ;
     RECT  59.814 0.012 59.868 0.031 ;
     RECT  59.886 0.012 59.94 0.031 ;
     RECT  59.958 0.012 60.012 0.031 ;
     RECT  60.03 0.012 60.084 0.031 ;
     RECT  60.102 0.012 60.156 0.031 ;
     RECT  60.174 0.012 60.228 0.031 ;
     RECT  60.246 0.012 60.3 0.031 ;
     RECT  60.318 0.012 60.372 0.031 ;
     RECT  60.39 0.012 60.444 0.031 ;
     RECT  60.462 0.012 60.516 0.031 ;
     RECT  60.534 0.012 60.588 0.031 ;
     RECT  60.606 0.012 60.66 0.031 ;
     RECT  60.678 0.012 60.732 0.031 ;
     RECT  60.75 0.012 60.804 0.031 ;
     RECT  60.822 0.012 60.876 0.031 ;
     RECT  60.894 0.012 60.948 0.031 ;
     RECT  60.966 0.012 61.02 0.031 ;
     RECT  61.038 0.012 61.092 0.031 ;
     RECT  61.11 0.012 61.164 0.031 ;
     RECT  61.182 0.012 61.236 0.031 ;
     RECT  61.254 0.012 61.308 0.031 ;
     RECT  61.326 0.012 61.38 0.031 ;
     RECT  61.398 0.012 61.452 0.031 ;
     RECT  61.47 0.012 61.524 0.031 ;
     RECT  61.542 0.012 61.596 0.031 ;
     RECT  61.614 0.012 61.668 0.031 ;
     RECT  61.686 0.012 61.74 0.031 ;
     RECT  61.758 0.012 61.812 0.031 ;
     RECT  61.83 0.012 61.884 0.031 ;
     RECT  61.902 0.012 61.956 0.031 ;
     RECT  61.974 0.012 62.028 0.031 ;
     RECT  62.046 0.012 62.1 0.031 ;
     RECT  62.118 0.012 62.172 0.031 ;
     RECT  62.19 0.012 62.244 0.031 ;
     RECT  62.262 0.012 62.316 0.031 ;
     RECT  62.334 0.012 62.388 0.031 ;
     RECT  62.406 0.012 62.46 0.031 ;
     RECT  62.478 0.012 62.532 0.031 ;
     RECT  62.55 0.012 62.604 0.031 ;
     RECT  62.622 0.012 62.676 0.031 ;
     RECT  62.694 0.012 62.748 0.031 ;
     RECT  62.766 0.012 62.82 0.031 ;
     RECT  62.838 0.012 62.892 0.031 ;
     RECT  62.91 0.012 62.964 0.031 ;
     RECT  62.982 0.012 63.036 0.031 ;
     RECT  63.054 0.012 63.108 0.031 ;
     RECT  63.126 0.012 63.18 0.031 ;
     RECT  63.198 0.012 63.252 0.031 ;
     RECT  63.27 0.012 63.324 0.031 ;
     RECT  63.342 0.012 63.396 0.031 ;
     RECT  63.414 0.012 63.468 0.031 ;
     RECT  63.486 0.012 63.54 0.031 ;
     RECT  63.558 0.012 63.612 0.031 ;
     RECT  63.63 0.012 63.684 0.031 ;
     RECT  63.702 0.012 63.756 0.031 ;
     RECT  63.774 0.012 63.828 0.031 ;
     RECT  63.846 0.012 63.9 0.031 ;
     RECT  63.918 0.012 63.972 0.031 ;
     RECT  63.99 0.012 64.044 0.031 ;
     RECT  64.062 0.012 64.116 0.031 ;
     RECT  64.134 0.012 64.188 0.031 ;
     RECT  64.206 0.012 64.26 0.031 ;
     RECT  64.278 0.012 64.332 0.031 ;
     RECT  64.35 0.012 64.404 0.031 ;
     RECT  64.422 0.012 64.476 0.031 ;
     RECT  64.494 0.012 64.548 0.031 ;
     RECT  64.566 0.012 64.62 0.031 ;
     RECT  64.638 0.012 64.692 0.031 ;
     RECT  64.71 0.012 64.764 0.031 ;
     RECT  64.782 0.012 64.836 0.031 ;
     RECT  64.854 0.012 64.908 0.031 ;
     RECT  64.926 0.012 64.98 0.031 ;
     RECT  64.998 0.012 65.052 0.031 ;
     RECT  65.07 0.012 65.124 0.031 ;
     RECT  65.142 0.012 65.196 0.031 ;
     RECT  65.214 0.012 65.268 0.031 ;
     RECT  65.286 0.012 65.34 0.031 ;
     RECT  65.358 0.012 65.412 0.031 ;
     RECT  65.43 0.012 65.484 0.031 ;
     RECT  65.502 0.012 65.556 0.031 ;
     RECT  65.574 0.012 65.628 0.031 ;
     RECT  65.646 0.012 65.7 0.031 ;
     RECT  65.718 0.012 65.772 0.031 ;
     RECT  65.79 0.012 65.844 0.031 ;
     RECT  65.862 0.012 65.916 0.031 ;
     RECT  65.934 0.012 65.988 0.031 ;
     RECT  66.006 0.012 66.06 0.031 ;
     RECT  66.078 0.012 66.132 0.031 ;
     RECT  66.15 0.012 66.204 0.031 ;
     RECT  66.222 0.012 66.276 0.031 ;
     RECT  66.294 0.012 66.348 0.031 ;
     RECT  66.366 0.012 66.42 0.031 ;
     RECT  66.438 0.012 66.492 0.031 ;
     RECT  66.51 0.012 66.564 0.031 ;
     RECT  66.582 0.012 66.636 0.031 ;
     RECT  66.654 0.012 66.708 0.031 ;
     RECT  66.726 0.012 66.78 0.031 ;
     RECT  66.798 0.012 66.852 0.031 ;
     RECT  66.87 0.012 66.924 0.031 ;
     RECT  66.942 0.012 66.996 0.031 ;
     RECT  67.014 0.012 67.068 0.031 ;
     RECT  67.086 0.012 67.14 0.031 ;
     RECT  67.158 0.012 67.212 0.031 ;
     RECT  67.23 0.012 67.284 0.031 ;
     RECT  67.302 0.012 67.356 0.031 ;
     RECT  67.374 0.012 67.428 0.031 ;
     RECT  67.446 0.012 67.5 0.031 ;
     RECT  67.518 0.012 67.572 0.031 ;
     RECT  67.59 0.012 67.644 0.031 ;
     RECT  67.662 0.012 67.716 0.031 ;
     RECT  67.734 0.012 67.788 0.031 ;
     RECT  67.806 0.012 67.86 0.031 ;
     RECT  67.878 0.012 67.932 0.031 ;
     RECT  67.95 0.012 68.004 0.031 ;
     RECT  68.022 0.012 68.076 0.031 ;
     RECT  68.094 0.012 68.148 0.031 ;
     RECT  68.166 0.012 68.22 0.031 ;
     RECT  68.238 0.012 68.292 0.031 ;
     RECT  68.31 0.012 68.364 0.031 ;
     RECT  68.382 0.012 68.436 0.031 ;
     RECT  68.454 0.012 68.508 0.031 ;
     RECT  68.526 0.012 68.58 0.031 ;
     RECT  68.598 0.012 68.652 0.031 ;
     RECT  68.67 0.012 68.724 0.031 ;
     RECT  68.742 0.012 68.796 0.031 ;
     RECT  68.814 0.012 68.868 0.031 ;
     RECT  68.886 0.012 68.94 0.031 ;
     RECT  68.958 0.012 69.012 0.031 ;
     RECT  69.03 0.012 69.084 0.031 ;
     RECT  69.102 0.012 69.156 0.031 ;
     RECT  69.174 0.012 69.228 0.031 ;
     RECT  69.246 0.012 69.3 0.031 ;
     RECT  69.318 0.012 69.372 0.031 ;
     RECT  69.39 0.012 69.444 0.031 ;
     RECT  69.462 0.012 69.516 0.031 ;
     RECT  69.534 0.012 69.588 0.031 ;
     RECT  69.606 0.012 69.66 0.031 ;
     RECT  69.678 0.012 69.732 0.031 ;
     RECT  69.75 0.012 69.804 0.031 ;
     RECT  69.822 0.012 69.876 0.031 ;
     RECT  69.894 0.012 69.948 0.031 ;
     RECT  69.966 0.012 70.02 0.031 ;
     RECT  70.038 0.012 70.092 0.031 ;
     RECT  70.11 0.012 70.164 0.031 ;
     RECT  70.182 0.012 70.236 0.031 ;
     RECT  70.254 0.012 70.308 0.031 ;
     RECT  70.326 0.012 70.38 0.031 ;
     RECT  70.398 0.012 70.452 0.031 ;
     RECT  70.47 0.012 70.524 0.031 ;
     RECT  70.542 0.012 70.596 0.031 ;
     RECT  70.614 0.012 70.668 0.031 ;
     RECT  70.686 0.012 70.74 0.031 ;
     RECT  70.758 0.012 70.812 0.031 ;
     RECT  70.83 0.012 70.884 0.031 ;
     RECT  70.902 0.012 70.956 0.031 ;
     RECT  70.974 0.012 71.028 0.031 ;
     RECT  71.046 0.012 71.1 0.031 ;
     RECT  71.118 0.012 71.172 0.031 ;
     RECT  71.19 0.012 71.244 0.031 ;
     RECT  71.262 0.012 71.316 0.031 ;
     RECT  71.334 0.012 71.388 0.031 ;
     RECT  38.52 0.031 38.538 0.091 ;
     RECT  37.044 0.043 37.062 0.139 ;
     RECT  38.52 0.091 39.33 0.187 ;
     RECT  40.356 0.031 40.86 0.037 ;
     RECT  40.878 0.031 40.932 0.037 ;
     RECT  40.95 0.031 41.004 0.037 ;
     RECT  41.022 0.031 41.076 0.037 ;
     RECT  41.094 0.031 41.148 0.037 ;
     RECT  41.166 0.031 41.22 0.037 ;
     RECT  41.238 0.031 41.292 0.037 ;
     RECT  41.31 0.031 41.364 0.037 ;
     RECT  41.382 0.031 41.436 0.037 ;
     RECT  41.454 0.031 41.508 0.037 ;
     RECT  41.526 0.031 41.58 0.037 ;
     RECT  41.598 0.031 41.652 0.037 ;
     RECT  41.67 0.031 41.724 0.037 ;
     RECT  41.742 0.031 41.796 0.037 ;
     RECT  41.814 0.031 41.868 0.037 ;
     RECT  41.886 0.031 41.94 0.037 ;
     RECT  41.958 0.031 42.012 0.037 ;
     RECT  42.03 0.031 42.084 0.037 ;
     RECT  42.102 0.031 42.156 0.037 ;
     RECT  42.174 0.031 42.228 0.037 ;
     RECT  42.246 0.031 42.3 0.037 ;
     RECT  42.318 0.031 42.372 0.037 ;
     RECT  42.39 0.031 42.444 0.037 ;
     RECT  42.462 0.031 42.516 0.037 ;
     RECT  42.534 0.031 42.588 0.037 ;
     RECT  42.606 0.031 42.66 0.037 ;
     RECT  42.678 0.031 42.732 0.037 ;
     RECT  42.75 0.031 42.804 0.037 ;
     RECT  42.822 0.031 42.876 0.037 ;
     RECT  42.894 0.031 42.948 0.037 ;
     RECT  42.966 0.031 43.02 0.037 ;
     RECT  43.038 0.031 43.092 0.037 ;
     RECT  43.11 0.031 43.74 0.037 ;
     RECT  43.758 0.031 43.812 0.037 ;
     RECT  43.83 0.031 43.884 0.037 ;
     RECT  43.902 0.031 43.956 0.037 ;
     RECT  43.974 0.031 44.028 0.037 ;
     RECT  44.046 0.031 44.1 0.037 ;
     RECT  44.118 0.031 44.172 0.037 ;
     RECT  44.19 0.031 44.244 0.037 ;
     RECT  44.262 0.031 44.316 0.037 ;
     RECT  44.334 0.031 44.388 0.037 ;
     RECT  44.406 0.031 44.46 0.037 ;
     RECT  44.478 0.031 44.532 0.037 ;
     RECT  44.55 0.031 44.604 0.037 ;
     RECT  44.622 0.031 44.676 0.037 ;
     RECT  44.694 0.031 44.748 0.037 ;
     RECT  44.766 0.031 44.82 0.037 ;
     RECT  44.838 0.031 44.892 0.037 ;
     RECT  44.91 0.031 44.964 0.037 ;
     RECT  44.982 0.031 45.036 0.037 ;
     RECT  45.054 0.031 45.108 0.037 ;
     RECT  45.126 0.031 45.18 0.037 ;
     RECT  45.198 0.031 45.252 0.037 ;
     RECT  45.27 0.031 45.324 0.037 ;
     RECT  45.342 0.031 45.396 0.037 ;
     RECT  45.414 0.031 45.468 0.037 ;
     RECT  45.486 0.031 45.54 0.037 ;
     RECT  45.558 0.031 45.612 0.037 ;
     RECT  45.63 0.031 45.684 0.037 ;
     RECT  45.702 0.031 45.756 0.037 ;
     RECT  45.774 0.031 45.828 0.037 ;
     RECT  45.846 0.031 45.9 0.037 ;
     RECT  45.918 0.031 45.972 0.037 ;
     RECT  45.99 0.031 46.044 0.037 ;
     RECT  46.062 0.031 46.116 0.037 ;
     RECT  46.134 0.031 46.188 0.037 ;
     RECT  46.206 0.031 46.26 0.037 ;
     RECT  46.278 0.031 46.332 0.037 ;
     RECT  46.35 0.031 46.404 0.037 ;
     RECT  46.422 0.031 46.476 0.037 ;
     RECT  46.494 0.031 46.548 0.037 ;
     RECT  46.566 0.031 46.62 0.037 ;
     RECT  46.638 0.031 46.692 0.037 ;
     RECT  46.71 0.031 46.764 0.037 ;
     RECT  46.782 0.031 46.836 0.037 ;
     RECT  46.854 0.031 46.908 0.037 ;
     RECT  46.926 0.031 46.98 0.037 ;
     RECT  46.998 0.031 47.052 0.037 ;
     RECT  47.07 0.031 47.124 0.037 ;
     RECT  47.142 0.031 47.196 0.037 ;
     RECT  47.214 0.031 47.268 0.037 ;
     RECT  47.286 0.031 47.34 0.037 ;
     RECT  47.358 0.031 47.412 0.037 ;
     RECT  47.43 0.031 47.484 0.037 ;
     RECT  47.502 0.031 47.556 0.037 ;
     RECT  47.574 0.031 47.628 0.037 ;
     RECT  47.646 0.031 47.7 0.037 ;
     RECT  47.718 0.031 47.772 0.037 ;
     RECT  47.79 0.031 47.844 0.037 ;
     RECT  47.862 0.031 47.916 0.037 ;
     RECT  47.934 0.031 47.988 0.037 ;
     RECT  48.006 0.031 48.06 0.037 ;
     RECT  48.078 0.031 48.132 0.037 ;
     RECT  48.15 0.031 48.204 0.037 ;
     RECT  48.222 0.031 48.276 0.037 ;
     RECT  48.294 0.031 48.348 0.037 ;
     RECT  48.366 0.031 48.42 0.037 ;
     RECT  48.438 0.031 48.492 0.037 ;
     RECT  48.51 0.031 48.564 0.037 ;
     RECT  48.582 0.031 48.636 0.037 ;
     RECT  48.654 0.031 48.708 0.037 ;
     RECT  48.726 0.031 48.78 0.037 ;
     RECT  48.798 0.031 48.852 0.037 ;
     RECT  48.87 0.031 48.924 0.037 ;
     RECT  48.942 0.031 48.996 0.037 ;
     RECT  49.014 0.031 49.068 0.037 ;
     RECT  49.086 0.031 49.14 0.037 ;
     RECT  49.158 0.031 49.212 0.037 ;
     RECT  49.23 0.031 49.284 0.037 ;
     RECT  49.302 0.031 49.356 0.037 ;
     RECT  49.374 0.031 49.428 0.037 ;
     RECT  49.446 0.031 49.5 0.037 ;
     RECT  49.518 0.031 49.572 0.037 ;
     RECT  49.59 0.031 49.644 0.037 ;
     RECT  49.662 0.031 49.716 0.037 ;
     RECT  49.734 0.031 49.788 0.037 ;
     RECT  49.806 0.031 49.86 0.037 ;
     RECT  49.878 0.031 49.932 0.037 ;
     RECT  49.95 0.031 50.004 0.037 ;
     RECT  50.022 0.031 50.076 0.037 ;
     RECT  50.094 0.031 50.148 0.037 ;
     RECT  50.166 0.031 50.22 0.037 ;
     RECT  50.238 0.031 50.292 0.037 ;
     RECT  50.31 0.031 50.364 0.037 ;
     RECT  50.382 0.031 50.436 0.037 ;
     RECT  50.454 0.031 50.508 0.037 ;
     RECT  50.526 0.031 50.58 0.037 ;
     RECT  50.598 0.031 50.652 0.037 ;
     RECT  50.67 0.031 50.724 0.037 ;
     RECT  50.742 0.031 50.796 0.037 ;
     RECT  50.814 0.031 50.868 0.037 ;
     RECT  50.886 0.031 50.94 0.037 ;
     RECT  50.958 0.031 51.012 0.037 ;
     RECT  51.03 0.031 51.084 0.037 ;
     RECT  51.102 0.031 51.156 0.037 ;
     RECT  51.174 0.031 51.228 0.037 ;
     RECT  51.246 0.031 51.3 0.037 ;
     RECT  51.318 0.031 51.372 0.037 ;
     RECT  51.39 0.031 51.444 0.037 ;
     RECT  51.462 0.031 51.516 0.037 ;
     RECT  51.534 0.031 51.588 0.037 ;
     RECT  51.606 0.031 51.66 0.037 ;
     RECT  51.678 0.031 51.732 0.037 ;
     RECT  51.75 0.031 51.804 0.037 ;
     RECT  51.822 0.031 51.876 0.037 ;
     RECT  51.894 0.031 51.948 0.037 ;
     RECT  51.966 0.031 52.02 0.037 ;
     RECT  52.038 0.031 52.092 0.037 ;
     RECT  52.11 0.031 52.164 0.037 ;
     RECT  52.182 0.031 52.236 0.037 ;
     RECT  52.254 0.031 52.308 0.037 ;
     RECT  52.326 0.031 52.38 0.037 ;
     RECT  52.398 0.031 52.452 0.037 ;
     RECT  52.47 0.031 52.524 0.037 ;
     RECT  52.542 0.031 52.596 0.037 ;
     RECT  52.614 0.031 52.668 0.037 ;
     RECT  52.686 0.031 52.74 0.037 ;
     RECT  52.758 0.031 52.812 0.037 ;
     RECT  52.83 0.031 52.884 0.037 ;
     RECT  52.902 0.031 52.956 0.037 ;
     RECT  52.974 0.031 53.028 0.037 ;
     RECT  53.046 0.031 53.1 0.037 ;
     RECT  53.118 0.031 53.172 0.037 ;
     RECT  53.19 0.031 53.244 0.037 ;
     RECT  53.262 0.031 53.316 0.037 ;
     RECT  53.334 0.031 53.388 0.037 ;
     RECT  53.406 0.031 53.46 0.037 ;
     RECT  53.478 0.031 53.532 0.037 ;
     RECT  53.55 0.031 53.604 0.037 ;
     RECT  53.622 0.031 53.676 0.037 ;
     RECT  53.694 0.031 53.748 0.037 ;
     RECT  53.766 0.031 53.82 0.037 ;
     RECT  53.838 0.031 53.892 0.037 ;
     RECT  53.91 0.031 53.964 0.037 ;
     RECT  53.982 0.031 54.036 0.037 ;
     RECT  54.054 0.031 54.108 0.037 ;
     RECT  54.126 0.031 54.18 0.037 ;
     RECT  54.198 0.031 54.252 0.037 ;
     RECT  54.27 0.031 54.324 0.037 ;
     RECT  54.342 0.031 54.396 0.037 ;
     RECT  54.414 0.031 54.468 0.037 ;
     RECT  54.486 0.031 54.54 0.037 ;
     RECT  54.558 0.031 54.612 0.037 ;
     RECT  54.63 0.031 54.684 0.037 ;
     RECT  54.702 0.031 54.756 0.037 ;
     RECT  54.774 0.031 54.828 0.037 ;
     RECT  54.846 0.031 54.9 0.037 ;
     RECT  54.918 0.031 54.972 0.037 ;
     RECT  54.99 0.031 55.044 0.037 ;
     RECT  55.062 0.031 55.116 0.037 ;
     RECT  55.134 0.031 55.188 0.037 ;
     RECT  55.206 0.031 55.26 0.037 ;
     RECT  55.278 0.031 55.332 0.037 ;
     RECT  55.35 0.031 55.404 0.037 ;
     RECT  55.422 0.031 55.476 0.037 ;
     RECT  55.494 0.031 55.548 0.037 ;
     RECT  55.566 0.031 55.62 0.037 ;
     RECT  55.638 0.031 55.692 0.037 ;
     RECT  55.71 0.031 55.764 0.037 ;
     RECT  55.782 0.031 55.836 0.037 ;
     RECT  55.854 0.031 55.908 0.037 ;
     RECT  55.926 0.031 55.98 0.037 ;
     RECT  55.998 0.031 56.052 0.037 ;
     RECT  56.07 0.031 56.124 0.037 ;
     RECT  56.142 0.031 56.196 0.037 ;
     RECT  56.214 0.031 56.268 0.037 ;
     RECT  56.286 0.031 56.34 0.037 ;
     RECT  56.358 0.031 56.412 0.037 ;
     RECT  56.43 0.031 56.484 0.037 ;
     RECT  56.502 0.031 56.556 0.037 ;
     RECT  56.574 0.031 56.628 0.037 ;
     RECT  56.646 0.031 56.7 0.037 ;
     RECT  56.718 0.031 56.772 0.037 ;
     RECT  56.79 0.031 56.844 0.037 ;
     RECT  56.862 0.031 56.916 0.037 ;
     RECT  56.934 0.031 56.988 0.037 ;
     RECT  57.006 0.031 57.06 0.037 ;
     RECT  57.078 0.031 57.132 0.037 ;
     RECT  57.15 0.031 57.204 0.037 ;
     RECT  57.222 0.031 57.276 0.037 ;
     RECT  57.294 0.031 57.348 0.037 ;
     RECT  57.366 0.031 57.42 0.037 ;
     RECT  57.438 0.031 57.492 0.037 ;
     RECT  57.51 0.031 58.14 0.037 ;
     RECT  58.158 0.031 58.212 0.037 ;
     RECT  58.23 0.031 58.284 0.037 ;
     RECT  58.302 0.031 58.356 0.037 ;
     RECT  58.374 0.031 58.428 0.037 ;
     RECT  58.446 0.031 58.5 0.037 ;
     RECT  58.518 0.031 58.572 0.037 ;
     RECT  58.59 0.031 58.644 0.037 ;
     RECT  58.662 0.031 58.716 0.037 ;
     RECT  58.734 0.031 58.788 0.037 ;
     RECT  58.806 0.031 58.86 0.037 ;
     RECT  58.878 0.031 58.932 0.037 ;
     RECT  58.95 0.031 59.004 0.037 ;
     RECT  59.022 0.031 59.076 0.037 ;
     RECT  59.094 0.031 59.148 0.037 ;
     RECT  59.166 0.031 59.22 0.037 ;
     RECT  59.238 0.031 59.292 0.037 ;
     RECT  59.31 0.031 59.364 0.037 ;
     RECT  59.382 0.031 59.436 0.037 ;
     RECT  59.454 0.031 59.508 0.037 ;
     RECT  59.526 0.031 59.58 0.037 ;
     RECT  59.598 0.031 59.652 0.037 ;
     RECT  59.67 0.031 59.724 0.037 ;
     RECT  59.742 0.031 59.796 0.037 ;
     RECT  59.814 0.031 59.868 0.037 ;
     RECT  59.886 0.031 59.94 0.037 ;
     RECT  59.958 0.031 60.012 0.037 ;
     RECT  60.03 0.031 60.084 0.037 ;
     RECT  60.102 0.031 60.156 0.037 ;
     RECT  60.174 0.031 60.228 0.037 ;
     RECT  60.246 0.031 60.3 0.037 ;
     RECT  60.318 0.031 60.372 0.037 ;
     RECT  60.39 0.031 60.444 0.037 ;
     RECT  60.462 0.031 60.516 0.037 ;
     RECT  60.534 0.031 60.588 0.037 ;
     RECT  60.606 0.031 60.66 0.037 ;
     RECT  60.678 0.031 60.732 0.037 ;
     RECT  60.75 0.031 60.804 0.037 ;
     RECT  60.822 0.031 60.876 0.037 ;
     RECT  60.894 0.031 60.948 0.037 ;
     RECT  60.966 0.031 61.02 0.037 ;
     RECT  61.038 0.031 61.092 0.037 ;
     RECT  61.11 0.031 61.164 0.037 ;
     RECT  61.182 0.031 61.236 0.037 ;
     RECT  61.254 0.031 61.308 0.037 ;
     RECT  61.326 0.031 61.38 0.037 ;
     RECT  61.398 0.031 61.452 0.037 ;
     RECT  61.47 0.031 61.524 0.037 ;
     RECT  61.542 0.031 61.596 0.037 ;
     RECT  61.614 0.031 61.668 0.037 ;
     RECT  61.686 0.031 61.74 0.037 ;
     RECT  61.758 0.031 61.812 0.037 ;
     RECT  61.83 0.031 61.884 0.037 ;
     RECT  61.902 0.031 61.956 0.037 ;
     RECT  61.974 0.031 62.028 0.037 ;
     RECT  62.046 0.031 62.1 0.037 ;
     RECT  62.118 0.031 62.172 0.037 ;
     RECT  62.19 0.031 62.244 0.037 ;
     RECT  62.262 0.031 62.316 0.037 ;
     RECT  62.334 0.031 62.388 0.037 ;
     RECT  62.406 0.031 62.46 0.037 ;
     RECT  62.478 0.031 62.532 0.037 ;
     RECT  62.55 0.031 62.604 0.037 ;
     RECT  62.622 0.031 62.676 0.037 ;
     RECT  62.694 0.031 62.748 0.037 ;
     RECT  62.766 0.031 62.82 0.037 ;
     RECT  62.838 0.031 62.892 0.037 ;
     RECT  62.91 0.031 62.964 0.037 ;
     RECT  62.982 0.031 63.036 0.037 ;
     RECT  63.054 0.031 63.108 0.037 ;
     RECT  63.126 0.031 63.18 0.037 ;
     RECT  63.198 0.031 63.252 0.037 ;
     RECT  63.27 0.031 63.324 0.037 ;
     RECT  63.342 0.031 63.396 0.037 ;
     RECT  63.414 0.031 63.468 0.037 ;
     RECT  63.486 0.031 63.54 0.037 ;
     RECT  63.558 0.031 63.612 0.037 ;
     RECT  63.63 0.031 63.684 0.037 ;
     RECT  63.702 0.031 63.756 0.037 ;
     RECT  63.774 0.031 63.828 0.037 ;
     RECT  63.846 0.031 63.9 0.037 ;
     RECT  63.918 0.031 63.972 0.037 ;
     RECT  63.99 0.031 64.044 0.037 ;
     RECT  64.062 0.031 64.116 0.037 ;
     RECT  64.134 0.031 64.188 0.037 ;
     RECT  64.206 0.031 64.26 0.037 ;
     RECT  64.278 0.031 64.332 0.037 ;
     RECT  64.35 0.031 64.404 0.037 ;
     RECT  64.422 0.031 64.476 0.037 ;
     RECT  64.494 0.031 64.548 0.037 ;
     RECT  64.566 0.031 64.62 0.037 ;
     RECT  64.638 0.031 64.692 0.037 ;
     RECT  64.71 0.031 64.764 0.037 ;
     RECT  64.782 0.031 64.836 0.037 ;
     RECT  64.854 0.031 64.908 0.037 ;
     RECT  64.926 0.031 64.98 0.037 ;
     RECT  64.998 0.031 65.052 0.037 ;
     RECT  65.07 0.031 65.124 0.037 ;
     RECT  65.142 0.031 65.196 0.037 ;
     RECT  65.214 0.031 65.268 0.037 ;
     RECT  65.286 0.031 65.34 0.037 ;
     RECT  65.358 0.031 65.412 0.037 ;
     RECT  65.43 0.031 65.484 0.037 ;
     RECT  65.502 0.031 65.556 0.037 ;
     RECT  65.574 0.031 65.628 0.037 ;
     RECT  65.646 0.031 65.7 0.037 ;
     RECT  65.718 0.031 65.772 0.037 ;
     RECT  65.79 0.031 65.844 0.037 ;
     RECT  65.862 0.031 65.916 0.037 ;
     RECT  65.934 0.031 65.988 0.037 ;
     RECT  66.006 0.031 66.06 0.037 ;
     RECT  66.078 0.031 66.132 0.037 ;
     RECT  66.15 0.031 66.204 0.037 ;
     RECT  66.222 0.031 66.276 0.037 ;
     RECT  66.294 0.031 66.348 0.037 ;
     RECT  66.366 0.031 66.42 0.037 ;
     RECT  66.438 0.031 66.492 0.037 ;
     RECT  66.51 0.031 66.564 0.037 ;
     RECT  66.582 0.031 66.636 0.037 ;
     RECT  66.654 0.031 66.708 0.037 ;
     RECT  66.726 0.031 66.78 0.037 ;
     RECT  66.798 0.031 66.852 0.037 ;
     RECT  66.87 0.031 66.924 0.037 ;
     RECT  66.942 0.031 66.996 0.037 ;
     RECT  67.014 0.031 67.068 0.037 ;
     RECT  67.086 0.031 67.14 0.037 ;
     RECT  67.158 0.031 67.212 0.037 ;
     RECT  67.23 0.031 67.284 0.037 ;
     RECT  67.302 0.031 67.356 0.037 ;
     RECT  67.374 0.031 67.428 0.037 ;
     RECT  67.446 0.031 67.5 0.037 ;
     RECT  67.518 0.031 67.572 0.037 ;
     RECT  67.59 0.031 67.644 0.037 ;
     RECT  67.662 0.031 67.716 0.037 ;
     RECT  67.734 0.031 67.788 0.037 ;
     RECT  67.806 0.031 67.86 0.037 ;
     RECT  67.878 0.031 67.932 0.037 ;
     RECT  67.95 0.031 68.004 0.037 ;
     RECT  68.022 0.031 68.076 0.037 ;
     RECT  68.094 0.031 68.148 0.037 ;
     RECT  68.166 0.031 68.22 0.037 ;
     RECT  68.238 0.031 68.292 0.037 ;
     RECT  68.31 0.031 68.364 0.037 ;
     RECT  68.382 0.031 68.436 0.037 ;
     RECT  68.454 0.031 68.508 0.037 ;
     RECT  68.526 0.031 68.58 0.037 ;
     RECT  68.598 0.031 68.652 0.037 ;
     RECT  68.67 0.031 68.724 0.037 ;
     RECT  68.742 0.031 68.796 0.037 ;
     RECT  68.814 0.031 68.868 0.037 ;
     RECT  68.886 0.031 68.94 0.037 ;
     RECT  68.958 0.031 69.012 0.037 ;
     RECT  69.03 0.031 69.084 0.037 ;
     RECT  69.102 0.031 69.156 0.037 ;
     RECT  69.174 0.031 69.228 0.037 ;
     RECT  69.246 0.031 69.3 0.037 ;
     RECT  69.318 0.031 69.372 0.037 ;
     RECT  69.39 0.031 69.444 0.037 ;
     RECT  69.462 0.031 69.516 0.037 ;
     RECT  69.534 0.031 69.588 0.037 ;
     RECT  69.606 0.031 69.66 0.037 ;
     RECT  69.678 0.031 69.732 0.037 ;
     RECT  69.75 0.031 69.804 0.037 ;
     RECT  69.822 0.031 69.876 0.037 ;
     RECT  69.894 0.031 69.948 0.037 ;
     RECT  69.966 0.031 70.02 0.037 ;
     RECT  70.038 0.031 70.092 0.037 ;
     RECT  70.11 0.031 70.164 0.037 ;
     RECT  70.182 0.031 70.236 0.037 ;
     RECT  70.254 0.031 70.308 0.037 ;
     RECT  70.326 0.031 70.38 0.037 ;
     RECT  70.398 0.031 70.452 0.037 ;
     RECT  70.47 0.031 70.524 0.037 ;
     RECT  70.542 0.031 70.596 0.037 ;
     RECT  70.614 0.031 70.668 0.037 ;
     RECT  70.686 0.031 70.74 0.037 ;
     RECT  70.758 0.031 70.812 0.037 ;
     RECT  70.83 0.031 70.884 0.037 ;
     RECT  70.902 0.031 70.956 0.037 ;
     RECT  70.974 0.031 71.028 0.037 ;
     RECT  71.046 0.031 71.1 0.037 ;
     RECT  71.118 0.031 71.172 0.037 ;
     RECT  71.19 0.031 71.244 0.037 ;
     RECT  71.262 0.031 71.316 0.037 ;
     RECT  71.334 0.031 71.388 0.037 ;
     RECT  40.356 0.037 71.406 0.187 ;
     RECT  38.484 0.187 71.406 0.317 ;
     RECT  37.044 0.139 37.674 0.811 ;
     RECT  36.324 0.811 37.674 0.907 ;
     RECT  34.704 0.859 34.722 1.003 ;
     RECT  35.676 0.907 37.674 1.003 ;
     RECT  34.704 1.003 37.674 1.387 ;
     RECT  40.428 0.317 71.406 1.723 ;
     RECT  40.428 1.723 71.514 2.143 ;
     RECT  38.484 0.317 39.33 2.191 ;
     RECT  40.215 2.143 71.514 2.191 ;
     RECT  34.416 1.387 37.674 2.219 ;
     RECT  38.484 2.191 71.514 2.219 ;
     RECT  2.415 2.143 2.505 2.413 ;
     RECT  5.115 2.143 5.205 2.413 ;
     RECT  7.815 2.143 7.905 2.413 ;
     RECT  10.515 2.143 10.605 2.413 ;
     RECT  13.215 2.143 13.305 2.413 ;
     RECT  15.915 2.143 16.005 2.413 ;
     RECT  18.615 2.143 18.705 2.413 ;
     RECT  21.315 2.143 21.405 2.413 ;
     RECT  24.015 2.143 24.105 2.413 ;
     RECT  26.715 2.143 26.805 2.413 ;
     RECT  29.415 2.143 29.505 2.413 ;
     RECT  32.115 2.143 32.205 2.413 ;
     RECT  37.44 2.219 37.674 2.413 ;
     RECT  38.484 2.219 71.37 2.413 ;
     RECT  72.615 2.143 72.705 2.413 ;
     RECT  75.315 2.143 75.405 2.413 ;
     RECT  78.015 2.143 78.105 2.413 ;
     RECT  80.715 2.143 80.805 2.413 ;
     RECT  83.415 2.143 83.505 2.413 ;
     RECT  86.115 2.143 86.205 2.413 ;
     RECT  88.815 2.143 88.905 2.413 ;
     RECT  91.515 2.143 91.605 2.413 ;
     RECT  94.215 2.143 94.305 2.413 ;
     RECT  96.915 2.143 97.005 2.413 ;
     RECT  99.615 2.143 99.705 2.413 ;
     RECT  72.615 2.413 72.897 3.379 ;
     RECT  37.44 2.413 71.37 3.451 ;
     RECT  72.324 3.379 72.897 3.451 ;
     RECT  37.44 3.451 72.897 3.569 ;
     RECT  72.324 3.569 72.897 3.605 ;
     RECT  37.44 3.569 71.478 3.725 ;
     RECT  86.115 2.413 86.397 16.771 ;
     RECT  78.015 2.413 78.297 16.891 ;
     RECT  86.115 16.771 86.706 16.891 ;
     RECT  80.715 2.413 80.997 16.939 ;
     RECT  82.656 16.843 82.674 16.973 ;
     RECT  80.715 16.939 81.09 16.979 ;
     RECT  78.015 16.891 78.678 17.069 ;
     RECT  86.076 16.891 86.706 17.069 ;
     RECT  86.115 17.069 86.706 17.117 ;
     RECT  72.36 3.605 72.897 24.359 ;
     RECT  34.416 2.219 36.558 29.065 ;
     RECT  101.232 29.731 101.43 29.789 ;
     RECT  101.412 29.789 101.43 29.831 ;
     RECT  37.44 3.725 71.334 29.839 ;
     RECT  101.736 29.899 101.754 29.939 ;
     RECT  99.615 2.413 99.897 29.995 ;
     RECT  99.615 29.995 99.99 30.125 ;
     RECT  34.416 29.065 36.63 30.451 ;
     RECT  37.368 29.839 71.334 30.451 ;
     RECT  33.588 30.451 33.606 30.811 ;
     RECT  32.115 2.413 32.397 30.991 ;
     RECT  33.408 30.811 33.606 30.991 ;
     RECT  32.115 30.991 33.606 31.261 ;
     RECT  32.076 31.261 33.606 31.891 ;
     RECT  34.416 30.451 71.334 31.891 ;
     RECT  32.076 31.891 71.334 43.979 ;
     RECT  32.076 43.979 68.31 45.571 ;
     RECT  69.264 43.979 71.334 45.571 ;
     RECT  32.076 45.571 71.334 50.279 ;
     RECT  32.076 50.279 71.118 50.549 ;
     RECT  32.076 50.549 70.83 51.125 ;
     RECT  69.624 51.125 70.83 51.359 ;
     RECT  69.915 51.359 70.83 51.539 ;
     RECT  32.076 51.125 68.67 51.737 ;
     RECT  32.076 51.737 68.31 51.943 ;
     RECT  69.915 51.539 70.197 53.563 ;
     RECT  31.572 51.943 68.31 53.635 ;
     RECT  72.615 24.359 72.897 53.659 ;
     RECT  69.915 53.563 70.29 53.693 ;
     RECT  31.572 53.635 68.814 53.803 ;
     RECT  69.915 53.693 70.197 53.803 ;
     RECT  72.396 53.659 72.897 53.837 ;
     RECT  31.572 53.803 70.197 54.571 ;
     RECT  31.5 54.571 70.197 54.841 ;
     RECT  29.415 2.413 29.697 54.907 ;
     RECT  29.124 54.907 29.697 54.913 ;
     RECT  29.088 54.913 29.697 55.147 ;
     RECT  30.78 54.841 70.197 55.243 ;
     RECT  30.78 55.243 70.254 55.435 ;
     RECT  30.78 55.435 70.398 55.525 ;
     RECT  28.512 55.147 29.697 55.561 ;
     RECT  30.78 55.525 70.686 55.561 ;
     RECT  30.78 55.561 71.118 55.751 ;
     RECT  30.78 55.751 70.686 55.759 ;
     RECT  28.512 55.561 29.826 55.795 ;
     RECT  30.636 55.759 70.686 55.795 ;
     RECT  28.512 55.795 70.686 55.805 ;
     RECT  28.512 55.805 70.578 56.057 ;
     RECT  28.512 56.057 70.398 56.101 ;
     RECT  71.82 56.539 71.838 56.587 ;
     RECT  72.615 53.837 72.897 56.587 ;
     RECT  28.152 56.101 70.398 56.839 ;
     RECT  27.936 56.839 70.398 56.875 ;
     RECT  71.82 56.587 72.897 57.029 ;
     RECT  27.936 56.875 70.722 57.109 ;
     RECT  26.715 2.413 26.997 57.415 ;
     RECT  27.936 57.109 70.758 57.415 ;
     RECT  71.892 57.029 72.897 57.415 ;
     RECT  71.892 57.415 72.954 57.721 ;
     RECT  74.016 57.649 74.034 57.721 ;
     RECT  2.415 2.413 2.697 57.797 ;
     RECT  5.115 2.413 5.397 57.797 ;
     RECT  7.815 2.413 8.097 57.797 ;
     RECT  10.515 2.413 10.797 57.797 ;
     RECT  13.215 2.413 13.497 57.797 ;
     RECT  15.915 2.413 16.197 57.797 ;
     RECT  18.615 2.413 18.897 57.797 ;
     RECT  21.315 2.413 21.597 57.797 ;
     RECT  24.015 2.413 24.297 57.797 ;
     RECT  26.715 57.415 70.974 57.797 ;
     RECT  75.315 2.413 75.597 57.797 ;
     RECT  78.015 17.069 78.297 57.797 ;
     RECT  80.715 16.979 80.997 57.797 ;
     RECT  83.415 2.413 83.697 57.797 ;
     RECT  86.115 17.117 86.397 57.797 ;
     RECT  88.815 2.413 89.097 57.797 ;
     RECT  91.515 2.413 91.797 57.797 ;
     RECT  94.215 2.413 94.497 57.797 ;
     RECT  96.915 2.413 97.197 57.797 ;
     RECT  99.615 30.125 99.897 57.797 ;
     RECT  71.892 57.721 74.034 57.839 ;
     RECT  26.784 57.797 70.974 58.019 ;
     RECT  2.607 57.797 2.697 58.067 ;
     RECT  5.307 57.797 5.397 58.067 ;
     RECT  8.007 57.797 8.097 58.067 ;
     RECT  10.707 57.797 10.797 58.067 ;
     RECT  13.407 57.797 13.497 58.067 ;
     RECT  16.107 57.797 16.197 58.067 ;
     RECT  18.807 57.797 18.897 58.067 ;
     RECT  21.507 57.797 21.597 58.067 ;
     RECT  24.207 57.797 24.297 58.067 ;
     RECT  71.892 57.839 73.53 58.067 ;
     RECT  75.507 57.797 75.597 58.067 ;
     RECT  78.207 57.797 78.297 58.067 ;
     RECT  80.907 57.797 80.997 58.067 ;
     RECT  83.607 57.797 83.697 58.067 ;
     RECT  86.307 57.797 86.397 58.067 ;
     RECT  89.007 57.797 89.097 58.067 ;
     RECT  91.707 57.797 91.797 58.067 ;
     RECT  94.407 57.797 94.497 58.067 ;
     RECT  97.107 57.797 97.197 58.067 ;
     RECT  99.807 57.797 99.897 58.067 ;
     RECT  71.892 58.067 72.09 58.081 ;
     RECT  26.784 58.019 61.074 58.145 ;
     RECT  26.856 58.145 61.074 58.181 ;
     RECT  61.848 58.019 70.974 58.253 ;
     RECT  61.848 58.253 61.866 58.289 ;
     RECT  72.936 58.067 73.53 58.397 ;
     RECT  72.936 58.397 72.99 58.445 ;
     RECT  27.36 58.181 61.074 58.451 ;
     RECT  71.784 58.081 72.09 58.493 ;
     RECT  72.936 58.445 72.954 58.541 ;
     RECT  27.756 58.451 61.074 58.721 ;
     RECT  62.82 58.253 70.974 58.721 ;
     RECT  62.856 58.721 70.974 58.733 ;
     RECT  27.756 58.721 61.002 58.973 ;
     RECT  27.936 58.973 61.002 59.021 ;
     RECT  62.856 58.733 62.874 59.503 ;
     RECT  63.756 58.733 70.974 59.503 ;
     RECT  62.856 59.503 70.974 59.567 ;
     RECT  28.152 59.021 61.002 59.603 ;
     RECT  28.44 59.603 61.002 59.684 ;
     RECT  28.584 59.684 61.002 59.837 ;
     RECT  62.856 59.567 70.002 59.954 ;
     RECT  62.856 59.954 66.186 59.981 ;
     RECT  66.924 59.954 70.002 59.981 ;
     RECT  66.996 59.981 70.002 59.999 ;
     RECT  63.252 59.981 66.186 60.029 ;
     RECT  63.252 60.029 65.646 60.077 ;
     RECT  66.996 59.999 68.274 60.173 ;
     RECT  28.584 59.837 60.426 60.179 ;
     RECT  31.536 60.179 60.426 60.221 ;
     RECT  63.252 60.077 64.89 60.221 ;
     RECT  67.356 60.173 68.274 60.221 ;
     RECT  28.584 60.179 30.582 60.224 ;
     RECT  65.628 60.077 65.646 60.224 ;
     RECT  28.584 60.224 30.006 60.269 ;
     RECT  67.356 60.221 68.238 60.269 ;
     RECT  28.584 60.269 29.142 60.305 ;
     RECT  67.356 60.269 67.374 60.305 ;
     RECT  32.004 60.221 60.426 60.317 ;
     RECT  64.548 60.221 64.89 60.341 ;
     RECT  29.988 60.269 30.006 60.365 ;
     RECT  63.252 60.221 63.378 60.365 ;
     RECT  69.3 59.999 70.002 60.365 ;
     RECT  69.984 60.365 70.002 60.377 ;
     RECT  28.692 60.305 29.106 60.413 ;
     RECT  32.004 60.317 60.318 60.413 ;
     RECT  61.56 59.926 61.578 60.413 ;
     RECT  64.548 60.341 64.566 60.413 ;
     RECT  68.22 60.269 68.238 60.413 ;
     RECT  72.072 58.493 72.09 60.413 ;
     RECT  32.148 60.413 60.318 60.419 ;
     RECT  32.166 60.419 32.22 60.444 ;
     RECT  32.238 60.419 32.292 60.444 ;
     RECT  32.31 60.419 32.364 60.444 ;
     RECT  32.382 60.419 32.436 60.444 ;
     RECT  32.454 60.419 32.508 60.444 ;
     RECT  32.526 60.419 32.58 60.444 ;
     RECT  32.598 60.419 32.652 60.444 ;
     RECT  32.67 60.419 32.724 60.444 ;
     RECT  32.742 60.419 32.796 60.444 ;
     RECT  32.814 60.419 32.868 60.444 ;
     RECT  32.886 60.419 32.94 60.444 ;
     RECT  32.958 60.419 33.012 60.444 ;
     RECT  33.03 60.419 33.084 60.444 ;
     RECT  33.102 60.419 33.156 60.444 ;
     RECT  33.174 60.419 33.228 60.444 ;
     RECT  33.246 60.419 33.3 60.444 ;
     RECT  33.318 60.419 33.372 60.444 ;
     RECT  33.39 60.419 33.444 60.444 ;
     RECT  33.462 60.419 33.516 60.444 ;
     RECT  33.534 60.419 33.588 60.444 ;
     RECT  33.606 60.419 33.66 60.444 ;
     RECT  33.678 60.419 33.732 60.444 ;
     RECT  33.75 60.419 33.804 60.444 ;
     RECT  33.822 60.419 33.876 60.444 ;
     RECT  33.894 60.419 33.948 60.444 ;
     RECT  33.966 60.419 34.02 60.444 ;
     RECT  34.038 60.419 34.092 60.444 ;
     RECT  34.11 60.419 34.164 60.444 ;
     RECT  34.182 60.419 34.236 60.444 ;
     RECT  34.254 60.419 34.308 60.444 ;
     RECT  34.326 60.419 34.38 60.444 ;
     RECT  34.398 60.419 34.452 60.444 ;
     RECT  34.47 60.419 34.524 60.444 ;
     RECT  34.542 60.419 34.596 60.444 ;
     RECT  34.614 60.419 34.668 60.444 ;
     RECT  34.686 60.419 34.74 60.444 ;
     RECT  34.758 60.419 34.812 60.444 ;
     RECT  34.83 60.419 34.884 60.444 ;
     RECT  34.902 60.419 34.956 60.444 ;
     RECT  34.974 60.419 35.028 60.444 ;
     RECT  35.046 60.419 35.1 60.444 ;
     RECT  35.118 60.419 35.172 60.444 ;
     RECT  35.19 60.419 35.244 60.444 ;
     RECT  35.262 60.419 35.316 60.444 ;
     RECT  35.334 60.419 35.388 60.444 ;
     RECT  35.406 60.419 35.46 60.444 ;
     RECT  35.478 60.419 35.532 60.444 ;
     RECT  35.55 60.419 35.604 60.444 ;
     RECT  35.622 60.419 35.676 60.444 ;
     RECT  35.694 60.419 35.748 60.444 ;
     RECT  35.766 60.419 35.82 60.444 ;
     RECT  35.838 60.419 35.892 60.444 ;
     RECT  35.91 60.419 35.964 60.444 ;
     RECT  35.982 60.419 36.036 60.444 ;
     RECT  36.054 60.419 36.108 60.444 ;
     RECT  36.126 60.419 36.18 60.444 ;
     RECT  36.198 60.419 36.252 60.444 ;
     RECT  36.27 60.419 36.324 60.444 ;
     RECT  36.342 60.419 36.396 60.444 ;
     RECT  36.414 60.419 36.468 60.444 ;
     RECT  36.486 60.419 36.54 60.444 ;
     RECT  36.558 60.419 36.612 60.444 ;
     RECT  36.63 60.419 36.684 60.444 ;
     RECT  36.702 60.419 36.756 60.444 ;
     RECT  36.774 60.419 36.828 60.444 ;
     RECT  36.846 60.419 36.9 60.444 ;
     RECT  36.918 60.419 36.972 60.444 ;
     RECT  36.99 60.419 37.044 60.444 ;
     RECT  37.062 60.419 37.116 60.444 ;
     RECT  37.134 60.419 37.188 60.444 ;
     RECT  37.206 60.419 37.26 60.444 ;
     RECT  37.278 60.419 37.332 60.444 ;
     RECT  37.35 60.419 37.404 60.444 ;
     RECT  37.422 60.419 37.476 60.444 ;
     RECT  37.494 60.419 37.548 60.444 ;
     RECT  37.566 60.419 37.62 60.444 ;
     RECT  37.638 60.419 37.692 60.444 ;
     RECT  37.71 60.419 37.764 60.444 ;
     RECT  37.782 60.419 37.836 60.444 ;
     RECT  37.854 60.419 37.908 60.444 ;
     RECT  37.926 60.419 37.98 60.444 ;
     RECT  37.998 60.419 38.052 60.444 ;
     RECT  38.07 60.419 38.124 60.444 ;
     RECT  38.142 60.419 38.196 60.444 ;
     RECT  38.214 60.419 38.268 60.444 ;
     RECT  38.286 60.419 38.34 60.444 ;
     RECT  38.358 60.419 38.412 60.444 ;
     RECT  38.43 60.419 38.484 60.444 ;
     RECT  38.502 60.419 38.556 60.444 ;
     RECT  38.574 60.419 38.628 60.444 ;
     RECT  38.646 60.419 38.7 60.444 ;
     RECT  38.718 60.419 38.772 60.444 ;
     RECT  38.79 60.419 38.844 60.444 ;
     RECT  38.862 60.419 38.916 60.444 ;
     RECT  38.934 60.419 38.988 60.444 ;
     RECT  39.006 60.419 39.06 60.444 ;
     RECT  39.078 60.419 39.132 60.444 ;
     RECT  39.15 60.419 39.204 60.444 ;
     RECT  39.222 60.419 39.276 60.444 ;
     RECT  39.294 60.419 39.348 60.444 ;
     RECT  39.366 60.419 39.42 60.444 ;
     RECT  39.438 60.419 39.492 60.444 ;
     RECT  39.51 60.419 39.564 60.444 ;
     RECT  39.582 60.419 39.636 60.444 ;
     RECT  39.654 60.419 39.708 60.444 ;
     RECT  39.726 60.419 39.78 60.444 ;
     RECT  39.798 60.419 39.852 60.444 ;
     RECT  39.87 60.419 39.924 60.444 ;
     RECT  39.942 60.419 39.996 60.444 ;
     RECT  40.014 60.419 40.068 60.444 ;
     RECT  40.086 60.419 40.14 60.444 ;
     RECT  40.158 60.419 40.212 60.444 ;
     RECT  40.23 60.419 40.284 60.444 ;
     RECT  40.302 60.419 40.356 60.444 ;
     RECT  40.374 60.419 40.428 60.444 ;
     RECT  40.446 60.419 40.5 60.444 ;
     RECT  40.518 60.419 40.572 60.444 ;
     RECT  40.59 60.419 40.644 60.444 ;
     RECT  40.662 60.419 40.716 60.444 ;
     RECT  40.734 60.419 40.788 60.444 ;
     RECT  40.806 60.419 40.86 60.444 ;
     RECT  40.878 60.419 40.932 60.444 ;
     RECT  40.95 60.419 41.004 60.444 ;
     RECT  41.022 60.419 41.076 60.444 ;
     RECT  41.094 60.419 41.148 60.444 ;
     RECT  41.166 60.419 41.22 60.444 ;
     RECT  41.238 60.419 41.292 60.444 ;
     RECT  41.31 60.419 41.364 60.444 ;
     RECT  41.382 60.419 41.436 60.444 ;
     RECT  41.454 60.419 41.508 60.444 ;
     RECT  41.526 60.419 41.58 60.444 ;
     RECT  41.598 60.419 41.652 60.444 ;
     RECT  41.67 60.419 41.724 60.444 ;
     RECT  41.742 60.419 41.796 60.444 ;
     RECT  41.814 60.419 41.868 60.444 ;
     RECT  41.886 60.419 41.94 60.444 ;
     RECT  41.958 60.419 42.012 60.444 ;
     RECT  42.03 60.419 42.084 60.444 ;
     RECT  42.102 60.419 42.156 60.444 ;
     RECT  42.174 60.419 42.228 60.444 ;
     RECT  42.246 60.419 42.3 60.444 ;
     RECT  42.318 60.419 42.372 60.444 ;
     RECT  42.39 60.419 42.444 60.444 ;
     RECT  42.462 60.419 42.516 60.444 ;
     RECT  42.534 60.419 42.588 60.444 ;
     RECT  42.606 60.419 42.66 60.444 ;
     RECT  42.678 60.419 42.732 60.444 ;
     RECT  42.75 60.419 42.804 60.444 ;
     RECT  42.822 60.419 42.876 60.444 ;
     RECT  42.894 60.419 42.948 60.444 ;
     RECT  42.966 60.419 43.02 60.444 ;
     RECT  43.038 60.419 43.092 60.444 ;
     RECT  43.11 60.419 43.164 60.444 ;
     RECT  43.182 60.419 43.236 60.444 ;
     RECT  43.254 60.419 43.308 60.444 ;
     RECT  43.326 60.419 43.38 60.444 ;
     RECT  43.398 60.419 43.452 60.444 ;
     RECT  43.47 60.419 43.524 60.444 ;
     RECT  43.542 60.419 43.596 60.444 ;
     RECT  43.614 60.419 43.668 60.444 ;
     RECT  43.686 60.419 43.74 60.444 ;
     RECT  43.758 60.419 43.812 60.444 ;
     RECT  43.83 60.419 43.884 60.444 ;
     RECT  43.902 60.419 43.956 60.444 ;
     RECT  43.974 60.419 44.028 60.444 ;
     RECT  44.046 60.419 44.1 60.444 ;
     RECT  44.118 60.419 44.172 60.444 ;
     RECT  44.19 60.419 44.244 60.444 ;
     RECT  44.262 60.419 44.316 60.444 ;
     RECT  44.334 60.419 44.388 60.444 ;
     RECT  44.406 60.419 44.46 60.444 ;
     RECT  44.478 60.419 44.532 60.444 ;
     RECT  44.55 60.419 44.604 60.444 ;
     RECT  44.622 60.419 44.676 60.444 ;
     RECT  44.694 60.419 44.748 60.444 ;
     RECT  44.766 60.419 44.82 60.444 ;
     RECT  44.838 60.419 44.892 60.444 ;
     RECT  44.91 60.419 44.964 60.444 ;
     RECT  44.982 60.419 45.036 60.444 ;
     RECT  45.054 60.419 45.108 60.444 ;
     RECT  45.126 60.419 45.18 60.444 ;
     RECT  45.198 60.419 45.252 60.444 ;
     RECT  45.27 60.419 45.324 60.444 ;
     RECT  45.342 60.419 45.396 60.444 ;
     RECT  45.414 60.419 45.468 60.444 ;
     RECT  45.486 60.419 45.54 60.444 ;
     RECT  45.558 60.419 45.612 60.444 ;
     RECT  45.63 60.419 45.684 60.444 ;
     RECT  45.702 60.419 45.756 60.444 ;
     RECT  45.774 60.419 45.828 60.444 ;
     RECT  45.846 60.419 45.9 60.444 ;
     RECT  45.918 60.419 46.548 60.444 ;
     RECT  46.566 60.419 46.62 60.444 ;
     RECT  46.638 60.419 46.692 60.444 ;
     RECT  46.71 60.419 46.764 60.444 ;
     RECT  46.782 60.419 46.836 60.444 ;
     RECT  46.854 60.419 46.908 60.444 ;
     RECT  46.926 60.419 46.98 60.444 ;
     RECT  46.998 60.419 47.052 60.444 ;
     RECT  47.07 60.419 47.124 60.444 ;
     RECT  47.142 60.419 47.196 60.444 ;
     RECT  47.214 60.419 47.268 60.444 ;
     RECT  47.286 60.419 47.34 60.444 ;
     RECT  47.358 60.419 47.412 60.444 ;
     RECT  47.43 60.419 47.484 60.444 ;
     RECT  47.502 60.419 47.556 60.444 ;
     RECT  47.574 60.419 47.628 60.444 ;
     RECT  47.646 60.419 47.7 60.444 ;
     RECT  47.718 60.419 47.772 60.444 ;
     RECT  47.79 60.419 47.844 60.444 ;
     RECT  47.862 60.419 47.916 60.444 ;
     RECT  47.934 60.419 47.988 60.444 ;
     RECT  48.006 60.419 48.06 60.444 ;
     RECT  48.078 60.419 48.132 60.444 ;
     RECT  48.15 60.419 48.204 60.444 ;
     RECT  48.222 60.419 48.276 60.444 ;
     RECT  48.294 60.419 48.348 60.444 ;
     RECT  48.366 60.419 48.42 60.444 ;
     RECT  48.438 60.419 48.492 60.444 ;
     RECT  48.51 60.419 48.564 60.444 ;
     RECT  48.582 60.419 48.636 60.444 ;
     RECT  48.654 60.419 48.708 60.444 ;
     RECT  48.726 60.419 48.78 60.444 ;
     RECT  48.798 60.419 48.852 60.444 ;
     RECT  48.87 60.419 48.924 60.444 ;
     RECT  48.942 60.419 48.996 60.444 ;
     RECT  49.014 60.419 49.068 60.444 ;
     RECT  49.086 60.419 49.14 60.444 ;
     RECT  49.158 60.419 49.212 60.444 ;
     RECT  49.23 60.419 49.284 60.444 ;
     RECT  49.302 60.419 49.356 60.444 ;
     RECT  49.374 60.419 49.428 60.444 ;
     RECT  49.446 60.419 49.5 60.444 ;
     RECT  49.518 60.419 49.572 60.444 ;
     RECT  49.59 60.419 49.644 60.444 ;
     RECT  49.662 60.419 49.716 60.444 ;
     RECT  49.734 60.419 49.788 60.444 ;
     RECT  49.806 60.419 49.86 60.444 ;
     RECT  49.878 60.419 49.932 60.444 ;
     RECT  49.95 60.419 50.004 60.444 ;
     RECT  50.022 60.419 50.076 60.444 ;
     RECT  50.094 60.419 50.148 60.444 ;
     RECT  50.166 60.419 50.22 60.444 ;
     RECT  50.238 60.419 50.292 60.444 ;
     RECT  50.31 60.419 50.364 60.444 ;
     RECT  50.382 60.419 50.436 60.444 ;
     RECT  50.454 60.419 50.508 60.444 ;
     RECT  50.526 60.419 50.58 60.444 ;
     RECT  50.598 60.419 50.652 60.444 ;
     RECT  50.67 60.419 50.724 60.444 ;
     RECT  50.742 60.419 50.796 60.444 ;
     RECT  50.814 60.419 50.868 60.444 ;
     RECT  50.886 60.419 50.94 60.444 ;
     RECT  50.958 60.419 51.012 60.444 ;
     RECT  51.03 60.419 51.084 60.444 ;
     RECT  51.102 60.419 51.156 60.444 ;
     RECT  51.174 60.419 51.228 60.444 ;
     RECT  51.246 60.419 51.3 60.444 ;
     RECT  51.318 60.419 51.372 60.444 ;
     RECT  51.39 60.419 51.444 60.444 ;
     RECT  51.462 60.419 51.516 60.444 ;
     RECT  51.534 60.419 51.588 60.444 ;
     RECT  51.606 60.419 51.66 60.444 ;
     RECT  51.678 60.419 51.732 60.444 ;
     RECT  51.75 60.419 51.804 60.444 ;
     RECT  51.822 60.419 51.876 60.444 ;
     RECT  51.894 60.419 51.948 60.444 ;
     RECT  51.966 60.419 52.02 60.444 ;
     RECT  52.038 60.419 52.092 60.444 ;
     RECT  52.11 60.419 52.164 60.444 ;
     RECT  52.182 60.419 52.236 60.444 ;
     RECT  52.254 60.419 52.308 60.444 ;
     RECT  52.326 60.419 52.38 60.444 ;
     RECT  52.398 60.419 52.452 60.444 ;
     RECT  52.47 60.419 52.524 60.444 ;
     RECT  52.542 60.419 52.596 60.444 ;
     RECT  52.614 60.419 52.668 60.444 ;
     RECT  52.686 60.419 52.74 60.444 ;
     RECT  52.758 60.419 52.812 60.444 ;
     RECT  52.83 60.419 52.884 60.444 ;
     RECT  52.902 60.419 52.956 60.444 ;
     RECT  52.974 60.419 53.028 60.444 ;
     RECT  53.046 60.419 53.1 60.444 ;
     RECT  53.118 60.419 53.172 60.444 ;
     RECT  53.19 60.419 53.244 60.444 ;
     RECT  53.262 60.419 53.316 60.444 ;
     RECT  53.334 60.419 53.388 60.444 ;
     RECT  53.406 60.419 53.46 60.444 ;
     RECT  53.478 60.419 53.532 60.444 ;
     RECT  53.55 60.419 53.604 60.444 ;
     RECT  53.622 60.419 53.676 60.444 ;
     RECT  53.694 60.419 53.748 60.444 ;
     RECT  53.766 60.419 53.82 60.444 ;
     RECT  53.838 60.419 53.892 60.444 ;
     RECT  53.91 60.419 53.964 60.444 ;
     RECT  53.982 60.419 54.036 60.444 ;
     RECT  54.054 60.419 54.108 60.444 ;
     RECT  54.126 60.419 54.18 60.444 ;
     RECT  54.198 60.419 54.252 60.444 ;
     RECT  54.27 60.419 54.324 60.444 ;
     RECT  54.342 60.419 54.396 60.444 ;
     RECT  54.414 60.419 54.468 60.444 ;
     RECT  54.486 60.419 54.54 60.444 ;
     RECT  54.558 60.419 54.612 60.444 ;
     RECT  54.63 60.419 54.684 60.444 ;
     RECT  54.702 60.419 54.756 60.444 ;
     RECT  54.774 60.419 54.828 60.444 ;
     RECT  54.846 60.419 54.9 60.444 ;
     RECT  54.918 60.419 54.972 60.444 ;
     RECT  54.99 60.419 55.044 60.444 ;
     RECT  55.062 60.419 55.116 60.444 ;
     RECT  55.134 60.419 55.188 60.444 ;
     RECT  55.206 60.419 55.26 60.444 ;
     RECT  55.278 60.419 55.332 60.444 ;
     RECT  55.35 60.419 55.404 60.444 ;
     RECT  55.422 60.419 55.476 60.444 ;
     RECT  55.494 60.419 55.548 60.444 ;
     RECT  55.566 60.419 55.62 60.444 ;
     RECT  55.638 60.419 55.692 60.444 ;
     RECT  55.71 60.419 55.764 60.444 ;
     RECT  55.782 60.419 55.836 60.444 ;
     RECT  55.854 60.419 55.908 60.444 ;
     RECT  55.926 60.419 55.98 60.444 ;
     RECT  55.998 60.419 56.052 60.444 ;
     RECT  56.07 60.419 56.124 60.444 ;
     RECT  56.142 60.419 56.196 60.444 ;
     RECT  56.214 60.419 56.268 60.444 ;
     RECT  56.286 60.419 56.34 60.444 ;
     RECT  56.358 60.419 56.412 60.444 ;
     RECT  56.43 60.419 56.484 60.444 ;
     RECT  56.502 60.419 56.556 60.444 ;
     RECT  56.574 60.419 56.628 60.444 ;
     RECT  56.646 60.419 56.7 60.444 ;
     RECT  56.718 60.419 56.772 60.444 ;
     RECT  56.79 60.419 56.844 60.444 ;
     RECT  56.862 60.419 56.916 60.444 ;
     RECT  56.934 60.419 56.988 60.444 ;
     RECT  57.006 60.419 57.06 60.444 ;
     RECT  57.078 60.419 57.132 60.444 ;
     RECT  57.15 60.419 57.204 60.444 ;
     RECT  57.222 60.419 57.276 60.444 ;
     RECT  57.294 60.419 57.348 60.444 ;
     RECT  57.366 60.419 57.42 60.444 ;
     RECT  57.438 60.419 57.492 60.444 ;
     RECT  57.51 60.419 57.564 60.444 ;
     RECT  57.582 60.419 57.636 60.444 ;
     RECT  57.654 60.419 57.708 60.444 ;
     RECT  57.726 60.419 57.78 60.444 ;
     RECT  57.798 60.419 57.852 60.444 ;
     RECT  57.87 60.419 57.924 60.444 ;
     RECT  57.942 60.419 57.996 60.444 ;
     RECT  58.014 60.419 58.068 60.444 ;
     RECT  58.086 60.419 58.14 60.444 ;
     RECT  58.158 60.419 58.212 60.444 ;
     RECT  58.23 60.419 58.284 60.444 ;
     RECT  58.302 60.419 58.356 60.444 ;
     RECT  58.374 60.419 58.428 60.444 ;
     RECT  58.446 60.419 58.5 60.444 ;
     RECT  58.518 60.419 58.572 60.444 ;
     RECT  58.59 60.419 58.644 60.444 ;
     RECT  58.662 60.419 58.716 60.444 ;
     RECT  58.734 60.419 58.788 60.444 ;
     RECT  58.806 60.419 58.86 60.444 ;
     RECT  58.878 60.419 58.932 60.444 ;
     RECT  58.95 60.419 59.004 60.444 ;
     RECT  59.022 60.419 59.076 60.444 ;
     RECT  59.094 60.419 59.148 60.444 ;
     RECT  59.166 60.419 59.22 60.444 ;
     RECT  59.238 60.419 59.292 60.444 ;
     RECT  59.31 60.419 59.364 60.444 ;
     RECT  59.382 60.419 59.436 60.444 ;
     RECT  59.454 60.419 59.508 60.444 ;
     RECT  59.526 60.419 59.58 60.444 ;
     RECT  59.598 60.419 59.652 60.444 ;
     RECT  59.67 60.419 59.724 60.444 ;
     RECT  59.742 60.419 59.796 60.444 ;
     RECT  59.814 60.419 59.868 60.444 ;
     RECT  59.886 60.419 59.94 60.444 ;
     RECT  59.958 60.419 60.012 60.444 ;
     RECT  60.03 60.419 60.084 60.444 ;
     RECT  60.102 60.419 60.156 60.444 ;
     RECT  60.174 60.419 60.228 60.444 ;
     RECT  60.246 60.419 60.3 60.444 ;
     RECT  33.48 60.444 33.498 60.449 ;
     RECT  39.96 60.444 39.978 60.449 ;
     RECT  59.4 60.444 59.418 60.449 ;
     RECT  70.956 59.567 70.974 60.449 ;
    LAYER M4 ;
     RECT  2.408 2.148 2.512 57.792 ;
     RECT  2.512 2.418 2.6 57.792 ;
     RECT  2.6 2.418 2.704 58.062 ;
     RECT  5.108 2.148 5.212 57.792 ;
     RECT  5.212 2.418 5.3 57.792 ;
     RECT  5.3 2.418 5.404 58.062 ;
     RECT  7.808 2.148 7.912 57.792 ;
     RECT  7.912 2.418 8 57.792 ;
     RECT  8 2.418 8.104 58.062 ;
     RECT  10.508 2.148 10.612 57.792 ;
     RECT  10.612 2.418 10.7 57.792 ;
     RECT  10.7 2.418 10.804 58.062 ;
     RECT  13.208 2.148 13.312 57.792 ;
     RECT  13.312 2.418 13.4 57.792 ;
     RECT  13.4 2.418 13.504 58.062 ;
     RECT  15.908 2.148 16.012 57.792 ;
     RECT  16.012 2.418 16.1 57.792 ;
     RECT  16.1 2.418 16.204 58.062 ;
     RECT  18.608 2.148 18.712 57.792 ;
     RECT  18.712 2.418 18.8 57.792 ;
     RECT  18.8 2.418 18.904 58.062 ;
     RECT  21.308 2.148 21.412 57.792 ;
     RECT  21.412 2.418 21.5 57.792 ;
     RECT  21.5 2.418 21.604 58.062 ;
     RECT  24.008 2.148 24.112 57.792 ;
     RECT  24.112 2.418 24.2 57.792 ;
     RECT  24.2 2.418 24.304 58.062 ;
     RECT  26.708 2.148 26.812 57.792 ;
     RECT  26.812 2.418 26.9 57.792 ;
     RECT  26.9 2.418 27.004 58.062 ;
     RECT  27.745 58.944 27.925 58.968 ;
     RECT  28.825 56.832 29.077 56.856 ;
     RECT  28.249 57.936 29.077 57.96 ;
     RECT  28.681 60.384 29.077 60.408 ;
     RECT  28.501 55.152 29.113 55.176 ;
     RECT  29.077 56.832 29.113 57.96 ;
     RECT  27.925 58.944 29.113 59.016 ;
     RECT  29.077 60.288 29.117 60.408 ;
     RECT  29.113 54.912 29.408 59.016 ;
     RECT  29.408 2.148 29.512 59.016 ;
     RECT  29.512 2.418 29.704 59.016 ;
     RECT  29.117 60.288 29.941 60.36 ;
     RECT  29.704 56.016 30.157 59.016 ;
     RECT  29.941 60.24 30.157 60.36 ;
     RECT  30.157 56.016 30.733 60.36 ;
     RECT  29.704 54.912 30.949 54.936 ;
     RECT  30.733 55.92 30.949 60.36 ;
     RECT  30.949 54.912 32.108 60.36 ;
     RECT  32.108 2.148 32.212 60.36 ;
     RECT  32.212 2.418 32.404 60.36 ;
     RECT  32.404 54.912 32.533 60.36 ;
     RECT  33.829 53.904 34.117 53.928 ;
     RECT  32.533 54.912 34.117 60.408 ;
     RECT  34.405 1.392 34.693 1.416 ;
     RECT  34.693 0.864 34.808 1.416 ;
     RECT  34.117 53.904 34.808 60.408 ;
     RECT  34.808 0.864 34.912 60.408 ;
     RECT  34.912 2.418 35.104 60.408 ;
     RECT  35.104 53.568 36.133 60.408 ;
     RECT  34.912 0.864 36.313 1.416 ;
     RECT  36.313 0.816 37.033 1.416 ;
     RECT  37.033 0.048 37.508 1.416 ;
     RECT  35.104 30.96 37.508 30.984 ;
     RECT  36.133 53.52 37.508 60.408 ;
     RECT  37.508 0.048 37.804 60.408 ;
     RECT  37.804 52.368 38.009 60.408 ;
     RECT  37.804 0.048 39.013 1.464 ;
     RECT  37.804 31.632 39.089 31.656 ;
     RECT  37.804 3.936 39.155 3.96 ;
     RECT  39.013 0.048 39.445 1.704 ;
     RECT  39.445 0.048 39.541 2.28 ;
     RECT  39.337 5.088 39.697 5.112 ;
     RECT  38.905 6.24 39.925 6.264 ;
     RECT  39.913 7.392 39.925 7.416 ;
     RECT  39.265 30.864 40.049 31.176 ;
     RECT  38.009 52.944 40.057 60.408 ;
     RECT  39.541 0.048 40.208 2.376 ;
     RECT  39.697 5.04 40.208 5.112 ;
     RECT  39.925 6.24 40.208 7.416 ;
     RECT  37.804 10.224 40.208 10.248 ;
     RECT  39.553 11.376 40.208 11.4 ;
     RECT  38.869 22.752 40.208 22.776 ;
     RECT  40.049 30.192 40.208 31.176 ;
     RECT  40.021 50.736 40.208 50.76 ;
     RECT  40.057 52.8 40.208 60.408 ;
     RECT  40.208 0.048 40.504 60.408 ;
     RECT  40.504 3.408 40.643 3.432 ;
     RECT  40.504 5.04 40.691 5.064 ;
     RECT  40.504 0.048 40.709 2.28 ;
     RECT  40.709 0.096 40.883 2.28 ;
     RECT  40.504 32.928 41.033 32.952 ;
     RECT  40.504 42.72 41.033 42.744 ;
     RECT  40.504 31.104 41.041 31.752 ;
     RECT  40.504 52.8 41.249 60.408 ;
     RECT  40.883 0.192 41.363 2.28 ;
     RECT  41.041 31.104 41.393 31.512 ;
     RECT  40.504 19.344 41.459 19.368 ;
     RECT  41.249 52.8 41.497 60.312 ;
     RECT  41.393 31.104 41.605 31.32 ;
     RECT  41.363 0.336 41.843 2.28 ;
     RECT  40.504 28.512 41.893 29.592 ;
     RECT  41.843 0.336 41.939 0.36 ;
     RECT  41.497 52.752 42.145 60.312 ;
     RECT  40.504 27.312 42.181 27.336 ;
     RECT  42.145 52.464 42.181 60.312 ;
     RECT  42.181 52.224 42.329 60.312 ;
     RECT  41.893 28.464 42.421 29.592 ;
     RECT  42.181 26.832 42.469 27.336 ;
     RECT  42.329 52.224 42.469 60.168 ;
     RECT  41.701 34.752 42.565 34.776 ;
     RECT  42.565 34.752 42.661 35.304 ;
     RECT  42.469 26.784 42.668 27.336 ;
     RECT  42.668 26.688 42.709 27.336 ;
     RECT  42.421 28.416 42.709 29.592 ;
     RECT  42.696 47.904 42.709 47.928 ;
     RECT  42.685 19.92 42.757 19.944 ;
     RECT  42.709 26.688 42.793 29.592 ;
     RECT  41.605 30.816 42.793 31.32 ;
     RECT  42.469 52.032 42.793 60.168 ;
     RECT  41.843 1.68 42.853 2.28 ;
     RECT  42.853 1.248 42.908 2.28 ;
     RECT  42.565 5.136 42.908 5.16 ;
     RECT  42.709 7.872 42.908 7.896 ;
     RECT  42.685 15.984 42.908 16.008 ;
     RECT  42.757 18.768 42.908 18.792 ;
     RECT  42.757 19.92 42.908 20.088 ;
     RECT  42.685 24 42.908 24.024 ;
     RECT  42.793 26.688 42.908 31.32 ;
     RECT  42.661 34.752 42.908 35.928 ;
     RECT  42.661 39.888 42.908 39.912 ;
     RECT  42.709 47.904 42.908 48.072 ;
     RECT  42.793 51.648 42.908 60.168 ;
     RECT  42.908 1.248 43.204 60.168 ;
     RECT  42.949 0.144 43.261 0.168 ;
     RECT  43.204 1.248 43.261 2.04 ;
     RECT  43.261 0.144 43.331 2.04 ;
     RECT  43.204 15.984 43.331 16.104 ;
     RECT  43.204 19.968 43.331 20.088 ;
     RECT  43.331 16.08 43.373 16.104 ;
     RECT  43.204 18.576 43.373 18.984 ;
     RECT  43.331 0.432 43.427 2.04 ;
     RECT  43.373 18.576 43.427 18.888 ;
     RECT  43.331 19.968 43.427 19.992 ;
     RECT  43.204 26.688 43.427 29.688 ;
     RECT  43.427 18.864 43.481 18.888 ;
     RECT  43.204 51.264 43.549 60.168 ;
     RECT  43.204 14.256 43.553 14.28 ;
     RECT  43.204 46.752 43.571 46.776 ;
     RECT  43.204 25.68 44.165 25.704 ;
     RECT  43.427 26.784 44.233 29.688 ;
     RECT  43.204 30.72 44.233 35.304 ;
     RECT  44.233 26.784 44.293 35.304 ;
     RECT  43.549 51.264 44.341 60.408 ;
     RECT  44.341 51.168 44.485 60.408 ;
     RECT  43.204 24.528 44.677 24.552 ;
     RECT  44.197 49.536 44.737 49.56 ;
     RECT  44.485 50.832 44.737 60.408 ;
     RECT  43.427 0.432 44.773 1.992 ;
     RECT  44.773 0.096 44.857 1.992 ;
     RECT  44.773 3.936 44.989 3.96 ;
     RECT  44.773 6.816 45.061 6.84 ;
     RECT  44.293 26.784 45.061 35.352 ;
     RECT  44.665 48.192 45.097 48.216 ;
     RECT  44.737 49.296 45.109 49.56 ;
     RECT  44.737 50.592 45.109 60.408 ;
     RECT  44.989 3.936 45.133 4.44 ;
     RECT  45.109 49.296 45.277 60.408 ;
     RECT  45.061 6.816 45.349 7.464 ;
     RECT  45.133 3.936 45.397 4.536 ;
     RECT  44.857 0.144 45.452 1.992 ;
     RECT  45.097 48.192 45.601 48.264 ;
     RECT  45.277 49.248 45.601 60.408 ;
     RECT  45.452 0.144 45.608 2.136 ;
     RECT  45.397 3.408 45.608 4.536 ;
     RECT  45.349 6.096 45.608 7.464 ;
     RECT  44.677 23.616 45.608 24.552 ;
     RECT  45.061 26.736 45.608 35.352 ;
     RECT  45.349 37.392 45.608 37.416 ;
     RECT  45.421 39.6 45.608 39.624 ;
     RECT  43.204 42.192 45.608 42.216 ;
     RECT  45.601 48.192 45.608 60.408 ;
     RECT  45.608 0.144 45.779 60.408 ;
     RECT  45.779 0.144 45.875 0.504 ;
     RECT  45.779 1.632 45.904 60.408 ;
     RECT  45.875 0.144 45.925 0.456 ;
     RECT  45.904 4.416 46.067 7.704 ;
     RECT  45.925 0.096 46.073 0.456 ;
     RECT  45.904 14.784 46.259 14.808 ;
     RECT  45.904 48.192 46.469 49.752 ;
     RECT  45.904 2.832 46.547 3.432 ;
     RECT  45.904 23.616 46.643 25.08 ;
     RECT  45.904 39.312 46.685 39.624 ;
     RECT  45.904 46.752 46.685 46.776 ;
     RECT  46.643 23.616 46.757 24.504 ;
     RECT  45.904 26.784 46.757 36.264 ;
     RECT  45.904 42.192 46.787 42.216 ;
     RECT  46.067 4.56 46.835 7.704 ;
     RECT  46.835 4.56 46.931 6.264 ;
     RECT  46.073 0.432 47.041 0.456 ;
     RECT  46.757 23.616 47.041 23.64 ;
     RECT  46.469 49.248 47.077 49.752 ;
     RECT  45.904 50.88 47.077 60.408 ;
     RECT  47.036 4.512 47.123 4.536 ;
     RECT  47.041 22.8 47.189 23.64 ;
     RECT  46.931 5.664 47.219 6.264 ;
     RECT  47.077 49.248 47.219 60.408 ;
     RECT  45.904 1.632 47.221 1.656 ;
     RECT  47.041 0.144 47.293 0.456 ;
     RECT  47.221 1.632 47.293 2.04 ;
     RECT  47.219 53.04 47.549 60.408 ;
     RECT  46.469 48.192 47.653 48.264 ;
     RECT  47.219 49.248 47.653 51.864 ;
     RECT  45.904 37.392 47.749 37.416 ;
     RECT  47.653 48.192 47.833 51.864 ;
     RECT  46.757 27.264 47.941 36.264 ;
     RECT  47.293 0.144 48.085 2.04 ;
     RECT  47.833 47.856 48.181 51.864 ;
     RECT  47.549 53.04 48.181 60.312 ;
     RECT  47.941 26.784 48.265 36.264 ;
     RECT  47.749 37.392 48.265 38.184 ;
     RECT  48.085 0.096 48.308 2.04 ;
     RECT  46.547 3.408 48.308 3.432 ;
     RECT  47.219 6.24 48.308 6.264 ;
     RECT  46.835 7.68 48.308 7.704 ;
     RECT  47.708 17.088 48.308 17.112 ;
     RECT  45.904 20.544 48.308 20.568 ;
     RECT  47.189 23.616 48.308 23.64 ;
     RECT  48.265 26.784 48.308 38.184 ;
     RECT  46.685 39.6 48.308 39.624 ;
     RECT  47.564 41.616 48.308 41.64 ;
     RECT  48.181 47.856 48.308 60.312 ;
     RECT  48.308 0.096 48.604 60.312 ;
     RECT  48.604 47.28 48.611 60.312 ;
     RECT  48.611 59.52 48.661 60.312 ;
     RECT  48.604 0.096 48.755 1.752 ;
     RECT  48.604 23.616 48.773 23.64 ;
     RECT  48.604 3.408 48.803 3.96 ;
     RECT  48.661 59.52 48.809 60.408 ;
     RECT  48.604 39.6 48.917 39.912 ;
     RECT  48.604 4.992 49.043 5.016 ;
     RECT  48.809 59.52 49.187 60.36 ;
     RECT  48.604 18.192 49.331 18.216 ;
     RECT  48.604 42.192 49.475 42.216 ;
     RECT  48.611 47.28 49.529 58.2 ;
     RECT  48.604 8.544 49.565 9.384 ;
     RECT  49.529 47.328 49.565 58.2 ;
     RECT  48.604 27.888 49.571 37.464 ;
     RECT  49.565 57.792 49.601 58.2 ;
     RECT  48.755 1.248 49.637 1.752 ;
     RECT  49.573 4.56 49.709 4.584 ;
     RECT  49.187 59.808 49.715 60.36 ;
     RECT  48.755 0.096 49.717 0.264 ;
     RECT  49.637 1.248 49.717 1.416 ;
     RECT  49.601 58.128 49.781 58.2 ;
     RECT  48.917 39.6 49.813 39.624 ;
     RECT  49.565 9.36 49.885 9.384 ;
     RECT  49.571 28.752 49.885 37.464 ;
     RECT  49.805 16.56 49.889 16.584 ;
     RECT  49.715 59.856 49.921 60.36 ;
     RECT  49.813 38.784 49.955 39.624 ;
     RECT  49.955 39.6 50.053 39.624 ;
     RECT  48.803 3.408 50.317 3.432 ;
     RECT  50.209 58.656 50.317 58.728 ;
     RECT  49.565 47.328 50.533 56.472 ;
     RECT  49.717 0.096 50.641 1.416 ;
     RECT  50.533 46.704 50.713 56.472 ;
     RECT  49.885 28.752 50.857 37.752 ;
     RECT  50.353 43.92 50.869 43.944 ;
     RECT  50.317 58.656 50.929 58.776 ;
     RECT  50.713 46.704 51.001 57 ;
     RECT  50.641 0.096 51.008 2.376 ;
     RECT  50.317 3.408 51.008 4.152 ;
     RECT  50.149 5.136 51.008 5.16 ;
     RECT  50.101 7.104 51.008 7.128 ;
     RECT  49.885 9.36 51.008 9.528 ;
     RECT  48.604 11.952 51.008 11.976 ;
     RECT  50.785 21.12 51.008 21.144 ;
     RECT  50.857 28.416 51.008 37.752 ;
     RECT  50.053 39.6 51.008 40.44 ;
     RECT  50.869 43.92 51.008 44.184 ;
     RECT  51.001 46.704 51.008 57.384 ;
     RECT  50.929 58.608 51.008 58.776 ;
     RECT  51.008 0.096 51.155 58.776 ;
     RECT  49.921 59.856 51.251 60.408 ;
     RECT  51.155 1.344 51.304 58.776 ;
     RECT  51.304 47.904 51.469 58.776 ;
     RECT  51.304 6.288 51.581 7.128 ;
     RECT  51.304 26.64 51.587 26.664 ;
     RECT  51.304 1.344 51.635 5.16 ;
     RECT  51.469 47.904 51.635 59.304 ;
     RECT  51.304 13.056 51.683 13.08 ;
     RECT  51.155 0.096 51.725 0.264 ;
     RECT  51.635 1.344 51.731 3.96 ;
     RECT  51.251 60.288 51.797 60.408 ;
     RECT  51.304 44.16 51.827 44.472 ;
     RECT  51.304 21.12 51.869 21.144 ;
     RECT  51.635 47.904 51.949 59.256 ;
     RECT  51.581 7.104 51.971 7.128 ;
     RECT  51.635 5.04 52.157 5.16 ;
     RECT  51.304 46.176 52.163 46.2 ;
     RECT  51.797 60.288 52.213 60.36 ;
     RECT  51.725 0.144 52.225 0.264 ;
     RECT  51.731 1.344 52.225 2.04 ;
     RECT  52.157 5.04 52.307 5.112 ;
     RECT  51.731 3.408 52.403 3.96 ;
     RECT  51.304 38.736 52.597 39.624 ;
     RECT  52.307 5.04 52.691 5.064 ;
     RECT  52.621 41.616 52.739 41.64 ;
     RECT  51.949 48.192 52.844 59.256 ;
     RECT  52.213 60.24 52.844 60.36 ;
     RECT  51.827 44.16 52.981 44.184 ;
     RECT  51.304 9.36 53.053 9.528 ;
     RECT  52.225 0.144 53.266 2.04 ;
     RECT  52.844 48.192 53.305 60.36 ;
     RECT  53.305 48.192 53.341 60.408 ;
     RECT  51.304 28.464 53.485 37.464 ;
     RECT  53.266 0.096 53.593 2.04 ;
     RECT  53.593 0.048 53.708 2.04 ;
     RECT  52.403 3.6 53.708 3.96 ;
     RECT  52.513 7.968 53.708 7.992 ;
     RECT  53.053 9.36 53.708 9.672 ;
     RECT  52.909 11.376 53.708 11.4 ;
     RECT  53.557 12.528 53.708 12.552 ;
     RECT  53.509 17.664 53.708 17.688 ;
     RECT  53.665 26.784 53.708 26.808 ;
     RECT  53.485 28.464 53.708 37.656 ;
     RECT  52.597 38.784 53.708 39.624 ;
     RECT  52.981 44.16 53.708 44.472 ;
     RECT  53.341 47.328 53.708 60.408 ;
     RECT  53.708 0.048 53.785 60.408 ;
     RECT  53.785 0.048 53.987 58.68 ;
     RECT  53.987 2.016 54.004 58.68 ;
     RECT  54.004 2.016 54.101 2.856 ;
     RECT  54.004 9.6 54.101 9.624 ;
     RECT  54.004 26.784 54.101 26.808 ;
     RECT  54.004 44.16 54.209 44.424 ;
     RECT  54.004 28.464 54.227 39.912 ;
     RECT  54.101 2.832 54.323 2.856 ;
     RECT  53.785 59.76 54.461 60.408 ;
     RECT  54.227 28.512 55.001 39.912 ;
     RECT  54.004 7.92 55.325 7.944 ;
     RECT  54.004 47.328 55.427 58.68 ;
     RECT  54.461 60.144 55.429 60.408 ;
     RECT  55.429 60.048 55.621 60.408 ;
     RECT  56.149 2.304 56.408 2.328 ;
     RECT  55.001 28.512 56.408 37.752 ;
     RECT  55.001 39.36 56.408 39.912 ;
     RECT  54.209 44.4 56.408 44.424 ;
     RECT  56.101 45.552 56.408 45.576 ;
     RECT  55.897 46.752 56.408 46.776 ;
     RECT  55.427 47.904 56.408 58.68 ;
     RECT  56.408 2.148 56.512 58.68 ;
     RECT  56.512 2.304 56.585 58.68 ;
     RECT  56.585 2.418 56.704 58.68 ;
     RECT  55.621 60 56.725 60.408 ;
     RECT  56.704 28.512 56.765 37.464 ;
     RECT  56.765 28.752 57.017 37.464 ;
     RECT  53.987 0.048 57.061 0.696 ;
     RECT  57.061 0.048 57.349 0.84 ;
     RECT  57.349 0.048 57.737 1.176 ;
     RECT  56.704 44.4 57.829 44.424 ;
     RECT  56.704 48.192 57.913 58.68 ;
     RECT  56.725 59.712 57.913 60.408 ;
     RECT  57.805 41.616 57.923 41.64 ;
     RECT  57.017 28.752 57.985 33.144 ;
     RECT  57.017 34.368 57.985 37.464 ;
     RECT  57.985 28.752 58.237 37.464 ;
     RECT  58.237 28.752 59.108 37.656 ;
     RECT  56.704 39.6 59.108 39.624 ;
     RECT  58.069 42.144 59.108 42.168 ;
     RECT  57.829 44.4 59.108 45.048 ;
     RECT  57.913 48.192 59.108 60.408 ;
     RECT  59.108 2.148 59.212 60.408 ;
     RECT  57.737 0.048 59.245 0.84 ;
     RECT  59.212 2.256 59.404 60.408 ;
     RECT  59.245 0.048 59.465 1.176 ;
     RECT  59.404 34.368 59.465 37.56 ;
     RECT  59.465 34.416 59.537 37.56 ;
     RECT  59.404 44.304 59.891 44.424 ;
     RECT  59.537 34.944 60.131 37.56 ;
     RECT  59.404 48.192 60.227 48.216 ;
     RECT  59.404 46.752 60.257 46.824 ;
     RECT  59.404 49.248 60.323 49.8 ;
     RECT  60.257 46.8 60.365 46.824 ;
     RECT  59.891 44.304 60.419 44.328 ;
     RECT  60.131 37.296 60.473 37.56 ;
     RECT  60.323 49.584 60.509 49.8 ;
     RECT  59.404 32.736 60.515 33.048 ;
     RECT  60.509 49.776 60.653 49.8 ;
     RECT  60.515 32.784 60.707 33.048 ;
     RECT  60.707 33.024 60.803 33.048 ;
     RECT  60.131 34.944 60.803 36.264 ;
     RECT  59.404 50.832 61.589 60.408 ;
     RECT  59.404 2.256 61.808 2.28 ;
     RECT  59.404 28.752 61.808 30.12 ;
     RECT  59.404 31.2 61.808 31.224 ;
     RECT  60.803 34.944 61.808 35.448 ;
     RECT  60.473 37.392 61.808 37.56 ;
     RECT  59.404 39.6 61.808 39.624 ;
     RECT  60.373 47.856 61.808 47.88 ;
     RECT  61.589 50.832 61.808 60.36 ;
     RECT  61.808 2.148 61.912 60.36 ;
     RECT  61.912 2.256 61.985 60.36 ;
     RECT  61.985 2.418 62.104 60.36 ;
     RECT  62.104 34.944 62.435 34.968 ;
     RECT  62.104 28.752 62.525 30.12 ;
     RECT  59.465 0.048 63.101 0.84 ;
     RECT  62.104 50.832 63.395 50.856 ;
     RECT  62.104 52.464 63.601 60.36 ;
     RECT  63.101 0.816 63.605 0.84 ;
     RECT  64.285 5.664 64.508 5.688 ;
     RECT  64.069 16.896 64.508 16.92 ;
     RECT  62.525 29.328 64.508 30.12 ;
     RECT  63.133 33.6 64.508 33.624 ;
     RECT  62.104 47.856 64.508 47.88 ;
     RECT  63.601 52.32 64.508 60.36 ;
     RECT  64.508 2.148 64.537 60.36 ;
     RECT  64.537 2.148 64.612 60.408 ;
     RECT  64.612 2.418 64.804 60.408 ;
     RECT  64.804 29.088 64.865 30.12 ;
     RECT  64.865 29.232 64.972 30.12 ;
     RECT  64.804 52.752 65.081 60.408 ;
     RECT  65.081 52.8 65.441 60.408 ;
     RECT  64.972 29.328 66.053 30.12 ;
     RECT  66.553 6.816 67.208 6.84 ;
     RECT  64.804 16.896 67.208 16.92 ;
     RECT  66.053 30.096 67.208 30.12 ;
     RECT  65.441 53.328 67.208 60.408 ;
     RECT  67.208 2.148 67.312 60.408 ;
     RECT  67.312 2.418 67.504 60.408 ;
     RECT  67.165 0.048 67.601 0.072 ;
     RECT  67.504 53.568 67.673 60.408 ;
     RECT  67.673 54.912 68.177 60.408 ;
     RECT  68.177 55.248 68.249 60.408 ;
     RECT  68.249 55.248 68.897 60.36 ;
     RECT  68.897 60.288 69.329 60.36 ;
     RECT  69.329 60.288 69.437 60.312 ;
     RECT  68.897 55.248 69.617 59.256 ;
     RECT  69.617 55.248 69.833 58.68 ;
     RECT  67.504 16.896 69.908 16.92 ;
     RECT  67.504 30.096 69.908 30.12 ;
     RECT  67.673 53.568 69.908 53.832 ;
     RECT  69.833 55.248 69.908 58.536 ;
     RECT  69.908 2.148 70.012 58.536 ;
     RECT  70.012 2.418 70.204 58.536 ;
     RECT  70.204 55.248 70.265 58.536 ;
     RECT  70.204 53.568 70.301 53.688 ;
     RECT  70.265 55.44 70.409 58.536 ;
     RECT  70.409 55.776 70.697 58.536 ;
     RECT  70.204 16.896 70.733 17.064 ;
     RECT  70.697 56.544 70.769 58.536 ;
     RECT  70.733 16.896 71.509 16.92 ;
     RECT  71.449 3.696 71.555 3.72 ;
     RECT  70.301 53.664 72.385 53.688 ;
     RECT  71.509 16.848 72.608 16.92 ;
     RECT  70.204 30.096 72.608 30.12 ;
     RECT  72.385 53.664 72.608 53.832 ;
     RECT  70.769 56.544 72.608 57.384 ;
     RECT  70.769 58.368 72.608 58.536 ;
     RECT  72.608 2.148 72.712 58.536 ;
     RECT  72.712 2.418 72.904 58.536 ;
     RECT  72.904 58.368 72.965 58.536 ;
     RECT  72.965 58.368 73.001 58.44 ;
     RECT  73.001 58.368 73.541 58.392 ;
     RECT  72.904 16.848 75.308 16.92 ;
     RECT  72.904 30.096 75.308 30.12 ;
     RECT  75.308 2.148 75.412 57.792 ;
     RECT  75.412 2.418 75.5 57.792 ;
     RECT  75.5 2.418 75.604 58.062 ;
     RECT  75.604 16.848 78.008 16.92 ;
     RECT  75.604 30.096 78.008 30.12 ;
     RECT  78.008 2.148 78.112 57.792 ;
     RECT  78.112 2.418 78.2 57.792 ;
     RECT  78.2 2.418 78.304 58.062 ;
     RECT  78.304 16.848 78.419 17.064 ;
     RECT  78.419 16.896 78.689 17.064 ;
     RECT  78.689 16.896 80.708 16.968 ;
     RECT  78.304 30.096 80.708 30.12 ;
     RECT  80.708 2.148 80.812 57.792 ;
     RECT  80.812 2.418 80.9 57.792 ;
     RECT  80.9 2.418 81.004 58.062 ;
     RECT  81.004 16.896 82.645 16.968 ;
     RECT  82.645 16.848 83.408 16.968 ;
     RECT  81.004 30.096 83.408 30.12 ;
     RECT  83.408 2.148 83.512 57.792 ;
     RECT  83.512 2.418 83.6 57.792 ;
     RECT  83.6 2.418 83.704 58.062 ;
     RECT  83.704 16.848 86.108 16.92 ;
     RECT  83.704 30.096 86.108 30.12 ;
     RECT  86.108 2.148 86.212 57.792 ;
     RECT  86.212 2.418 86.3 57.792 ;
     RECT  86.3 2.418 86.404 58.062 ;
     RECT  86.404 17.088 86.761 17.112 ;
     RECT  86.404 29.76 88.808 30.12 ;
     RECT  88.808 2.148 88.912 57.792 ;
     RECT  88.912 2.418 89 57.792 ;
     RECT  89 2.418 89.104 58.062 ;
     RECT  89.104 29.76 91.508 30.12 ;
     RECT  91.508 2.148 91.612 57.792 ;
     RECT  91.612 2.418 91.7 57.792 ;
     RECT  91.7 2.418 91.804 58.062 ;
     RECT  91.804 29.76 94.208 30.12 ;
     RECT  94.208 2.148 94.312 57.792 ;
     RECT  94.312 2.418 94.4 57.792 ;
     RECT  94.4 2.418 94.504 58.062 ;
     RECT  94.504 29.76 96.908 30.12 ;
     RECT  96.908 2.148 97.012 57.792 ;
     RECT  97.012 2.418 97.1 57.792 ;
     RECT  97.1 2.418 97.204 58.062 ;
     RECT  97.204 29.76 99.608 30.12 ;
     RECT  99.608 2.148 99.712 57.792 ;
     RECT  99.712 2.418 99.8 57.792 ;
     RECT  99.8 2.418 99.904 58.062 ;
     RECT  99.904 29.76 100.001 30.12 ;
     RECT  100.001 29.76 101.261 30.024 ;
     RECT  101.261 29.904 104.004 29.928 ;
     RECT  101.261 29.928 104.028 30 ;
     RECT  101.261 30 104.004 30.024 ;
    LAYER M5 ;
     RECT  39.144 0.016 39.216 0.037 ;
     RECT  39.24 0.016 39.312 0.037 ;
     RECT  39.336 0.016 39.408 0.037 ;
     RECT  39.432 0.016 39.504 0.037 ;
     RECT  39.528 0.016 39.6 0.037 ;
     RECT  39.624 0.016 39.696 0.037 ;
     RECT  39.72 0.016 39.792 0.037 ;
     RECT  39.816 0.016 39.888 0.037 ;
     RECT  39.912 0.016 39.984 0.037 ;
     RECT  40.008 0.016 40.08 0.037 ;
     RECT  40.104 0.016 40.176 0.037 ;
     RECT  40.2 0.016 40.272 0.037 ;
     RECT  40.296 0.016 40.368 0.037 ;
     RECT  40.392 0.016 40.464 0.037 ;
     RECT  40.488 0.016 40.56 0.037 ;
     RECT  40.584 0.016 40.656 0.037 ;
     RECT  40.68 0.016 40.752 0.037 ;
     RECT  40.776 0.016 40.848 0.037 ;
     RECT  40.872 0.016 40.944 0.037 ;
     RECT  40.968 0.016 41.04 0.037 ;
     RECT  41.064 0.016 41.136 0.037 ;
     RECT  41.16 0.016 41.232 0.037 ;
     RECT  41.256 0.016 41.328 0.037 ;
     RECT  41.352 0.016 41.424 0.037 ;
     RECT  41.448 0.016 41.52 0.037 ;
     RECT  41.544 0.016 41.616 0.037 ;
     RECT  41.64 0.016 41.712 0.037 ;
     RECT  41.736 0.016 41.808 0.037 ;
     RECT  41.832 0.016 41.904 0.037 ;
     RECT  41.928 0.016 42 0.037 ;
     RECT  42.024 0.016 42.096 0.037 ;
     RECT  42.12 0.016 42.192 0.037 ;
     RECT  42.216 0.016 42.288 0.037 ;
     RECT  42.312 0.016 42.384 0.037 ;
     RECT  42.408 0.016 42.48 0.037 ;
     RECT  42.504 0.016 42.576 0.037 ;
     RECT  42.6 0.016 42.672 0.037 ;
     RECT  42.696 0.016 42.768 0.037 ;
     RECT  42.792 0.016 42.864 0.037 ;
     RECT  42.888 0.016 42.96 0.037 ;
     RECT  42.984 0.016 43.056 0.037 ;
     RECT  43.08 0.016 43.152 0.037 ;
     RECT  43.176 0.016 43.248 0.037 ;
     RECT  43.272 0.016 43.344 0.037 ;
     RECT  43.368 0.016 43.44 0.037 ;
     RECT  43.464 0.016 43.536 0.037 ;
     RECT  43.56 0.016 43.632 0.037 ;
     RECT  43.656 0.016 43.728 0.037 ;
     RECT  43.752 0.016 43.824 0.037 ;
     RECT  43.848 0.016 43.92 0.037 ;
     RECT  43.944 0.016 44.016 0.037 ;
     RECT  44.04 0.016 44.112 0.037 ;
     RECT  44.136 0.016 44.208 0.037 ;
     RECT  44.232 0.016 44.304 0.037 ;
     RECT  44.328 0.016 44.4 0.037 ;
     RECT  44.424 0.016 44.496 0.037 ;
     RECT  44.52 0.016 44.592 0.037 ;
     RECT  44.616 0.016 44.688 0.037 ;
     RECT  44.712 0.016 44.784 0.037 ;
     RECT  44.808 0.016 44.88 0.037 ;
     RECT  44.904 0.016 44.976 0.037 ;
     RECT  45 0.016 45.072 0.037 ;
     RECT  45.096 0.016 45.168 0.037 ;
     RECT  45.192 0.016 45.264 0.037 ;
     RECT  45.288 0.016 45.36 0.037 ;
     RECT  45.384 0.016 45.456 0.037 ;
     RECT  45.48 0.016 45.552 0.037 ;
     RECT  45.576 0.016 45.648 0.037 ;
     RECT  45.672 0.016 45.744 0.037 ;
     RECT  45.768 0.016 45.84 0.037 ;
     RECT  45.864 0.016 45.936 0.037 ;
     RECT  45.96 0.016 46.032 0.037 ;
     RECT  46.056 0.016 46.128 0.037 ;
     RECT  46.152 0.016 46.224 0.037 ;
     RECT  46.248 0.016 46.32 0.037 ;
     RECT  46.344 0.016 46.416 0.037 ;
     RECT  46.44 0.016 46.512 0.037 ;
     RECT  46.536 0.016 46.608 0.037 ;
     RECT  46.632 0.016 46.704 0.037 ;
     RECT  46.728 0.016 46.8 0.037 ;
     RECT  46.824 0.016 46.896 0.037 ;
     RECT  46.92 0.016 46.992 0.037 ;
     RECT  47.016 0.016 47.088 0.037 ;
     RECT  47.112 0.016 47.184 0.037 ;
     RECT  47.208 0.016 47.28 0.037 ;
     RECT  47.304 0.016 47.376 0.037 ;
     RECT  47.4 0.016 47.472 0.037 ;
     RECT  47.496 0.016 47.568 0.037 ;
     RECT  47.592 0.016 47.664 0.037 ;
     RECT  47.688 0.016 47.76 0.037 ;
     RECT  47.784 0.016 47.856 0.037 ;
     RECT  47.88 0.016 47.952 0.037 ;
     RECT  47.976 0.016 48.048 0.037 ;
     RECT  48.072 0.016 48.144 0.037 ;
     RECT  48.168 0.016 48.24 0.037 ;
     RECT  48.264 0.016 48.336 0.037 ;
     RECT  48.36 0.016 48.432 0.037 ;
     RECT  48.456 0.016 48.528 0.037 ;
     RECT  48.552 0.016 48.624 0.037 ;
     RECT  48.648 0.016 48.72 0.037 ;
     RECT  48.744 0.016 48.816 0.037 ;
     RECT  48.84 0.016 48.912 0.037 ;
     RECT  48.936 0.016 49.008 0.037 ;
     RECT  49.032 0.016 49.104 0.037 ;
     RECT  49.128 0.016 49.2 0.037 ;
     RECT  49.224 0.016 49.296 0.037 ;
     RECT  49.32 0.016 49.392 0.037 ;
     RECT  49.416 0.016 49.488 0.037 ;
     RECT  49.512 0.016 49.584 0.037 ;
     RECT  49.608 0.016 49.68 0.037 ;
     RECT  49.704 0.016 49.776 0.037 ;
     RECT  49.8 0.016 49.872 0.037 ;
     RECT  49.896 0.016 49.968 0.037 ;
     RECT  49.992 0.016 50.064 0.037 ;
     RECT  50.088 0.016 50.16 0.037 ;
     RECT  50.184 0.016 50.256 0.037 ;
     RECT  50.28 0.016 50.352 0.037 ;
     RECT  50.376 0.016 50.448 0.037 ;
     RECT  50.472 0.016 50.544 0.037 ;
     RECT  50.568 0.016 50.64 0.037 ;
     RECT  50.664 0.016 50.736 0.037 ;
     RECT  50.76 0.016 50.832 0.037 ;
     RECT  50.856 0.016 50.928 0.037 ;
     RECT  50.952 0.016 51.024 0.037 ;
     RECT  51.048 0.016 51.12 0.037 ;
     RECT  51.144 0.016 51.216 0.037 ;
     RECT  51.24 0.016 51.312 0.037 ;
     RECT  51.336 0.016 51.408 0.037 ;
     RECT  51.432 0.016 51.504 0.037 ;
     RECT  51.528 0.016 51.6 0.037 ;
     RECT  51.624 0.016 51.696 0.037 ;
     RECT  51.72 0.016 51.792 0.037 ;
     RECT  51.816 0.016 51.888 0.037 ;
     RECT  51.912 0.016 51.984 0.037 ;
     RECT  52.008 0.016 52.08 0.037 ;
     RECT  52.104 0.016 52.176 0.037 ;
     RECT  52.2 0.016 52.272 0.037 ;
     RECT  52.296 0.016 52.368 0.037 ;
     RECT  52.392 0.016 52.464 0.037 ;
     RECT  52.488 0.016 52.56 0.037 ;
     RECT  52.584 0.016 52.656 0.037 ;
     RECT  52.68 0.016 52.752 0.037 ;
     RECT  52.776 0.016 52.848 0.037 ;
     RECT  52.872 0.016 52.944 0.037 ;
     RECT  52.968 0.016 53.04 0.037 ;
     RECT  53.064 0.016 53.136 0.037 ;
     RECT  53.16 0.016 53.232 0.037 ;
     RECT  53.256 0.016 53.328 0.037 ;
     RECT  53.352 0.016 53.424 0.037 ;
     RECT  53.448 0.016 53.52 0.037 ;
     RECT  53.544 0.016 53.616 0.037 ;
     RECT  53.64 0.016 53.712 0.037 ;
     RECT  53.736 0.016 53.808 0.037 ;
     RECT  53.832 0.016 53.904 0.037 ;
     RECT  53.928 0.016 54 0.037 ;
     RECT  54.024 0.016 54.096 0.037 ;
     RECT  54.12 0.016 54.192 0.037 ;
     RECT  54.216 0.016 54.288 0.037 ;
     RECT  54.312 0.016 54.384 0.037 ;
     RECT  54.408 0.016 54.48 0.037 ;
     RECT  54.504 0.016 54.576 0.037 ;
     RECT  54.6 0.016 54.672 0.037 ;
     RECT  54.696 0.016 54.768 0.037 ;
     RECT  54.792 0.016 54.864 0.037 ;
     RECT  54.888 0.016 54.96 0.037 ;
     RECT  54.984 0.016 55.056 0.037 ;
     RECT  55.08 0.016 55.152 0.037 ;
     RECT  55.176 0.016 55.248 0.037 ;
     RECT  55.272 0.016 55.344 0.037 ;
     RECT  55.368 0.016 55.44 0.037 ;
     RECT  55.464 0.016 55.536 0.037 ;
     RECT  55.56 0.016 55.632 0.037 ;
     RECT  55.656 0.016 55.728 0.037 ;
     RECT  55.752 0.016 55.824 0.037 ;
     RECT  55.848 0.016 55.92 0.037 ;
     RECT  55.944 0.016 56.016 0.037 ;
     RECT  56.04 0.016 56.112 0.037 ;
     RECT  56.136 0.016 56.208 0.037 ;
     RECT  56.232 0.016 56.304 0.037 ;
     RECT  56.328 0.016 56.4 0.037 ;
     RECT  56.424 0.016 56.496 0.037 ;
     RECT  56.52 0.016 56.592 0.037 ;
     RECT  56.616 0.016 56.688 0.037 ;
     RECT  56.712 0.016 56.784 0.037 ;
     RECT  56.808 0.016 56.88 0.037 ;
     RECT  56.904 0.016 56.976 0.037 ;
     RECT  57 0.016 57.072 0.037 ;
     RECT  57.096 0.016 57.168 0.037 ;
     RECT  57.192 0.016 57.264 0.037 ;
     RECT  57.288 0.016 57.36 0.037 ;
     RECT  57.384 0.016 57.456 0.037 ;
     RECT  60.768 0.133 60.792 0.517 ;
     RECT  39.144 0.037 39.216 0.084 ;
     RECT  39.24 0.037 39.312 0.084 ;
     RECT  39.336 0.037 39.408 0.084 ;
     RECT  39.432 0.037 39.504 0.084 ;
     RECT  39.528 0.037 39.6 0.084 ;
     RECT  39.624 0.037 39.696 0.084 ;
     RECT  39.72 0.037 39.792 0.084 ;
     RECT  39.816 0.037 39.888 0.084 ;
     RECT  39.912 0.037 39.984 0.084 ;
     RECT  40.008 0.037 40.08 0.084 ;
     RECT  40.104 0.037 40.176 0.084 ;
     RECT  40.2 0.037 40.272 0.084 ;
     RECT  40.296 0.037 40.368 0.084 ;
     RECT  40.392 0.037 40.464 0.084 ;
     RECT  40.488 0.037 40.56 0.084 ;
     RECT  40.584 0.037 40.656 0.084 ;
     RECT  40.68 0.037 40.752 0.084 ;
     RECT  40.776 0.037 40.848 0.084 ;
     RECT  40.872 0.037 40.944 0.084 ;
     RECT  40.968 0.037 41.04 0.084 ;
     RECT  41.064 0.037 41.136 0.084 ;
     RECT  41.16 0.037 41.232 0.084 ;
     RECT  41.256 0.037 41.328 0.084 ;
     RECT  41.352 0.037 41.424 0.084 ;
     RECT  41.448 0.037 41.52 0.084 ;
     RECT  41.544 0.037 41.616 0.084 ;
     RECT  41.64 0.037 41.712 0.084 ;
     RECT  41.736 0.037 41.808 0.084 ;
     RECT  41.832 0.037 41.904 0.084 ;
     RECT  41.928 0.037 42 0.084 ;
     RECT  42.024 0.037 42.096 0.084 ;
     RECT  42.12 0.037 42.192 0.084 ;
     RECT  42.216 0.037 42.288 0.084 ;
     RECT  42.312 0.037 42.384 0.084 ;
     RECT  42.408 0.037 42.48 0.084 ;
     RECT  42.504 0.037 42.576 0.084 ;
     RECT  42.6 0.037 42.672 0.084 ;
     RECT  42.696 0.037 42.768 0.084 ;
     RECT  42.792 0.037 42.864 0.084 ;
     RECT  42.888 0.037 42.96 0.084 ;
     RECT  42.984 0.037 43.056 0.084 ;
     RECT  43.08 0.037 43.152 0.084 ;
     RECT  43.176 0.037 43.248 0.084 ;
     RECT  43.272 0.037 43.344 0.084 ;
     RECT  43.368 0.037 43.44 0.084 ;
     RECT  43.464 0.037 43.536 0.084 ;
     RECT  43.56 0.037 43.632 0.084 ;
     RECT  43.656 0.037 43.728 0.084 ;
     RECT  43.752 0.037 43.824 0.084 ;
     RECT  43.848 0.037 43.92 0.084 ;
     RECT  43.944 0.037 44.016 0.084 ;
     RECT  44.04 0.037 44.112 0.084 ;
     RECT  44.136 0.037 44.208 0.084 ;
     RECT  44.232 0.037 44.304 0.084 ;
     RECT  44.328 0.037 44.4 0.084 ;
     RECT  44.424 0.037 44.496 0.084 ;
     RECT  44.52 0.037 44.592 0.084 ;
     RECT  44.616 0.037 44.688 0.084 ;
     RECT  44.712 0.037 44.784 0.084 ;
     RECT  44.808 0.037 44.88 0.084 ;
     RECT  44.904 0.037 44.976 0.084 ;
     RECT  45 0.037 45.072 0.084 ;
     RECT  45.096 0.037 45.168 0.084 ;
     RECT  45.192 0.037 45.264 0.084 ;
     RECT  45.288 0.037 45.36 0.084 ;
     RECT  45.384 0.037 45.456 0.084 ;
     RECT  45.48 0.037 45.552 0.084 ;
     RECT  45.576 0.037 45.648 0.084 ;
     RECT  45.672 0.037 45.744 0.084 ;
     RECT  45.768 0.037 45.84 0.084 ;
     RECT  45.864 0.037 45.936 0.084 ;
     RECT  45.96 0.037 46.032 0.084 ;
     RECT  46.056 0.037 46.128 0.084 ;
     RECT  46.152 0.037 46.224 0.084 ;
     RECT  46.248 0.037 46.32 0.084 ;
     RECT  46.344 0.037 46.416 0.084 ;
     RECT  46.44 0.037 46.512 0.084 ;
     RECT  46.536 0.037 46.608 0.084 ;
     RECT  46.632 0.037 46.704 0.084 ;
     RECT  46.728 0.037 46.8 0.084 ;
     RECT  46.824 0.037 46.896 0.084 ;
     RECT  46.92 0.037 46.992 0.084 ;
     RECT  47.016 0.037 47.088 0.084 ;
     RECT  47.112 0.037 47.184 0.084 ;
     RECT  47.208 0.037 47.28 0.084 ;
     RECT  47.304 0.037 47.376 0.084 ;
     RECT  47.4 0.037 47.472 0.084 ;
     RECT  47.496 0.037 47.568 0.084 ;
     RECT  47.592 0.037 47.664 0.084 ;
     RECT  47.688 0.037 47.76 0.084 ;
     RECT  47.784 0.037 47.856 0.084 ;
     RECT  47.88 0.037 47.952 0.084 ;
     RECT  47.976 0.037 48.048 0.084 ;
     RECT  48.072 0.037 48.144 0.084 ;
     RECT  48.168 0.037 48.24 0.084 ;
     RECT  48.264 0.037 48.336 0.084 ;
     RECT  48.36 0.037 48.432 0.084 ;
     RECT  48.456 0.037 48.528 0.084 ;
     RECT  48.552 0.037 48.624 0.084 ;
     RECT  48.648 0.037 48.72 0.084 ;
     RECT  48.744 0.037 48.816 0.084 ;
     RECT  48.84 0.037 48.912 0.084 ;
     RECT  48.936 0.037 49.008 0.084 ;
     RECT  49.032 0.037 49.104 0.084 ;
     RECT  49.128 0.037 49.2 0.084 ;
     RECT  49.224 0.037 49.296 0.084 ;
     RECT  49.32 0.037 49.392 0.084 ;
     RECT  49.416 0.037 49.488 0.084 ;
     RECT  49.512 0.037 49.584 0.084 ;
     RECT  49.608 0.037 49.68 0.084 ;
     RECT  49.704 0.037 49.776 0.084 ;
     RECT  49.8 0.037 49.872 0.084 ;
     RECT  49.896 0.037 49.968 0.084 ;
     RECT  49.992 0.037 50.064 0.084 ;
     RECT  50.088 0.037 50.16 0.084 ;
     RECT  50.184 0.037 50.256 0.084 ;
     RECT  50.28 0.037 50.352 0.084 ;
     RECT  50.376 0.037 50.448 0.084 ;
     RECT  50.472 0.037 50.544 0.084 ;
     RECT  50.568 0.037 50.64 0.084 ;
     RECT  50.664 0.037 50.736 0.084 ;
     RECT  50.76 0.037 50.832 0.084 ;
     RECT  50.856 0.037 50.928 0.084 ;
     RECT  50.952 0.037 51.024 0.084 ;
     RECT  51.048 0.037 51.12 0.084 ;
     RECT  51.144 0.037 51.216 0.084 ;
     RECT  51.24 0.037 51.312 0.084 ;
     RECT  51.336 0.037 51.408 0.084 ;
     RECT  51.432 0.037 51.504 0.084 ;
     RECT  51.528 0.037 51.6 0.084 ;
     RECT  51.624 0.037 51.696 0.084 ;
     RECT  51.72 0.037 51.792 0.084 ;
     RECT  51.816 0.037 51.888 0.084 ;
     RECT  51.912 0.037 51.984 0.084 ;
     RECT  52.008 0.037 52.08 0.084 ;
     RECT  52.104 0.037 52.176 0.084 ;
     RECT  52.2 0.037 52.272 0.084 ;
     RECT  52.296 0.037 52.368 0.084 ;
     RECT  52.392 0.037 52.464 0.084 ;
     RECT  52.488 0.037 52.56 0.084 ;
     RECT  52.584 0.037 52.656 0.084 ;
     RECT  52.68 0.037 52.752 0.084 ;
     RECT  52.776 0.037 52.848 0.084 ;
     RECT  52.872 0.037 52.944 0.084 ;
     RECT  52.968 0.037 53.04 0.084 ;
     RECT  53.064 0.037 53.136 0.084 ;
     RECT  53.16 0.037 53.232 0.084 ;
     RECT  53.256 0.037 53.328 0.084 ;
     RECT  53.352 0.037 53.424 0.084 ;
     RECT  53.448 0.037 53.52 0.084 ;
     RECT  53.544 0.037 53.616 0.084 ;
     RECT  53.64 0.037 53.712 0.084 ;
     RECT  53.736 0.037 53.808 0.084 ;
     RECT  53.832 0.037 53.904 0.084 ;
     RECT  53.928 0.037 54 0.084 ;
     RECT  54.024 0.037 54.096 0.084 ;
     RECT  54.12 0.037 54.192 0.084 ;
     RECT  54.216 0.037 54.288 0.084 ;
     RECT  54.312 0.037 54.384 0.084 ;
     RECT  54.408 0.037 54.48 0.084 ;
     RECT  54.504 0.037 54.576 0.084 ;
     RECT  54.6 0.037 54.672 0.084 ;
     RECT  54.696 0.037 54.768 0.084 ;
     RECT  54.792 0.037 54.864 0.084 ;
     RECT  54.888 0.037 54.96 0.084 ;
     RECT  54.984 0.037 55.056 0.084 ;
     RECT  55.08 0.037 55.152 0.084 ;
     RECT  55.176 0.037 55.248 0.084 ;
     RECT  55.272 0.037 55.344 0.084 ;
     RECT  55.368 0.037 55.44 0.084 ;
     RECT  55.464 0.037 55.536 0.084 ;
     RECT  55.56 0.037 55.632 0.084 ;
     RECT  55.656 0.037 55.728 0.084 ;
     RECT  55.752 0.037 55.824 0.084 ;
     RECT  55.848 0.037 55.92 0.084 ;
     RECT  55.944 0.037 56.016 0.084 ;
     RECT  56.04 0.037 56.112 0.084 ;
     RECT  56.136 0.037 56.208 0.084 ;
     RECT  56.232 0.037 56.304 0.084 ;
     RECT  56.328 0.037 56.4 0.084 ;
     RECT  56.424 0.037 56.496 0.084 ;
     RECT  56.52 0.037 56.592 0.084 ;
     RECT  56.616 0.037 56.688 0.084 ;
     RECT  56.712 0.037 56.784 0.084 ;
     RECT  56.808 0.037 56.88 0.084 ;
     RECT  56.904 0.037 56.976 0.084 ;
     RECT  57 0.037 57.072 0.084 ;
     RECT  57.096 0.037 57.168 0.084 ;
     RECT  57.192 0.037 57.264 0.084 ;
     RECT  57.288 0.037 57.36 0.084 ;
     RECT  57.384 0.037 57.456 0.084 ;
     RECT  57.48 0.037 57.576 0.084 ;
     RECT  39.12 0.084 57.576 0.709 ;
     RECT  2.4 2.137 2.52 2.151 ;
     RECT  5.1 2.137 5.22 2.151 ;
     RECT  7.8 2.137 7.92 2.151 ;
     RECT  10.5 2.137 10.62 2.151 ;
     RECT  13.2 2.137 13.32 2.151 ;
     RECT  15.9 2.137 16.02 2.151 ;
     RECT  18.6 2.137 18.72 2.151 ;
     RECT  21.3 2.137 21.42 2.151 ;
     RECT  24 2.137 24.12 2.151 ;
     RECT  26.7 2.137 26.82 2.151 ;
     RECT  29.4 2.137 29.52 2.151 ;
     RECT  32.1 2.137 32.22 2.151 ;
     RECT  34.8 2.137 34.92 2.151 ;
     RECT  37.5 2.137 37.62 2.151 ;
     RECT  59.1 2.137 59.22 2.151 ;
     RECT  61.8 2.137 61.92 2.151 ;
     RECT  64.5 2.137 64.62 2.151 ;
     RECT  67.2 2.137 67.32 2.151 ;
     RECT  69.9 2.137 70.02 2.151 ;
     RECT  72.6 2.137 72.72 2.151 ;
     RECT  75.3 2.137 75.42 2.151 ;
     RECT  78 2.137 78.12 2.151 ;
     RECT  80.7 2.137 80.82 2.151 ;
     RECT  83.4 2.137 83.52 2.151 ;
     RECT  86.1 2.137 86.22 2.151 ;
     RECT  88.8 2.137 88.92 2.151 ;
     RECT  91.5 2.137 91.62 2.151 ;
     RECT  94.2 2.137 94.32 2.151 ;
     RECT  96.9 2.137 97.02 2.151 ;
     RECT  99.6 2.137 99.72 2.151 ;
     RECT  59.1 2.151 59.412 2.245 ;
     RECT  60.672 0.517 60.792 2.245 ;
     RECT  39.12 0.709 57.912 3.971 ;
     RECT  64.5 2.151 64.812 5.653 ;
     RECT  78 2.151 78.312 16.837 ;
     RECT  71.52 3.685 71.544 16.883 ;
     RECT  64.32 5.653 64.812 16.885 ;
     RECT  78 16.837 78.408 16.979 ;
     RECT  86.1 2.151 86.412 17.077 ;
     RECT  39.552 3.971 57.912 19.379 ;
     RECT  39.552 19.379 40.512 22.741 ;
     RECT  42.192 19.379 57.912 26.867 ;
     RECT  38.88 22.741 40.512 27.301 ;
     RECT  38.88 27.301 41.304 28.453 ;
     RECT  42.288 26.867 57.912 28.453 ;
     RECT  64.08 16.885 64.812 29.221 ;
     RECT  64.08 29.221 64.92 29.651 ;
     RECT  86.1 17.077 86.712 29.795 ;
     RECT  59.1 2.245 60.792 31.189 ;
     RECT  61.8 2.151 62.112 31.189 ;
     RECT  38.88 28.453 57.912 31.861 ;
     RECT  59.1 31.189 62.112 31.861 ;
     RECT  38.88 31.861 62.112 34.933 ;
     RECT  38.88 34.933 62.424 44.435 ;
     RECT  60.384 44.435 62.424 47.845 ;
     RECT  64.08 29.651 64.812 47.845 ;
     RECT  60.384 47.845 64.812 47.891 ;
     RECT  38.88 44.435 59.412 48.181 ;
     RECT  60.384 47.891 63.384 48.181 ;
     RECT  37.5 2.151 37.812 52.357 ;
     RECT  38.88 48.181 63.384 52.357 ;
     RECT  37.5 52.357 63.384 52.501 ;
     RECT  37.5 52.501 63.432 52.645 ;
     RECT  64.5 47.891 64.812 52.645 ;
     RECT  34.8 2.151 35.112 53.557 ;
     RECT  37.5 52.645 64.812 54.085 ;
     RECT  37.5 54.085 65.4 54.517 ;
     RECT  67.2 2.151 67.512 54.517 ;
     RECT  37.5 54.517 67.512 54.755 ;
     RECT  66.816 54.755 67.512 54.995 ;
     RECT  32.1 2.151 32.412 55.141 ;
     RECT  37.5 54.755 65.4 55.427 ;
     RECT  32.1 55.141 33.144 55.813 ;
     RECT  32.1 55.813 33.336 55.861 ;
     RECT  34.8 53.557 35.496 55.861 ;
     RECT  40.2 55.427 65.4 55.909 ;
     RECT  32.1 55.861 35.496 55.957 ;
     RECT  67.2 54.995 67.512 56.053 ;
     RECT  32.1 55.957 35.928 56.149 ;
     RECT  32.1 56.149 36.312 56.197 ;
     RECT  40.2 55.909 65.736 56.293 ;
     RECT  37.5 55.427 38.904 56.437 ;
     RECT  40.2 56.293 66.072 56.483 ;
     RECT  42.432 56.483 66.072 56.485 ;
     RECT  67.2 56.053 67.848 56.485 ;
     RECT  37.5 56.437 39.048 56.533 ;
     RECT  37.392 56.533 39.048 56.579 ;
     RECT  39.024 56.579 39.048 56.675 ;
     RECT  31.92 56.197 36.312 56.677 ;
     RECT  37.392 56.579 37.992 56.677 ;
     RECT  31.92 56.677 37.992 56.723 ;
     RECT  31.92 56.723 36.456 56.867 ;
     RECT  42.432 56.485 67.848 57.013 ;
     RECT  31.92 56.867 36.312 57.059 ;
     RECT  42.432 57.013 68.376 57.059 ;
     RECT  42.48 57.059 68.376 57.107 ;
     RECT  31.92 57.059 36.216 57.109 ;
     RECT  31.44 57.109 36.216 57.203 ;
     RECT  37.5 56.723 37.992 57.251 ;
     RECT  31.44 57.203 35.592 57.539 ;
     RECT  66.72 57.107 68.376 57.589 ;
     RECT  42.48 57.107 65.688 57.635 ;
     RECT  29.4 2.151 29.712 57.637 ;
     RECT  66.72 57.589 68.904 57.683 ;
     RECT  67.2 57.683 68.904 57.827 ;
     RECT  34.56 57.539 35.112 57.875 ;
     RECT  29.088 57.637 29.712 57.971 ;
     RECT  2.4 2.151 2.712 58.059 ;
     RECT  5.1 2.151 5.412 58.059 ;
     RECT  7.8 2.151 8.112 58.059 ;
     RECT  10.5 2.151 10.812 58.059 ;
     RECT  13.2 2.151 13.512 58.059 ;
     RECT  15.9 2.151 16.212 58.059 ;
     RECT  18.6 2.151 18.912 58.059 ;
     RECT  21.3 2.151 21.612 58.059 ;
     RECT  24 2.151 24.312 58.059 ;
     RECT  26.7 2.151 27.012 58.059 ;
     RECT  29.4 57.971 29.712 58.059 ;
     RECT  34.8 57.875 35.112 58.059 ;
     RECT  37.5 57.251 37.812 58.059 ;
     RECT  40.2 56.483 40.512 58.059 ;
     RECT  42.9 57.635 65.688 58.059 ;
     RECT  67.2 57.827 68.808 58.059 ;
     RECT  69.9 2.151 70.212 58.059 ;
     RECT  72.6 2.151 72.912 58.059 ;
     RECT  75.3 2.151 75.612 58.059 ;
     RECT  78 16.979 78.312 58.059 ;
     RECT  80.7 2.151 81.012 58.059 ;
     RECT  83.4 2.151 83.712 58.059 ;
     RECT  86.1 29.795 86.412 58.059 ;
     RECT  88.8 2.151 89.112 58.059 ;
     RECT  91.5 2.151 91.812 58.059 ;
     RECT  94.2 2.151 94.512 58.059 ;
     RECT  96.9 2.151 97.212 58.059 ;
     RECT  99.6 2.151 99.912 58.059 ;
     RECT  2.592 58.059 2.712 58.073 ;
     RECT  5.292 58.059 5.412 58.073 ;
     RECT  7.992 58.059 8.112 58.073 ;
     RECT  10.692 58.059 10.812 58.073 ;
     RECT  13.392 58.059 13.512 58.073 ;
     RECT  16.092 58.059 16.212 58.073 ;
     RECT  18.792 58.059 18.912 58.073 ;
     RECT  21.492 58.059 21.612 58.073 ;
     RECT  24.192 58.059 24.312 58.073 ;
     RECT  26.892 58.059 27.012 58.073 ;
     RECT  29.592 58.059 29.712 58.073 ;
     RECT  31.44 57.539 33.336 58.073 ;
     RECT  34.992 58.059 35.112 58.073 ;
     RECT  37.692 58.059 37.812 58.073 ;
     RECT  40.392 58.059 40.512 58.073 ;
     RECT  43.092 58.059 65.688 58.073 ;
     RECT  67.392 58.059 68.808 58.073 ;
     RECT  70.092 58.059 70.212 58.073 ;
     RECT  72.792 58.059 72.912 58.073 ;
     RECT  75.492 58.059 75.612 58.073 ;
     RECT  78.192 58.059 78.312 58.073 ;
     RECT  80.892 58.059 81.012 58.073 ;
     RECT  83.592 58.059 83.712 58.073 ;
     RECT  86.292 58.059 86.412 58.073 ;
     RECT  88.992 58.059 89.112 58.073 ;
     RECT  91.692 58.059 91.812 58.073 ;
     RECT  94.392 58.059 94.512 58.073 ;
     RECT  97.092 58.059 97.212 58.073 ;
     RECT  99.792 58.059 99.912 58.073 ;
     RECT  33.12 58.073 33.336 58.115 ;
     RECT  38.784 57.973 38.808 58.163 ;
     RECT  67.584 58.073 68.808 58.163 ;
     RECT  43.44 58.073 65.688 58.211 ;
     RECT  67.584 58.163 67.896 58.211 ;
     RECT  67.632 58.211 67.896 58.259 ;
     RECT  67.632 58.259 67.752 58.739 ;
     RECT  67.632 58.739 67.656 58.787 ;
     RECT  33.12 58.115 33.144 58.835 ;
     RECT  31.44 58.073 31.992 59.123 ;
     RECT  31.968 59.123 31.992 59.603 ;
     RECT  33.408 59.461 33.432 59.747 ;
     RECT  43.44 58.211 64.968 60.372 ;
     RECT  43.464 60.372 43.536 60.432 ;
     RECT  43.56 60.372 43.632 60.432 ;
     RECT  43.656 60.372 43.728 60.432 ;
     RECT  43.752 60.372 43.824 60.432 ;
     RECT  43.848 60.372 43.92 60.432 ;
     RECT  43.944 60.372 44.016 60.432 ;
     RECT  44.04 60.372 44.112 60.432 ;
     RECT  44.136 60.372 44.208 60.432 ;
     RECT  44.232 60.372 44.304 60.432 ;
     RECT  44.328 60.372 44.4 60.432 ;
     RECT  44.424 60.372 44.496 60.432 ;
     RECT  44.52 60.372 44.592 60.432 ;
     RECT  44.616 60.372 44.688 60.432 ;
     RECT  44.712 60.372 44.784 60.432 ;
     RECT  44.808 60.372 44.88 60.432 ;
     RECT  44.904 60.372 44.976 60.432 ;
     RECT  45 60.372 45.072 60.432 ;
     RECT  45.096 60.372 45.168 60.432 ;
     RECT  45.192 60.372 45.264 60.432 ;
     RECT  45.288 60.372 45.36 60.432 ;
     RECT  45.384 60.372 45.456 60.432 ;
     RECT  45.48 60.372 45.552 60.432 ;
     RECT  45.576 60.372 45.648 60.432 ;
     RECT  45.672 60.372 45.744 60.432 ;
     RECT  45.768 60.372 46.608 60.432 ;
     RECT  46.632 60.372 46.704 60.432 ;
     RECT  46.728 60.372 46.8 60.432 ;
     RECT  46.824 60.372 46.896 60.432 ;
     RECT  46.92 60.372 46.992 60.432 ;
     RECT  47.016 60.372 47.088 60.432 ;
     RECT  47.112 60.372 47.184 60.432 ;
     RECT  47.208 60.372 47.28 60.432 ;
     RECT  47.304 60.372 47.376 60.432 ;
     RECT  47.4 60.372 47.472 60.432 ;
     RECT  47.496 60.372 47.568 60.432 ;
     RECT  47.592 60.372 47.664 60.432 ;
     RECT  47.688 60.372 47.76 60.432 ;
     RECT  47.784 60.372 47.856 60.432 ;
     RECT  47.88 60.372 47.952 60.432 ;
     RECT  47.976 60.372 48.048 60.432 ;
     RECT  48.072 60.372 48.144 60.432 ;
     RECT  48.168 60.372 48.24 60.432 ;
     RECT  48.264 60.372 48.336 60.432 ;
     RECT  48.36 60.372 48.432 60.432 ;
     RECT  48.456 60.372 48.528 60.432 ;
     RECT  48.552 60.372 48.624 60.432 ;
     RECT  48.648 60.372 48.72 60.432 ;
     RECT  48.744 60.372 48.816 60.432 ;
     RECT  48.84 60.372 48.912 60.432 ;
     RECT  48.936 60.372 49.008 60.432 ;
     RECT  49.032 60.372 49.104 60.432 ;
     RECT  49.128 60.372 49.2 60.432 ;
     RECT  49.224 60.372 49.296 60.432 ;
     RECT  49.32 60.372 49.392 60.432 ;
     RECT  49.416 60.372 49.488 60.432 ;
     RECT  49.512 60.372 49.584 60.432 ;
     RECT  49.608 60.372 49.68 60.432 ;
     RECT  49.704 60.372 49.776 60.432 ;
     RECT  49.8 60.372 49.872 60.432 ;
     RECT  49.896 60.372 49.968 60.432 ;
     RECT  49.992 60.372 50.064 60.432 ;
     RECT  50.088 60.372 50.16 60.432 ;
     RECT  50.184 60.372 50.256 60.432 ;
     RECT  50.28 60.372 50.352 60.432 ;
     RECT  50.376 60.372 50.448 60.432 ;
     RECT  50.472 60.372 50.544 60.432 ;
     RECT  50.568 60.372 50.64 60.432 ;
     RECT  50.664 60.372 50.736 60.432 ;
     RECT  50.76 60.372 50.832 60.432 ;
     RECT  50.856 60.372 50.928 60.432 ;
     RECT  50.952 60.372 51.024 60.432 ;
     RECT  51.048 60.372 51.12 60.432 ;
     RECT  51.144 60.372 51.216 60.432 ;
     RECT  51.24 60.372 51.312 60.432 ;
     RECT  51.336 60.372 51.408 60.432 ;
     RECT  51.432 60.372 51.504 60.432 ;
     RECT  51.528 60.372 51.6 60.432 ;
     RECT  51.624 60.372 51.696 60.432 ;
     RECT  51.72 60.372 51.792 60.432 ;
     RECT  51.816 60.372 51.888 60.432 ;
     RECT  51.912 60.372 51.984 60.432 ;
     RECT  52.008 60.372 52.08 60.432 ;
     RECT  52.104 60.372 52.176 60.432 ;
     RECT  52.2 60.372 52.272 60.432 ;
     RECT  52.296 60.372 52.368 60.432 ;
     RECT  52.392 60.372 52.464 60.432 ;
     RECT  52.488 60.372 52.56 60.432 ;
     RECT  52.584 60.372 52.656 60.432 ;
     RECT  52.68 60.372 52.752 60.432 ;
     RECT  52.776 60.372 52.848 60.432 ;
     RECT  52.872 60.372 52.944 60.432 ;
     RECT  52.968 60.372 53.04 60.432 ;
     RECT  53.064 60.372 53.136 60.432 ;
     RECT  53.16 60.372 53.232 60.432 ;
     RECT  53.256 60.372 53.328 60.432 ;
     RECT  53.352 60.372 53.424 60.432 ;
     RECT  53.448 60.372 53.52 60.432 ;
     RECT  53.544 60.372 53.616 60.432 ;
     RECT  53.64 60.372 53.712 60.432 ;
     RECT  53.736 60.372 53.808 60.432 ;
     RECT  53.832 60.372 53.904 60.432 ;
     RECT  53.928 60.372 54 60.432 ;
     RECT  54.024 60.372 54.096 60.432 ;
     RECT  54.12 60.372 54.192 60.432 ;
     RECT  54.216 60.372 54.288 60.432 ;
     RECT  54.312 60.372 54.384 60.432 ;
     RECT  54.408 60.372 54.48 60.432 ;
     RECT  54.504 60.372 54.576 60.432 ;
     RECT  54.6 60.372 54.672 60.432 ;
     RECT  54.696 60.372 54.768 60.432 ;
     RECT  54.792 60.372 54.864 60.432 ;
     RECT  54.888 60.372 54.96 60.432 ;
     RECT  54.984 60.372 55.056 60.432 ;
     RECT  55.08 60.372 55.152 60.432 ;
     RECT  55.176 60.372 55.248 60.432 ;
     RECT  55.272 60.372 55.344 60.432 ;
     RECT  55.368 60.372 55.44 60.432 ;
     RECT  55.464 60.372 55.536 60.432 ;
     RECT  55.56 60.372 55.632 60.432 ;
     RECT  55.656 60.372 55.728 60.432 ;
     RECT  55.752 60.372 55.824 60.432 ;
     RECT  55.848 60.372 55.92 60.432 ;
     RECT  55.944 60.372 56.016 60.432 ;
     RECT  56.04 60.372 56.112 60.432 ;
     RECT  56.136 60.372 56.208 60.432 ;
     RECT  56.232 60.372 56.304 60.432 ;
     RECT  56.328 60.372 56.4 60.432 ;
     RECT  56.424 60.372 56.496 60.432 ;
     RECT  56.52 60.372 56.592 60.432 ;
     RECT  56.616 60.372 56.688 60.432 ;
     RECT  56.712 60.372 56.784 60.432 ;
     RECT  56.808 60.372 56.88 60.432 ;
     RECT  56.904 60.372 56.976 60.432 ;
     RECT  57 60.372 57.072 60.432 ;
     RECT  57.096 60.372 57.168 60.432 ;
     RECT  57.192 60.372 57.264 60.432 ;
     RECT  57.288 60.372 57.36 60.432 ;
     RECT  57.384 60.372 57.456 60.432 ;
     RECT  57.48 60.372 57.552 60.432 ;
     RECT  57.576 60.372 57.648 60.432 ;
     RECT  57.672 60.372 57.744 60.432 ;
     RECT  57.768 60.372 57.84 60.432 ;
     RECT  57.864 60.372 57.936 60.432 ;
     RECT  57.96 60.372 58.032 60.432 ;
     RECT  58.056 60.372 58.128 60.432 ;
     RECT  58.152 60.372 58.224 60.432 ;
     RECT  58.248 60.372 58.32 60.432 ;
     RECT  58.344 60.372 58.416 60.432 ;
     RECT  58.44 60.372 58.512 60.432 ;
     RECT  58.536 60.372 58.608 60.432 ;
     RECT  58.632 60.372 58.704 60.432 ;
     RECT  58.728 60.372 58.8 60.432 ;
     RECT  58.824 60.372 58.896 60.432 ;
     RECT  58.92 60.372 58.992 60.432 ;
     RECT  59.016 60.372 59.088 60.432 ;
     RECT  59.112 60.372 59.184 60.432 ;
     RECT  59.208 60.372 59.28 60.432 ;
     RECT  59.304 60.372 59.376 60.432 ;
     RECT  59.4 60.372 59.472 60.432 ;
     RECT  59.496 60.372 59.568 60.432 ;
     RECT  59.592 60.372 59.664 60.432 ;
     RECT  59.688 60.372 59.76 60.432 ;
     RECT  59.784 60.372 59.856 60.432 ;
     RECT  59.88 60.372 59.952 60.432 ;
     RECT  59.976 60.372 60.048 60.432 ;
     RECT  60.072 60.372 60.144 60.432 ;
     RECT  60.168 60.372 60.24 60.432 ;
     RECT  60.264 60.372 60.336 60.432 ;
     RECT  60.36 60.372 60.432 60.432 ;
     RECT  60.456 60.372 60.528 60.432 ;
     RECT  60.552 60.372 60.624 60.432 ;
     RECT  60.648 60.372 60.72 60.432 ;
     RECT  60.744 60.372 60.816 60.432 ;
     RECT  60.84 60.372 60.912 60.432 ;
     RECT  60.936 60.372 61.008 60.432 ;
     RECT  61.032 60.372 61.104 60.432 ;
     RECT  61.128 60.372 61.2 60.432 ;
     RECT  61.224 60.372 61.296 60.432 ;
     RECT  61.32 60.372 61.392 60.432 ;
     RECT  61.416 60.372 61.488 60.432 ;
     RECT  61.512 60.372 61.584 60.432 ;
     RECT  61.608 60.372 61.68 60.432 ;
     RECT  61.704 60.372 61.776 60.432 ;
     RECT  61.8 60.372 61.872 60.432 ;
     RECT  61.896 60.372 61.968 60.432 ;
     RECT  61.992 60.372 62.064 60.432 ;
     RECT  62.088 60.372 62.16 60.432 ;
     RECT  62.184 60.372 62.256 60.432 ;
     RECT  62.28 60.372 62.352 60.432 ;
     RECT  62.376 60.372 62.448 60.432 ;
     RECT  62.472 60.372 62.544 60.432 ;
     RECT  62.568 60.372 62.64 60.432 ;
     RECT  62.664 60.372 62.736 60.432 ;
     RECT  62.76 60.372 62.832 60.432 ;
     RECT  62.856 60.372 62.928 60.432 ;
     RECT  62.952 60.372 63.024 60.432 ;
     RECT  63.048 60.372 63.12 60.432 ;
     RECT  63.144 60.372 63.216 60.432 ;
     RECT  63.24 60.372 63.312 60.432 ;
     RECT  63.336 60.372 63.408 60.432 ;
     RECT  63.432 60.372 63.504 60.432 ;
     RECT  63.528 60.372 63.6 60.432 ;
     RECT  63.624 60.372 63.696 60.432 ;
     RECT  63.72 60.372 63.792 60.432 ;
     RECT  63.816 60.372 63.888 60.432 ;
     RECT  63.912 60.372 63.984 60.432 ;
     RECT  64.008 60.372 64.08 60.432 ;
     RECT  64.104 60.372 64.176 60.432 ;
     RECT  64.2 60.372 64.272 60.432 ;
     RECT  64.296 60.372 64.368 60.432 ;
     RECT  64.392 60.372 64.464 60.432 ;
     RECT  64.488 60.372 64.56 60.432 ;
     RECT  64.584 60.372 64.656 60.432 ;
     RECT  64.68 60.372 64.752 60.432 ;
     RECT  64.776 60.372 64.848 60.432 ;
     RECT  64.872 60.372 64.944 60.432 ;
     RECT  37.62 2.137 39.12 2.151 ;
     RECT  57.912 2.137 59.1 31.861 ;
     RECT  59.22 2.137 60.672 2.151 ;
     RECT  60.792 2.137 61.8 31.189 ;
     RECT  37.812 2.151 39.12 3.971 ;
     RECT  59.412 2.151 60.672 2.245 ;
     RECT  70.212 3.685 71.52 16.883 ;
     RECT  71.544 3.685 72.6 16.883 ;
     RECT  37.812 22.741 38.88 52.357 ;
     RECT  42.192 26.867 42.288 27.301 ;
     RECT  41.304 27.301 42.288 28.453 ;
     RECT  59.412 44.435 60.384 48.181 ;
     RECT  63.384 47.891 64.5 52.501 ;
     RECT  63.432 52.501 64.5 52.645 ;
     RECT  65.4 54.755 66.816 54.995 ;
     RECT  65.4 54.995 67.2 55.909 ;
     RECT  38.904 55.427 40.2 56.437 ;
     RECT  33.336 55.813 34.8 55.861 ;
     RECT  65.736 55.909 67.2 56.293 ;
     RECT  36.312 56.149 37.5 56.533 ;
     RECT  66.072 56.293 67.2 56.485 ;
     RECT  39.048 56.437 40.2 56.675 ;
     RECT  36.312 56.533 37.392 56.677 ;
     RECT  37.992 56.579 39.024 56.675 ;
     RECT  37.992 56.675 40.2 57.251 ;
     RECT  36.456 56.723 37.5 56.867 ;
     RECT  36.312 56.867 37.5 57.059 ;
     RECT  68.376 57.013 69.9 57.589 ;
     RECT  36.216 57.059 37.5 57.203 ;
     RECT  65.688 57.107 66.72 57.683 ;
     RECT  37.812 57.251 40.2 57.973 ;
     RECT  33.336 57.539 34.56 57.875 ;
     RECT  68.904 57.589 69.9 57.827 ;
     RECT  65.688 57.683 67.2 58.059 ;
     RECT  68.808 57.827 69.9 58.059 ;
     RECT  33.336 57.875 34.8 58.059 ;
     RECT  37.812 57.973 38.784 58.073 ;
     RECT  38.808 57.973 40.2 58.059 ;
     RECT  33.336 58.059 33.432 58.115 ;
     RECT  68.808 58.059 70.092 58.073 ;
     RECT  31.992 58.073 33.12 58.835 ;
     RECT  33.144 58.115 33.432 58.835 ;
     RECT  31.992 58.835 33.432 59.461 ;
     RECT  31.992 59.461 33.408 59.603 ;
  END
END qfd_rlyh_600_NS_104x60
END LIBRARY
